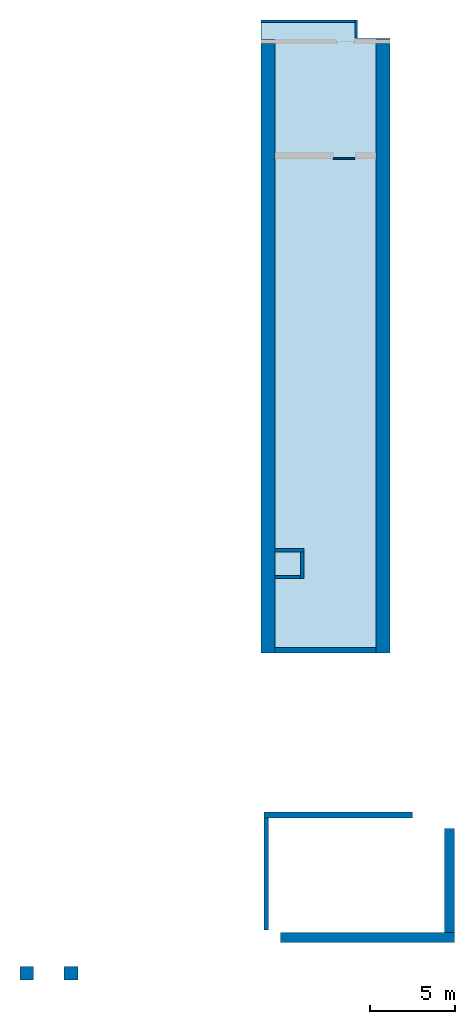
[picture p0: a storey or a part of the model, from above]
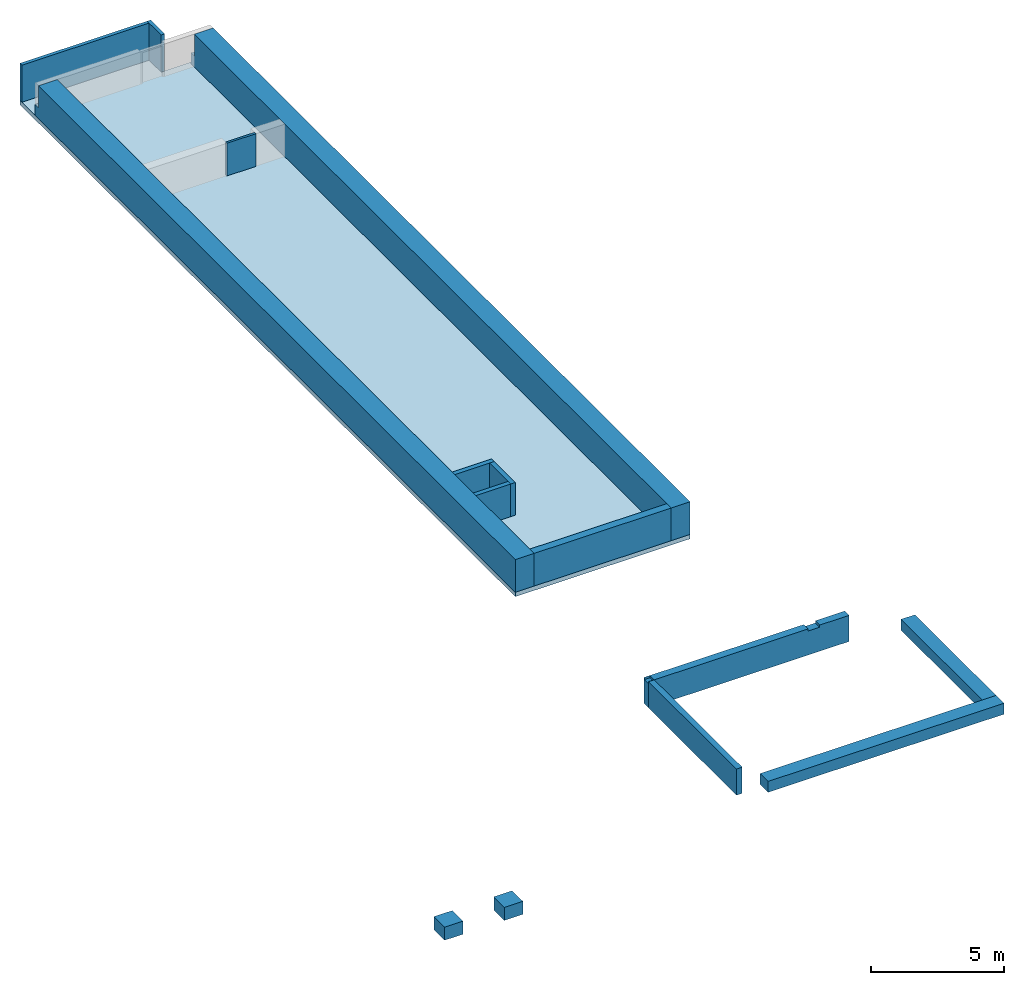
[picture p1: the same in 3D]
Properties of the parts of a building model (IFC2X3), part 1 of 7

# File
Description: ViewDefinition [, SurfaceGeometryAddOnView], Option [Elements to export: Visible elements (on all stories)], Option [Partial Structure Display: Entire Model], Option [IFC Domain: All], Option [Structural Function: All Elements], Option [Convert Grid elements: On], Option [Convert IFC Annotations and Archicad 2D elements: Off], Option [Convert 2D symbols of Doors and Windows: Off], Option [Export geometries that Participates in Collision Detection only: On], Option [Split complex elements: Off], Option [Material Preservation: Explode all], Option [IFC Model position: Survey Point and Project Origin], Option [Curtain Wall export mode: Container Element], Option [Railing export mode: Container Element], Option [Stair export mode: Container Element], Option [Properties To Export: Current Scheme properties only], Option [Space containment: Off], Option [Geometry to type objects: On], Option [Element Properties: Visible Only], Option [Building Material Properties: On], Option [Element Parameters: Off], Option [Component Parameters: Off], Option [IFC Base Quantities: Off], Option [Door Window Parameters: On], Option [IFC Space boundaries: Off], Option [Archicad Zone Categories as IFC Space classification data: Off], Option [Element Classifications: Off]
File name: C:\Users\kamee\OneDrive - Joop Petit Beheer BV\Bureaublad\Plot\IFC Bouwkiundig model.ifc
Time: 2026-01-28T16:22:37
Author: Architect
Organization: Naam bureau
Written by: DDS_IFC v3.0
Made in: Graphisoft - Archicad - 28.3.0
Authorization: The authorising person

# IfcProject, 108 Het Martin Buber
Description: Locatie Atrium gebouw N&V

# IfcSite, Site
RefLatitude: 51, 27, 0, 0; RefLongitude: 5, 29, 0, 0; RefElevation: 0 mm

# IfcBuildingStorey (11)
In: Naam gebouw
Name | Elevation (mm)
1e verdieping N | 4150
Begane grond N | 0
Fundering N | -1700
2e verdieping N | 7650
2e verdieping V | 8690
3e verdieping/dak N | 11150
3e verdieping V | 11460
4e verdieping V | 14230
5e verdieping V | 17000
6e verdieping V | 19770
7e verdieping-dak V | 22540

# IfcBeam: ALG - CONSTRUCTIEF KOLOM 150 x 250 (3)
In: 1e verdieping N
Type - PredefinedType: BEAM
Material: ALG - CONSTRUCTIEF KOLOM
Pset_BeamCommon - Slope: 0 deg; FireRating: n.v.t.; IsExternal: no; LoadBearing: yes; Reference: ALG - CONSTRUCTIEF KOLOM 150 x 250
Material Properties - ALG - CONSTRUCTIEF KOLOM, ThermalConductivity: 2.3; ALG - CONSTRUCTIEF KOLOM, SpecificHeatCapacity: 1000 J/kg/K; ALG - CONSTRUCTIEF KOLOM, MassDensity: 2300 kg/m3; ALG - CONSTRUCTIEF KOLOM, Embodied Energy: 1.92 (MJ/kg); ALG - CONSTRUCTIEF KOLOM, Embodied Carbon: 0.198 (kgCO₂/kg); ALG - CONSTRUCTIEF KOLOM, Name: ALG - CONSTRUCTIEF KOLOM; ALG - CONSTRUCTIEF KOLOM, Participates in Collision Detection: yes
CPset_Phasing - Renovation Phase: Bestaand
Name | Span (mm)
_Balk-x | 9595
_Balk-x | 28130
_Balk-x | 6885

# IfcBeam: ALG - CONSTRUCTIEF KOLOM 200 x 250, _Balk-x
In: 2e verdieping N
Type - PredefinedType: BEAM
Material: ALG - CONSTRUCTIEF KOLOM
Pset_BeamCommon - Span: 5320 mm; Slope: 0 deg; FireRating: n.v.t.; IsExternal: no; LoadBearing: yes; Reference: ALG - CONSTRUCTIEF KOLOM 200 x 250
CPset_Phasing - Renovation Phase: Bestaand
Material Properties - ALG - CONSTRUCTIEF KOLOM, ThermalConductivity: 2.3; ALG - CONSTRUCTIEF KOLOM, SpecificHeatCapacity: 1000 J/kg/K; ALG - CONSTRUCTIEF KOLOM, MassDensity: 2300 kg/m3; ALG - CONSTRUCTIEF KOLOM, Embodied Energy: 1.92 (MJ/kg); ALG - CONSTRUCTIEF KOLOM, Embodied Carbon: 0.198 (kgCO₂/kg); ALG - CONSTRUCTIEF KOLOM, Name: ALG - CONSTRUCTIEF KOLOM; ALG - CONSTRUCTIEF KOLOM, Participates in Collision Detection: yes

# IfcBeam: ALG - CONSTRUCTIEF KOLOM 250 x 200, _Balk-x
In: 2e verdieping N
Type - PredefinedType: BEAM
Material: ALG - CONSTRUCTIEF KOLOM
Pset_BeamCommon - Span: 5685 mm; Slope: 0 deg; FireRating: n.v.t.; IsExternal: no; LoadBearing: yes; Reference: ALG - CONSTRUCTIEF KOLOM 250 x 200
CPset_Phasing - Renovation Phase: Bestaand
Material Properties - ALG - CONSTRUCTIEF KOLOM, ThermalConductivity: 2.3; ALG - CONSTRUCTIEF KOLOM, SpecificHeatCapacity: 1000 J/kg/K; ALG - CONSTRUCTIEF KOLOM, MassDensity: 2300 kg/m3; ALG - CONSTRUCTIEF KOLOM, Embodied Energy: 1.92 (MJ/kg); ALG - CONSTRUCTIEF KOLOM, Embodied Carbon: 0.198 (kgCO₂/kg); ALG - CONSTRUCTIEF KOLOM, Name: ALG - CONSTRUCTIEF KOLOM; ALG - CONSTRUCTIEF KOLOM, Participates in Collision Detection: yes

# IfcBeam: ALG - CONSTRUCTIEF KOLOM 250 x 250 (8)
Type - PredefinedType: BEAM
Material: ALG - CONSTRUCTIEF KOLOM
Pset_BeamCommon - Slope: 0 deg; FireRating: n.v.t.; IsExternal: no; LoadBearing: yes; Reference: ALG - CONSTRUCTIEF KOLOM 250 x 250
CPset_Phasing - Renovation Phase: Bestaand
Material Properties - ALG - CONSTRUCTIEF KOLOM, ThermalConductivity: 2.3; ALG - CONSTRUCTIEF KOLOM, SpecificHeatCapacity: 1000 J/kg/K; ALG - CONSTRUCTIEF KOLOM, MassDensity: 2300 kg/m3; ALG - CONSTRUCTIEF KOLOM, Embodied Energy: 1.92 (MJ/kg); ALG - CONSTRUCTIEF KOLOM, Embodied Carbon: 0.198 (kgCO₂/kg); ALG - CONSTRUCTIEF KOLOM, Name: ALG - CONSTRUCTIEF KOLOM; ALG - CONSTRUCTIEF KOLOM, Participates in Collision Detection: yes
Name | In | Span (mm)
_Balk-x | 1e verdieping N | 5130
_Balk-x | 1e verdieping N | 3930
2 x _Balk-x | 1e verdieping N | 2710
_Balk-x | 1e verdieping N | 5275
_Balk-x | 1e verdieping N | 2705
_Balk-x | 1e verdieping N | 2650
_Balk-x | 2e verdieping N | 2705

# IfcBeam: ALG - CONSTRUCTIEF KOLOM 250 x 290, _Balk-x
In: 2e verdieping N
Type - PredefinedType: BEAM
Material: ALG - CONSTRUCTIEF KOLOM
Pset_BeamCommon - Span: 3930 mm; Slope: 0 deg; FireRating: n.v.t.; IsExternal: no; LoadBearing: yes; Reference: ALG - CONSTRUCTIEF KOLOM 250 x 290
CPset_Phasing - Renovation Phase: Bestaand
Material Properties - ALG - CONSTRUCTIEF KOLOM, ThermalConductivity: 2.3; ALG - CONSTRUCTIEF KOLOM, SpecificHeatCapacity: 1000 J/kg/K; ALG - CONSTRUCTIEF KOLOM, MassDensity: 2300 kg/m3; ALG - CONSTRUCTIEF KOLOM, Embodied Energy: 1.92 (MJ/kg); ALG - CONSTRUCTIEF KOLOM, Embodied Carbon: 0.198 (kgCO₂/kg); ALG - CONSTRUCTIEF KOLOM, Name: ALG - CONSTRUCTIEF KOLOM; ALG - CONSTRUCTIEF KOLOM, Participates in Collision Detection: yes

# IfcBeam: ALG - CONSTRUCTIEF KOLOM 250 x 300 (2)
In: Begane grond N
Type - PredefinedType: BEAM
Material: ALG - CONSTRUCTIEF KOLOM
Pset_BeamCommon - Span: 3873.9 mm; Slope: 0 deg; FireRating: n.v.t.; IsExternal: no; LoadBearing: yes; Reference: ALG - CONSTRUCTIEF KOLOM 250 x 300
Material Properties - ALG - CONSTRUCTIEF KOLOM, ThermalConductivity: 2.3; ALG - CONSTRUCTIEF KOLOM, SpecificHeatCapacity: 1000 J/kg/K; ALG - CONSTRUCTIEF KOLOM, MassDensity: 2300 kg/m3; ALG - CONSTRUCTIEF KOLOM, Embodied Energy: 1.92 (MJ/kg); ALG - CONSTRUCTIEF KOLOM, Embodied Carbon: 0.198 (kgCO₂/kg); ALG - CONSTRUCTIEF KOLOM, Name: ALG - CONSTRUCTIEF KOLOM; ALG - CONSTRUCTIEF KOLOM, Participates in Collision Detection: yes
CPset_Phasing - Renovation Phase: Bestaand

# IfcBeam: ALG - CONSTRUCTIEF KOLOM 250 x 350 (7)
In: Begane grond N
Type - PredefinedType: BEAM
Material: ALG - CONSTRUCTIEF KOLOM
CPset_Phasing - Renovation Phase: Bestaand
Material Properties - ALG - CONSTRUCTIEF KOLOM, ThermalConductivity: 2.3; ALG - CONSTRUCTIEF KOLOM, SpecificHeatCapacity: 1000 J/kg/K; ALG - CONSTRUCTIEF KOLOM, MassDensity: 2300 kg/m3; ALG - CONSTRUCTIEF KOLOM, Embodied Energy: 1.92 (MJ/kg); ALG - CONSTRUCTIEF KOLOM, Embodied Carbon: 0.198 (kgCO₂/kg); ALG - CONSTRUCTIEF KOLOM, Name: ALG - CONSTRUCTIEF KOLOM; ALG - CONSTRUCTIEF KOLOM, Participates in Collision Detection: yes
Pset_BeamCommon - Slope: 0 deg; FireRating: n.v.t.; IsExternal: no; LoadBearing: yes; Reference: ALG - CONSTRUCTIEF KOLOM 250 x 350
Name | Span (mm)
_Balk-x | 8932.17
2 x _Balk-x | 5
2 x _Balk-x | 2705
_Balk-x | 3820
_Balk-x | 2650

# IfcBeam: ALG - CONSTRUCTIEF KOLOM 355 x 250, _Balk-x
In: 1e verdieping N
Type - PredefinedType: BEAM
Material: ALG - CONSTRUCTIEF KOLOM
CPset_Phasing - Renovation Phase: Bestaand
Material Properties - ALG - CONSTRUCTIEF KOLOM, ThermalConductivity: 2.3; ALG - CONSTRUCTIEF KOLOM, SpecificHeatCapacity: 1000 J/kg/K; ALG - CONSTRUCTIEF KOLOM, MassDensity: 2300 kg/m3; ALG - CONSTRUCTIEF KOLOM, Embodied Energy: 1.92 (MJ/kg); ALG - CONSTRUCTIEF KOLOM, Embodied Carbon: 0.198 (kgCO₂/kg); ALG - CONSTRUCTIEF KOLOM, Name: ALG - CONSTRUCTIEF KOLOM; ALG - CONSTRUCTIEF KOLOM, Participates in Collision Detection: yes
Pset_BeamCommon - Span: 6283 mm; Slope: 0 deg; FireRating: n.v.t.; IsExternal: no; LoadBearing: yes; Reference: ALG - CONSTRUCTIEF KOLOM 355 x 250

# IfcBeam: ALG - CONSTRUCTIEF KOLOM 400 x 250 (5)
Type - PredefinedType: BEAM
Material: ALG - CONSTRUCTIEF KOLOM
Pset_BeamCommon - Slope: 0 deg; FireRating: n.v.t.; IsExternal: no; LoadBearing: yes; Reference: ALG - CONSTRUCTIEF KOLOM 400 x 250
CPset_Phasing - Renovation Phase: Bestaand
Material Properties - ALG - CONSTRUCTIEF KOLOM, ThermalConductivity: 2.3; ALG - CONSTRUCTIEF KOLOM, SpecificHeatCapacity: 1000 J/kg/K; ALG - CONSTRUCTIEF KOLOM, MassDensity: 2300 kg/m3; ALG - CONSTRUCTIEF KOLOM, Embodied Energy: 1.92 (MJ/kg); ALG - CONSTRUCTIEF KOLOM, Embodied Carbon: 0.198 (kgCO₂/kg); ALG - CONSTRUCTIEF KOLOM, Name: ALG - CONSTRUCTIEF KOLOM; ALG - CONSTRUCTIEF KOLOM, Participates in Collision Detection: yes
Name | In | Span (mm)
_Balk-x | Begane grond N | 6901.5
2 x _Balk-x | Begane grond N | 9670
_Balk-x | 1e verdieping N | 31151.2
_Balk-x | 1e verdieping N | 9700

# IfcBeam: ALG - CONSTRUCTIEF KOLOM 400 x 470 (8)
In: Begane grond N
Type - PredefinedType: BEAM
Material: ALG - CONSTRUCTIEF KOLOM
CPset_Phasing - Renovation Phase: Bestaand
Pset_BeamCommon - Slope: 0 deg; FireRating: n.v.t.; IsExternal: no; LoadBearing: yes; Reference: ALG - CONSTRUCTIEF KOLOM 400 x 470
Material Properties - ALG - CONSTRUCTIEF KOLOM, ThermalConductivity: 2.3; ALG - CONSTRUCTIEF KOLOM, SpecificHeatCapacity: 1000 J/kg/K; ALG - CONSTRUCTIEF KOLOM, MassDensity: 2300 kg/m3; ALG - CONSTRUCTIEF KOLOM, Embodied Energy: 1.92 (MJ/kg); ALG - CONSTRUCTIEF KOLOM, Embodied Carbon: 0.198 (kgCO₂/kg); ALG - CONSTRUCTIEF KOLOM, Name: ALG - CONSTRUCTIEF KOLOM; ALG - CONSTRUCTIEF KOLOM, Participates in Collision Detection: yes
Name | Span (mm)
6 x _Balk-x | 9670
_Balk-x | 40782.5
_Balk-x | 27880

# IfcBeam: ALG - CONSTRUCTIEF KOLOM 400 x 890 (9)
In: 1e verdieping N
Type - PredefinedType: BEAM
Material: ALG - CONSTRUCTIEF KOLOM
Pset_BeamCommon - Slope: 0 deg; FireRating: n.v.t.; IsExternal: no; LoadBearing: yes; Reference: ALG - CONSTRUCTIEF KOLOM 400 x 890
Material Properties - ALG - CONSTRUCTIEF KOLOM, ThermalConductivity: 2.3; ALG - CONSTRUCTIEF KOLOM, SpecificHeatCapacity: 1000 J/kg/K; ALG - CONSTRUCTIEF KOLOM, MassDensity: 2300 kg/m3; ALG - CONSTRUCTIEF KOLOM, Embodied Energy: 1.92 (MJ/kg); ALG - CONSTRUCTIEF KOLOM, Embodied Carbon: 0.198 (kgCO₂/kg); ALG - CONSTRUCTIEF KOLOM, Name: ALG - CONSTRUCTIEF KOLOM; ALG - CONSTRUCTIEF KOLOM, Participates in Collision Detection: yes
CPset_Phasing - Renovation Phase: Bestaand
Name | Span (mm)
7 x _Balk-x | 9670
2 x _Balk-x | 40427.5

# IfcBeam: L150X100X10 100 x 150 (3)
In: Begane grond N
Type - PredefinedType: BEAM
Material: Steen - Baksteen
Pset_BeamCommon - Slope: 0 deg; FireRating: n.v.t.; IsExternal: no; LoadBearing: yes; Reference: L150X100X10 100 x 150
CPset_Phasing - Renovation Phase: Nieuw
Material Properties - Steen - Baksteen, ThermalConductivity: 0.9; Steen - Baksteen, SpecificHeatCapacity: 840 J/kg/K; Steen - Baksteen, MassDensity: 1600 kg/m3; Steen - Baksteen, Embodied Energy: 3 (MJ/kg); Steen - Baksteen, Embodied Carbon: 0.23 (kgCO₂/kg); Steen - Baksteen, Name: Steen - Baksteen; Steen - Baksteen, Participates in Collision Detection: yes
Name | Span (mm)
2 x _Balk-x | 1910
_Balk-x | 3695

# IfcBeam: Lekdorpel 107 x 49 (26)
Type - PredefinedType: BEAM
Material: Metaal - Aluminium
Pset_BeamCommon - Slope: 0 deg; FireRating: n.v.t.; IsExternal: no; LoadBearing: yes; Reference: Lekdorpel 107 x 49
Material Properties - Metaal - Aluminium, ThermalConductivity: 160; Metaal - Aluminium, SpecificHeatCapacity: 880 J/kg/K; Metaal - Aluminium, MassDensity: 2800 kg/m3; Metaal - Aluminium, Embodied Energy: 155 (MJ/kg); Metaal - Aluminium, Embodied Carbon: 9.16 (kgCO₂/kg); Metaal - Aluminium, Name: Metaal - Aluminium; Metaal - Aluminium, Participates in Collision Detection: yes
Name | In | Span (mm) | Renovation Phase
2 x _Balk-x | Begane grond N | 4900 | Bestaand
_Balk-x | 1e verdieping N | 14675 | Nieuw
_Balk-x | 1e verdieping N | 18275 | Nieuw
_Balk-x | 1e verdieping N | 4460 | Bestaand
_Balk-x | 1e verdieping N | 12600 | Nieuw
_Balk-x | 2e verdieping N | 12600 | Nieuw
_Balk-x | 2e verdieping N | 3906.5 | Nieuw
_Balk-x | 2e verdieping N | 18275 | Nieuw
_Balk-x | 2e verdieping N | 16475 | Nieuw
_Balk-x | 2e verdieping N | 25200 | Nieuw
_Balk-x | 2e verdieping N | 7156.5 | Nieuw
_Balk-x | 2e verdieping N | 12738.7 | Nieuw
_Balk-x | 2e verdieping V | 5330 | Bestaand
_Balk-x | 2e verdieping V | 22661 | Bestaand
_Balk-x | 2e verdieping V | 15990 | Bestaand
_Balk-x | 2e verdieping V | 5080 | Bestaand
_Balk-x | 3e verdieping V | 5330 | Bestaand
_Balk-x | 3e verdieping V | 26650 | Bestaand
_Balk-x | 3e verdieping V | 22661 | Bestaand
_Balk-x | 4e verdieping V | 26650 | Bestaand
_Balk-x | 4e verdieping V | 5330 | Bestaand
_Balk-x | 4e verdieping V | 22661 | Bestaand
_Balk-x | 5e verdieping V | 22661 | Bestaand
_Balk-x | 5e verdieping V | 26650 | Bestaand
_Balk-x | 5e verdieping V | 5330 | Bestaand

# IfcBeam: Metaal - Staal C 10 x 100 (4)
In: 1e verdieping N
Type - PredefinedType: BEAM
Material: Metaal - Staal C
Pset_BeamCommon - FireRating: n.v.t.; IsExternal: no; LoadBearing: yes; Reference: Metaal - Staal C 10 x 100
CPset_Phasing - Renovation Phase: Nieuw
Material Properties - Metaal - Staal C, ThermalConductivity: 52; Metaal - Staal C, SpecificHeatCapacity: 530 J/kg/K; Metaal - Staal C, MassDensity: 7950 kg/m3; Metaal - Staal C, Embodied Energy: 25 (MJ/kg); Metaal - Staal C, Embodied Carbon: 1.91 (kgCO₂/kg); Metaal - Staal C, Name: Metaal - Staal C; Metaal - Staal C, Participates in Collision Detection: yes
Name | Span (mm) | Slope (deg)
2 x _Balk-x | 6507.14 | 37.1047
2 x _Balk-x | 6000.45 | 44.156

# IfcBeam: NLRS_28_SF_LIB_balk HE_generiek_ISR:balk HE_gen_HEB300 (33)
Type - PredefinedType: BEAM
Material: staal geanodiseerd RAL 7024
Pset_BeamCommon - Slope: 0 deg; Reference: balk HE_gen_HEB300; IsExternal: no; LoadBearing: yes
CPset_Phasing - Renovation Phase: Nieuw
Material Properties - staal geanodiseerd RAL 7024, ThermalConductivity: 2.3; staal geanodiseerd RAL 7024, SpecificHeatCapacity: 1000 J/kg/K; staal geanodiseerd RAL 7024, MassDensity: 2300 kg/m3; staal geanodiseerd RAL 7024, Embodied Energy: 1.92 (MJ/kg); staal geanodiseerd RAL 7024, Embodied Carbon: 0.198 (kgCO₂/kg); staal geanodiseerd RAL 7024, Name: staal geanodiseerd RAL 7024; staal geanodiseerd RAL 7024, Participates in Collision Detection: yes
Name (NLRS_28_SF_LIB_balk HE_generiek_ISR:balk HE_gen_HEB300:...) | In | Pset_ReinforcementBarPitchOfBeam, Reference | Pset_ReinforcementBarPitchOfBeam, sets with these values | Span (mm) | Group
3106919 | 2e verdieping N | balk HE_gen_HEB300 | 2 | 2833.63
3106583 | 2e verdieping N | balk HE_gen_HEB300 | 2 | 2833.63
3148283 | 2e verdieping N | balk HE_gen_HEB300 | 2 | 1544 | Model Group:luifel penthouse:3148164
3148337 | 2e verdieping N | balk HE_gen_HEB300 | 2 | 1544 | Model Group:luifel penthouse:3148164
3148282 | 2e verdieping N | balk HE_gen_HEB300 | 2 | 7380 | Model Group:luifel penthouse:3148164
2972296 | 2e verdieping V | balk HE_gen_HEB300 | 2 | 2830 | Model Group:BUITENRUIMTE helft:2972320
2973538 | 2e verdieping V | balk HE_gen_HEB300 | 2 | 2830
2972295 | 2e verdieping V | balk HE_gen_HEB300 | 2 | 7995 | Model Group:BUITENRUIMTE helft:2972320
2973612 | 2e verdieping V | balk HE_gen_HEB300 | 2 | 2830
2973856 | 2e verdieping V | balk HE_gen_HEB300 | 2 | 5240.03
3097593 | 2e verdieping V | balk HE_gen_HEB300 | 2 | 2833.63
3097884 | 2e verdieping V | balk HE_gen_HEB300 | 2 | 2833.63
3098411 | 2e verdieping V | balk HE_gen_HEB300 | 2 | 5330
2973537 | 2e verdieping V | balk HE_gen_HEB300 | 2 | 516.12
2972322 | 2e verdieping V | balk HE_gen_HEB300 | 2 | 7995 | Model Group:BUITENRUIMTE helft:2972347
2972323 | 2e verdieping V | balk HE_gen_HEB300 | 2 | 2830 | Model Group:BUITENRUIMTE helft:2972347
3108933 | 2e verdieping V |  |  | 3727.38 | Pset_QuantityTakeOff - Reference: balk HE_gen_HEB300; sets with these values: 2
2971994 | 3e verdieping/dak N |  |  | 7995 | Model Group:BUITENRUIMTE helft:2972019 | Pset_QuantityTakeOff - Reference: balk HE_gen_HEB300; sets with these values: 2
2971995 | 3e verdieping/dak N | balk HE_gen_HEB300 | 2 | 2830 | Model Group:BUITENRUIMTE helft:2972019
2972021 | 3e verdieping/dak N | balk HE_gen_HEB300 | 2 | 7995 | Model Group:BUITENRUIMTE helft:2972046
2972022 | 3e verdieping/dak N | balk HE_gen_HEB300 | 2 | 2830 | Model Group:BUITENRUIMTE helft:2972046
2972048 | 3e verdieping V | balk HE_gen_HEB300 | 2 | 7995 | Model Group:BUITENRUIMTE helft:2972073
2972075 | 3e verdieping V | balk HE_gen_HEB300 | 2 | 7995 | Model Group:BUITENRUIMTE helft:2972100
2972049 | 3e verdieping V |  |  | 2830 | Model Group:BUITENRUIMTE helft:2972073 | Pset_QuantityTakeOff - Reference: balk HE_gen_HEB300; sets with these values: 2
2972076 | 3e verdieping V | balk HE_gen_HEB300 | 2 | 2830 | Model Group:BUITENRUIMTE helft:2972100
2971941 | 4e verdieping V | balk HE_gen_HEB300 | 2 | 2830 | Model Group:BUITENRUIMTE helft:2971965
2971968 | 4e verdieping V | balk HE_gen_HEB300 | 2 | 2830 | Model Group:BUITENRUIMTE helft:2971992
2971940 | 4e verdieping V |  |  | 7995 | Model Group:BUITENRUIMTE helft:2971965 | Pset_QuantityTakeOff - Reference: balk HE_gen_HEB300; sets with these values: 2
2971967 | 4e verdieping V | balk HE_gen_HEB300 | 2 | 7995 | Model Group:BUITENRUIMTE helft:2971992
2972590 | 5e verdieping V | balk HE_gen_HEB300 | 2 | 2550 | Model Group:BUITENRUIMTE helft dak:2972614
2972589 | 5e verdieping V | balk HE_gen_HEB300 | 2 | 7995 | Model Group:BUITENRUIMTE helft dak:2972614
2972412 | 5e verdieping V | balk HE_gen_HEB300 | 2 | 7995 | Model Group:BUITENRUIMTE helft dak:2972437
2972413 | 5e verdieping V | balk HE_gen_HEB300 | 2 | 2550 | Model Group:BUITENRUIMTE helft dak:2972437

# IfcBeam: NLRS_28_SF_staal - balk - UNP:UNP300 (20)
Type - PredefinedType: BEAM
Pset_BeamCommon - Slope: 0 deg; Reference: UNP300; IsExternal: no; LoadBearing: yes
CPset_Phasing - Renovation Phase: Nieuw
Name (NLRS_28_SF_staal - balk - UNP:UNP300:...) | In | Material | Span (mm) | staal, ThermalConductivity | staal, SpecificHeatCapacity (J/kg/K) | staal, MassDensity (kg/m3) | staal, Embodied Energy | staal, Embodied Carbon | staal, Name | staal, Participates in Collision Detection | Group | Pset_ReinforcementBarPitchOfBeam, Reference | Pset_ReinforcementBarPitchOfBeam, sets with these values
3149742 | 1e verdieping N | staal | 2200 | 2.3 | 1000 | 2300 | 1.92 (MJ/kg) | 0.198 (kgCO₂/kg) | staal | yes | Model Group:KOZ-03:3140556 | Pset_QuantityTakeOff - Reference: UNP300; sets with these values: 2
2725791 | 1e verdieping N | staal | 11220 | 2.3 | 1000 | 2300 | 1.92 (MJ/kg) | 0.198 (kgCO₂/kg) | staal | yes |  | UNP300 | 2
2727269 | 1e verdieping N | staal | 6410 | 2.3 | 1000 | 2300 | 1.92 (MJ/kg) | 0.198 (kgCO₂/kg) | staal | yes |  | UNP300 | 2
2725625 | 2e verdieping N | staal | 5960 | 2.3 | 1000 | 2300 | 1.92 (MJ/kg) | 0.198 (kgCO₂/kg) | staal | yes |  | UNP300 | 2
3149748 | 2e verdieping N | staal | 2200 | 2.3 | 1000 | 2300 | 1.92 (MJ/kg) | 0.198 (kgCO₂/kg) | staal | yes | Model Group:KOZ-03:3142360 | UNP300 | 2
3149730 | 2e verdieping V | staal geanodiseerd RAL 7024 | 2200 |  |  |  |  |  |  |  | Model Group:KOZ-03:3087227 | UNP300 | 2 | Material Properties - staal geanodiseerd RAL 7024, ThermalConductivity: 2.3; staal geanodiseerd RAL 7024, SpecificHeatCapacity: 1000 J/kg/K; staal geanodiseerd RAL 7024, MassDensity: 2300 kg/m3; staal geanodiseerd RAL 7024, Embodied Energy: 1.92 (MJ/kg); staal geanodiseerd RAL 7024, Embodied Carbon: 0.198 (kgCO₂/kg); staal geanodiseerd RAL 7024, Name: staal geanodiseerd RAL 7024; staal geanodiseerd RAL 7024, Participates in Collision Detection: yes
3149745 | 2e verdieping V | staal | 2200 | 2.3 | 1000 | 2300 | 1.92 (MJ/kg) | 0.198 (kgCO₂/kg) | staal | yes | Model Group:KOZ-03:3140557 | UNP300 | 2
2725736 | 2e verdieping V | staal | 5960 | 2.3 | 1000 | 2300 | 1.92 (MJ/kg) | 0.198 (kgCO₂/kg) | staal | yes |  | UNP300 | 2
3149715 | 3e verdieping/dak N | staal geanodiseerd RAL 7024 | 2200 |  |  |  |  |  |  |  | Model Group:KOZ-03:2767540 | Pset_QuantityTakeOff - Reference: UNP300; sets with these values: 2; Material Properties - staal geanodiseerd RAL 7024, ThermalConductivity: 2.3; staal geanodiseerd RAL 7024, SpecificHeatCapacity: 1000 J/kg/K; staal geanodiseerd RAL 7024, MassDensity: 2300 kg/m3; staal geanodiseerd RAL 7024, Embodied Energy: 1.92 (MJ/kg); staal geanodiseerd RAL 7024, Embodied Carbon: 0.198 (kgCO₂/kg); staal geanodiseerd RAL 7024, Name: staal geanodiseerd RAL 7024; staal geanodiseerd RAL 7024, Participates in Collision Detection: yes
2725577 | 3e verdieping/dak N | staal | 5960 | 2.3 | 1000 | 2300 | 1.92 (MJ/kg) | 0.198 (kgCO₂/kg) | staal | yes | Model Group:V vluchttrappenhuis 2:2013401 | UNP300 | 2
3149733 | 3e verdieping/dak N | staal | 2200 | 2.3 | 1000 | 2300 | 1.92 (MJ/kg) | 0.198 (kgCO₂/kg) | staal | yes | Model Group:KOZ-03:3140528 | Pset_QuantityTakeOff - Reference: UNP300; sets with these values: 2
2725581 | 3e verdieping V | staal | 5960 | 2.3 | 1000 | 2300 | 1.92 (MJ/kg) | 0.198 (kgCO₂/kg) | staal | yes | Model Group:V vluchttrappenhuis 2:2013471 | UNP300 | 2
3149721 | 3e verdieping V | staal geanodiseerd RAL 7024 | 2200 |  |  |  |  |  |  |  | Model Group:KOZ-03:2767569 | Pset_QuantityTakeOff - Reference: UNP300; sets with these values: 2; Material Properties - staal geanodiseerd RAL 7024, ThermalConductivity: 2.3; staal geanodiseerd RAL 7024, SpecificHeatCapacity: 1000 J/kg/K; staal geanodiseerd RAL 7024, MassDensity: 2300 kg/m3; staal geanodiseerd RAL 7024, Embodied Energy: 1.92 (MJ/kg); staal geanodiseerd RAL 7024, Embodied Carbon: 0.198 (kgCO₂/kg); staal geanodiseerd RAL 7024, Name: staal geanodiseerd RAL 7024; staal geanodiseerd RAL 7024, Participates in Collision Detection: yes
3149736 | 3e verdieping V | staal | 2200 | 2.3 | 1000 | 2300 | 1.92 (MJ/kg) | 0.198 (kgCO₂/kg) | staal | yes | Model Group:KOZ-03:3140535 | Pset_QuantityTakeOff - Reference: UNP300; sets with these values: 2
3149739 | 4e verdieping V | staal | 2200 | 2.3 | 1000 | 2300 | 1.92 (MJ/kg) | 0.198 (kgCO₂/kg) | staal | yes | Model Group:KOZ-03:3140542 | UNP300 | 2
3149724 | 4e verdieping V | staal geanodiseerd RAL 7024 | 2200 |  |  |  |  |  |  |  | Model Group:KOZ-03:2767587 | Pset_QuantityTakeOff - Reference: UNP300; sets with these values: 2; Material Properties - staal geanodiseerd RAL 7024, ThermalConductivity: 2.3; staal geanodiseerd RAL 7024, SpecificHeatCapacity: 1000 J/kg/K; staal geanodiseerd RAL 7024, MassDensity: 2300 kg/m3; staal geanodiseerd RAL 7024, Embodied Energy: 1.92 (MJ/kg); staal geanodiseerd RAL 7024, Embodied Carbon: 0.198 (kgCO₂/kg); staal geanodiseerd RAL 7024, Name: staal geanodiseerd RAL 7024; staal geanodiseerd RAL 7024, Participates in Collision Detection: yes
2725293 | 4e verdieping V | staal | 5960 | 2.3 | 1000 | 2300 | 1.92 (MJ/kg) | 0.198 (kgCO₂/kg) | staal | yes | Model Group:V vluchttrappenhuis 2:2013517 | UNP300 | 2
3149419 | 5e verdieping V | staal | 2200 | 2.3 | 1000 | 2300 | 1.92 (MJ/kg) | 0.198 (kgCO₂/kg) | staal | yes | Model Group:KOZ-03:3140549 | UNP300 | 2
3149727 | 5e verdieping V | staal geanodiseerd RAL 7024 | 2200 |  |  |  |  |  |  |  | Model Group:KOZ-03:2767621 | UNP300 | 2 | Material Properties - staal geanodiseerd RAL 7024, ThermalConductivity: 2.3; staal geanodiseerd RAL 7024, SpecificHeatCapacity: 1000 J/kg/K; staal geanodiseerd RAL 7024, MassDensity: 2300 kg/m3; staal geanodiseerd RAL 7024, Embodied Energy: 1.92 (MJ/kg); staal geanodiseerd RAL 7024, Embodied Carbon: 0.198 (kgCO₂/kg); staal geanodiseerd RAL 7024, Name: staal geanodiseerd RAL 7024; staal geanodiseerd RAL 7024, Participates in Collision Detection: yes
3085542 | 5e verdieping V | staal | 5960 | 2.3 | 1000 | 2300 | 1.92 (MJ/kg) | 0.198 (kgCO₂/kg) | staal | yes | Model Group:V vluchttrappenhuis 2:2013112 | Pset_QuantityTakeOff - Reference: UNP300; sets with these values: 2

# IfcBeam: Onderdorpel 155 x 80 (8)
In: Begane grond N
Type - PredefinedType: BEAM
Material: Beton gewapend prefab
Pset_BeamCommon - Span: 275 mm; Slope: 0 deg; FireRating: n.v.t.; IsExternal: no; LoadBearing: yes; Reference: Onderdorpel 155 x 80
CPset_Phasing - Renovation Phase: Nieuw
Material Properties - Beton gewapend prefab, ThermalConductivity: 2.5; Beton gewapend prefab, SpecificHeatCapacity: 1000 J/kg/K; Beton gewapend prefab, MassDensity: 2400 kg/m3; Beton gewapend prefab, Embodied Energy: 2.33 (MJ/kg); Beton gewapend prefab, Embodied Carbon: 0.242 (kgCO₂/kg); Beton gewapend prefab, Name: Beton gewapend prefab; Beton gewapend prefab, Participates in Collision Detection: yes

# IfcBuildingElementPart (1450)
Name | In | Material | Renovation Phase
101 x Isolatie - Steenwol LSW | Begane grond N | Isolatie - Steenwol LSW | Nieuw | Material Properties - Isolatie - Steenwol LSW, ThermalConductivity: 0.039; Isolatie - Steenwol LSW, SpecificHeatCapacity: 840 J/kg/K; Isolatie - Steenwol LSW, MassDensity: 55 kg/m3; Isolatie - Steenwol LSW, Embodied Energy: 16.8 (MJ/kg); Isolatie - Steenwol LSW, Embodied Carbon: 1.05 (kgCO₂/kg); Isolatie - Steenwol LSW, Name: Isolatie - Steenwol LSW; Isolatie - Steenwol LSW, Participates in Collision Detection: yes
207 x Gipsplaat | Begane grond N | Gipsplaat | Nieuw | Material Properties - Gipsplaat, ThermalConductivity: 0.23; Gipsplaat, SpecificHeatCapacity: 840 J/kg/K; Gipsplaat, MassDensity: 800 kg/m3; Gipsplaat, Embodied Energy: 6.75 (MJ/kg); Gipsplaat, Embodied Carbon: 0.38 (kgCO₂/kg); Gipsplaat, Name: Gipsplaat; Gipsplaat, Participates in Collision Detection: yes
4 x Hout - Multiplex | Begane grond N | Hout - Multiplex | Nieuw | Material Properties - Hout - Multiplex, ThermalConductivity: 0.17; Hout - Multiplex, SpecificHeatCapacity: 1600 J/kg/K; Hout - Multiplex, MassDensity: 700 kg/m3; Hout - Multiplex, Embodied Energy: 15 (MJ/kg); Hout - Multiplex, Embodied Carbon: 0.77 (kgCO₂/kg); Hout - Multiplex, Name: Hout - Multiplex; Hout - Multiplex, Participates in Collision Detection: yes
10 x Isolatie - Kunststof hard | Begane grond N | Isolatie - Kunststof hard | Nieuw | Material Properties - Isolatie - Kunststof hard, ThermalConductivity: 0.029; Isolatie - Kunststof hard, SpecificHeatCapacity: 1470 J/kg/K; Isolatie - Kunststof hard, MassDensity: 100 kg/m3; Isolatie - Kunststof hard, Embodied Energy: 101.5 (MJ/kg); Isolatie - Kunststof hard, Embodied Carbon: 3.48 (kgCO₂/kg); Isolatie - Kunststof hard, Name: Isolatie - Kunststof hard; Isolatie - Kunststof hard, Participates in Collision Detection: yes
2 x Metaal - Aluminium | Begane grond N | Metaal - Aluminium | Nieuw | Material Properties - Metaal - Aluminium, ThermalConductivity: 160; Metaal - Aluminium, SpecificHeatCapacity: 880 J/kg/K; Metaal - Aluminium, MassDensity: 2800 kg/m3; Metaal - Aluminium, Embodied Energy: 155 (MJ/kg); Metaal - Aluminium, Embodied Carbon: 9.16 (kgCO₂/kg); Metaal - Aluminium, Name: Metaal - Aluminium; Metaal - Aluminium, Participates in Collision Detection: yes
7 x stucwerk | Begane grond N | stucwerk | Nieuw | Material Properties - stucwerk, ThermalConductivity: 2.3; stucwerk, SpecificHeatCapacity: 1000 J/kg/K; stucwerk, MassDensity: 2300 kg/m3; stucwerk, Embodied Energy: 1.92 (MJ/kg); stucwerk, Embodied Carbon: 0.198 (kgCO₂/kg); stucwerk, Name: stucwerk; stucwerk, Participates in Collision Detection: yes
Cement | Begane grond N | Cement | Nieuw | Material Properties - Cement, ThermalConductivity: 0.93; Cement, SpecificHeatCapacity: 840 J/kg/K; Cement, MassDensity: 1900 kg/m3; Cement, Embodied Energy: 0.97 (MJ/kg); Cement, Embodied Carbon: 0.146 (kgCO₂/kg); Cement, Name: Cement; Cement, Participates in Collision Detection: yes
Beton gewapend C vloer | Begane grond N | Beton gewapend C vloer | Nieuw | Material Properties - Beton gewapend C vloer, ThermalConductivity: 2.5; Beton gewapend C vloer, SpecificHeatCapacity: 1000 J/kg/K; Beton gewapend C vloer, MassDensity: 2400 kg/m3; Beton gewapend C vloer, Embodied Energy: 2.33 (MJ/kg); Beton gewapend C vloer, Embodied Carbon: 0.242 (kgCO₂/kg); Beton gewapend C vloer, Name: Beton gewapend C vloer; Beton gewapend C vloer, Participates in Collision Detection: yes
2 x Steen - Betonblok | Begane grond N | Steen - Betonblok | Nieuw | Material Properties - Steen - Betonblok, ThermalConductivity: 0.4; Steen - Betonblok, SpecificHeatCapacity: 840 J/kg/K; Steen - Betonblok, MassDensity: 800 kg/m3; Steen - Betonblok, Embodied Energy: 0.59 (MJ/kg); Steen - Betonblok, Embodied Carbon: 0.059 (kgCO₂/kg); Steen - Betonblok, Name: Steen - Betonblok; Steen - Betonblok, Participates in Collision Detection: yes
2 x Isolatie - Steenwol zacht | Begane grond N | Isolatie - Steenwol zacht | Nieuw | Material Properties - Isolatie - Steenwol zacht, ThermalConductivity: 0.035; Isolatie - Steenwol zacht, SpecificHeatCapacity: 840 J/kg/K; Isolatie - Steenwol zacht, MassDensity: 45 kg/m3; Isolatie - Steenwol zacht, Embodied Energy: 16.8 (MJ/kg); Isolatie - Steenwol zacht, Embodied Carbon: 1.05 (kgCO₂/kg); Isolatie - Steenwol zacht, Name: Isolatie - Steenwol zacht; Isolatie - Steenwol zacht, Participates in Collision Detection: yes
2 x Steen - Baksteen AFW | Begane grond N | Steen - Baksteen AFW | Nieuw | Material Properties - Steen - Baksteen AFW, ThermalConductivity: 0.9; Steen - Baksteen AFW, SpecificHeatCapacity: 840 J/kg/K; Steen - Baksteen AFW, MassDensity: 1600 kg/m3; Steen - Baksteen AFW, Embodied Energy: 3 (MJ/kg); Steen - Baksteen AFW, Embodied Carbon: 0.23 (kgCO₂/kg); Steen - Baksteen AFW, Name: Steen - Baksteen AFW; Steen - Baksteen AFW, Participates in Collision Detection: yes
104 x Isolatie - Steenwol LSW | 1e verdieping N | Isolatie - Steenwol LSW | Nieuw | Material Properties - Isolatie - Steenwol LSW, ThermalConductivity: 0.039; Isolatie - Steenwol LSW, SpecificHeatCapacity: 840 J/kg/K; Isolatie - Steenwol LSW, MassDensity: 55 kg/m3; Isolatie - Steenwol LSW, Embodied Energy: 16.8 (MJ/kg); Isolatie - Steenwol LSW, Embodied Carbon: 1.05 (kgCO₂/kg); Isolatie - Steenwol LSW, Name: Isolatie - Steenwol LSW; Isolatie - Steenwol LSW, Participates in Collision Detection: yes
206 x Gipsplaat | 1e verdieping N | Gipsplaat | Nieuw | Material Properties - Gipsplaat, ThermalConductivity: 0.23; Gipsplaat, SpecificHeatCapacity: 840 J/kg/K; Gipsplaat, MassDensity: 800 kg/m3; Gipsplaat, Embodied Energy: 6.75 (MJ/kg); Gipsplaat, Embodied Carbon: 0.38 (kgCO₂/kg); Gipsplaat, Name: Gipsplaat; Gipsplaat, Participates in Collision Detection: yes
10 x isolatie_080_1-100 | 1e verdieping N | isolatie_080_1-100 | Nieuw | Material Properties - isolatie_080_1-100, ThermalConductivity: 2.3; isolatie_080_1-100, SpecificHeatCapacity: 1000 J/kg/K; isolatie_080_1-100, MassDensity: 2300 kg/m3; isolatie_080_1-100, Embodied Energy: 1.92 (MJ/kg); isolatie_080_1-100, Embodied Carbon: 0.198 (kgCO₂/kg); isolatie_080_1-100, Name: isolatie_080_1-100; isolatie_080_1-100, Participates in Collision Detection: yes
10 x stucwerk - gevel gebouw V RAL 7044 | 1e verdieping N | stucwerk - gevel gebouw V RAL 7044 | Nieuw | Material Properties - stucwerk - gevel gebouw V RAL 7044, ThermalConductivity: 2.3; stucwerk - gevel gebouw V RAL 7044, SpecificHeatCapacity: 1000 J/kg/K; stucwerk - gevel gebouw V RAL 7044, MassDensity: 2300 kg/m3; stucwerk - gevel gebouw V RAL 7044, Embodied Energy: 1.92 (MJ/kg); stucwerk - gevel gebouw V RAL 7044, Embodied Carbon: 0.198 (kgCO₂/kg); stucwerk - gevel gebouw V RAL 7044, Name: stucwerk - gevel gebouw V RAL 7044; stucwerk - gevel gebouw V RAL 7044, Participates in Collision Detection: yes
10 x Verflaag ral 7044 Zijdengrijs Isostuc | 1e verdieping N | Verflaag ral 7044 Zijdengrijs Isostuc | Nieuw | Material Properties - Verflaag ral 7044 Zijdengrijs Isostuc, ThermalConductivity: 2.3; Verflaag ral 7044 Zijdengrijs Isostuc, SpecificHeatCapacity: 1000 J/kg/K; Verflaag ral 7044 Zijdengrijs Isostuc, MassDensity: 2300 kg/m3; Verflaag ral 7044 Zijdengrijs Isostuc, Embodied Energy: 1.92 (MJ/kg); Verflaag ral 7044 Zijdengrijs Isostuc, Embodied Carbon: 0.198 (kgCO₂/kg); Verflaag ral 7044 Zijdengrijs Isostuc, Name: Verflaag ral 7044 Zijdengrijs Isostuc; Verflaag ral 7044 Zijdengrijs Isostuc, Participates in Collision Detection: yes
isolatie | 1e verdieping N | isolatie | Nieuw | Material Properties - isolatie, ThermalConductivity: 2.3; isolatie, SpecificHeatCapacity: 1000 J/kg/K; isolatie, MassDensity: 2300 kg/m3; isolatie, Embodied Energy: 1.92 (MJ/kg); isolatie, Embodied Carbon: 0.198 (kgCO₂/kg); isolatie, Name: isolatie; isolatie, Participates in Collision Detection: yes
2 x luchtspouw | 1e verdieping N | luchtspouw | Nieuw | Material Properties - luchtspouw, ThermalConductivity: 2.3; luchtspouw, SpecificHeatCapacity: 1000 J/kg/K; luchtspouw, MassDensity: 2300 kg/m3; luchtspouw, Embodied Energy: 1.92 (MJ/kg); luchtspouw, Embodied Carbon: 0.198 (kgCO₂/kg); luchtspouw, Name: luchtspouw; luchtspouw, Participates in Collision Detection: yes
Houten delen vert | 1e verdieping N | Houten delen vert | Nieuw | Material Properties - Houten delen vert, ThermalConductivity: 2.3; Houten delen vert, SpecificHeatCapacity: 1000 J/kg/K; Houten delen vert, MassDensity: 2300 kg/m3; Houten delen vert, Embodied Energy: 1.92 (MJ/kg); Houten delen vert, Embodied Carbon: 0.198 (kgCO₂/kg); Houten delen vert, Name: Houten delen vert; Houten delen vert, Participates in Collision Detection: yes
4 x Gipsplaat | 1e verdieping N | Gipsplaat | Bestaand | Material Properties - Gipsplaat, ThermalConductivity: 0.23; Gipsplaat, SpecificHeatCapacity: 840 J/kg/K; Gipsplaat, MassDensity: 800 kg/m3; Gipsplaat, Embodied Energy: 6.75 (MJ/kg); Gipsplaat, Embodied Carbon: 0.38 (kgCO₂/kg); Gipsplaat, Name: Gipsplaat; Gipsplaat, Participates in Collision Detection: yes
2 x Isolatie - Steenwol LSW | 1e verdieping N | Isolatie - Steenwol LSW | Bestaand | Material Properties - Isolatie - Steenwol LSW, ThermalConductivity: 0.039; Isolatie - Steenwol LSW, SpecificHeatCapacity: 840 J/kg/K; Isolatie - Steenwol LSW, MassDensity: 55 kg/m3; Isolatie - Steenwol LSW, Embodied Energy: 16.8 (MJ/kg); Isolatie - Steenwol LSW, Embodied Carbon: 1.05 (kgCO₂/kg); Isolatie - Steenwol LSW, Name: Isolatie - Steenwol LSW; Isolatie - Steenwol LSW, Participates in Collision Detection: yes
160 x Gipsplaat | 2e verdieping N | Gipsplaat | Nieuw | Material Properties - Gipsplaat, ThermalConductivity: 0.23; Gipsplaat, SpecificHeatCapacity: 840 J/kg/K; Gipsplaat, MassDensity: 800 kg/m3; Gipsplaat, Embodied Energy: 6.75 (MJ/kg); Gipsplaat, Embodied Carbon: 0.38 (kgCO₂/kg); Gipsplaat, Name: Gipsplaat; Gipsplaat, Participates in Collision Detection: yes
80 x Isolatie - Steenwol LSW | 2e verdieping N | Isolatie - Steenwol LSW | Nieuw | Material Properties - Isolatie - Steenwol LSW, ThermalConductivity: 0.039; Isolatie - Steenwol LSW, SpecificHeatCapacity: 840 J/kg/K; Isolatie - Steenwol LSW, MassDensity: 55 kg/m3; Isolatie - Steenwol LSW, Embodied Energy: 16.8 (MJ/kg); Isolatie - Steenwol LSW, Embodied Carbon: 1.05 (kgCO₂/kg); Isolatie - Steenwol LSW, Name: Isolatie - Steenwol LSW; Isolatie - Steenwol LSW, Participates in Collision Detection: yes
6 x Verflaag ral 7044 Zijdengrijs Isostuc | 2e verdieping N | Verflaag ral 7044 Zijdengrijs Isostuc | Nieuw | Material Properties - Verflaag ral 7044 Zijdengrijs Isostuc, ThermalConductivity: 2.3; Verflaag ral 7044 Zijdengrijs Isostuc, SpecificHeatCapacity: 1000 J/kg/K; Verflaag ral 7044 Zijdengrijs Isostuc, MassDensity: 2300 kg/m3; Verflaag ral 7044 Zijdengrijs Isostuc, Embodied Energy: 1.92 (MJ/kg); Verflaag ral 7044 Zijdengrijs Isostuc, Embodied Carbon: 0.198 (kgCO₂/kg); Verflaag ral 7044 Zijdengrijs Isostuc, Name: Verflaag ral 7044 Zijdengrijs Isostuc; Verflaag ral 7044 Zijdengrijs Isostuc, Participates in Collision Detection: yes
6 x stucwerk - gevel gebouw V RAL 7044 | 2e verdieping N | stucwerk - gevel gebouw V RAL 7044 | Nieuw | Material Properties - stucwerk - gevel gebouw V RAL 7044, ThermalConductivity: 2.3; stucwerk - gevel gebouw V RAL 7044, SpecificHeatCapacity: 1000 J/kg/K; stucwerk - gevel gebouw V RAL 7044, MassDensity: 2300 kg/m3; stucwerk - gevel gebouw V RAL 7044, Embodied Energy: 1.92 (MJ/kg); stucwerk - gevel gebouw V RAL 7044, Embodied Carbon: 0.198 (kgCO₂/kg); stucwerk - gevel gebouw V RAL 7044, Name: stucwerk - gevel gebouw V RAL 7044; stucwerk - gevel gebouw V RAL 7044, Participates in Collision Detection: yes
26 x isolatie_080_1-100 | 2e verdieping N | isolatie_080_1-100 | Nieuw | Material Properties - isolatie_080_1-100, ThermalConductivity: 2.3; isolatie_080_1-100, SpecificHeatCapacity: 1000 J/kg/K; isolatie_080_1-100, MassDensity: 2300 kg/m3; isolatie_080_1-100, Embodied Energy: 1.92 (MJ/kg); isolatie_080_1-100, Embodied Carbon: 0.198 (kgCO₂/kg); isolatie_080_1-100, Name: isolatie_080_1-100; isolatie_080_1-100, Participates in Collision Detection: yes
40 x Aluminum geanodiseerd RAL 7024 | 2e verdieping N | Aluminum geanodiseerd RAL 7024 | Nieuw | Material Properties - Aluminum geanodiseerd RAL 7024, ThermalConductivity: 2.3; Aluminum geanodiseerd RAL 7024, SpecificHeatCapacity: 1000 J/kg/K; Aluminum geanodiseerd RAL 7024, MassDensity: 2300 kg/m3; Aluminum geanodiseerd RAL 7024, Embodied Energy: 1.92 (MJ/kg); Aluminum geanodiseerd RAL 7024, Embodied Carbon: 0.198 (kgCO₂/kg); Aluminum geanodiseerd RAL 7024, Name: Aluminum geanodiseerd RAL 7024; Aluminum geanodiseerd RAL 7024, Participates in Collision Detection: yes
4 x Hout - Multiplex | 2e verdieping N | Hout - Multiplex | Nieuw | Material Properties - Hout - Multiplex, ThermalConductivity: 0.17; Hout - Multiplex, SpecificHeatCapacity: 1600 J/kg/K; Hout - Multiplex, MassDensity: 700 kg/m3; Hout - Multiplex, Embodied Energy: 15 (MJ/kg); Hout - Multiplex, Embodied Carbon: 0.77 (kgCO₂/kg); Hout - Multiplex, Name: Hout - Multiplex; Hout - Multiplex, Participates in Collision Detection: yes
2 x Isolatie - Steenwol zacht | 2e verdieping N | Isolatie - Steenwol zacht | Nieuw | Material Properties - Isolatie - Steenwol zacht, ThermalConductivity: 0.035; Isolatie - Steenwol zacht, SpecificHeatCapacity: 840 J/kg/K; Isolatie - Steenwol zacht, MassDensity: 45 kg/m3; Isolatie - Steenwol zacht, Embodied Energy: 16.8 (MJ/kg); Isolatie - Steenwol zacht, Embodied Carbon: 1.05 (kgCO₂/kg); Isolatie - Steenwol zacht, Name: Isolatie - Steenwol zacht; Isolatie - Steenwol zacht, Participates in Collision Detection: yes
2 x Metaal - Staal AFW | 2e verdieping N | Metaal - Staal AFW | Nieuw | Material Properties - Metaal - Staal AFW, ThermalConductivity: 52; Metaal - Staal AFW, SpecificHeatCapacity: 530 J/kg/K; Metaal - Staal AFW, MassDensity: 7950 kg/m3; Metaal - Staal AFW, Embodied Energy: 25 (MJ/kg); Metaal - Staal AFW, Embodied Carbon: 1.91 (kgCO₂/kg); Metaal - Staal AFW, Name: Metaal - Staal AFW; Metaal - Staal AFW, Participates in Collision Detection: yes
Bestaand metselwerk | 2e verdieping N | Bestaand metselwerk | Nieuw | Material Properties - Bestaand metselwerk, ThermalConductivity: 2.3; Bestaand metselwerk, SpecificHeatCapacity: 1000 J/kg/K; Bestaand metselwerk, MassDensity: 2300 kg/m3; Bestaand metselwerk, Embodied Energy: 1.92 (MJ/kg); Bestaand metselwerk, Embodied Carbon: 0.198 (kgCO₂/kg); Bestaand metselwerk, Name: Bestaand metselwerk; Bestaand metselwerk, Participates in Collision Detection: yes
4 x stucwerk | 2e verdieping N | stucwerk | Nieuw | Material Properties - stucwerk, ThermalConductivity: 2.3; stucwerk, SpecificHeatCapacity: 1000 J/kg/K; stucwerk, MassDensity: 2300 kg/m3; stucwerk, Embodied Energy: 1.92 (MJ/kg); stucwerk, Embodied Carbon: 0.198 (kgCO₂/kg); stucwerk, Name: stucwerk; stucwerk, Participates in Collision Detection: yes
2 x metselwerk | 2e verdieping N | metselwerk | Nieuw | Material Properties - metselwerk, ThermalConductivity: 2.3; metselwerk, SpecificHeatCapacity: 1000 J/kg/K; metselwerk, MassDensity: 2300 kg/m3; metselwerk, Embodied Energy: 1.92 (MJ/kg); metselwerk, Embodied Carbon: 0.198 (kgCO₂/kg); metselwerk, Name: metselwerk; metselwerk, Participates in Collision Detection: yes
11 x luchtspouw | 2e verdieping N | luchtspouw | Nieuw | Material Properties - luchtspouw, ThermalConductivity: 2.3; luchtspouw, SpecificHeatCapacity: 1000 J/kg/K; luchtspouw, MassDensity: 2300 kg/m3; luchtspouw, Embodied Energy: 1.92 (MJ/kg); luchtspouw, Embodied Carbon: 0.198 (kgCO₂/kg); luchtspouw, Name: luchtspouw; luchtspouw, Participates in Collision Detection: yes
5 x Houten delen vert | 2e verdieping N | Houten delen vert | Nieuw | Material Properties - Houten delen vert, ThermalConductivity: 2.3; Houten delen vert, SpecificHeatCapacity: 1000 J/kg/K; Houten delen vert, MassDensity: 2300 kg/m3; Houten delen vert, Embodied Energy: 1.92 (MJ/kg); Houten delen vert, Embodied Carbon: 0.198 (kgCO₂/kg); Houten delen vert, Name: Houten delen vert; Houten delen vert, Participates in Collision Detection: yes
4 x isolatie | 2e verdieping N | isolatie | Nieuw | Material Properties - isolatie, ThermalConductivity: 2.3; isolatie, SpecificHeatCapacity: 1000 J/kg/K; isolatie, MassDensity: 2300 kg/m3; isolatie, Embodied Energy: 1.92 (MJ/kg); isolatie, Embodied Carbon: 0.198 (kgCO₂/kg); isolatie, Name: isolatie; isolatie, Participates in Collision Detection: yes
2 x Multiplex | 2e verdieping N | Multiplex | Nieuw | Material Properties - Multiplex, ThermalConductivity: 2.3; Multiplex, SpecificHeatCapacity: 1000 J/kg/K; Multiplex, MassDensity: 2300 kg/m3; Multiplex, Embodied Energy: 1.92 (MJ/kg); Multiplex, Embodied Carbon: 0.198 (kgCO₂/kg); Multiplex, Name: Multiplex; Multiplex, Participates in Collision Detection: yes
Oriented Strand Board | 2e verdieping N | Oriented Strand Board | Nieuw | Material Properties - Oriented Strand Board, ThermalConductivity: 2.3; Oriented Strand Board, SpecificHeatCapacity: 1000 J/kg/K; Oriented Strand Board, MassDensity: 2300 kg/m3; Oriented Strand Board, Embodied Energy: 1.92 (MJ/kg); Oriented Strand Board, Embodied Carbon: 0.198 (kgCO₂/kg); Oriented Strand Board, Name: Oriented Strand Board; Oriented Strand Board, Participates in Collision Detection: yes
4 x isolatie_080_1-100 | 2e verdieping V | isolatie_080_1-100 | Nieuw | Material Properties - isolatie_080_1-100, ThermalConductivity: 2.3; isolatie_080_1-100, SpecificHeatCapacity: 1000 J/kg/K; isolatie_080_1-100, MassDensity: 2300 kg/m3; isolatie_080_1-100, Embodied Energy: 1.92 (MJ/kg); isolatie_080_1-100, Embodied Carbon: 0.198 (kgCO₂/kg); isolatie_080_1-100, Name: isolatie_080_1-100; isolatie_080_1-100, Participates in Collision Detection: yes
4 x stucwerk - gevel gebouw V RAL 7044 | 2e verdieping V | stucwerk - gevel gebouw V RAL 7044 | Nieuw | Material Properties - stucwerk - gevel gebouw V RAL 7044, ThermalConductivity: 2.3; stucwerk - gevel gebouw V RAL 7044, SpecificHeatCapacity: 1000 J/kg/K; stucwerk - gevel gebouw V RAL 7044, MassDensity: 2300 kg/m3; stucwerk - gevel gebouw V RAL 7044, Embodied Energy: 1.92 (MJ/kg); stucwerk - gevel gebouw V RAL 7044, Embodied Carbon: 0.198 (kgCO₂/kg); stucwerk - gevel gebouw V RAL 7044, Name: stucwerk - gevel gebouw V RAL 7044; stucwerk - gevel gebouw V RAL 7044, Participates in Collision Detection: yes
2 x luchtspouw | 2e verdieping V | luchtspouw | Nieuw | Material Properties - luchtspouw, ThermalConductivity: 2.3; luchtspouw, SpecificHeatCapacity: 1000 J/kg/K; luchtspouw, MassDensity: 2300 kg/m3; luchtspouw, Embodied Energy: 1.92 (MJ/kg); luchtspouw, Embodied Carbon: 0.198 (kgCO₂/kg); luchtspouw, Name: luchtspouw; luchtspouw, Participates in Collision Detection: yes
4 x Verflaag ral 7044 Zijdengrijs Isostuc | 2e verdieping V | Verflaag ral 7044 Zijdengrijs Isostuc | Nieuw | Material Properties - Verflaag ral 7044 Zijdengrijs Isostuc, ThermalConductivity: 2.3; Verflaag ral 7044 Zijdengrijs Isostuc, SpecificHeatCapacity: 1000 J/kg/K; Verflaag ral 7044 Zijdengrijs Isostuc, MassDensity: 2300 kg/m3; Verflaag ral 7044 Zijdengrijs Isostuc, Embodied Energy: 1.92 (MJ/kg); Verflaag ral 7044 Zijdengrijs Isostuc, Embodied Carbon: 0.198 (kgCO₂/kg); Verflaag ral 7044 Zijdengrijs Isostuc, Name: Verflaag ral 7044 Zijdengrijs Isostuc; Verflaag ral 7044 Zijdengrijs Isostuc, Participates in Collision Detection: yes
Houten delen vert | 2e verdieping V | Houten delen vert | Nieuw | Material Properties - Houten delen vert, ThermalConductivity: 2.3; Houten delen vert, SpecificHeatCapacity: 1000 J/kg/K; Houten delen vert, MassDensity: 2300 kg/m3; Houten delen vert, Embodied Energy: 1.92 (MJ/kg); Houten delen vert, Embodied Carbon: 0.198 (kgCO₂/kg); Houten delen vert, Name: Houten delen vert; Houten delen vert, Participates in Collision Detection: yes
isolatie | 2e verdieping V | isolatie | Nieuw | Material Properties - isolatie, ThermalConductivity: 2.3; isolatie, SpecificHeatCapacity: 1000 J/kg/K; isolatie, MassDensity: 2300 kg/m3; isolatie, Embodied Energy: 1.92 (MJ/kg); isolatie, Embodied Carbon: 0.198 (kgCO₂/kg); isolatie, Name: isolatie; isolatie, Participates in Collision Detection: yes
Metaal - Staal AFW | 2e verdieping V | Metaal - Staal AFW | Nieuw | Material Properties - Metaal - Staal AFW, ThermalConductivity: 52; Metaal - Staal AFW, SpecificHeatCapacity: 530 J/kg/K; Metaal - Staal AFW, MassDensity: 7950 kg/m3; Metaal - Staal AFW, Embodied Energy: 25 (MJ/kg); Metaal - Staal AFW, Embodied Carbon: 1.91 (kgCO₂/kg); Metaal - Staal AFW, Name: Metaal - Staal AFW; Metaal - Staal AFW, Participates in Collision Detection: yes
Isolatie - Steenwol zacht | 2e verdieping V | Isolatie - Steenwol zacht | Nieuw | Material Properties - Isolatie - Steenwol zacht, ThermalConductivity: 0.035; Isolatie - Steenwol zacht, SpecificHeatCapacity: 840 J/kg/K; Isolatie - Steenwol zacht, MassDensity: 45 kg/m3; Isolatie - Steenwol zacht, Embodied Energy: 16.8 (MJ/kg); Isolatie - Steenwol zacht, Embodied Carbon: 1.05 (kgCO₂/kg); Isolatie - Steenwol zacht, Name: Isolatie - Steenwol zacht; Isolatie - Steenwol zacht, Participates in Collision Detection: yes
Hout - Multiplex | 2e verdieping V | Hout - Multiplex | Nieuw | Material Properties - Hout - Multiplex, ThermalConductivity: 0.17; Hout - Multiplex, SpecificHeatCapacity: 1600 J/kg/K; Hout - Multiplex, MassDensity: 700 kg/m3; Hout - Multiplex, Embodied Energy: 15 (MJ/kg); Hout - Multiplex, Embodied Carbon: 0.77 (kgCO₂/kg); Hout - Multiplex, Name: Hout - Multiplex; Hout - Multiplex, Participates in Collision Detection: yes
Gipsplaat | 2e verdieping V | Gipsplaat | Nieuw | Material Properties - Gipsplaat, ThermalConductivity: 0.23; Gipsplaat, SpecificHeatCapacity: 840 J/kg/K; Gipsplaat, MassDensity: 800 kg/m3; Gipsplaat, Embodied Energy: 6.75 (MJ/kg); Gipsplaat, Embodied Carbon: 0.38 (kgCO₂/kg); Gipsplaat, Name: Gipsplaat; Gipsplaat, Participates in Collision Detection: yes
4 x Verflaag ral 7044 Zijdengrijs Isostuc | 3e verdieping/dak N | Verflaag ral 7044 Zijdengrijs Isostuc | Nieuw | Material Properties - Verflaag ral 7044 Zijdengrijs Isostuc, ThermalConductivity: 2.3; Verflaag ral 7044 Zijdengrijs Isostuc, SpecificHeatCapacity: 1000 J/kg/K; Verflaag ral 7044 Zijdengrijs Isostuc, MassDensity: 2300 kg/m3; Verflaag ral 7044 Zijdengrijs Isostuc, Embodied Energy: 1.92 (MJ/kg); Verflaag ral 7044 Zijdengrijs Isostuc, Embodied Carbon: 0.198 (kgCO₂/kg); Verflaag ral 7044 Zijdengrijs Isostuc, Name: Verflaag ral 7044 Zijdengrijs Isostuc; Verflaag ral 7044 Zijdengrijs Isostuc, Participates in Collision Detection: yes
4 x isolatie_080_1-100 | 3e verdieping/dak N | isolatie_080_1-100 | Nieuw | Material Properties - isolatie_080_1-100, ThermalConductivity: 2.3; isolatie_080_1-100, SpecificHeatCapacity: 1000 J/kg/K; isolatie_080_1-100, MassDensity: 2300 kg/m3; isolatie_080_1-100, Embodied Energy: 1.92 (MJ/kg); isolatie_080_1-100, Embodied Carbon: 0.198 (kgCO₂/kg); isolatie_080_1-100, Name: isolatie_080_1-100; isolatie_080_1-100, Participates in Collision Detection: yes
3 x Membraan - waterdicht | 3e verdieping/dak N | Membraan - waterdicht | Nieuw | Material Properties - Membraan - waterdicht, ThermalConductivity: 0.2; Membraan - waterdicht, SpecificHeatCapacity: 1840 J/kg/K; Membraan - waterdicht, MassDensity: 1050 kg/m3; Membraan - waterdicht, Embodied Energy: 51 (MJ/kg); Membraan - waterdicht, Embodied Carbon: 0.38 (kgCO₂/kg); Membraan - waterdicht, Name: Membraan - waterdicht; Membraan - waterdicht, Participates in Collision Detection: yes
4 x stucwerk - gevel gebouw V RAL 7044 | 3e verdieping/dak N | stucwerk - gevel gebouw V RAL 7044 | Nieuw | Material Properties - stucwerk - gevel gebouw V RAL 7044, ThermalConductivity: 2.3; stucwerk - gevel gebouw V RAL 7044, SpecificHeatCapacity: 1000 J/kg/K; stucwerk - gevel gebouw V RAL 7044, MassDensity: 2300 kg/m3; stucwerk - gevel gebouw V RAL 7044, Embodied Energy: 1.92 (MJ/kg); stucwerk - gevel gebouw V RAL 7044, Embodied Carbon: 0.198 (kgCO₂/kg); stucwerk - gevel gebouw V RAL 7044, Name: stucwerk - gevel gebouw V RAL 7044; stucwerk - gevel gebouw V RAL 7044, Participates in Collision Detection: yes
3 x Isolatie - Kunststof hard | 3e verdieping/dak N | Isolatie - Kunststof hard | Nieuw | Material Properties - Isolatie - Kunststof hard, ThermalConductivity: 0.029; Isolatie - Kunststof hard, SpecificHeatCapacity: 1470 J/kg/K; Isolatie - Kunststof hard, MassDensity: 100 kg/m3; Isolatie - Kunststof hard, Embodied Energy: 101.5 (MJ/kg); Isolatie - Kunststof hard, Embodied Carbon: 3.48 (kgCO₂/kg); Isolatie - Kunststof hard, Name: Isolatie - Kunststof hard; Isolatie - Kunststof hard, Participates in Collision Detection: yes
2 x Membraan - dampdicht | 3e verdieping/dak N | Membraan - dampdicht | Nieuw | Material Properties - Membraan - dampdicht, ThermalConductivity: 0.22; Membraan - dampdicht, SpecificHeatCapacity: 1800 J/kg/K; Membraan - dampdicht, MassDensity: 910 kg/m3; Membraan - dampdicht, Embodied Energy: 99.2 (MJ/kg); Membraan - dampdicht, Embodied Carbon: 3.43 (kgCO₂/kg); Membraan - dampdicht, Name: Membraan - dampdicht; Membraan - dampdicht, Participates in Collision Detection: yes
Hout - Multiplex | 3e verdieping/dak N | Hout - Multiplex | Nieuw | Material Properties - Hout - Multiplex, ThermalConductivity: 0.17; Hout - Multiplex, SpecificHeatCapacity: 1600 J/kg/K; Hout - Multiplex, MassDensity: 700 kg/m3; Hout - Multiplex, Embodied Energy: 15 (MJ/kg); Hout - Multiplex, Embodied Carbon: 0.77 (kgCO₂/kg); Hout - Multiplex, Name: Hout - Multiplex; Hout - Multiplex, Participates in Collision Detection: yes
Houten delen vert | 3e verdieping/dak N | Houten delen vert | Nieuw | Material Properties - Houten delen vert, ThermalConductivity: 2.3; Houten delen vert, SpecificHeatCapacity: 1000 J/kg/K; Houten delen vert, MassDensity: 2300 kg/m3; Houten delen vert, Embodied Energy: 1.92 (MJ/kg); Houten delen vert, Embodied Carbon: 0.198 (kgCO₂/kg); Houten delen vert, Name: Houten delen vert; Houten delen vert, Participates in Collision Detection: yes
2 x luchtspouw | 3e verdieping/dak N | luchtspouw | Nieuw | Material Properties - luchtspouw, ThermalConductivity: 2.3; luchtspouw, SpecificHeatCapacity: 1000 J/kg/K; luchtspouw, MassDensity: 2300 kg/m3; luchtspouw, Embodied Energy: 1.92 (MJ/kg); luchtspouw, Embodied Carbon: 0.198 (kgCO₂/kg); luchtspouw, Name: luchtspouw; luchtspouw, Participates in Collision Detection: yes
isolatie | 3e verdieping/dak N | isolatie | Nieuw | Material Properties - isolatie, ThermalConductivity: 2.3; isolatie, SpecificHeatCapacity: 1000 J/kg/K; isolatie, MassDensity: 2300 kg/m3; isolatie, Embodied Energy: 1.92 (MJ/kg); isolatie, Embodied Carbon: 0.198 (kgCO₂/kg); isolatie, Name: isolatie; isolatie, Participates in Collision Detection: yes
4 x isolatie_080_1-100 | 3e verdieping V | isolatie_080_1-100 | Nieuw | Material Properties - isolatie_080_1-100, ThermalConductivity: 2.3; isolatie_080_1-100, SpecificHeatCapacity: 1000 J/kg/K; isolatie_080_1-100, MassDensity: 2300 kg/m3; isolatie_080_1-100, Embodied Energy: 1.92 (MJ/kg); isolatie_080_1-100, Embodied Carbon: 0.198 (kgCO₂/kg); isolatie_080_1-100, Name: isolatie_080_1-100; isolatie_080_1-100, Participates in Collision Detection: yes
4 x stucwerk - gevel gebouw V RAL 7044 | 3e verdieping V | stucwerk - gevel gebouw V RAL 7044 | Nieuw | Material Properties - stucwerk - gevel gebouw V RAL 7044, ThermalConductivity: 2.3; stucwerk - gevel gebouw V RAL 7044, SpecificHeatCapacity: 1000 J/kg/K; stucwerk - gevel gebouw V RAL 7044, MassDensity: 2300 kg/m3; stucwerk - gevel gebouw V RAL 7044, Embodied Energy: 1.92 (MJ/kg); stucwerk - gevel gebouw V RAL 7044, Embodied Carbon: 0.198 (kgCO₂/kg); stucwerk - gevel gebouw V RAL 7044, Name: stucwerk - gevel gebouw V RAL 7044; stucwerk - gevel gebouw V RAL 7044, Participates in Collision Detection: yes
4 x Verflaag ral 7044 Zijdengrijs Isostuc | 3e verdieping V | Verflaag ral 7044 Zijdengrijs Isostuc | Nieuw | Material Properties - Verflaag ral 7044 Zijdengrijs Isostuc, ThermalConductivity: 2.3; Verflaag ral 7044 Zijdengrijs Isostuc, SpecificHeatCapacity: 1000 J/kg/K; Verflaag ral 7044 Zijdengrijs Isostuc, MassDensity: 2300 kg/m3; Verflaag ral 7044 Zijdengrijs Isostuc, Embodied Energy: 1.92 (MJ/kg); Verflaag ral 7044 Zijdengrijs Isostuc, Embodied Carbon: 0.198 (kgCO₂/kg); Verflaag ral 7044 Zijdengrijs Isostuc, Name: Verflaag ral 7044 Zijdengrijs Isostuc; Verflaag ral 7044 Zijdengrijs Isostuc, Participates in Collision Detection: yes
isolatie | 3e verdieping V | isolatie | Nieuw | Material Properties - isolatie, ThermalConductivity: 2.3; isolatie, SpecificHeatCapacity: 1000 J/kg/K; isolatie, MassDensity: 2300 kg/m3; isolatie, Embodied Energy: 1.92 (MJ/kg); isolatie, Embodied Carbon: 0.198 (kgCO₂/kg); isolatie, Name: isolatie; isolatie, Participates in Collision Detection: yes
2 x luchtspouw | 3e verdieping V | luchtspouw | Nieuw | Material Properties - luchtspouw, ThermalConductivity: 2.3; luchtspouw, SpecificHeatCapacity: 1000 J/kg/K; luchtspouw, MassDensity: 2300 kg/m3; luchtspouw, Embodied Energy: 1.92 (MJ/kg); luchtspouw, Embodied Carbon: 0.198 (kgCO₂/kg); luchtspouw, Name: luchtspouw; luchtspouw, Participates in Collision Detection: yes
Houten delen vert | 3e verdieping V | Houten delen vert | Nieuw | Material Properties - Houten delen vert, ThermalConductivity: 2.3; Houten delen vert, SpecificHeatCapacity: 1000 J/kg/K; Houten delen vert, MassDensity: 2300 kg/m3; Houten delen vert, Embodied Energy: 1.92 (MJ/kg); Houten delen vert, Embodied Carbon: 0.198 (kgCO₂/kg); Houten delen vert, Name: Houten delen vert; Houten delen vert, Participates in Collision Detection: yes
stucwerk - gevel gebouw V RAL 7044 | 4e verdieping V | stucwerk - gevel gebouw V RAL 7044 | Nieuw | Material Properties - stucwerk - gevel gebouw V RAL 7044, ThermalConductivity: 2.3; stucwerk - gevel gebouw V RAL 7044, SpecificHeatCapacity: 1000 J/kg/K; stucwerk - gevel gebouw V RAL 7044, MassDensity: 2300 kg/m3; stucwerk - gevel gebouw V RAL 7044, Embodied Energy: 1.92 (MJ/kg); stucwerk - gevel gebouw V RAL 7044, Embodied Carbon: 0.198 (kgCO₂/kg); stucwerk - gevel gebouw V RAL 7044, Name: stucwerk - gevel gebouw V RAL 7044; stucwerk - gevel gebouw V RAL 7044, Participates in Collision Detection: yes
Verflaag ral 7044 Zijdengrijs Isostuc | 4e verdieping V | Verflaag ral 7044 Zijdengrijs Isostuc | Nieuw | Material Properties - Verflaag ral 7044 Zijdengrijs Isostuc, ThermalConductivity: 2.3; Verflaag ral 7044 Zijdengrijs Isostuc, SpecificHeatCapacity: 1000 J/kg/K; Verflaag ral 7044 Zijdengrijs Isostuc, MassDensity: 2300 kg/m3; Verflaag ral 7044 Zijdengrijs Isostuc, Embodied Energy: 1.92 (MJ/kg); Verflaag ral 7044 Zijdengrijs Isostuc, Embodied Carbon: 0.198 (kgCO₂/kg); Verflaag ral 7044 Zijdengrijs Isostuc, Name: Verflaag ral 7044 Zijdengrijs Isostuc; Verflaag ral 7044 Zijdengrijs Isostuc, Participates in Collision Detection: yes
isolatie_080_1-100 | 4e verdieping V | isolatie_080_1-100 | Nieuw | Material Properties - isolatie_080_1-100, ThermalConductivity: 2.3; isolatie_080_1-100, SpecificHeatCapacity: 1000 J/kg/K; isolatie_080_1-100, MassDensity: 2300 kg/m3; isolatie_080_1-100, Embodied Energy: 1.92 (MJ/kg); isolatie_080_1-100, Embodied Carbon: 0.198 (kgCO₂/kg); isolatie_080_1-100, Name: isolatie_080_1-100; isolatie_080_1-100, Participates in Collision Detection: yes
2 x luchtspouw | 4e verdieping V | luchtspouw | Nieuw | Material Properties - luchtspouw, ThermalConductivity: 2.3; luchtspouw, SpecificHeatCapacity: 1000 J/kg/K; luchtspouw, MassDensity: 2300 kg/m3; luchtspouw, Embodied Energy: 1.92 (MJ/kg); luchtspouw, Embodied Carbon: 0.198 (kgCO₂/kg); luchtspouw, Name: luchtspouw; luchtspouw, Participates in Collision Detection: yes
isolatie | 4e verdieping V | isolatie | Nieuw | Material Properties - isolatie, ThermalConductivity: 2.3; isolatie, SpecificHeatCapacity: 1000 J/kg/K; isolatie, MassDensity: 2300 kg/m3; isolatie, Embodied Energy: 1.92 (MJ/kg); isolatie, Embodied Carbon: 0.198 (kgCO₂/kg); isolatie, Name: isolatie; isolatie, Participates in Collision Detection: yes
Houten delen vert | 4e verdieping V | Houten delen vert | Nieuw | Material Properties - Houten delen vert, ThermalConductivity: 2.3; Houten delen vert, SpecificHeatCapacity: 1000 J/kg/K; Houten delen vert, MassDensity: 2300 kg/m3; Houten delen vert, Embodied Energy: 1.92 (MJ/kg); Houten delen vert, Embodied Carbon: 0.198 (kgCO₂/kg); Houten delen vert, Name: Houten delen vert; Houten delen vert, Participates in Collision Detection: yes
96 x Gyproc® A | 5e verdieping V | Gyproc® A | Nieuw | Material Properties - Gyproc® A, ThermalConductivity: 2.3; Gyproc® A, SpecificHeatCapacity: 1000 J/kg/K; Gyproc® A, MassDensity: 2300 kg/m3; Gyproc® A, Embodied Energy: 1.92 (MJ/kg); Gyproc® A, Embodied Carbon: 0.198 (kgCO₂/kg); Gyproc® A, Name: Gyproc® A; Gyproc® A, Participates in Collision Detection: yes
66 x GYPROC_Profile | 5e verdieping V | GYPROC_Profile | Nieuw | Material Properties - GYPROC_Profile, ThermalConductivity: 2.3; GYPROC_Profile, SpecificHeatCapacity: 1000 J/kg/K; GYPROC_Profile, MassDensity: 2300 kg/m3; GYPROC_Profile, Embodied Energy: 1.92 (MJ/kg); GYPROC_Profile, Embodied Carbon: 0.198 (kgCO₂/kg); GYPROC_Profile, Name: GYPROC_Profile; GYPROC_Profile, Participates in Collision Detection: yes
33 x ISOVER® Sonepanel | 5e verdieping V | ISOVER® Sonepanel | Nieuw | Material Properties - ISOVER® Sonepanel, ThermalConductivity: 2.3; ISOVER® Sonepanel, SpecificHeatCapacity: 1000 J/kg/K; ISOVER® Sonepanel, MassDensity: 2300 kg/m3; ISOVER® Sonepanel, Embodied Energy: 1.92 (MJ/kg); ISOVER® Sonepanel, Embodied Carbon: 0.198 (kgCO₂/kg); ISOVER® Sonepanel, Name: ISOVER® Sonepanel; ISOVER® Sonepanel, Participates in Collision Detection: yes
27 x stucwerk - gevel gebouw V RAL 7044 | 5e verdieping V | stucwerk - gevel gebouw V RAL 7044 | Nieuw | Material Properties - stucwerk - gevel gebouw V RAL 7044, ThermalConductivity: 2.3; stucwerk - gevel gebouw V RAL 7044, SpecificHeatCapacity: 1000 J/kg/K; stucwerk - gevel gebouw V RAL 7044, MassDensity: 2300 kg/m3; stucwerk - gevel gebouw V RAL 7044, Embodied Energy: 1.92 (MJ/kg); stucwerk - gevel gebouw V RAL 7044, Embodied Carbon: 0.198 (kgCO₂/kg); stucwerk - gevel gebouw V RAL 7044, Name: stucwerk - gevel gebouw V RAL 7044; stucwerk - gevel gebouw V RAL 7044, Participates in Collision Detection: yes
27 x Verflaag ral 7044 Zijdengrijs Isostuc | 5e verdieping V | Verflaag ral 7044 Zijdengrijs Isostuc | Nieuw | Material Properties - Verflaag ral 7044 Zijdengrijs Isostuc, ThermalConductivity: 2.3; Verflaag ral 7044 Zijdengrijs Isostuc, SpecificHeatCapacity: 1000 J/kg/K; Verflaag ral 7044 Zijdengrijs Isostuc, MassDensity: 2300 kg/m3; Verflaag ral 7044 Zijdengrijs Isostuc, Embodied Energy: 1.92 (MJ/kg); Verflaag ral 7044 Zijdengrijs Isostuc, Embodied Carbon: 0.198 (kgCO₂/kg); Verflaag ral 7044 Zijdengrijs Isostuc, Name: Verflaag ral 7044 Zijdengrijs Isostuc; Verflaag ral 7044 Zijdengrijs Isostuc, Participates in Collision Detection: yes
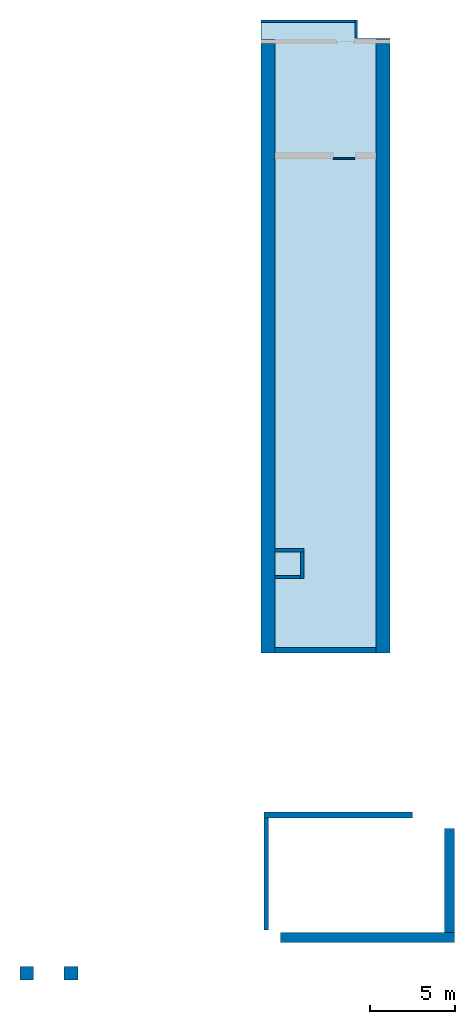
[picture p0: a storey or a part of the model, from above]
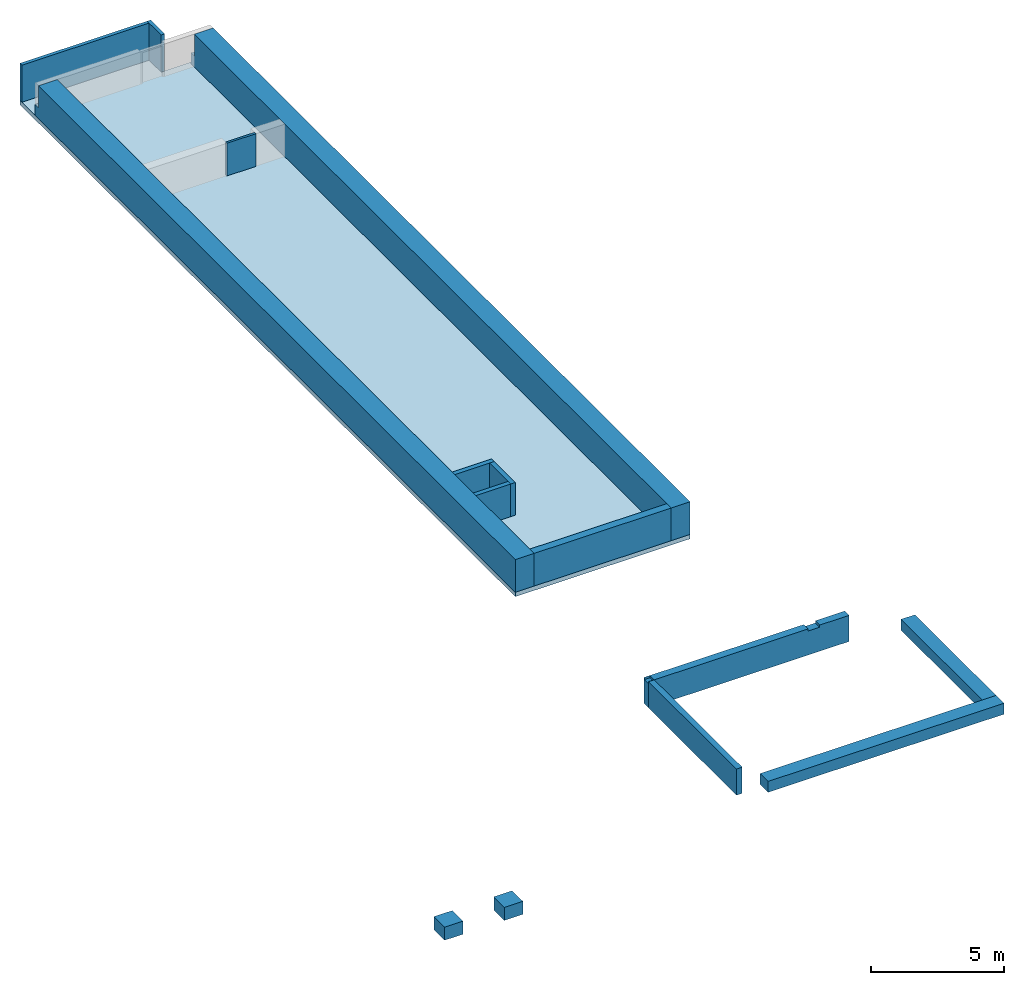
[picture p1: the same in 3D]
Properties of the parts of a building model (IFC2X3), part 2 of 7

# IfcBuildingElementPart (1450)
Name | In | Material | Renovation Phase
20 x isolatie_080_1-100 | 5e verdieping V | isolatie_080_1-100 | Nieuw | Material Properties - isolatie_080_1-100, ThermalConductivity: 2.3; isolatie_080_1-100, SpecificHeatCapacity: 1000 J/kg/K; isolatie_080_1-100, MassDensity: 2300 kg/m3; isolatie_080_1-100, Embodied Energy: 1.92 (MJ/kg); isolatie_080_1-100, Embodied Carbon: 0.198 (kgCO₂/kg); isolatie_080_1-100, Name: isolatie_080_1-100; isolatie_080_1-100, Participates in Collision Detection: yes
10 x DuraGyp® Standaard | 5e verdieping V | DuraGyp® Standaard | Nieuw | Material Properties - DuraGyp® Standaard, ThermalConductivity: 2.3; DuraGyp® Standaard, SpecificHeatCapacity: 1000 J/kg/K; DuraGyp® Standaard, MassDensity: 2300 kg/m3; DuraGyp® Standaard, Embodied Energy: 1.92 (MJ/kg); DuraGyp® Standaard, Embodied Carbon: 0.198 (kgCO₂/kg); DuraGyp® Standaard, Name: DuraGyp® Standaard; DuraGyp® Standaard, Participates in Collision Detection: yes
5 x GYPROC_Air | 5e verdieping V | GYPROC_Air | Nieuw | Material Properties - GYPROC_Air, ThermalConductivity: 2.3; GYPROC_Air, SpecificHeatCapacity: 1000 J/kg/K; GYPROC_Air, MassDensity: 2300 kg/m3; GYPROC_Air, Embodied Energy: 1.92 (MJ/kg); GYPROC_Air, Embodied Carbon: 0.198 (kgCO₂/kg); GYPROC_Air, Name: GYPROC_Air; GYPROC_Air, Participates in Collision Detection: yes
10 x RAL 7024 - Grafietgrijs | 5e verdieping V | RAL 7024 - Grafietgrijs | Nieuw | Material Properties - RAL 7024 - Grafietgrijs, ThermalConductivity: 2.3; RAL 7024 - Grafietgrijs, SpecificHeatCapacity: 1000 J/kg/K; RAL 7024 - Grafietgrijs, MassDensity: 2300 kg/m3; RAL 7024 - Grafietgrijs, Embodied Energy: 1.92 (MJ/kg); RAL 7024 - Grafietgrijs, Embodied Carbon: 0.198 (kgCO₂/kg); RAL 7024 - Grafietgrijs, Name: RAL 7024 - Grafietgrijs; RAL 7024 - Grafietgrijs, Participates in Collision Detection: yes
10 x aluminium | 5e verdieping V | aluminium | Nieuw | Material Properties - aluminium, ThermalConductivity: 2.3; aluminium, SpecificHeatCapacity: 1000 J/kg/K; aluminium, MassDensity: 2300 kg/m3; aluminium, Embodied Energy: 1.92 (MJ/kg); aluminium, Embodied Carbon: 0.198 (kgCO₂/kg); aluminium, Name: aluminium; aluminium, Participates in Collision Detection: yes
11 x isolatie_dak_120_1-100 | 5e verdieping V | isolatie_dak_120_1-100 | Nieuw | Material Properties - isolatie_dak_120_1-100, ThermalConductivity: 2.3; isolatie_dak_120_1-100, SpecificHeatCapacity: 1000 J/kg/K; isolatie_dak_120_1-100, MassDensity: 2300 kg/m3; isolatie_dak_120_1-100, Embodied Energy: 1.92 (MJ/kg); isolatie_dak_120_1-100, Embodied Carbon: 0.198 (kgCO₂/kg); isolatie_dak_120_1-100, Name: isolatie_dak_120_1-100; isolatie_dak_120_1-100, Participates in Collision Detection: yes
3 x HSB wand | 5e verdieping V | HSB wand | Nieuw | Material Properties - HSB wand, ThermalConductivity: 2.3; HSB wand, SpecificHeatCapacity: 1000 J/kg/K; HSB wand, MassDensity: 2300 kg/m3; HSB wand, Embodied Energy: 1.92 (MJ/kg); HSB wand, Embodied Carbon: 0.198 (kgCO₂/kg); HSB wand, Name: HSB wand; HSB wand, Participates in Collision Detection: yes
2 x Houten delen vert | 5e verdieping V | Houten delen vert | Nieuw | Material Properties - Houten delen vert, ThermalConductivity: 2.3; Houten delen vert, SpecificHeatCapacity: 1000 J/kg/K; Houten delen vert, MassDensity: 2300 kg/m3; Houten delen vert, Embodied Energy: 1.92 (MJ/kg); Houten delen vert, Embodied Carbon: 0.198 (kgCO₂/kg); Houten delen vert, Name: Houten delen vert; Houten delen vert, Participates in Collision Detection: yes
4 x luchtspouw | 5e verdieping V | luchtspouw | Nieuw | Material Properties - luchtspouw, ThermalConductivity: 2.3; luchtspouw, SpecificHeatCapacity: 1000 J/kg/K; luchtspouw, MassDensity: 2300 kg/m3; luchtspouw, Embodied Energy: 1.92 (MJ/kg); luchtspouw, Embodied Carbon: 0.198 (kgCO₂/kg); luchtspouw, Name: luchtspouw; luchtspouw, Participates in Collision Detection: yes
isolatie | 5e verdieping V | isolatie | Nieuw | Material Properties - isolatie, ThermalConductivity: 2.3; isolatie, SpecificHeatCapacity: 1000 J/kg/K; isolatie, MassDensity: 2300 kg/m3; isolatie, Embodied Energy: 1.92 (MJ/kg); isolatie, Embodied Carbon: 0.198 (kgCO₂/kg); isolatie, Name: isolatie; isolatie, Participates in Collision Detection: yes
4 x Verflaag ral 7044 Zijdengrijs Isostuc | 6e verdieping V | Verflaag ral 7044 Zijdengrijs Isostuc | Nieuw | Material Properties - Verflaag ral 7044 Zijdengrijs Isostuc, ThermalConductivity: 2.3; Verflaag ral 7044 Zijdengrijs Isostuc, SpecificHeatCapacity: 1000 J/kg/K; Verflaag ral 7044 Zijdengrijs Isostuc, MassDensity: 2300 kg/m3; Verflaag ral 7044 Zijdengrijs Isostuc, Embodied Energy: 1.92 (MJ/kg); Verflaag ral 7044 Zijdengrijs Isostuc, Embodied Carbon: 0.198 (kgCO₂/kg); Verflaag ral 7044 Zijdengrijs Isostuc, Name: Verflaag ral 7044 Zijdengrijs Isostuc; Verflaag ral 7044 Zijdengrijs Isostuc, Participates in Collision Detection: yes
4 x stucwerk - gevel gebouw V RAL 7044 | 6e verdieping V | stucwerk - gevel gebouw V RAL 7044 | Nieuw | Material Properties - stucwerk - gevel gebouw V RAL 7044, ThermalConductivity: 2.3; stucwerk - gevel gebouw V RAL 7044, SpecificHeatCapacity: 1000 J/kg/K; stucwerk - gevel gebouw V RAL 7044, MassDensity: 2300 kg/m3; stucwerk - gevel gebouw V RAL 7044, Embodied Energy: 1.92 (MJ/kg); stucwerk - gevel gebouw V RAL 7044, Embodied Carbon: 0.198 (kgCO₂/kg); stucwerk - gevel gebouw V RAL 7044, Name: stucwerk - gevel gebouw V RAL 7044; stucwerk - gevel gebouw V RAL 7044, Participates in Collision Detection: yes
4 x isolatie_080_1-100 | 6e verdieping V | isolatie_080_1-100 | Nieuw | Material Properties - isolatie_080_1-100, ThermalConductivity: 2.3; isolatie_080_1-100, SpecificHeatCapacity: 1000 J/kg/K; isolatie_080_1-100, MassDensity: 2300 kg/m3; isolatie_080_1-100, Embodied Energy: 1.92 (MJ/kg); isolatie_080_1-100, Embodied Carbon: 0.198 (kgCO₂/kg); isolatie_080_1-100, Name: isolatie_080_1-100; isolatie_080_1-100, Participates in Collision Detection: yes

# IfcBuildingElementProxy: 57_ZEHN_Warmteterugwinapparaat WHR930 rechts:WHR930 Basis rechts, 57_ZEHN_Warmteterugwinapparaat WHR930 rechts:WHR930 Basis rechts:2571872
In: 5e verdieping V
Material: IFC Building Material
Pset_QuantityTakeOff - Reference: WHR930 Basis rechts; sets with these values: 2
CPset_Phasing - Renovation Phase: Nieuw
Material Properties - IFC Building Material, ThermalConductivity: 2.3; IFC Building Material, SpecificHeatCapacity: 1000 J/kg/K; IFC Building Material, MassDensity: 2300 kg/m3; IFC Building Material, Embodied Energy: 1.92 (MJ/kg); IFC Building Material, Embodied Carbon: 0.198 (kgCO₂/kg); IFC Building Material, Name: IFC Building Material; IFC Building Material, Participates in Collision Detection: yes

# IfcBuildingElementProxy: 71_postkasten BBK 10 stuks R21:71_postkasten BBK 10 stuks R21, 71_postkasten BBK 10 stuks R21:71_postkasten BBK 10 stuks R21:2742604
In: 1e verdieping N
Material: IFC Building Material
Pset_QuantityTakeOff - Reference: 71_postkasten BBK 10 stuks R21; sets with these values: 2
CPset_Phasing - Renovation Phase: Nieuw
Material Properties - IFC Building Material, ThermalConductivity: 2.3; IFC Building Material, SpecificHeatCapacity: 1000 J/kg/K; IFC Building Material, MassDensity: 2300 kg/m3; IFC Building Material, Embodied Energy: 1.92 (MJ/kg); IFC Building Material, Embodied Carbon: 0.198 (kgCO₂/kg); IFC Building Material, Name: IFC Building Material; IFC Building Material, Participates in Collision Detection: yes

# IfcBuildingElementProxy: Beton C (3)
In: 5e verdieping V
Material: Beton C
Material Properties - Beton C, ThermalConductivity: 2; Beton C, SpecificHeatCapacity: 840 J/kg/K; Beton C, MassDensity: 2400 kg/m3; Beton C, Embodied Energy: 0.75 (MJ/kg); Beton C, Embodied Carbon: 0.1 (kgCO₂/kg); Beton C, Name: Beton C; Beton C, Participates in Collision Detection: yes
CPset_Phasing - Renovation Phase: Nieuw
Name (Wall Sweep:afdekkap gevel V:...) | Pset_QuantityTakeOff, Reference | Pset_QuantityTakeOff, sets with these values
2753781 | Pset_BuildingElementProxyCommon - Reference: afdekkap gevel V; sets with these values: 2
2753781 | afdekkap gevel V | 2
2766944 | afdekkap gevel V | 2

# IfcBuildingElementProxy: Buis ro koudgev kolom 27 (2)
In: Begane grond N
Material: Metaal - Staal AFW
Material Properties - Metaal - Staal AFW, ThermalConductivity: 52; Metaal - Staal AFW, SpecificHeatCapacity: 530 J/kg/K; Metaal - Staal AFW, MassDensity: 7950 kg/m3; Metaal - Staal AFW, Embodied Energy: 25 (MJ/kg); Metaal - Staal AFW, Embodied Carbon: 1.91 (kgCO₂/kg); Metaal - Staal AFW, Name: Metaal - Staal AFW; Metaal - Staal AFW, Participates in Collision Detection: yes

# IfcBuildingElementProxy: Buis vk koudgev balk 26 (25)
Material: Metaal - Staal AFW
Material Properties - Metaal - Staal AFW, ThermalConductivity: 52; Metaal - Staal AFW, SpecificHeatCapacity: 530 J/kg/K; Metaal - Staal AFW, MassDensity: 7950 kg/m3; Metaal - Staal AFW, Embodied Energy: 25 (MJ/kg); Metaal - Staal AFW, Embodied Carbon: 1.91 (kgCO₂/kg); Metaal - Staal AFW, Name: Metaal - Staal AFW; Metaal - Staal AFW, Participates in Collision Detection: yes
Name | In
7 x _Boom-x | 1e verdieping N
18 x _Boom-x | 3e verdieping/dak N

# IfcBuildingElementProxy: Buis vk koudgev kolom 26 (17)
Material: Metaal - Staal AFW
Material Properties - Metaal - Staal AFW, ThermalConductivity: 52; Metaal - Staal AFW, SpecificHeatCapacity: 530 J/kg/K; Metaal - Staal AFW, MassDensity: 7950 kg/m3; Metaal - Staal AFW, Embodied Energy: 25 (MJ/kg); Metaal - Staal AFW, Embodied Carbon: 1.91 (kgCO₂/kg); Metaal - Staal AFW, Name: Metaal - Staal AFW; Metaal - Staal AFW, Participates in Collision Detection: yes
Name | In
4 x _Boom-x | 1e verdieping N
3 x _Boom-x | 2e verdieping N
10 x _Boom-x | 3e verdieping/dak N

# IfcBuildingElementProxy: Buis vk warmgew balk 27 (2)
In: 1e verdieping N
Material: Metaal - Staal AFW
Material Properties - Metaal - Staal AFW, ThermalConductivity: 52; Metaal - Staal AFW, SpecificHeatCapacity: 530 J/kg/K; Metaal - Staal AFW, MassDensity: 7950 kg/m3; Metaal - Staal AFW, Embodied Energy: 25 (MJ/kg); Metaal - Staal AFW, Embodied Carbon: 1.91 (kgCO₂/kg); Metaal - Staal AFW, Name: Metaal - Staal AFW; Metaal - Staal AFW, Participates in Collision Detection: yes

# IfcBuildingElementProxy: Buis vk warmgew kolom 27 (59)
Material: Metaal - Staal AFW
Material Properties - Metaal - Staal AFW, ThermalConductivity: 52; Metaal - Staal AFW, SpecificHeatCapacity: 530 J/kg/K; Metaal - Staal AFW, MassDensity: 7950 kg/m3; Metaal - Staal AFW, Embodied Energy: 25 (MJ/kg); Metaal - Staal AFW, Embodied Carbon: 1.91 (kgCO₂/kg); Metaal - Staal AFW, Name: Metaal - Staal AFW; Metaal - Staal AFW, Participates in Collision Detection: yes
Name | In
18 x _Boom-x | Begane grond N
21 x _Boom-x | 1e verdieping N
20 x _Boom-x | 2e verdieping N

# IfcBuildingElementProxy: HEA balk 26, _Boom-x
In: 2e verdieping N
Material: Metaal - Staal AFW
Material Properties - Metaal - Staal AFW, ThermalConductivity: 52; Metaal - Staal AFW, SpecificHeatCapacity: 530 J/kg/K; Metaal - Staal AFW, MassDensity: 7950 kg/m3; Metaal - Staal AFW, Embodied Energy: 25 (MJ/kg); Metaal - Staal AFW, Embodied Carbon: 1.91 (kgCO₂/kg); Metaal - Staal AFW, Name: Metaal - Staal AFW; Metaal - Staal AFW, Participates in Collision Detection: yes

# IfcBuildingElementProxy: HEA balk 27 (12)
Material: Metaal - Staal AFW
Material Properties - Metaal - Staal AFW, ThermalConductivity: 52; Metaal - Staal AFW, SpecificHeatCapacity: 530 J/kg/K; Metaal - Staal AFW, MassDensity: 7950 kg/m3; Metaal - Staal AFW, Embodied Energy: 25 (MJ/kg); Metaal - Staal AFW, Embodied Carbon: 1.91 (kgCO₂/kg); Metaal - Staal AFW, Name: Metaal - Staal AFW; Metaal - Staal AFW, Participates in Collision Detection: yes
Name | In
6 x _Boom-x | Begane grond N
4 x _Boom-x | 1e verdieping N
2 x _Boom-x | 2e verdieping N

# IfcBuildingElementProxy: HEA kolom 26 (2)
In: Begane grond N
Material: Metaal - Staal AFW
Material Properties - Metaal - Staal AFW, ThermalConductivity: 52; Metaal - Staal AFW, SpecificHeatCapacity: 530 J/kg/K; Metaal - Staal AFW, MassDensity: 7950 kg/m3; Metaal - Staal AFW, Embodied Energy: 25 (MJ/kg); Metaal - Staal AFW, Embodied Carbon: 1.91 (kgCO₂/kg); Metaal - Staal AFW, Name: Metaal - Staal AFW; Metaal - Staal AFW, Participates in Collision Detection: yes

# IfcBuildingElementProxy: HEB balk 27 (19)
Material: Metaal - Staal AFW
Material Properties - Metaal - Staal AFW, ThermalConductivity: 52; Metaal - Staal AFW, SpecificHeatCapacity: 530 J/kg/K; Metaal - Staal AFW, MassDensity: 7950 kg/m3; Metaal - Staal AFW, Embodied Energy: 25 (MJ/kg); Metaal - Staal AFW, Embodied Carbon: 1.91 (kgCO₂/kg); Metaal - Staal AFW, Name: Metaal - Staal AFW; Metaal - Staal AFW, Participates in Collision Detection: yes
Name | In
6 x _Boom-x | Begane grond N
7 x _Boom-x | 1e verdieping N
6 x _Boom-x | 2e verdieping N

# IfcBuildingElementProxy: Hoeklijn gelijk balk 27, _Boom-x
In: 1e verdieping N
Material: Metaal - Staal AFW
Material Properties - Metaal - Staal AFW, ThermalConductivity: 52; Metaal - Staal AFW, SpecificHeatCapacity: 530 J/kg/K; Metaal - Staal AFW, MassDensity: 7950 kg/m3; Metaal - Staal AFW, Embodied Energy: 25 (MJ/kg); Metaal - Staal AFW, Embodied Carbon: 1.91 (kgCO₂/kg); Metaal - Staal AFW, Name: Metaal - Staal AFW; Metaal - Staal AFW, Participates in Collision Detection: yes

# IfcBuildingElementProxy: IFC Opening Extruded, _Object-x
In: 1e verdieping N
Material: IFC Building Material
CPset_Phasing - Renovation Phase: Nieuw
Material Properties - IFC Building Material, ThermalConductivity: 2.3; IFC Building Material, SpecificHeatCapacity: 1000 J/kg/K; IFC Building Material, MassDensity: 2300 kg/m3; IFC Building Material, Embodied Energy: 1.92 (MJ/kg); IFC Building Material, Embodied Carbon: 0.198 (kgCO₂/kg); IFC Building Material, Name: IFC Building Material; IFC Building Material, Participates in Collision Detection: yes

# IfcBuildingElementProxy: IfcBuildingElementProxy (3)
In: 1e verdieping N
Material: Metaal - Staal C
Material Properties - Metaal - Staal C, ThermalConductivity: 52; Metaal - Staal C, SpecificHeatCapacity: 530 J/kg/K; Metaal - Staal C, MassDensity: 7950 kg/m3; Metaal - Staal C, Embodied Energy: 25 (MJ/kg); Metaal - Staal C, Embodied Carbon: 1.91 (kgCO₂/kg); Metaal - Staal C, Name: Metaal - Staal C; Metaal - Staal C, Participates in Collision Detection: yes
Name
_Trapconstructie-x
_SS - 005
_SS - 004

# IfcBuildingElementProxy: NLRS_30_GM_UN_screen 95mm handbediend_Pirisol_ISR:screen handbediend_Pirisol_b 95 (2)
In: 5e verdieping V
Type - Description: Pirisol screen 95mm handbediend
Material: IFC Building Material
CPset_Phasing - Renovation Phase: Nieuw
Material Properties - IFC Building Material, ThermalConductivity: 2.3; IFC Building Material, SpecificHeatCapacity: 1000 J/kg/K; IFC Building Material, MassDensity: 2300 kg/m3; IFC Building Material, Embodied Energy: 1.92 (MJ/kg); IFC Building Material, Embodied Carbon: 0.198 (kgCO₂/kg); IFC Building Material, Name: IFC Building Material; IFC Building Material, Participates in Collision Detection: yes
Name (NLRS_30_GM_UN_screen 95mm handbediend_Pirisol_ISR:screen handbediend_Pirisol_b 95:...)
2659481 | Pset_BuildingElementProxyCommon - Reference: screen handbediend_Pirisol_b 95; sets with these values: 2
2659731 | Pset_QuantityTakeOff - Reference: screen handbediend_Pirisol_b 95; sets with these values: 2

# IfcBuildingElementProxy: Prefab balk recht 01 27 (22)
Material: Hout C
Material Properties - Hout C, ThermalConductivity: 0.14; Hout C, SpecificHeatCapacity: 1880 J/kg/K; Hout C, MassDensity: 550 kg/m3; Hout C, Embodied Energy: 7.4 (MJ/kg); Hout C, Embodied Carbon: 0.19 (kgCO₂/kg); Hout C, Name: Hout C; Hout C, Participates in Collision Detection: yes
Name | In
7 x _Boom-x | 1e verdieping N
15 x _Boom-x | 2e verdieping V

# IfcBuildingElementProxy: Profielplaat 26 (10)
Material: Metaal - Staal AFW
Material Properties - Metaal - Staal AFW, ThermalConductivity: 52; Metaal - Staal AFW, SpecificHeatCapacity: 530 J/kg/K; Metaal - Staal AFW, MassDensity: 7950 kg/m3; Metaal - Staal AFW, Embodied Energy: 25 (MJ/kg); Metaal - Staal AFW, Embodied Carbon: 1.91 (kgCO₂/kg); Metaal - Staal AFW, Name: Metaal - Staal AFW; Metaal - Staal AFW, Participates in Collision Detection: yes
Name | In
2 x _Boom-x | 1e verdieping N
2 x _Boom-x | 2e verdieping N
6 x _Boom-x | 3e verdieping/dak N

# IfcBuildingElementProxy: Structural Connections 229:Structural Connections 1, Structural Connections 229:Structural Connections 1:2971957
In: 3e verdieping V
Material: staal geanodiseerd RAL 7024; Group: Model Group:BUITENRUIMTE helft:2971965
Pset_QuantityTakeOff - Reference: Structural Connections 1; sets with these values: 2
CPset_Phasing - Renovation Phase: Nieuw
Material Properties - staal geanodiseerd RAL 7024, ThermalConductivity: 2.3; staal geanodiseerd RAL 7024, SpecificHeatCapacity: 1000 J/kg/K; staal geanodiseerd RAL 7024, MassDensity: 2300 kg/m3; staal geanodiseerd RAL 7024, Embodied Energy: 1.92 (MJ/kg); staal geanodiseerd RAL 7024, Embodied Carbon: 0.198 (kgCO₂/kg); staal geanodiseerd RAL 7024, Name: staal geanodiseerd RAL 7024; staal geanodiseerd RAL 7024, Participates in Collision Detection: yes

# IfcBuildingElementProxy: Structural Connections 230:Structural Connections 1, Structural Connections 230:Structural Connections 1:2971984
In: 3e verdieping V
Material: staal geanodiseerd RAL 7024; Group: Model Group:BUITENRUIMTE helft:2971992
Pset_BuildingElementProxyCommon - Reference: Structural Connections 1; sets with these values: 2
CPset_Phasing - Renovation Phase: Nieuw
Material Properties - staal geanodiseerd RAL 7024, ThermalConductivity: 2.3; staal geanodiseerd RAL 7024, SpecificHeatCapacity: 1000 J/kg/K; staal geanodiseerd RAL 7024, MassDensity: 2300 kg/m3; staal geanodiseerd RAL 7024, Embodied Energy: 1.92 (MJ/kg); staal geanodiseerd RAL 7024, Embodied Carbon: 0.198 (kgCO₂/kg); staal geanodiseerd RAL 7024, Name: staal geanodiseerd RAL 7024; staal geanodiseerd RAL 7024, Participates in Collision Detection: yes

# IfcBuildingElementProxy: Structural Connections 231:Structural Connections 1, Structural Connections 231:Structural Connections 1:2972011
In: 2e verdieping V
Material: staal geanodiseerd RAL 7024; Group: Model Group:BUITENRUIMTE helft:2972019
Pset_QuantityTakeOff - Reference: Structural Connections 1; sets with these values: 2
CPset_Phasing - Renovation Phase: Nieuw
Material Properties - staal geanodiseerd RAL 7024, ThermalConductivity: 2.3; staal geanodiseerd RAL 7024, SpecificHeatCapacity: 1000 J/kg/K; staal geanodiseerd RAL 7024, MassDensity: 2300 kg/m3; staal geanodiseerd RAL 7024, Embodied Energy: 1.92 (MJ/kg); staal geanodiseerd RAL 7024, Embodied Carbon: 0.198 (kgCO₂/kg); staal geanodiseerd RAL 7024, Name: staal geanodiseerd RAL 7024; staal geanodiseerd RAL 7024, Participates in Collision Detection: yes

# IfcBuildingElementProxy: Structural Connections 232:Structural Connections 1, Structural Connections 232:Structural Connections 1:2972038
In: 2e verdieping V
Material: staal geanodiseerd RAL 7024; Group: Model Group:BUITENRUIMTE helft:2972046
Pset_QuantityTakeOff - Reference: Structural Connections 1; sets with these values: 2
CPset_Phasing - Renovation Phase: Nieuw
Material Properties - staal geanodiseerd RAL 7024, ThermalConductivity: 2.3; staal geanodiseerd RAL 7024, SpecificHeatCapacity: 1000 J/kg/K; staal geanodiseerd RAL 7024, MassDensity: 2300 kg/m3; staal geanodiseerd RAL 7024, Embodied Energy: 1.92 (MJ/kg); staal geanodiseerd RAL 7024, Embodied Carbon: 0.198 (kgCO₂/kg); staal geanodiseerd RAL 7024, Name: staal geanodiseerd RAL 7024; staal geanodiseerd RAL 7024, Participates in Collision Detection: yes

# IfcBuildingElementProxy: Structural Connections 233:Structural Connections 1, Structural Connections 233:Structural Connections 1:2972065
In: 3e verdieping/dak N
Material: staal geanodiseerd RAL 7024; Group: Model Group:BUITENRUIMTE helft:2972073
Pset_QuantityTakeOff - Reference: Structural Connections 1; sets with these values: 2
CPset_Phasing - Renovation Phase: Nieuw
Material Properties - staal geanodiseerd RAL 7024, ThermalConductivity: 2.3; staal geanodiseerd RAL 7024, SpecificHeatCapacity: 1000 J/kg/K; staal geanodiseerd RAL 7024, MassDensity: 2300 kg/m3; staal geanodiseerd RAL 7024, Embodied Energy: 1.92 (MJ/kg); staal geanodiseerd RAL 7024, Embodied Carbon: 0.198 (kgCO₂/kg); staal geanodiseerd RAL 7024, Name: staal geanodiseerd RAL 7024; staal geanodiseerd RAL 7024, Participates in Collision Detection: yes

# IfcBuildingElementProxy: Structural Connections 234:Structural Connections 1, Structural Connections 234:Structural Connections 1:2972092
In: 3e verdieping/dak N
Material: staal geanodiseerd RAL 7024; Group: Model Group:BUITENRUIMTE helft:2972100
Pset_QuantityTakeOff - Reference: Structural Connections 1; sets with these values: 2
CPset_Phasing - Renovation Phase: Nieuw
Material Properties - staal geanodiseerd RAL 7024, ThermalConductivity: 2.3; staal geanodiseerd RAL 7024, SpecificHeatCapacity: 1000 J/kg/K; staal geanodiseerd RAL 7024, MassDensity: 2300 kg/m3; staal geanodiseerd RAL 7024, Embodied Energy: 1.92 (MJ/kg); staal geanodiseerd RAL 7024, Embodied Carbon: 0.198 (kgCO₂/kg); staal geanodiseerd RAL 7024, Name: staal geanodiseerd RAL 7024; staal geanodiseerd RAL 7024, Participates in Collision Detection: yes

# IfcBuildingElementProxy: Structural Connections 235:Structural Connections 1, Structural Connections 235:Structural Connections 1:2972312
In: 2e verdieping N
Material: staal geanodiseerd RAL 7024; Group: Model Group:BUITENRUIMTE helft:2972320
Pset_BuildingElementProxyCommon - Reference: Structural Connections 1; sets with these values: 2
Material Properties - staal geanodiseerd RAL 7024, ThermalConductivity: 2.3; staal geanodiseerd RAL 7024, SpecificHeatCapacity: 1000 J/kg/K; staal geanodiseerd RAL 7024, MassDensity: 2300 kg/m3; staal geanodiseerd RAL 7024, Embodied Energy: 1.92 (MJ/kg); staal geanodiseerd RAL 7024, Embodied Carbon: 0.198 (kgCO₂/kg); staal geanodiseerd RAL 7024, Name: staal geanodiseerd RAL 7024; staal geanodiseerd RAL 7024, Participates in Collision Detection: yes
CPset_Phasing - Renovation Phase: Nieuw

# IfcBuildingElementProxy: Structural Connections 236:Structural Connections 1, Structural Connections 236:Structural Connections 1:2972339
In: 2e verdieping N
Material: staal geanodiseerd RAL 7024; Group: Model Group:BUITENRUIMTE helft:2972347
Pset_QuantityTakeOff - Reference: Structural Connections 1; sets with these values: 2
CPset_Phasing - Renovation Phase: Nieuw
Material Properties - staal geanodiseerd RAL 7024, ThermalConductivity: 2.3; staal geanodiseerd RAL 7024, SpecificHeatCapacity: 1000 J/kg/K; staal geanodiseerd RAL 7024, MassDensity: 2300 kg/m3; staal geanodiseerd RAL 7024, Embodied Energy: 1.92 (MJ/kg); staal geanodiseerd RAL 7024, Embodied Carbon: 0.198 (kgCO₂/kg); staal geanodiseerd RAL 7024, Name: staal geanodiseerd RAL 7024; staal geanodiseerd RAL 7024, Participates in Collision Detection: yes

# IfcBuildingElementProxy: Structural Connections 237:Structural Connections 1, Structural Connections 237:Structural Connections 1:2972429
In: 4e verdieping V
Material: staal geanodiseerd RAL 7024; Group: Model Group:BUITENRUIMTE helft dak:2972437
Pset_QuantityTakeOff - Reference: Structural Connections 1; sets with these values: 2
Material Properties - staal geanodiseerd RAL 7024, ThermalConductivity: 2.3; staal geanodiseerd RAL 7024, SpecificHeatCapacity: 1000 J/kg/K; staal geanodiseerd RAL 7024, MassDensity: 2300 kg/m3; staal geanodiseerd RAL 7024, Embodied Energy: 1.92 (MJ/kg); staal geanodiseerd RAL 7024, Embodied Carbon: 0.198 (kgCO₂/kg); staal geanodiseerd RAL 7024, Name: staal geanodiseerd RAL 7024; staal geanodiseerd RAL 7024, Participates in Collision Detection: yes
CPset_Phasing - Renovation Phase: Nieuw

# IfcBuildingElementProxy: Structural Connections 244:Structural Connections 1, Structural Connections 244:Structural Connections 1:2972557
In: 2e verdieping N
Material: staal geanodiseerd RAL 7024; Group: Model Group:BUITENRUIMTE helft:2972320
Material Properties - staal geanodiseerd RAL 7024, ThermalConductivity: 2.3; staal geanodiseerd RAL 7024, SpecificHeatCapacity: 1000 J/kg/K; staal geanodiseerd RAL 7024, MassDensity: 2300 kg/m3; staal geanodiseerd RAL 7024, Embodied Energy: 1.92 (MJ/kg); staal geanodiseerd RAL 7024, Embodied Carbon: 0.198 (kgCO₂/kg); staal geanodiseerd RAL 7024, Name: staal geanodiseerd RAL 7024; staal geanodiseerd RAL 7024, Participates in Collision Detection: yes
Pset_BuildingElementProxyCommon - Reference: Structural Connections 1; sets with these values: 2
CPset_Phasing - Renovation Phase: Nieuw

# IfcBuildingElementProxy: Structural Connections 245:Structural Connections 1, Structural Connections 245:Structural Connections 1:2972569
In: 2e verdieping N
Material: staal geanodiseerd RAL 7024; Group: Model Group:BUITENRUIMTE helft:2972347
Pset_BuildingElementProxyCommon - Reference: Structural Connections 1; sets with these values: 2
Material Properties - staal geanodiseerd RAL 7024, ThermalConductivity: 2.3; staal geanodiseerd RAL 7024, SpecificHeatCapacity: 1000 J/kg/K; staal geanodiseerd RAL 7024, MassDensity: 2300 kg/m3; staal geanodiseerd RAL 7024, Embodied Energy: 1.92 (MJ/kg); staal geanodiseerd RAL 7024, Embodied Carbon: 0.198 (kgCO₂/kg); staal geanodiseerd RAL 7024, Name: staal geanodiseerd RAL 7024; staal geanodiseerd RAL 7024, Participates in Collision Detection: yes
CPset_Phasing - Renovation Phase: Nieuw

# IfcBuildingElementProxy: Structural Connections 247:Structural Connections 1, Structural Connections 247:Structural Connections 1:2972606
In: 4e verdieping V
Material: staal geanodiseerd RAL 7024; Group: Model Group:BUITENRUIMTE helft dak:2972614
Pset_QuantityTakeOff - Reference: Structural Connections 1; sets with these values: 2
CPset_Phasing - Renovation Phase: Nieuw
Material Properties - staal geanodiseerd RAL 7024, ThermalConductivity: 2.3; staal geanodiseerd RAL 7024, SpecificHeatCapacity: 1000 J/kg/K; staal geanodiseerd RAL 7024, MassDensity: 2300 kg/m3; staal geanodiseerd RAL 7024, Embodied Energy: 1.92 (MJ/kg); staal geanodiseerd RAL 7024, Embodied Carbon: 0.198 (kgCO₂/kg); staal geanodiseerd RAL 7024, Name: staal geanodiseerd RAL 7024; staal geanodiseerd RAL 7024, Participates in Collision Detection: yes

# IfcBuildingElementProxy: Structural Connections 249:Structural Connections 1, Structural Connections 249:Structural Connections 1:2972737
In: 3e verdieping V
Material: staal geanodiseerd RAL 7024
CPset_Phasing - Renovation Phase: Nieuw
Pset_BuildingElementProxyCommon - Reference: Structural Connections 1; sets with these values: 2
Material Properties - staal geanodiseerd RAL 7024, ThermalConductivity: 2.3; staal geanodiseerd RAL 7024, SpecificHeatCapacity: 1000 J/kg/K; staal geanodiseerd RAL 7024, MassDensity: 2300 kg/m3; staal geanodiseerd RAL 7024, Embodied Energy: 1.92 (MJ/kg); staal geanodiseerd RAL 7024, Embodied Carbon: 0.198 (kgCO₂/kg); staal geanodiseerd RAL 7024, Name: staal geanodiseerd RAL 7024; staal geanodiseerd RAL 7024, Participates in Collision Detection: yes

# IfcBuildingElementProxy: Structural Connections 250:Structural Connections 1, Structural Connections 250:Structural Connections 1:2972785
In: 2e verdieping N
Material: staal geanodiseerd RAL 7024
Pset_QuantityTakeOff - Reference: Structural Connections 1; sets with these values: 2
CPset_Phasing - Renovation Phase: Nieuw
Material Properties - staal geanodiseerd RAL 7024, ThermalConductivity: 2.3; staal geanodiseerd RAL 7024, SpecificHeatCapacity: 1000 J/kg/K; staal geanodiseerd RAL 7024, MassDensity: 2300 kg/m3; staal geanodiseerd RAL 7024, Embodied Energy: 1.92 (MJ/kg); staal geanodiseerd RAL 7024, Embodied Carbon: 0.198 (kgCO₂/kg); staal geanodiseerd RAL 7024, Name: staal geanodiseerd RAL 7024; staal geanodiseerd RAL 7024, Participates in Collision Detection: yes

# IfcBuildingElementProxy: Structural Connections 251:Structural Connections 1, Structural Connections 251:Structural Connections 1:2972826
In: 2e verdieping V
Material: staal geanodiseerd RAL 7024
Pset_QuantityTakeOff - Reference: Structural Connections 1; sets with these values: 2
CPset_Phasing - Renovation Phase: Nieuw
Material Properties - staal geanodiseerd RAL 7024, ThermalConductivity: 2.3; staal geanodiseerd RAL 7024, SpecificHeatCapacity: 1000 J/kg/K; staal geanodiseerd RAL 7024, MassDensity: 2300 kg/m3; staal geanodiseerd RAL 7024, Embodied Energy: 1.92 (MJ/kg); staal geanodiseerd RAL 7024, Embodied Carbon: 0.198 (kgCO₂/kg); staal geanodiseerd RAL 7024, Name: staal geanodiseerd RAL 7024; staal geanodiseerd RAL 7024, Participates in Collision Detection: yes

# IfcBuildingElementProxy: Structural Connections 252:Structural Connections 1, Structural Connections 252:Structural Connections 1:2972874
In: 3e verdieping/dak N
Material: staal geanodiseerd RAL 7024
Pset_QuantityTakeOff - Reference: Structural Connections 1; sets with these values: 2
Material Properties - staal geanodiseerd RAL 7024, ThermalConductivity: 2.3; staal geanodiseerd RAL 7024, SpecificHeatCapacity: 1000 J/kg/K; staal geanodiseerd RAL 7024, MassDensity: 2300 kg/m3; staal geanodiseerd RAL 7024, Embodied Energy: 1.92 (MJ/kg); staal geanodiseerd RAL 7024, Embodied Carbon: 0.198 (kgCO₂/kg); staal geanodiseerd RAL 7024, Name: staal geanodiseerd RAL 7024; staal geanodiseerd RAL 7024, Participates in Collision Detection: yes
CPset_Phasing - Renovation Phase: Nieuw

# IfcBuildingElementProxy: Structural Connections 253:Structural Connections 1, Structural Connections 253:Structural Connections 1:2972923
In: 4e verdieping V
Material: staal geanodiseerd RAL 7024
Pset_QuantityTakeOff - Reference: Structural Connections 1; sets with these values: 2
Material Properties - staal geanodiseerd RAL 7024, ThermalConductivity: 2.3; staal geanodiseerd RAL 7024, SpecificHeatCapacity: 1000 J/kg/K; staal geanodiseerd RAL 7024, MassDensity: 2300 kg/m3; staal geanodiseerd RAL 7024, Embodied Energy: 1.92 (MJ/kg); staal geanodiseerd RAL 7024, Embodied Carbon: 0.198 (kgCO₂/kg); staal geanodiseerd RAL 7024, Name: staal geanodiseerd RAL 7024; staal geanodiseerd RAL 7024, Participates in Collision Detection: yes
CPset_Phasing - Renovation Phase: Nieuw

# IfcBuildingElementProxy: Structural Connections 254:Structural Connections 1, Structural Connections 254:Structural Connections 1:2972964
In: 4e verdieping V
Material: staal geanodiseerd RAL 7024
Pset_QuantityTakeOff - Reference: Structural Connections 1; sets with these values: 2
CPset_Phasing - Renovation Phase: Nieuw
Material Properties - staal geanodiseerd RAL 7024, ThermalConductivity: 2.3; staal geanodiseerd RAL 7024, SpecificHeatCapacity: 1000 J/kg/K; staal geanodiseerd RAL 7024, MassDensity: 2300 kg/m3; staal geanodiseerd RAL 7024, Embodied Energy: 1.92 (MJ/kg); staal geanodiseerd RAL 7024, Embodied Carbon: 0.198 (kgCO₂/kg); staal geanodiseerd RAL 7024, Name: staal geanodiseerd RAL 7024; staal geanodiseerd RAL 7024, Participates in Collision Detection: yes

# IfcBuildingElementProxy: Structural Connections 255:Structural Connections 1, Structural Connections 255:Structural Connections 1:2973052
In: 3e verdieping V
Material: staal geanodiseerd RAL 7024
Pset_BuildingElementProxyCommon - Reference: Structural Connections 1; sets with these values: 2
Material Properties - staal geanodiseerd RAL 7024, ThermalConductivity: 2.3; staal geanodiseerd RAL 7024, SpecificHeatCapacity: 1000 J/kg/K; staal geanodiseerd RAL 7024, MassDensity: 2300 kg/m3; staal geanodiseerd RAL 7024, Embodied Energy: 1.92 (MJ/kg); staal geanodiseerd RAL 7024, Embodied Carbon: 0.198 (kgCO₂/kg); staal geanodiseerd RAL 7024, Name: staal geanodiseerd RAL 7024; staal geanodiseerd RAL 7024, Participates in Collision Detection: yes
CPset_Phasing - Renovation Phase: Nieuw

# IfcBuildingElementProxy: Structural Connections 256:Structural Connections 1, Structural Connections 256:Structural Connections 1:2973100
In: 2e verdieping N
Material: staal geanodiseerd RAL 7024
Pset_BuildingElementProxyCommon - Reference: Structural Connections 1; sets with these values: 2
CPset_Phasing - Renovation Phase: Nieuw
Material Properties - staal geanodiseerd RAL 7024, ThermalConductivity: 2.3; staal geanodiseerd RAL 7024, SpecificHeatCapacity: 1000 J/kg/K; staal geanodiseerd RAL 7024, MassDensity: 2300 kg/m3; staal geanodiseerd RAL 7024, Embodied Energy: 1.92 (MJ/kg); staal geanodiseerd RAL 7024, Embodied Carbon: 0.198 (kgCO₂/kg); staal geanodiseerd RAL 7024, Name: staal geanodiseerd RAL 7024; staal geanodiseerd RAL 7024, Participates in Collision Detection: yes

# IfcBuildingElementProxy: Structural Connections 257:Structural Connections 1, Structural Connections 257:Structural Connections 1:2973148
In: 2e verdieping V
Material: staal geanodiseerd RAL 7024
Pset_QuantityTakeOff - Reference: Structural Connections 1; sets with these values: 2
Material Properties - staal geanodiseerd RAL 7024, ThermalConductivity: 2.3; staal geanodiseerd RAL 7024, SpecificHeatCapacity: 1000 J/kg/K; staal geanodiseerd RAL 7024, MassDensity: 2300 kg/m3; staal geanodiseerd RAL 7024, Embodied Energy: 1.92 (MJ/kg); staal geanodiseerd RAL 7024, Embodied Carbon: 0.198 (kgCO₂/kg); staal geanodiseerd RAL 7024, Name: staal geanodiseerd RAL 7024; staal geanodiseerd RAL 7024, Participates in Collision Detection: yes
CPset_Phasing - Renovation Phase: Nieuw

# IfcBuildingElementProxy: Structural Connections 258:Structural Connections 1, Structural Connections 258:Structural Connections 1:2973196
In: 3e verdieping/dak N
Material: staal geanodiseerd RAL 7024
Pset_QuantityTakeOff - Reference: Structural Connections 1; sets with these values: 2
CPset_Phasing - Renovation Phase: Nieuw
Material Properties - staal geanodiseerd RAL 7024, ThermalConductivity: 2.3; staal geanodiseerd RAL 7024, SpecificHeatCapacity: 1000 J/kg/K; staal geanodiseerd RAL 7024, MassDensity: 2300 kg/m3; staal geanodiseerd RAL 7024, Embodied Energy: 1.92 (MJ/kg); staal geanodiseerd RAL 7024, Embodied Carbon: 0.198 (kgCO₂/kg); staal geanodiseerd RAL 7024, Name: staal geanodiseerd RAL 7024; staal geanodiseerd RAL 7024, Participates in Collision Detection: yes

# IfcBuildingElementProxy: Structural Connections 259:Structural Connections 1, Structural Connections 259:Structural Connections 1:2973245
In: 4e verdieping V
Material: staal geanodiseerd RAL 7024
CPset_Phasing - Renovation Phase: Nieuw
Pset_QuantityTakeOff - Reference: Structural Connections 1; sets with these values: 2
Material Properties - staal geanodiseerd RAL 7024, ThermalConductivity: 2.3; staal geanodiseerd RAL 7024, SpecificHeatCapacity: 1000 J/kg/K; staal geanodiseerd RAL 7024, MassDensity: 2300 kg/m3; staal geanodiseerd RAL 7024, Embodied Energy: 1.92 (MJ/kg); staal geanodiseerd RAL 7024, Embodied Carbon: 0.198 (kgCO₂/kg); staal geanodiseerd RAL 7024, Name: staal geanodiseerd RAL 7024; staal geanodiseerd RAL 7024, Participates in Collision Detection: yes

# IfcBuildingElementProxy: Structural Connections 260:Structural Connections 1, Structural Connections 260:Structural Connections 1:2973307
In: 3e verdieping V
Material: staal geanodiseerd RAL 7024
Pset_QuantityTakeOff - Reference: Structural Connections 1; sets with these values: 2
Material Properties - staal geanodiseerd RAL 7024, ThermalConductivity: 2.3; staal geanodiseerd RAL 7024, SpecificHeatCapacity: 1000 J/kg/K; staal geanodiseerd RAL 7024, MassDensity: 2300 kg/m3; staal geanodiseerd RAL 7024, Embodied Energy: 1.92 (MJ/kg); staal geanodiseerd RAL 7024, Embodied Carbon: 0.198 (kgCO₂/kg); staal geanodiseerd RAL 7024, Name: staal geanodiseerd RAL 7024; staal geanodiseerd RAL 7024, Participates in Collision Detection: yes
CPset_Phasing - Renovation Phase: Nieuw

# IfcBuildingElementProxy: Structural Connections 261:Structural Connections 1, Structural Connections 261:Structural Connections 1:2973355
In: 2e verdieping N
Material: staal geanodiseerd RAL 7024
Pset_QuantityTakeOff - Reference: Structural Connections 1; sets with these values: 2
CPset_Phasing - Renovation Phase: Nieuw
Material Properties - staal geanodiseerd RAL 7024, ThermalConductivity: 2.3; staal geanodiseerd RAL 7024, SpecificHeatCapacity: 1000 J/kg/K; staal geanodiseerd RAL 7024, MassDensity: 2300 kg/m3; staal geanodiseerd RAL 7024, Embodied Energy: 1.92 (MJ/kg); staal geanodiseerd RAL 7024, Embodied Carbon: 0.198 (kgCO₂/kg); staal geanodiseerd RAL 7024, Name: staal geanodiseerd RAL 7024; staal geanodiseerd RAL 7024, Participates in Collision Detection: yes

# IfcBuildingElementProxy: Structural Connections 262:Structural Connections 1, Structural Connections 262:Structural Connections 1:2973396
In: 2e verdieping V
Material: staal geanodiseerd RAL 7024
Material Properties - staal geanodiseerd RAL 7024, ThermalConductivity: 2.3; staal geanodiseerd RAL 7024, SpecificHeatCapacity: 1000 J/kg/K; staal geanodiseerd RAL 7024, MassDensity: 2300 kg/m3; staal geanodiseerd RAL 7024, Embodied Energy: 1.92 (MJ/kg); staal geanodiseerd RAL 7024, Embodied Carbon: 0.198 (kgCO₂/kg); staal geanodiseerd RAL 7024, Name: staal geanodiseerd RAL 7024; staal geanodiseerd RAL 7024, Participates in Collision Detection: yes
CPset_Phasing - Renovation Phase: Nieuw
Pset_BuildingElementProxyCommon - Reference: Structural Connections 1; sets with these values: 2

# IfcBuildingElementProxy: Structural Connections 263:Structural Connections 1, Structural Connections 263:Structural Connections 1:2973444
In: 3e verdieping/dak N
Material: staal geanodiseerd RAL 7024
Pset_QuantityTakeOff - Reference: Structural Connections 1; sets with these values: 2
CPset_Phasing - Renovation Phase: Nieuw
Material Properties - staal geanodiseerd RAL 7024, ThermalConductivity: 2.3; staal geanodiseerd RAL 7024, SpecificHeatCapacity: 1000 J/kg/K; staal geanodiseerd RAL 7024, MassDensity: 2300 kg/m3; staal geanodiseerd RAL 7024, Embodied Energy: 1.92 (MJ/kg); staal geanodiseerd RAL 7024, Embodied Carbon: 0.198 (kgCO₂/kg); staal geanodiseerd RAL 7024, Name: staal geanodiseerd RAL 7024; staal geanodiseerd RAL 7024, Participates in Collision Detection: yes

# IfcBuildingElementProxy: Structural Connections 264:Structural Connections 1, Structural Connections 264:Structural Connections 1:2973493
In: 4e verdieping V
Material: staal geanodiseerd RAL 7024
Pset_QuantityTakeOff - Reference: Structural Connections 1; sets with these values: 2
CPset_Phasing - Renovation Phase: Nieuw
Material Properties - staal geanodiseerd RAL 7024, ThermalConductivity: 2.3; staal geanodiseerd RAL 7024, SpecificHeatCapacity: 1000 J/kg/K; staal geanodiseerd RAL 7024, MassDensity: 2300 kg/m3; staal geanodiseerd RAL 7024, Embodied Energy: 1.92 (MJ/kg); staal geanodiseerd RAL 7024, Embodied Carbon: 0.198 (kgCO₂/kg); staal geanodiseerd RAL 7024, Name: staal geanodiseerd RAL 7024; staal geanodiseerd RAL 7024, Participates in Collision Detection: yes

# IfcBuildingElementProxy: Structural Connections 269:Structural Connections 1, Structural Connections 269:Structural Connections 1:2974118
In: 2e verdieping N
Material: staal geanodiseerd RAL 7024; Group: Model Group:verbinding 1:2974151
Pset_QuantityTakeOff - Reference: Structural Connections 1; sets with these values: 2
Material Properties - staal geanodiseerd RAL 7024, ThermalConductivity: 2.3; staal geanodiseerd RAL 7024, SpecificHeatCapacity: 1000 J/kg/K; staal geanodiseerd RAL 7024, MassDensity: 2300 kg/m3; staal geanodiseerd RAL 7024, Embodied Energy: 1.92 (MJ/kg); staal geanodiseerd RAL 7024, Embodied Carbon: 0.198 (kgCO₂/kg); staal geanodiseerd RAL 7024, Name: staal geanodiseerd RAL 7024; staal geanodiseerd RAL 7024, Participates in Collision Detection: yes
CPset_Phasing - Renovation Phase: Nieuw

# IfcBuildingElementProxy: Structural Connections 2:Structural Connections 1, Structural Connections 2:Structural Connections 1:3148295
In: 5e verdieping V
Material: staal geanodiseerd RAL 7024; Group: Model Group:luifel penthouse:3148164
Pset_BuildingElementProxyCommon - Reference: Structural Connections 1; sets with these values: 2
CPset_Phasing - Renovation Phase: Nieuw
Material Properties - staal geanodiseerd RAL 7024, ThermalConductivity: 2.3; staal geanodiseerd RAL 7024, SpecificHeatCapacity: 1000 J/kg/K; staal geanodiseerd RAL 7024, MassDensity: 2300 kg/m3; staal geanodiseerd RAL 7024, Embodied Energy: 1.92 (MJ/kg); staal geanodiseerd RAL 7024, Embodied Carbon: 0.198 (kgCO₂/kg); staal geanodiseerd RAL 7024, Name: staal geanodiseerd RAL 7024; staal geanodiseerd RAL 7024, Participates in Collision Detection: yes

# IfcBuildingElementProxy: Structural Connections 3:Structural Connections 1, Structural Connections 3:Structural Connections 1:3021267
In: 2e verdieping N
Material: staal geanodiseerd RAL 7024; Group: Model Group:verbinding 1:3021300
Pset_QuantityTakeOff - Reference: Structural Connections 1; sets with these values: 2
CPset_Phasing - Renovation Phase: Nieuw
Material Properties - staal geanodiseerd RAL 7024, ThermalConductivity: 2.3; staal geanodiseerd RAL 7024, SpecificHeatCapacity: 1000 J/kg/K; staal geanodiseerd RAL 7024, MassDensity: 2300 kg/m3; staal geanodiseerd RAL 7024, Embodied Energy: 1.92 (MJ/kg); staal geanodiseerd RAL 7024, Embodied Carbon: 0.198 (kgCO₂/kg); staal geanodiseerd RAL 7024, Name: staal geanodiseerd RAL 7024; staal geanodiseerd RAL 7024, Participates in Collision Detection: yes

# IfcBuildingElementProxy: Structural Connections 4:Structural Connections 1, Structural Connections 4:Structural Connections 1:3021339
In: 2e verdieping N
Material: staal geanodiseerd RAL 7024; Group: Model Group:verbinding 1:3021372
Pset_QuantityTakeOff - Reference: Structural Connections 1; sets with these values: 2
CPset_Phasing - Renovation Phase: Nieuw
Material Properties - staal geanodiseerd RAL 7024, ThermalConductivity: 2.3; staal geanodiseerd RAL 7024, SpecificHeatCapacity: 1000 J/kg/K; staal geanodiseerd RAL 7024, MassDensity: 2300 kg/m3; staal geanodiseerd RAL 7024, Embodied Energy: 1.92 (MJ/kg); staal geanodiseerd RAL 7024, Embodied Carbon: 0.198 (kgCO₂/kg); staal geanodiseerd RAL 7024, Name: staal geanodiseerd RAL 7024; staal geanodiseerd RAL 7024, Participates in Collision Detection: yes

# IfcBuildingElementProxy: Structural Connections 5:Structural Connections 1, Structural Connections 5:Structural Connections 1:3021397
In: 2e verdieping N
Material: staal geanodiseerd RAL 7024; Group: Model Group:verbinding 1:3021430
Pset_QuantityTakeOff - Reference: Structural Connections 1; sets with these values: 2
CPset_Phasing - Renovation Phase: Nieuw
Material Properties - staal geanodiseerd RAL 7024, ThermalConductivity: 2.3; staal geanodiseerd RAL 7024, SpecificHeatCapacity: 1000 J/kg/K; staal geanodiseerd RAL 7024, MassDensity: 2300 kg/m3; staal geanodiseerd RAL 7024, Embodied Energy: 1.92 (MJ/kg); staal geanodiseerd RAL 7024, Embodied Carbon: 0.198 (kgCO₂/kg); staal geanodiseerd RAL 7024, Name: staal geanodiseerd RAL 7024; staal geanodiseerd RAL 7024, Participates in Collision Detection: yes

# IfcBuildingElementProxy: Structural Connections 6:Structural Connections 1, Structural Connections 6:Structural Connections 1:3148318
In: 5e verdieping V
Material: staal geanodiseerd RAL 7024; Group: Model Group:luifel penthouse:3148164
Pset_BuildingElementProxyCommon - Reference: Structural Connections 1; sets with these values: 2
Material Properties - staal geanodiseerd RAL 7024, ThermalConductivity: 2.3; staal geanodiseerd RAL 7024, SpecificHeatCapacity: 1000 J/kg/K; staal geanodiseerd RAL 7024, MassDensity: 2300 kg/m3; staal geanodiseerd RAL 7024, Embodied Energy: 1.92 (MJ/kg); staal geanodiseerd RAL 7024, Embodied Carbon: 0.198 (kgCO₂/kg); staal geanodiseerd RAL 7024, Name: staal geanodiseerd RAL 7024; staal geanodiseerd RAL 7024, Participates in Collision Detection: yes
CPset_Phasing - Renovation Phase: Nieuw

# IfcBuildingElementProxy: Structural Connections 7:Structural Connections 1, Structural Connections 7:Structural Connections 1:3148342
In: 5e verdieping V
Material: staal geanodiseerd RAL 7024; Group: Model Group:luifel penthouse:3148164
Pset_QuantityTakeOff - Reference: Structural Connections 1; sets with these values: 2
CPset_Phasing - Renovation Phase: Nieuw
Material Properties - staal geanodiseerd RAL 7024, ThermalConductivity: 2.3; staal geanodiseerd RAL 7024, SpecificHeatCapacity: 1000 J/kg/K; staal geanodiseerd RAL 7024, MassDensity: 2300 kg/m3; staal geanodiseerd RAL 7024, Embodied Energy: 1.92 (MJ/kg); staal geanodiseerd RAL 7024, Embodied Carbon: 0.198 (kgCO₂/kg); staal geanodiseerd RAL 7024, Name: staal geanodiseerd RAL 7024; staal geanodiseerd RAL 7024, Participates in Collision Detection: yes

# IfcBuildingElementProxy: Structural Connections 8:Structural Connections 1, Structural Connections 8:Structural Connections 1:3148365
In: 5e verdieping V
Material: staal geanodiseerd RAL 7024; Group: Model Group:luifel penthouse:3148164
Pset_QuantityTakeOff - Reference: Structural Connections 1; sets with these values: 2
Material Properties - staal geanodiseerd RAL 7024, ThermalConductivity: 2.3; staal geanodiseerd RAL 7024, SpecificHeatCapacity: 1000 J/kg/K; staal geanodiseerd RAL 7024, MassDensity: 2300 kg/m3; staal geanodiseerd RAL 7024, Embodied Energy: 1.92 (MJ/kg); staal geanodiseerd RAL 7024, Embodied Carbon: 0.198 (kgCO₂/kg); staal geanodiseerd RAL 7024, Name: staal geanodiseerd RAL 7024; staal geanodiseerd RAL 7024, Participates in Collision Detection: yes
CPset_Phasing - Renovation Phase: Nieuw

# IfcBuildingElementProxy: UPN balk 27 (18)
Material: Metaal - Staal AFW
Material Properties - Metaal - Staal AFW, ThermalConductivity: 52; Metaal - Staal AFW, SpecificHeatCapacity: 530 J/kg/K; Metaal - Staal AFW, MassDensity: 7950 kg/m3; Metaal - Staal AFW, Embodied Energy: 25 (MJ/kg); Metaal - Staal AFW, Embodied Carbon: 1.91 (kgCO₂/kg); Metaal - Staal AFW, Name: Metaal - Staal AFW; Metaal - Staal AFW, Participates in Collision Detection: yes
Name | In
3 x _Boom-x | Begane grond N
7 x _Boom-x | 1e verdieping N
8 x _Boom-x | 2e verdieping N

# IfcBuildingElementProxy: UPN kolom 27, _Boom-x
In: Begane grond N
Material: Metaal - Staal AFW
Material Properties - Metaal - Staal AFW, ThermalConductivity: 52; Metaal - Staal AFW, SpecificHeatCapacity: 530 J/kg/K; Metaal - Staal AFW, MassDensity: 7950 kg/m3; Metaal - Staal AFW, Embodied Energy: 25 (MJ/kg); Metaal - Staal AFW, Embodied Carbon: 1.91 (kgCO₂/kg); Metaal - Staal AFW, Name: Metaal - Staal AFW; Metaal - Staal AFW, Participates in Collision Detection: yes

# IfcBuildingElementProxy: Wall Sweep:afdekkap gevel V, Wall Sweep:afdekkap gevel V:3146978
In: 5e verdieping V
Material: aluminium_wit
Pset_QuantityTakeOff - Reference: afdekkap gevel V; sets with these values: 2
CPset_Phasing - Renovation Phase: Nieuw
Material Properties - aluminium_wit, ThermalConductivity: 2.3; aluminium_wit, SpecificHeatCapacity: 1000 J/kg/K; aluminium_wit, MassDensity: 2300 kg/m3; aluminium_wit, Embodied Energy: 1.92 (MJ/kg); aluminium_wit, Embodied Carbon: 0.198 (kgCO₂/kg); aluminium_wit, Name: aluminium_wit; aluminium_wit, Participates in Collision Detection: yes

# IfcColumn: ALG - CONSTRUCTIEF 200 x 150 (6)
Type - PredefinedType: COLUMN
Material: ALG - CONSTRUCTIEF
Pset_ColumnCommon - Slope: 90 deg; FireRating: n.v.t.; IsExternal: no; LoadBearing: yes; Reference: ALG - CONSTRUCTIEF 200 x 150
CPset_Phasing - Renovation Phase: Bestaand
Material Properties - ALG - CONSTRUCTIEF, ThermalConductivity: 2.3; ALG - CONSTRUCTIEF, SpecificHeatCapacity: 1000 J/kg/K; ALG - CONSTRUCTIEF, MassDensity: 2300 kg/m3; ALG - CONSTRUCTIEF, Embodied Energy: 1.92 (MJ/kg); ALG - CONSTRUCTIEF, Embodied Carbon: 0.198 (kgCO₂/kg); ALG - CONSTRUCTIEF, Name: ALG - CONSTRUCTIEF; ALG - CONSTRUCTIEF, Participates in Collision Detection: yes
Name | In
2 x _Kolom-x | 3e verdieping/dak N
2 x _Kolom-x | 3e verdieping V
2 x _Kolom-x | 4e verdieping V

# IfcColumn: ALG - CONSTRUCTIEF 400 x 400 (24)
Type - PredefinedType: COLUMN
Material: ALG - CONSTRUCTIEF
CPset_Phasing - Renovation Phase: Bestaand
Pset_ColumnCommon - Slope: 90 deg; FireRating: n.v.t.; IsExternal: no; LoadBearing: yes; Reference: ALG - CONSTRUCTIEF 400 x 400
Material Properties - ALG - CONSTRUCTIEF, ThermalConductivity: 2.3; ALG - CONSTRUCTIEF, SpecificHeatCapacity: 1000 J/kg/K; ALG - CONSTRUCTIEF, MassDensity: 2300 kg/m3; ALG - CONSTRUCTIEF, Embodied Energy: 1.92 (MJ/kg); ALG - CONSTRUCTIEF, Embodied Carbon: 0.198 (kgCO₂/kg); ALG - CONSTRUCTIEF, Name: ALG - CONSTRUCTIEF; ALG - CONSTRUCTIEF, Participates in Collision Detection: yes
Name | In
12 x _Kolom-x | 1e verdieping N
12 x _Kolom-x | 2e verdieping N

# IfcColumn: ALG - CONSTRUCTIEF 500 x 355 (8)
Type - PredefinedType: COLUMN
Material: ALG - CONSTRUCTIEF
Pset_ColumnCommon - Slope: 90 deg; FireRating: n.v.t.; IsExternal: no; LoadBearing: yes; Reference: ALG - CONSTRUCTIEF 500 x 355
CPset_Phasing - Renovation Phase: Bestaand
Material Properties - ALG - CONSTRUCTIEF, ThermalConductivity: 2.3; ALG - CONSTRUCTIEF, SpecificHeatCapacity: 1000 J/kg/K; ALG - CONSTRUCTIEF, MassDensity: 2300 kg/m3; ALG - CONSTRUCTIEF, Embodied Energy: 1.92 (MJ/kg); ALG - CONSTRUCTIEF, Embodied Carbon: 0.198 (kgCO₂/kg); ALG - CONSTRUCTIEF, Name: ALG - CONSTRUCTIEF; ALG - CONSTRUCTIEF, Participates in Collision Detection: yes
Name | In
4 x _Kolom-x | 1e verdieping N
4 x _Kolom-x | 2e verdieping N

# IfcColumn: ALG - CONSTRUCTIEF 500 x 800 (3)
In: 1e verdieping N
Type - PredefinedType: COLUMN
Material: ALG - CONSTRUCTIEF
Pset_ColumnCommon - Slope: 90 deg; FireRating: n.v.t.; IsExternal: no; LoadBearing: yes; Reference: ALG - CONSTRUCTIEF 500 x 800
CPset_Phasing - Renovation Phase: Bestaand
Material Properties - ALG - CONSTRUCTIEF, ThermalConductivity: 2.3; ALG - CONSTRUCTIEF, SpecificHeatCapacity: 1000 J/kg/K; ALG - CONSTRUCTIEF, MassDensity: 2300 kg/m3; ALG - CONSTRUCTIEF, Embodied Energy: 1.92 (MJ/kg); ALG - CONSTRUCTIEF, Embodied Carbon: 0.198 (kgCO₂/kg); ALG - CONSTRUCTIEF, Name: ALG - CONSTRUCTIEF; ALG - CONSTRUCTIEF, Participates in Collision Detection: yes

# IfcColumn: ALG - CONSTRUCTIEF 500 x 820, _Kolom-x
In: 1e verdieping N
Type - PredefinedType: COLUMN
Material: ALG - CONSTRUCTIEF
Pset_ColumnCommon - Slope: 90 deg; FireRating: n.v.t.; IsExternal: no; LoadBearing: yes; Reference: ALG - CONSTRUCTIEF 500 x 820
CPset_Phasing - Renovation Phase: Bestaand
Material Properties - ALG - CONSTRUCTIEF, ThermalConductivity: 2.3; ALG - CONSTRUCTIEF, SpecificHeatCapacity: 1000 J/kg/K; ALG - CONSTRUCTIEF, MassDensity: 2300 kg/m3; ALG - CONSTRUCTIEF, Embodied Energy: 1.92 (MJ/kg); ALG - CONSTRUCTIEF, Embodied Carbon: 0.198 (kgCO₂/kg); ALG - CONSTRUCTIEF, Name: ALG - CONSTRUCTIEF; ALG - CONSTRUCTIEF, Participates in Collision Detection: yes

# IfcColumn: ALG - CONSTRUCTIEF 525 x 820 (25)
Type - PredefinedType: COLUMN
Material: ALG - CONSTRUCTIEF
CPset_Phasing - Renovation Phase: Bestaand
Material Properties - ALG - CONSTRUCTIEF, ThermalConductivity: 2.3; ALG - CONSTRUCTIEF, SpecificHeatCapacity: 1000 J/kg/K; ALG - CONSTRUCTIEF, MassDensity: 2300 kg/m3; ALG - CONSTRUCTIEF, Embodied Energy: 1.92 (MJ/kg); ALG - CONSTRUCTIEF, Embodied Carbon: 0.198 (kgCO₂/kg); ALG - CONSTRUCTIEF, Name: ALG - CONSTRUCTIEF; ALG - CONSTRUCTIEF, Participates in Collision Detection: yes
Pset_ColumnCommon - Slope: 90 deg; FireRating: n.v.t.; IsExternal: no; LoadBearing: yes; Reference: ALG - CONSTRUCTIEF 525 x 820
Name | In
12 x _Kolom-x | 1e verdieping N
13 x _Kolom-x | 2e verdieping V

# IfcColumn: ALG - CONSTRUCTIEF 540 x 310 (23)
Type - PredefinedType: COLUMN
Material: ALG - CONSTRUCTIEF
Pset_ColumnCommon - Slope: 90 deg; FireRating: n.v.t.; IsExternal: no; LoadBearing: yes; Reference: ALG - CONSTRUCTIEF 540 x 310
CPset_Phasing - Renovation Phase: Bestaand
Material Properties - ALG - CONSTRUCTIEF, ThermalConductivity: 2.3; ALG - CONSTRUCTIEF, SpecificHeatCapacity: 1000 J/kg/K; ALG - CONSTRUCTIEF, MassDensity: 2300 kg/m3; ALG - CONSTRUCTIEF, Embodied Energy: 1.92 (MJ/kg); ALG - CONSTRUCTIEF, Embodied Carbon: 0.198 (kgCO₂/kg); ALG - CONSTRUCTIEF, Name: ALG - CONSTRUCTIEF; ALG - CONSTRUCTIEF, Participates in Collision Detection: yes
Name | In
12 x _Kolom-x | 1e verdieping N
11 x _Kolom-x | 2e verdieping N

# IfcColumn: ALG - CONSTRUCTIEF D700 (2)
Type - PredefinedType: COLUMN
Material: ALG - CONSTRUCTIEF
Pset_ColumnCommon - Slope: 90 deg; FireRating: n.v.t.; IsExternal: no; LoadBearing: yes; Reference: ALG - CONSTRUCTIEF D700
CPset_Phasing - Renovation Phase: Bestaand
Material Properties - ALG - CONSTRUCTIEF, ThermalConductivity: 2.3; ALG - CONSTRUCTIEF, SpecificHeatCapacity: 1000 J/kg/K; ALG - CONSTRUCTIEF, MassDensity: 2300 kg/m3; ALG - CONSTRUCTIEF, Embodied Energy: 1.92 (MJ/kg); ALG - CONSTRUCTIEF, Embodied Carbon: 0.198 (kgCO₂/kg); ALG - CONSTRUCTIEF, Name: ALG - CONSTRUCTIEF; ALG - CONSTRUCTIEF, Participates in Collision Detection: yes
Name | In
_Kolom-x | 1e verdieping N
_Kolom-x | 2e verdieping N

# IfcColumn: ALG - CONSTRUCTIEF KOLOM 250 x 500 (5)
In: Begane grond N
Type - PredefinedType: COLUMN
Material: ALG - CONSTRUCTIEF KOLOM
Pset_ColumnCommon - Slope: 90 deg; FireRating: n.v.t.; IsExternal: no; LoadBearing: yes; Reference: ALG - CONSTRUCTIEF KOLOM 250 x 500
CPset_Phasing - Renovation Phase: Bestaand
Material Properties - ALG - CONSTRUCTIEF KOLOM, ThermalConductivity: 2.3; ALG - CONSTRUCTIEF KOLOM, SpecificHeatCapacity: 1000 J/kg/K; ALG - CONSTRUCTIEF KOLOM, MassDensity: 2300 kg/m3; ALG - CONSTRUCTIEF KOLOM, Embodied Energy: 1.92 (MJ/kg); ALG - CONSTRUCTIEF KOLOM, Embodied Carbon: 0.198 (kgCO₂/kg); ALG - CONSTRUCTIEF KOLOM, Name: ALG - CONSTRUCTIEF KOLOM; ALG - CONSTRUCTIEF KOLOM, Participates in Collision Detection: yes

# IfcColumn: ALG - CONSTRUCTIEF KOLOM 330 x 500, _Kolom-x
In: Begane grond N
Type - PredefinedType: COLUMN
Material: ALG - CONSTRUCTIEF KOLOM
Pset_ColumnCommon - Slope: 90 deg; FireRating: n.v.t.; IsExternal: no; LoadBearing: yes; Reference: ALG - CONSTRUCTIEF KOLOM 330 x 500
CPset_Phasing - Renovation Phase: Bestaand
Material Properties - ALG - CONSTRUCTIEF KOLOM, ThermalConductivity: 2.3; ALG - CONSTRUCTIEF KOLOM, SpecificHeatCapacity: 1000 J/kg/K; ALG - CONSTRUCTIEF KOLOM, MassDensity: 2300 kg/m3; ALG - CONSTRUCTIEF KOLOM, Embodied Energy: 1.92 (MJ/kg); ALG - CONSTRUCTIEF KOLOM, Embodied Carbon: 0.198 (kgCO₂/kg); ALG - CONSTRUCTIEF KOLOM, Name: ALG - CONSTRUCTIEF KOLOM; ALG - CONSTRUCTIEF KOLOM, Participates in Collision Detection: yes

# IfcColumn: ALG - CONSTRUCTIEF KOLOM 350 x 150, _Kolom-x
In: Begane grond N
Type - PredefinedType: COLUMN
Material: ALG - CONSTRUCTIEF KOLOM
Pset_ColumnCommon - Slope: 90 deg; FireRating: n.v.t.; IsExternal: no; LoadBearing: yes; Reference: ALG - CONSTRUCTIEF KOLOM 350 x 150
CPset_Phasing - Renovation Phase: Bestaand
Material Properties - ALG - CONSTRUCTIEF KOLOM, ThermalConductivity: 2.3; ALG - CONSTRUCTIEF KOLOM, SpecificHeatCapacity: 1000 J/kg/K; ALG - CONSTRUCTIEF KOLOM, MassDensity: 2300 kg/m3; ALG - CONSTRUCTIEF KOLOM, Embodied Energy: 1.92 (MJ/kg); ALG - CONSTRUCTIEF KOLOM, Embodied Carbon: 0.198 (kgCO₂/kg); ALG - CONSTRUCTIEF KOLOM, Name: ALG - CONSTRUCTIEF KOLOM; ALG - CONSTRUCTIEF KOLOM, Participates in Collision Detection: yes

# IfcColumn: ALG - CONSTRUCTIEF KOLOM 400 x 330 (11)
In: Begane grond N
Type - PredefinedType: COLUMN
Material: ALG - CONSTRUCTIEF KOLOM
Pset_ColumnCommon - Slope: 90 deg; FireRating: n.v.t.; IsExternal: no; LoadBearing: yes; Reference: ALG - CONSTRUCTIEF KOLOM 400 x 330
CPset_Phasing - Renovation Phase: Bestaand
Material Properties - ALG - CONSTRUCTIEF KOLOM, ThermalConductivity: 2.3; ALG - CONSTRUCTIEF KOLOM, SpecificHeatCapacity: 1000 J/kg/K; ALG - CONSTRUCTIEF KOLOM, MassDensity: 2300 kg/m3; ALG - CONSTRUCTIEF KOLOM, Embodied Energy: 1.92 (MJ/kg); ALG - CONSTRUCTIEF KOLOM, Embodied Carbon: 0.198 (kgCO₂/kg); ALG - CONSTRUCTIEF KOLOM, Name: ALG - CONSTRUCTIEF KOLOM; ALG - CONSTRUCTIEF KOLOM, Participates in Collision Detection: yes

# IfcColumn: ALG - CONSTRUCTIEF KOLOM 400 x 400 (12)
In: Begane grond N
Type - PredefinedType: COLUMN
Material: ALG - CONSTRUCTIEF KOLOM
Pset_ColumnCommon - Slope: 90 deg; FireRating: n.v.t.; IsExternal: no; LoadBearing: yes; Reference: ALG - CONSTRUCTIEF KOLOM 400 x 400
CPset_Phasing - Renovation Phase: Bestaand
Material Properties - ALG - CONSTRUCTIEF KOLOM, ThermalConductivity: 2.3; ALG - CONSTRUCTIEF KOLOM, SpecificHeatCapacity: 1000 J/kg/K; ALG - CONSTRUCTIEF KOLOM, MassDensity: 2300 kg/m3; ALG - CONSTRUCTIEF KOLOM, Embodied Energy: 1.92 (MJ/kg); ALG - CONSTRUCTIEF KOLOM, Embodied Carbon: 0.198 (kgCO₂/kg); ALG - CONSTRUCTIEF KOLOM, Name: ALG - CONSTRUCTIEF KOLOM; ALG - CONSTRUCTIEF KOLOM, Participates in Collision Detection: yes

# IfcColumn: ALG - CONSTRUCTIEF KOLOM 475 x 310, _Kolom-x
In: Begane grond N
Type - PredefinedType: COLUMN
Material: ALG - CONSTRUCTIEF KOLOM
CPset_Phasing - Renovation Phase: Bestaand
Pset_ColumnCommon - Slope: 90 deg; FireRating: n.v.t.; IsExternal: no; LoadBearing: yes; Reference: ALG - CONSTRUCTIEF KOLOM 475 x 310
Material Properties - ALG - CONSTRUCTIEF KOLOM, ThermalConductivity: 2.3; ALG - CONSTRUCTIEF KOLOM, SpecificHeatCapacity: 1000 J/kg/K; ALG - CONSTRUCTIEF KOLOM, MassDensity: 2300 kg/m3; ALG - CONSTRUCTIEF KOLOM, Embodied Energy: 1.92 (MJ/kg); ALG - CONSTRUCTIEF KOLOM, Embodied Carbon: 0.198 (kgCO₂/kg); ALG - CONSTRUCTIEF KOLOM, Name: ALG - CONSTRUCTIEF KOLOM; ALG - CONSTRUCTIEF KOLOM, Participates in Collision Detection: yes

# IfcColumn: ALG - CONSTRUCTIEF KOLOM 500 x 355 (3)
In: Begane grond N
Type - PredefinedType: COLUMN
Material: ALG - CONSTRUCTIEF KOLOM
Pset_ColumnCommon - Slope: 90 deg; FireRating: n.v.t.; IsExternal: no; LoadBearing: yes; Reference: ALG - CONSTRUCTIEF KOLOM 500 x 355
CPset_Phasing - Renovation Phase: Bestaand
Material Properties - ALG - CONSTRUCTIEF KOLOM, ThermalConductivity: 2.3; ALG - CONSTRUCTIEF KOLOM, SpecificHeatCapacity: 1000 J/kg/K; ALG - CONSTRUCTIEF KOLOM, MassDensity: 2300 kg/m3; ALG - CONSTRUCTIEF KOLOM, Embodied Energy: 1.92 (MJ/kg); ALG - CONSTRUCTIEF KOLOM, Embodied Carbon: 0.198 (kgCO₂/kg); ALG - CONSTRUCTIEF KOLOM, Name: ALG - CONSTRUCTIEF KOLOM; ALG - CONSTRUCTIEF KOLOM, Participates in Collision Detection: yes

# IfcColumn: ALG - CONSTRUCTIEF KOLOM 500 x 800, _Kolom-x
In: Begane grond N
Type - PredefinedType: COLUMN
Material: ALG - CONSTRUCTIEF KOLOM
Pset_ColumnCommon - Slope: 90 deg; FireRating: n.v.t.; IsExternal: no; LoadBearing: yes; Reference: ALG - CONSTRUCTIEF KOLOM 500 x 800
CPset_Phasing - Renovation Phase: Bestaand
Material Properties - ALG - CONSTRUCTIEF KOLOM, ThermalConductivity: 2.3; ALG - CONSTRUCTIEF KOLOM, SpecificHeatCapacity: 1000 J/kg/K; ALG - CONSTRUCTIEF KOLOM, MassDensity: 2300 kg/m3; ALG - CONSTRUCTIEF KOLOM, Embodied Energy: 1.92 (MJ/kg); ALG - CONSTRUCTIEF KOLOM, Embodied Carbon: 0.198 (kgCO₂/kg); ALG - CONSTRUCTIEF KOLOM, Name: ALG - CONSTRUCTIEF KOLOM; ALG - CONSTRUCTIEF KOLOM, Participates in Collision Detection: yes

# IfcColumn: ALG - CONSTRUCTIEF KOLOM 525 x 820 (15)
In: Begane grond N
Type - PredefinedType: COLUMN
Material: ALG - CONSTRUCTIEF KOLOM
Pset_ColumnCommon - Slope: 90 deg; FireRating: n.v.t.; IsExternal: no; LoadBearing: yes; Reference: ALG - CONSTRUCTIEF KOLOM 525 x 820
Material Properties - ALG - CONSTRUCTIEF KOLOM, ThermalConductivity: 2.3; ALG - CONSTRUCTIEF KOLOM, SpecificHeatCapacity: 1000 J/kg/K; ALG - CONSTRUCTIEF KOLOM, MassDensity: 2300 kg/m3; ALG - CONSTRUCTIEF KOLOM, Embodied Energy: 1.92 (MJ/kg); ALG - CONSTRUCTIEF KOLOM, Embodied Carbon: 0.198 (kgCO₂/kg); ALG - CONSTRUCTIEF KOLOM, Name: ALG - CONSTRUCTIEF KOLOM; ALG - CONSTRUCTIEF KOLOM, Participates in Collision Detection: yes
CPset_Phasing - Renovation Phase: Bestaand

# IfcColumn: ALG - CONSTRUCTIEF KOLOM 540 x 150 (5)
In: Begane grond N
Type - PredefinedType: COLUMN
Material: ALG - CONSTRUCTIEF KOLOM
Pset_ColumnCommon - Slope: 90 deg; FireRating: n.v.t.; IsExternal: no; LoadBearing: yes; Reference: ALG - CONSTRUCTIEF KOLOM 540 x 150
CPset_Phasing - Renovation Phase: Bestaand
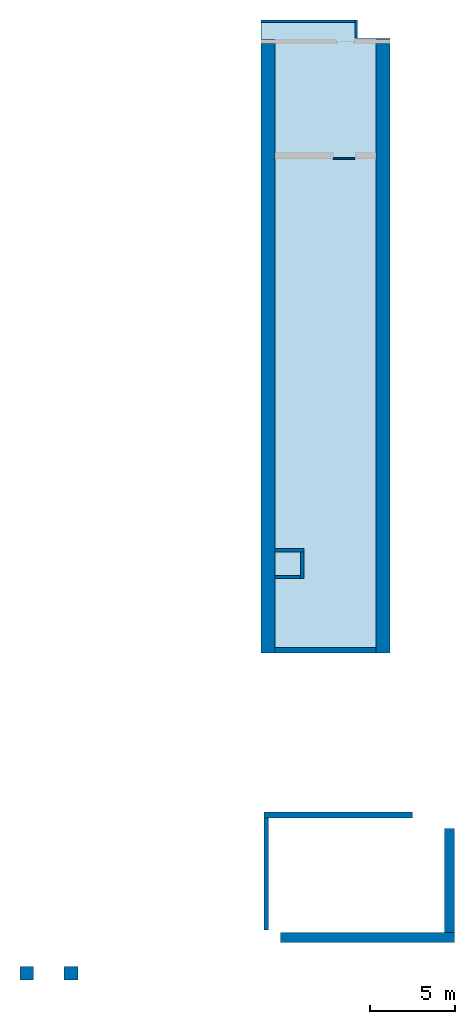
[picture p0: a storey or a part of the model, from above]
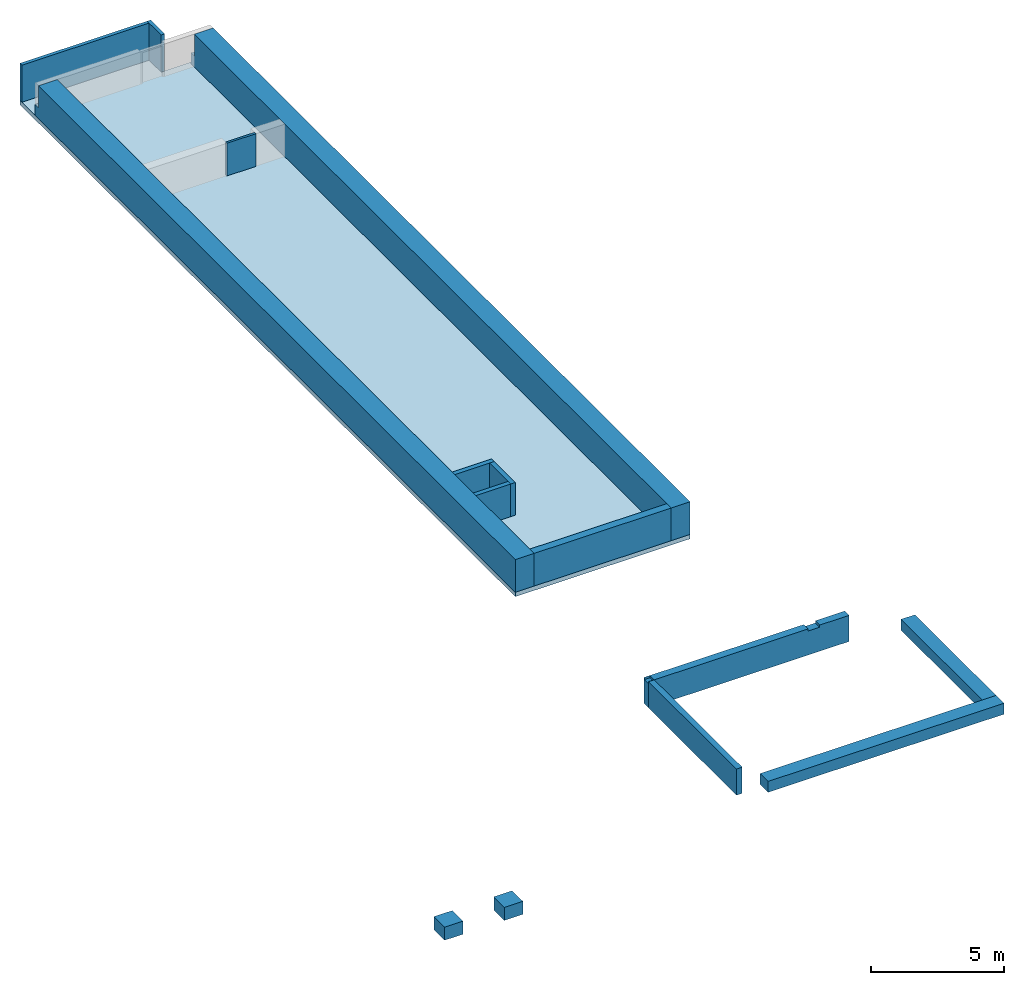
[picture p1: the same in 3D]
Properties of the parts of a building model (IFC2X3), part 3 of 7

# IfcColumn: ALG - CONSTRUCTIEF KOLOM 540 x 150 (5)
Material Properties - ALG - CONSTRUCTIEF KOLOM, ThermalConductivity: 2.3; ALG - CONSTRUCTIEF KOLOM, SpecificHeatCapacity: 1000 J/kg/K; ALG - CONSTRUCTIEF KOLOM, MassDensity: 2300 kg/m3; ALG - CONSTRUCTIEF KOLOM, Embodied Energy: 1.92 (MJ/kg); ALG - CONSTRUCTIEF KOLOM, Embodied Carbon: 0.198 (kgCO₂/kg); ALG - CONSTRUCTIEF KOLOM, Name: ALG - CONSTRUCTIEF KOLOM; ALG - CONSTRUCTIEF KOLOM, Participates in Collision Detection: yes

# IfcColumn: ALG - CONSTRUCTIEF KOLOM 540 x 275, _Kolom-x
In: Begane grond N
Type - PredefinedType: COLUMN
Material: ALG - CONSTRUCTIEF KOLOM
Pset_ColumnCommon - Slope: 90 deg; FireRating: n.v.t.; IsExternal: no; LoadBearing: yes; Reference: ALG - CONSTRUCTIEF KOLOM 540 x 275
Material Properties - ALG - CONSTRUCTIEF KOLOM, ThermalConductivity: 2.3; ALG - CONSTRUCTIEF KOLOM, SpecificHeatCapacity: 1000 J/kg/K; ALG - CONSTRUCTIEF KOLOM, MassDensity: 2300 kg/m3; ALG - CONSTRUCTIEF KOLOM, Embodied Energy: 1.92 (MJ/kg); ALG - CONSTRUCTIEF KOLOM, Embodied Carbon: 0.198 (kgCO₂/kg); ALG - CONSTRUCTIEF KOLOM, Name: ALG - CONSTRUCTIEF KOLOM; ALG - CONSTRUCTIEF KOLOM, Participates in Collision Detection: yes
CPset_Phasing - Renovation Phase: Bestaand

# IfcColumn: ALG - CONSTRUCTIEF KOLOM 540 x 310 (10)
In: Begane grond N
Type - PredefinedType: COLUMN
Material: ALG - CONSTRUCTIEF KOLOM
CPset_Phasing - Renovation Phase: Bestaand
Material Properties - ALG - CONSTRUCTIEF KOLOM, ThermalConductivity: 2.3; ALG - CONSTRUCTIEF KOLOM, SpecificHeatCapacity: 1000 J/kg/K; ALG - CONSTRUCTIEF KOLOM, MassDensity: 2300 kg/m3; ALG - CONSTRUCTIEF KOLOM, Embodied Energy: 1.92 (MJ/kg); ALG - CONSTRUCTIEF KOLOM, Embodied Carbon: 0.198 (kgCO₂/kg); ALG - CONSTRUCTIEF KOLOM, Name: ALG - CONSTRUCTIEF KOLOM; ALG - CONSTRUCTIEF KOLOM, Participates in Collision Detection: yes
Pset_ColumnCommon - Slope: 90 deg; FireRating: n.v.t.; IsExternal: no; LoadBearing: yes; Reference: ALG - CONSTRUCTIEF KOLOM 540 x 310

# IfcColumn: ALG - CONSTRUCTIEF KOLOM 540 x 330, _Kolom-x
In: Begane grond N
Type - PredefinedType: COLUMN
Material: ALG - CONSTRUCTIEF KOLOM
Material Properties - ALG - CONSTRUCTIEF KOLOM, ThermalConductivity: 2.3; ALG - CONSTRUCTIEF KOLOM, SpecificHeatCapacity: 1000 J/kg/K; ALG - CONSTRUCTIEF KOLOM, MassDensity: 2300 kg/m3; ALG - CONSTRUCTIEF KOLOM, Embodied Energy: 1.92 (MJ/kg); ALG - CONSTRUCTIEF KOLOM, Embodied Carbon: 0.198 (kgCO₂/kg); ALG - CONSTRUCTIEF KOLOM, Name: ALG - CONSTRUCTIEF KOLOM; ALG - CONSTRUCTIEF KOLOM, Participates in Collision Detection: yes
Pset_ColumnCommon - Slope: 90 deg; FireRating: n.v.t.; IsExternal: no; LoadBearing: yes; Reference: ALG - CONSTRUCTIEF KOLOM 540 x 330
CPset_Phasing - Renovation Phase: Bestaand

# IfcColumn: ALG - CONSTRUCTIEF KOLOM 770 x 225 (2)
In: Begane grond N
Type - PredefinedType: COLUMN
Material: ALG - CONSTRUCTIEF KOLOM
Pset_ColumnCommon - Slope: 90 deg; FireRating: n.v.t.; IsExternal: no; LoadBearing: yes; Reference: ALG - CONSTRUCTIEF KOLOM 770 x 225
CPset_Phasing - Renovation Phase: Bestaand
Material Properties - ALG - CONSTRUCTIEF KOLOM, ThermalConductivity: 2.3; ALG - CONSTRUCTIEF KOLOM, SpecificHeatCapacity: 1000 J/kg/K; ALG - CONSTRUCTIEF KOLOM, MassDensity: 2300 kg/m3; ALG - CONSTRUCTIEF KOLOM, Embodied Energy: 1.92 (MJ/kg); ALG - CONSTRUCTIEF KOLOM, Embodied Carbon: 0.198 (kgCO₂/kg); ALG - CONSTRUCTIEF KOLOM, Name: ALG - CONSTRUCTIEF KOLOM; ALG - CONSTRUCTIEF KOLOM, Participates in Collision Detection: yes

# IfcColumn: ALG - CONSTRUCTIEF KOLOM D700, _Kolom-x
In: Begane grond N
Type - PredefinedType: COLUMN
Material: ALG - CONSTRUCTIEF KOLOM
CPset_Phasing - Renovation Phase: Bestaand
Material Properties - ALG - CONSTRUCTIEF KOLOM, ThermalConductivity: 2.3; ALG - CONSTRUCTIEF KOLOM, SpecificHeatCapacity: 1000 J/kg/K; ALG - CONSTRUCTIEF KOLOM, MassDensity: 2300 kg/m3; ALG - CONSTRUCTIEF KOLOM, Embodied Energy: 1.92 (MJ/kg); ALG - CONSTRUCTIEF KOLOM, Embodied Carbon: 0.198 (kgCO₂/kg); ALG - CONSTRUCTIEF KOLOM, Name: ALG - CONSTRUCTIEF KOLOM; ALG - CONSTRUCTIEF KOLOM, Participates in Collision Detection: yes
Pset_ColumnCommon - Slope: 90 deg; FireRating: n.v.t.; IsExternal: no; LoadBearing: yes; Reference: ALG - CONSTRUCTIEF KOLOM D700

# IfcColumn: Hout C 46 x 146 (19)
In: 2e verdieping N
Type - PredefinedType: COLUMN
Material: Hout C
Material Properties - Hout C, ThermalConductivity: 0.14; Hout C, SpecificHeatCapacity: 1880 J/kg/K; Hout C, MassDensity: 550 kg/m3; Hout C, Embodied Energy: 7.4 (MJ/kg); Hout C, Embodied Carbon: 0.19 (kgCO₂/kg); Hout C, Name: Hout C; Hout C, Participates in Collision Detection: yes
CPset_Phasing - Renovation Phase: Nieuw
Pset_ColumnCommon - Slope: 90 deg; FireRating: n.v.t.; IsExternal: no; LoadBearing: yes; Reference: Hout C 46 x 146

# IfcColumn: Kolom r80mm1:Kolom r80mm, Kolom r80mm1:Kolom r80mm:2989662
In: 1e verdieping N
Type - PredefinedType: COLUMN
Material: staal geanodiseerd RAL 7024
Pset_ReinforcementBarPitchOfColumn - Reference: Kolom r80mm; sets with these values: 2
Pset_ColumnCommon - Reference: Kolom r80mm; Slope: 90 deg; IsExternal: no; LoadBearing: yes
CPset_Phasing - Renovation Phase: Nieuw
Material Properties - staal geanodiseerd RAL 7024, ThermalConductivity: 2.3; staal geanodiseerd RAL 7024, SpecificHeatCapacity: 1000 J/kg/K; staal geanodiseerd RAL 7024, MassDensity: 2300 kg/m3; staal geanodiseerd RAL 7024, Embodied Energy: 1.92 (MJ/kg); staal geanodiseerd RAL 7024, Embodied Carbon: 0.198 (kgCO₂/kg); staal geanodiseerd RAL 7024, Name: staal geanodiseerd RAL 7024; staal geanodiseerd RAL 7024, Participates in Collision Detection: yes

# IfcColumn: Kolom r80mm:Kolom r80mm, Kolom r80mm:Kolom r80mm:2989587
In: 1e verdieping N
Type - PredefinedType: COLUMN
Material: staal geanodiseerd RAL 7024
Pset_ReinforcementBarPitchOfColumn - Reference: Kolom r80mm; sets with these values: 2
Pset_ColumnCommon - Reference: Kolom r80mm; Slope: 90 deg; IsExternal: no; LoadBearing: yes
CPset_Phasing - Renovation Phase: Nieuw
Material Properties - staal geanodiseerd RAL 7024, ThermalConductivity: 2.3; staal geanodiseerd RAL 7024, SpecificHeatCapacity: 1000 J/kg/K; staal geanodiseerd RAL 7024, MassDensity: 2300 kg/m3; staal geanodiseerd RAL 7024, Embodied Energy: 1.92 (MJ/kg); staal geanodiseerd RAL 7024, Embodied Carbon: 0.198 (kgCO₂/kg); staal geanodiseerd RAL 7024, Name: staal geanodiseerd RAL 7024; staal geanodiseerd RAL 7024, Participates in Collision Detection: yes

# IfcColumn: Metaal - Staal C 90 x 44 (741)
Type - PredefinedType: COLUMN
Material: Metaal - Staal C
Pset_ColumnCommon - Slope: 90 deg; FireRating: n.v.t.; IsExternal: no; LoadBearing: yes; Reference: Metaal - Staal C 90 x 44
CPset_Phasing - Renovation Phase: Nieuw
Material Properties - Metaal - Staal C, ThermalConductivity: 52; Metaal - Staal C, SpecificHeatCapacity: 530 J/kg/K; Metaal - Staal C, MassDensity: 7950 kg/m3; Metaal - Staal C, Embodied Energy: 25 (MJ/kg); Metaal - Staal C, Embodied Carbon: 1.91 (kgCO₂/kg); Metaal - Staal C, Name: Metaal - Staal C; Metaal - Staal C, Participates in Collision Detection: yes
Name | In
282 x _Kolom-x | Begane grond N
272 x _Kolom-x | 1e verdieping N
187 x _Kolom-x | 2e verdieping N

# IfcColumn: NLRS_28_SCO_staal - kolom - HEB:HE300B (33)
Type - PredefinedType: COLUMN
Material: staal geanodiseerd RAL 7024
CPset_Phasing - Renovation Phase: Nieuw
Material Properties - staal geanodiseerd RAL 7024, ThermalConductivity: 2.3; staal geanodiseerd RAL 7024, SpecificHeatCapacity: 1000 J/kg/K; staal geanodiseerd RAL 7024, MassDensity: 2300 kg/m3; staal geanodiseerd RAL 7024, Embodied Energy: 1.92 (MJ/kg); staal geanodiseerd RAL 7024, Embodied Carbon: 0.198 (kgCO₂/kg); staal geanodiseerd RAL 7024, Name: staal geanodiseerd RAL 7024; staal geanodiseerd RAL 7024, Participates in Collision Detection: yes
Pset_ColumnCommon - Reference: HE300B; Slope: 90 deg; IsExternal: no; LoadBearing: yes
Name (NLRS_28_SCO_staal - kolom - HEB:HE300B:...) | In | Pset_ReinforcementBarPitchOfColumn, Reference | Pset_ReinforcementBarPitchOfColumn, sets with these values
3021381 | 2e verdieping N | HE300B | 2
2 x 3021251 | 2e verdieping N | HE300B | 2
3021323 | 2e verdieping N | HE300B | 2
2974208 | 2e verdieping N | HE300B | 2
2974102 | 2e verdieping N | HE300B | 2
2973033 | 2e verdieping N | HE300B | 2
2974153 | 2e verdieping N | HE300B | 2
2972654 | 2e verdieping N | Pset_QuantityTakeOff - Reference: HE300B; sets with these values: 2
3167840 | 2e verdieping N | Pset_QuantityTakeOff - Reference: HE300B; sets with these values: 2
3027965 | 2e verdieping N | HE300B | 2
3026742 | 2e verdieping N | HE300B | 2
3026877 | 2e verdieping N | HE300B | 2
2972907 | 2e verdieping V | HE300B | 2
2973477 | 2e verdieping V | HE300B | 2
2972294 | 2e verdieping V | Pset_QuantityTakeOff - Reference: HE300B; sets with these values: 2; Group: Model Group:BUITENRUIMTE helft:2972320
2973229 | 2e verdieping V | Pset_QuantityTakeOff - Reference: HE300B; sets with these values: 2
2972321 | 2e verdieping V | HE300B | 2 | Group: Model Group:BUITENRUIMTE helft:2972347
2973036 | 3e verdieping/dak N | HE300B | 2
2972721 | 3e verdieping/dak N | HE300B | 2
2973291 | 3e verdieping/dak N | HE300B | 2
2972020 | 3e verdieping/dak N | Pset_QuantityTakeOff - Reference: HE300B; sets with these values: 2; Group: Model Group:BUITENRUIMTE helft:2972046
2971993 | 3e verdieping/dak N | HE300B | 2 | Group: Model Group:BUITENRUIMTE helft:2972019
2972101 | 3e verdieping V | HE300B | 2
2972047 | 3e verdieping V | HE300B | 2 | Group: Model Group:BUITENRUIMTE helft:2972073
2973034 | 3e verdieping V | HE300B | 2
2972074 | 3e verdieping V | HE300B | 2 | Group: Model Group:BUITENRUIMTE helft:2972100
2973289 | 3e verdieping V | Pset_QuantityTakeOff - Reference: HE300B; sets with these values: 2
2971939 | 4e verdieping V | HE300B | 2 | Group: Model Group:BUITENRUIMTE helft:2971965
2973035 | 4e verdieping V | Pset_QuantityTakeOff - Reference: HE300B; sets with these values: 2
2973290 | 4e verdieping V | HE300B | 2
2972720 | 4e verdieping V | Pset_QuantityTakeOff - Reference: HE300B; sets with these values: 2
2971966 | 4e verdieping V | HE300B | 2 | Group: Model Group:BUITENRUIMTE helft:2971992

# IfcColumn: NLRS_28_SC_LIB_kolom recht_generiek_ISR:kolom staal_gen (12)
In: 5e verdieping V
Type - PredefinedType: COLUMN
Material: 00_Staal_generiek wit
Pset_ColumnCommon - Reference: kolom staal_gen; Slope: 90 deg; IsExternal: no; LoadBearing: yes
CPset_Phasing - Renovation Phase: Nieuw
Material Properties - 00_Staal_generiek wit, ThermalConductivity: 2.3; 00_Staal_generiek wit, SpecificHeatCapacity: 1000 J/kg/K; 00_Staal_generiek wit, MassDensity: 2300 kg/m3; 00_Staal_generiek wit, Embodied Energy: 1.92 (MJ/kg); 00_Staal_generiek wit, Embodied Carbon: 0.198 (kgCO₂/kg); 00_Staal_generiek wit, Name: 00_Staal_generiek wit; 00_Staal_generiek wit, Participates in Collision Detection: yes
Name (NLRS_28_SC_LIB_kolom recht_generiek_ISR:kolom staal_gen:...) | Pset_ReinforcementBarPitchOfColumn, Reference | Pset_ReinforcementBarPitchOfColumn, sets with these values
2546379 | kolom staal_gen | 2
2562121 | kolom staal_gen | 2
2562119 | Pset_QuantityTakeOff - Reference: kolom staal_gen; sets with these values: 2
2560163 | kolom staal_gen | 2
2560381 | kolom staal_gen | 2
2560324 | kolom staal_gen | 2
2560383 | kolom staal_gen | 2
2560303 | Pset_QuantityTakeOff - Reference: kolom staal_gen; sets with these values: 2
2560260 | Pset_QuantityTakeOff - Reference: kolom staal_gen; sets with these values: 2
2560385 | kolom staal_gen | 2
2560387 | kolom staal_gen | 2
2560389 | Pset_QuantityTakeOff - Reference: kolom staal_gen; sets with these values: 2

# IfcCovering: Compound Ceiling:47_3B_plafond gips 2 platen, Compound Ceiling:47_3B_plafond gips 2 platen:2730408
In: 1e verdieping N
Type - PredefinedType: CEILING
Type - Pset_CoveringCommon - TotalThickness: 25 mm
Material: IFC Building Material
Pset_QuantityTakeOff - Reference: 47_3B_plafond gips 2 platen
Pset_CoveringCommon - Reference: 47_3B_plafond gips 2 platen; Finish: plafond_gips;; Material: Lege arcering (01)
CPset_Phasing - Renovation Phase: Nieuw
Material Properties - IFC Building Material, ThermalConductivity: 2.3; IFC Building Material, SpecificHeatCapacity: 1000 J/kg/K; IFC Building Material, MassDensity: 2300 kg/m3; IFC Building Material, Embodied Energy: 1.92 (MJ/kg); IFC Building Material, Embodied Carbon: 0.198 (kgCO₂/kg); IFC Building Material, Name: IFC Building Material; IFC Building Material, Participates in Collision Detection: yes

# IfcCovering: Compound Ceiling:47_3B_plafond wvm WIT (9)
Type - PredefinedType: CEILING
Type - Pset_CoveringCommon - TotalThickness: 12 mm
Material: IFC Building Material
Pset_QuantityTakeOff - Reference: 47_3B_plafond wvm WIT
Pset_CoveringCommon - Reference: 47_3B_plafond wvm WIT; Finish: Multiplex wit geschilderd;; Material: Lege arcering (01)
CPset_Phasing - Renovation Phase: Nieuw
Material Properties - IFC Building Material, ThermalConductivity: 2.3; IFC Building Material, SpecificHeatCapacity: 1000 J/kg/K; IFC Building Material, MassDensity: 2300 kg/m3; IFC Building Material, Embodied Energy: 1.92 (MJ/kg); IFC Building Material, Embodied Carbon: 0.198 (kgCO₂/kg); IFC Building Material, Name: IFC Building Material; IFC Building Material, Participates in Collision Detection: yes
Name (Compound Ceiling:47_3B_plafond wvm WIT:...) | In | Group
2972687 | 3e verdieping/dak N | Model Group:BUITENRUIMTE helft:2972046
2972680 | 3e verdieping/dak N | Model Group:BUITENRUIMTE helft:2972019
2972694 | 3e verdieping V | Model Group:BUITENRUIMTE helft:2972073
2972701 | 3e verdieping V | Model Group:BUITENRUIMTE helft:2972100
3148389 | 4e verdieping V | Model Group:luifel penthouse:3148164
2972665 | 4e verdieping V | Model Group:BUITENRUIMTE helft:2971992
2972673 | 4e verdieping V | Model Group:BUITENRUIMTE helft:2971965
2973021 | 5e verdieping V
2973028 | 5e verdieping V

# IfcCurtainWall: Curtain Wall:21_CW_alu kozijn 070x065 (47)
Pset_QuantityTakeOff - Reference: 21_CW_alu kozijn 070x065
Pset_CurtainWallCommon - IsExternal: yes; Reference: 21_CW_alu kozijn 070x065
Name (Curtain Wall:21_CW_alu kozijn 070x065:...) | In | Group
2039380 | 1e verdieping N | Model Group:V-koz-M nieuw 2:2039391
2039354 | 1e verdieping N | Model Group:V-koz-M nieuw 2:2039379
2947045 | 1e verdieping N
2815514 | 1e verdieping N
3088430 | 1e verdieping N
2728845 | 1e verdieping N
2726616 | 1e verdieping N
3142361 | 1e verdieping N | Model Group:KOZ-03:3142360
3140550 | 1e verdieping N | Model Group:KOZ-03:3140556
2039108 | 2e verdieping N | Model Group:V-koz-M nieuw 2:2039133
2039134 | 2e verdieping N | Model Group:V-koz-M nieuw 2:2039145
3140558 | 2e verdieping N | Model Group:KOZ-03:3140557
3088416 | 2e verdieping N | Model Group:KOZ-03:3087227
2765754 | 2e verdieping V | Model Group:KOZ-03:2767540
3140522 | 2e verdieping V | Model Group:KOZ-03:3140528
2013389 | 2e verdieping V | Model Group:V-koz-M nieuw 2:2013400
2013363 | 2e verdieping V | Model Group:V-koz-M nieuw 2:2013388
2013459 | 3e verdieping/dak N | Model Group:V-koz-M nieuw 2:2013470
2767560 | 3e verdieping/dak N | Model Group:KOZ-03:2767569
2013433 | 3e verdieping/dak N | Model Group:V-koz-M nieuw 2:2013458
3140529 | 3e verdieping/dak N | Model Group:KOZ-03:3140535
2013630 | 3e verdieping V | Model Group:V-koz-M nieuw 2:2013655
2013656 | 3e verdieping V | Model Group:V-koz-M nieuw 2:2013667
3140536 | 3e verdieping V | Model Group:KOZ-03:3140542
2767578 | 3e verdieping V | Model Group:KOZ-03:2767587
2999300 | 5e verdieping V
2538973 | 5e verdieping V
2540323 | 5e verdieping V
3094151 | 5e verdieping V
3094180 | 5e verdieping V
3140909 | 5e verdieping V | Model Group:V vluchttrappenhuis V5:3080963
3140740 | 5e verdieping V | Model Group:V vluchttrappenhuis V5:3080963
2759490 | 5e verdieping V
3089618 | 5e verdieping V
2557569 | 5e verdieping V | Model Group:V-koz-N nieuw:2557585
2561723 | 5e verdieping V
3081058 | 5e verdieping V | Model Group:V vluchttrappenhuis V5:3080963
3081076 | 5e verdieping V | Model Group:V vluchttrappenhuis V5:3080963
2772138 | 5e verdieping V
2772172 | 5e verdieping V
2550081 | 5e verdieping V
3084842 | 5e verdieping V | Model Group:V vluchttrappenhuis V5:3080963
2542067 | 5e verdieping V
3085498 | 4e verdieping V | Model Group:V-koz-M nieuw 2:3085515
3085516 | 4e verdieping V | Model Group:V-koz-M nieuw 2:3085520
2767612 | 4e verdieping V | Model Group:KOZ-03:2767621
3140543 | 4e verdieping V | Model Group:KOZ-03:3140549

# IfcCurtainWall: Curtain Wall:21_CW_alu kozijn 084x065 (10)
In: 2e verdieping N
Pset_QuantityTakeOff - Reference: 21_CW_alu kozijn 084x065
Pset_CurtainWallCommon - IsExternal: yes; Reference: 21_CW_alu kozijn 084x065
Name (Curtain Wall:21_CW_alu kozijn 084x065:...)
3024871
3024069
3024353
3024322
3026228
3168168
2973606
2974187
3108137
3104775

# IfcDoor: 31_DO_deur_BI_glas:deur (2)
In: 5e verdieping V
Type - ParameterTakesPrecedence: no; Sizeable: no
Material: Glass
Pset_QuantityTakeOff - Reference: deur
CPset_Phasing - Renovation Phase: Nieuw
Material Properties - Glass, ThermalConductivity: 2.3; Glass, SpecificHeatCapacity: 1000 J/kg/K; Glass, MassDensity: 2300 kg/m3; Glass, Embodied Energy: 1.92 (MJ/kg); Glass, Embodied Carbon: 0.198 (kgCO₂/kg); Glass, Name: Glass; Glass, Participates in Collision Detection: yes
Pset_DoorCommon - Reference: deur; IsExternal: yes
Name (31_DO_deur_BI_glas:deur:...)
2539070
2561730

# IfcDoor: 31_DO_stolpdeur_1:0std (4)
In: 2e verdieping N
Type - ParameterTakesPrecedence: no; Sizeable: no
Pset_QuantityTakeOff - Reference: 0std
Pset_DoorCommon - Reference: 0std; IsExternal: yes
CPset_Phasing - Renovation Phase: Nieuw
Name (31_DO_stolpdeur_1:0std:...) | Material | RAL 7024 - Grafietgrijs, ThermalConductivity | RAL 7024 - Grafietgrijs, SpecificHeatCapacity (J/kg/K) | RAL 7024 - Grafietgrijs, MassDensity (kg/m3) | RAL 7024 - Grafietgrijs, Embodied Energy | RAL 7024 - Grafietgrijs, Embodied Carbon | RAL 7024 - Grafietgrijs, Name | RAL 7024 - Grafietgrijs, Participates in Collision Detection
3024076 | RAL 7024 - Grafietgrijs | 2.3 | 1000 | 2300 | 1.92 (MJ/kg) | 0.198 (kgCO₂/kg) | RAL 7024 - Grafietgrijs | yes
3024360 | RAL 7024 - Grafietgrijs | 2.3 | 1000 | 2300 | 1.92 (MJ/kg) | 0.198 (kgCO₂/kg) | RAL 7024 - Grafietgrijs | yes
3027120 | IFC Building Material | Material Properties - IFC Building Material, ThermalConductivity: 2.3; IFC Building Material, SpecificHeatCapacity: 1000 J/kg/K; IFC Building Material, MassDensity: 2300 kg/m3; IFC Building Material, Embodied Energy: 1.92 (MJ/kg); IFC Building Material, Embodied Carbon: 0.198 (kgCO₂/kg); IFC Building Material, Name: IFC Building Material; IFC Building Material, Participates in Collision Detection: yes
3021903 | RAL 7024 - Grafietgrijs | 2.3 | 1000 | 2300 | 1.92 (MJ/kg) | 0.198 (kgCO₂/kg) | RAL 7024 - Grafietgrijs | yes

# IfcDoor: 31_DO_stolpdeur_1:alu deur, 31_DO_stolpdeur_1:alu deur:2759491
In: 5e verdieping V
Type - ParameterTakesPrecedence: no; Sizeable: no
Material: IFC Building Material
Pset_DoorCommon - Reference: alu deur; IsExternal: yes
Pset_QuantityTakeOff - Reference: alu deur
CPset_Phasing - Renovation Phase: Nieuw
Material Properties - IFC Building Material, ThermalConductivity: 2.3; IFC Building Material, SpecificHeatCapacity: 1000 J/kg/K; IFC Building Material, MassDensity: 2300 kg/m3; IFC Building Material, Embodied Energy: 1.92 (MJ/kg); IFC Building Material, Embodied Carbon: 0.198 (kgCO₂/kg); IFC Building Material, Name: IFC Building Material; IFC Building Material, Participates in Collision Detection: yes

# IfcDoor: D1 26, _Merk-007
In: 2e verdieping N
Type - OperationType: SINGLE_SWING_LEFT; ParameterTakesPrecedence: no; Sizeable: no
Type - Door Lining Properties - LiningDepth: 114 mm; LiningThickness: 67 mm; LiningOffset: -114 mm
Type - Door Panel Properties - Panel 1 - PanelDepth: 40 mm; PanelOperation: SWINGING; PanelWidth: 1; PanelPosition: MIDDLE
OverallHeight: 2400 mm; OverallWidth: 1030 mm
Pset_DoorCommon - FireRating: n.v.t.; SecurityRating: FALSE; ThermalTransmittance: 0; GlazingAreaFraction: 1.4938; FireExit: no; SelfClosing: no; SmokeStop: no; IsExternal: no
Pset_FireRatingProperties - FireResistanceRating: Zelfsluitend
Material - Frame / Draaiend deel: n.v.t.; Deurblad: n.v.t.; Onderdorpel: n.v.t.; Stofdorpel: n.v.t.; Vensterbank: n.v.t.; Ventilatierooster: n.v.t.; Spouwlat: n.v.t.; Rollaag / Latei: n.v.t.; Afwerking dagkant buiten: n.v.t.; Afwerking dagkant binnen: n.v.t.; Zonwering - behuizing: n.v.t.; Zonwering - isolatie: n.v.t.; Glas: Glas - algemeen
CPset_Phasing - Renovation Phase: Nieuw

# IfcDoor: D1 26 (2)
Type - OperationType: SINGLE_SWING_LEFT; ParameterTakesPrecedence: no; Sizeable: no
Type - Door Lining Properties - LiningDepth: 114 mm; LiningThickness: 67 mm; LiningOffset: -184 mm
Type - Door Panel Properties - Panel 1 - PanelDepth: 40 mm; PanelOperation: SWINGING; PanelWidth: 1; PanelPosition: MIDDLE
OverallHeight: 2400 mm; OverallWidth: 1030 mm
Pset_DoorCommon - FireRating: n.v.t.; SecurityRating: FALSE; ThermalTransmittance: 0; GlazingAreaFraction: 1.4938; FireExit: no; SelfClosing: no; SmokeStop: no; IsExternal: no
Material - Frame / Draaiend deel: n.v.t.; Deurblad: n.v.t.; Onderdorpel: n.v.t.; Stofdorpel: n.v.t.; Vensterbank: n.v.t.; Ventilatierooster: n.v.t.; Spouwlat: n.v.t.; Rollaag / Latei: n.v.t.; Afwerking dagkant buiten: n.v.t.; Afwerking dagkant binnen: n.v.t.; Zonwering - behuizing: n.v.t.; Zonwering - isolatie: n.v.t.; Glas: Glas - algemeen
Pset_FireRatingProperties - FireResistanceRating: Zelfsluitend
CPset_Phasing - Renovation Phase: Nieuw
Name | In
_Merk-007 | Begane grond N
_Merk-007 | 1e verdieping N

# IfcDoor: D1 26, _Merk-008
In: Begane grond N
Type - OperationType: SINGLE_SWING_LEFT; ParameterTakesPrecedence: no; Sizeable: no
Type - Door Lining Properties - LiningDepth: 114 mm; LiningThickness: 67 mm; LiningOffset: -64 mm
Type - Door Panel Properties - Panel 1 - PanelDepth: 40 mm; PanelOperation: SWINGING; PanelWidth: 1; PanelPosition: MIDDLE
OverallHeight: 2400 mm; OverallWidth: 1030 mm
Pset_DoorCommon - FireRating: n.v.t.; SecurityRating: FALSE; ThermalTransmittance: 0; FireExit: no; SelfClosing: no; SmokeStop: no; IsExternal: no
Material - Frame / Draaiend deel: n.v.t.; Deurblad: n.v.t.; Onderdorpel: n.v.t.; Stofdorpel: n.v.t.; Vensterbank: n.v.t.; Ventilatierooster: n.v.t.; Spouwlat: n.v.t.; Rollaag / Latei: n.v.t.; Afwerking dagkant buiten: n.v.t.; Afwerking dagkant binnen: n.v.t.; Zonwering - behuizing: n.v.t.; Zonwering - isolatie: n.v.t.; Glas: Glas - algemeen
Pset_FireRatingProperties - FireResistanceRating: Zelfsluitend
CPset_Phasing - Renovation Phase: Nieuw

# IfcDoor: D1 26, _Merk-x
In: 6e verdieping V
Type - OperationType: SINGLE_SWING_LEFT; ParameterTakesPrecedence: no; Sizeable: no
Type - Door Lining Properties - LiningDepth: 114 mm; LiningThickness: 67 mm; LiningOffset: 11 mm
Type - Door Panel Properties - Panel 1 - PanelDepth: 40 mm; PanelOperation: SWINGING; PanelWidth: 1; PanelPosition: MIDDLE
OverallHeight: 2100 mm; OverallWidth: 1000 mm
Material - Frame / Draaiend deel: n.v.t.; Deurblad: n.v.t.; Onderdorpel: n.v.t.; Stofdorpel: n.v.t.; Vensterbank: n.v.t.; Ventilatierooster: n.v.t.; Spouwlat: n.v.t.; Rollaag / Latei: n.v.t.; Afwerking dagkant buiten: n.v.t.; Afwerking dagkant binnen: n.v.t.; Zonwering - behuizing: n.v.t.; Zonwering - isolatie: n.v.t.; Glas: Glas - algemeen
CPset_Phasing - Renovation Phase: Bestaand
Pset_DoorCommon - FireRating: n.v.t.; SecurityRating: FALSE; ThermalTransmittance: 0; FireExit: no; SelfClosing: no; SmokeStop: no; IsExternal: no

# IfcDoor: D1 26 (4)
Type - OperationType: SINGLE_SWING_RIGHT; ParameterTakesPrecedence: no; Sizeable: no
Type - Door Lining Properties - LiningDepth: 114 mm; LiningThickness: 67 mm; LiningOffset: -114 mm
Type - Door Panel Properties - Panel 1 - PanelDepth: 40 mm; PanelOperation: SWINGING; PanelWidth: 1; PanelPosition: MIDDLE
OverallHeight: 2100 mm; OverallWidth: 1000 mm
Pset_DoorCommon - FireRating: n.v.t.; SecurityRating: FALSE; ThermalTransmittance: 0; GlazingAreaFraction: 1.2136; FireExit: no; SelfClosing: no; SmokeStop: no; IsExternal: no
Material - Frame / Draaiend deel: n.v.t.; Deurblad: n.v.t.; Onderdorpel: n.v.t.; Stofdorpel: n.v.t.; Vensterbank: n.v.t.; Ventilatierooster: n.v.t.; Spouwlat: n.v.t.; Rollaag / Latei: n.v.t.; Afwerking dagkant buiten: n.v.t.; Afwerking dagkant binnen: n.v.t.; Zonwering - behuizing: n.v.t.; Zonwering - isolatie: n.v.t.; Glas: Glas - algemeen
CPset_Phasing - Renovation Phase: Bestaand
Name | In
_Merk-x | 2e verdieping V
_Merk-x | 3e verdieping V
_Merk-x | 4e verdieping V
_Merk-x | 5e verdieping V

# IfcDoor: D1 26, _Merk-x
In: 3e verdieping/dak N
Type - OperationType: SINGLE_SWING_RIGHT; ParameterTakesPrecedence: no; Sizeable: no
Type - Door Lining Properties - LiningDepth: 114 mm; LiningThickness: 67 mm; LiningOffset: -200 mm
Type - Door Panel Properties - Panel 1 - PanelDepth: 40 mm; PanelOperation: SWINGING; PanelWidth: 1; PanelPosition: MIDDLE
OverallHeight: 2100 mm; OverallWidth: 1000 mm
Pset_DoorCommon - FireRating: n.v.t.; SecurityRating: FALSE; ThermalTransmittance: 0; FireExit: no; SelfClosing: no; SmokeStop: no; IsExternal: no
Material - Frame / Draaiend deel: n.v.t.; Deurblad: n.v.t.; Onderdorpel: n.v.t.; Stofdorpel: n.v.t.; Vensterbank: n.v.t.; Ventilatierooster: n.v.t.; Spouwlat: n.v.t.; Rollaag / Latei: n.v.t.; Afwerking dagkant buiten: n.v.t.; Afwerking dagkant binnen: n.v.t.; Zonwering - behuizing: n.v.t.; Zonwering - isolatie: n.v.t.; Glas: Glas - algemeen
CPset_Phasing - Renovation Phase: Bestaand

# IfcDoor: D1 27 (2)
Type - OperationType: SINGLE_SWING_LEFT; ParameterTakesPrecedence: no; Sizeable: no
Type - Door Lining Properties - LiningDepth: 114 mm; LiningThickness: 67 mm; LiningOffset: -100 mm
Type - Door Panel Properties - Panel 1 - PanelDepth: 40 mm; PanelOperation: SWINGING; PanelWidth: 1; PanelPosition: MIDDLE
OverallHeight: 2400 mm; OverallWidth: 1034 mm
Pset_DoorCommon - FireRating: n.v.t.; SecurityRating: FALSE; ThermalTransmittance: 0; FireExit: no; SelfClosing: no; SmokeStop: no; IsExternal: no
Material - Frame / Draaiend deel: n.v.t.; Deurblad: n.v.t.; Onderdorpel: n.v.t.; Stofdorpel: n.v.t.; Vensterbank: n.v.t.; Ventilatierooster: n.v.t.; Spouwlat: n.v.t.; Rollaag / Latei: n.v.t.; Afwerking dagkant buiten: n.v.t.; Afwerking dagkant binnen: n.v.t.; Zonwering - behuizing: n.v.t.; Zonwering - isolatie: n.v.t.; Glas: Glas - algemeen
CPset_Phasing - Renovation Phase: Nieuw
Name | In
_Merk-x | Begane grond N
_Merk-x | 1e verdieping N

# IfcDoor: D1 27 (9)
Type - OperationType: SINGLE_SWING_LEFT; ParameterTakesPrecedence: no; Sizeable: no
Type - Door Lining Properties - LiningDepth: 114 mm; LiningThickness: 67 mm; LiningOffset: -107 mm
Type - Door Panel Properties - Panel 1 - PanelDepth: 40 mm; PanelOperation: SWINGING; PanelWidth: 1; PanelPosition: MIDDLE
Pset_DoorCommon - FireRating: n.v.t.; SecurityRating: FALSE; ThermalTransmittance: 0; FireExit: no; SelfClosing: no; SmokeStop: no; IsExternal: no
Material - Frame / Draaiend deel: n.v.t.; Deurblad: n.v.t.; Onderdorpel: n.v.t.; Stofdorpel: n.v.t.; Vensterbank: n.v.t.; Ventilatierooster: n.v.t.; Spouwlat: n.v.t.; Rollaag / Latei: n.v.t.; Afwerking dagkant buiten: n.v.t.; Afwerking dagkant binnen: n.v.t.; Zonwering - behuizing: n.v.t.; Zonwering - isolatie: n.v.t.; Glas: Glas - algemeen
CPset_Phasing - Renovation Phase: Nieuw
Name | In | OverallHeight (mm) | OverallWidth (mm)
2 x _Merk-x | Begane grond N | 2100 | 1034
2 x _Merk-x | Begane grond N | 2400 | 1034
_Merk-x | 1e verdieping N | 2400 | 934
2 x _Merk-x | 1e verdieping N | 2400 | 1034
2 x _Merk-x | 2e verdieping N | 2400 | 934

# IfcDoor: D1 27 (4)
Type - OperationType: SINGLE_SWING_LEFT; ParameterTakesPrecedence: no; Sizeable: no
Type - Door Lining Properties - LiningDepth: 114 mm; LiningThickness: 67 mm; LiningOffset: -114 mm
Type - Door Panel Properties - Panel 1 - PanelDepth: 40 mm; PanelOperation: SWINGING; PanelWidth: 1; PanelPosition: MIDDLE
OverallHeight: 2100 mm
Pset_DoorCommon - FireRating: n.v.t.; SecurityRating: FALSE; ThermalTransmittance: 0; FireExit: no; SelfClosing: no; SmokeStop: no; IsExternal: no
Material - Frame / Draaiend deel: n.v.t.; Deurblad: n.v.t.; Onderdorpel: n.v.t.; Stofdorpel: n.v.t.; Vensterbank: n.v.t.; Ventilatierooster: n.v.t.; Spouwlat: n.v.t.; Rollaag / Latei: n.v.t.; Afwerking dagkant buiten: n.v.t.; Afwerking dagkant binnen: n.v.t.; Zonwering - behuizing: n.v.t.; Zonwering - isolatie: n.v.t.; Glas: Glas - algemeen
CPset_Phasing - Renovation Phase: Bestaand
Name | In | OverallWidth (mm)
_Merk-x | 1e verdieping N | 1230
_Merk-x | 2e verdieping N | 1230
2 x _Merk-x | 2e verdieping V | 930

# IfcDoor: D1 27 (6)
Type - OperationType: SINGLE_SWING_LEFT; ParameterTakesPrecedence: no; Sizeable: no
Type - Door Lining Properties - LiningDepth: 114 mm; LiningThickness: 67 mm; LiningOffset: -14 mm
Type - Door Panel Properties - Panel 1 - PanelDepth: 40 mm; PanelOperation: SWINGING; PanelWidth: 1; PanelPosition: MIDDLE
OverallHeight: 2100 mm
Pset_DoorCommon - FireRating: n.v.t.; SecurityRating: FALSE; ThermalTransmittance: 0; FireExit: no; SelfClosing: no; SmokeStop: no; IsExternal: no
CPset_Phasing - Renovation Phase: Bestaand
Material - Frame / Draaiend deel: n.v.t.; Deurblad: n.v.t.; Onderdorpel: n.v.t.; Stofdorpel: n.v.t.; Vensterbank: n.v.t.; Ventilatierooster: n.v.t.; Spouwlat: n.v.t.; Rollaag / Latei: n.v.t.; Afwerking dagkant buiten: n.v.t.; Afwerking dagkant binnen: n.v.t.; Zonwering - behuizing: n.v.t.; Zonwering - isolatie: n.v.t.; Glas: Glas - algemeen
Name | In | OverallWidth (mm)
_Merk-x | 1e verdieping N | 800
_Merk-x | 1e verdieping N | 830
_Merk-x | 2e verdieping N | 800
_Merk-x | 2e verdieping N | 930
_Merk-x | 2e verdieping V | 949.999
_Merk-x | 2e verdieping V | 1000

# IfcDoor: D1 27, _Merk-x
In: Begane grond N
Type - OperationType: SINGLE_SWING_LEFT; ParameterTakesPrecedence: no; Sizeable: no
Type - Door Lining Properties - LiningDepth: 114 mm; LiningThickness: 67 mm; LiningOffset: -39 mm
Type - Door Panel Properties - Panel 1 - PanelDepth: 40 mm; PanelOperation: SWINGING; PanelWidth: 1; PanelPosition: MIDDLE
OverallHeight: 2100 mm; OverallWidth: 1100 mm
Pset_DoorCommon - FireRating: n.v.t.; SecurityRating: FALSE; ThermalTransmittance: 0; FireExit: no; SelfClosing: no; SmokeStop: no; IsExternal: no
Material - Frame / Draaiend deel: n.v.t.; Deurblad: n.v.t.; Onderdorpel: n.v.t.; Stofdorpel: n.v.t.; Vensterbank: n.v.t.; Ventilatierooster: n.v.t.; Spouwlat: n.v.t.; Rollaag / Latei: n.v.t.; Afwerking dagkant buiten: n.v.t.; Afwerking dagkant binnen: n.v.t.; Zonwering - behuizing: n.v.t.; Zonwering - isolatie: n.v.t.; Glas: Glas - algemeen
CPset_Phasing - Renovation Phase: Bestaand

# IfcDoor: D1 27, _Merk-x
In: 2e verdieping N
Type - OperationType: SINGLE_SWING_LEFT; ParameterTakesPrecedence: no; Sizeable: no
Type - Door Lining Properties - LiningDepth: 114 mm; LiningThickness: 67 mm; LiningOffset: -57 mm
Type - Door Panel Properties - Panel 1 - PanelDepth: 40 mm; PanelOperation: SWINGING; PanelWidth: 1; PanelPosition: MIDDLE
OverallHeight: 2400 mm; OverallWidth: 934 mm
Pset_DoorCommon - FireRating: n.v.t.; SecurityRating: FALSE; ThermalTransmittance: 0; FireExit: no; SelfClosing: no; SmokeStop: no; IsExternal: no
Material - Frame / Draaiend deel: n.v.t.; Deurblad: n.v.t.; Onderdorpel: n.v.t.; Stofdorpel: n.v.t.; Vensterbank: n.v.t.; Ventilatierooster: n.v.t.; Spouwlat: n.v.t.; Rollaag / Latei: n.v.t.; Afwerking dagkant buiten: n.v.t.; Afwerking dagkant binnen: n.v.t.; Zonwering - behuizing: n.v.t.; Zonwering - isolatie: n.v.t.; Glas: Glas - algemeen
CPset_Phasing - Renovation Phase: Nieuw

# IfcDoor: D1 27, _Merk-x
In: 1e verdieping N
Type - OperationType: SINGLE_SWING_LEFT; ParameterTakesPrecedence: no; Sizeable: no
Type - Door Lining Properties - LiningDepth: 114 mm; LiningThickness: 67 mm; LiningOffset: -64 mm
Type - Door Panel Properties - Panel 1 - PanelDepth: 40 mm; PanelOperation: SWINGING; PanelWidth: 1; PanelPosition: MIDDLE
OverallHeight: 2100 mm; OverallWidth: 930 mm
Pset_DoorCommon - FireRating: n.v.t.; SecurityRating: FALSE; ThermalTransmittance: 0; FireExit: no; SelfClosing: no; SmokeStop: no; IsExternal: no
CPset_Phasing - Renovation Phase: Bestaand
Material - Frame / Draaiend deel: n.v.t.; Deurblad: n.v.t.; Onderdorpel: n.v.t.; Stofdorpel: n.v.t.; Vensterbank: n.v.t.; Ventilatierooster: n.v.t.; Spouwlat: n.v.t.; Rollaag / Latei: n.v.t.; Afwerking dagkant buiten: n.v.t.; Afwerking dagkant binnen: n.v.t.; Zonwering - behuizing: n.v.t.; Zonwering - isolatie: n.v.t.; Glas: Glas - algemeen

# IfcDoor: D1 27 (8)
Type - OperationType: SINGLE_SWING_LEFT; ParameterTakesPrecedence: no; Sizeable: no
Type - Door Lining Properties - LiningDepth: 114 mm; LiningThickness: 67 mm; LiningOffset: -7 mm
Type - Door Panel Properties - Panel 1 - PanelDepth: 40 mm; PanelOperation: SWINGING; PanelWidth: 1; PanelPosition: MIDDLE
OverallHeight: 2400 mm
Material - Frame / Draaiend deel: n.v.t.; Deurblad: n.v.t.; Onderdorpel: n.v.t.; Stofdorpel: n.v.t.; Vensterbank: n.v.t.; Ventilatierooster: n.v.t.; Spouwlat: n.v.t.; Rollaag / Latei: n.v.t.; Afwerking dagkant buiten: n.v.t.; Afwerking dagkant binnen: n.v.t.; Zonwering - behuizing: n.v.t.; Zonwering - isolatie: n.v.t.; Glas: Glas - algemeen
Pset_DoorCommon - FireRating: n.v.t.; SecurityRating: FALSE; ThermalTransmittance: 0; FireExit: no; SelfClosing: no; SmokeStop: no; IsExternal: no
CPset_Phasing - Renovation Phase: Nieuw
Name | In | OverallWidth (mm)
3 x _Merk-x | Begane grond N | 934
_Merk-x | 1e verdieping N | 1034
_Merk-x | 2e verdieping N | 934
3 x _Merk-x | 2e verdieping N | 1034

# IfcDoor: D1 27 (2)
In: Begane grond N
Type - OperationType: SINGLE_SWING_LEFT; ParameterTakesPrecedence: no; Sizeable: no
Type - Door Lining Properties - LiningDepth: 114 mm; LiningThickness: 67 mm; LiningOffset: -75 mm
Type - Door Panel Properties - Panel 1 - PanelDepth: 40 mm; PanelOperation: SWINGING; PanelWidth: 1; PanelPosition: MIDDLE
OverallHeight: 2100 mm; OverallWidth: 1100 mm
Pset_DoorCommon - FireRating: n.v.t.; SecurityRating: FALSE; ThermalTransmittance: 0; FireExit: no; SelfClosing: no; SmokeStop: no; IsExternal: no
CPset_Phasing - Renovation Phase: Bestaand
Material - Frame / Draaiend deel: n.v.t.; Deurblad: n.v.t.; Onderdorpel: n.v.t.; Stofdorpel: n.v.t.; Vensterbank: n.v.t.; Ventilatierooster: n.v.t.; Spouwlat: n.v.t.; Rollaag / Latei: n.v.t.; Afwerking dagkant buiten: n.v.t.; Afwerking dagkant binnen: n.v.t.; Zonwering - behuizing: n.v.t.; Zonwering - isolatie: n.v.t.; Glas: Glas - algemeen

# IfcDoor: D1 27, _Merk-x
In: Begane grond N
Type - OperationType: SINGLE_SWING_LEFT; ParameterTakesPrecedence: no; Sizeable: no
Type - Door Lining Properties - LiningDepth: 114 mm; LiningThickness: 67 mm; LiningOffset: 0 mm
Type - Door Panel Properties - Panel 1 - PanelDepth: 40 mm; PanelOperation: SWINGING; PanelWidth: 1; PanelPosition: MIDDLE
OverallHeight: 2100 mm; OverallWidth: 1100 mm
Material - Frame / Draaiend deel: n.v.t.; Deurblad: n.v.t.; Onderdorpel: n.v.t.; Stofdorpel: n.v.t.; Vensterbank: n.v.t.; Ventilatierooster: n.v.t.; Spouwlat: n.v.t.; Rollaag / Latei: n.v.t.; Afwerking dagkant buiten: n.v.t.; Afwerking dagkant binnen: n.v.t.; Zonwering - behuizing: n.v.t.; Zonwering - isolatie: n.v.t.; Glas: Glas - algemeen
Pset_DoorCommon - FireRating: n.v.t.; SecurityRating: FALSE; ThermalTransmittance: 0; FireExit: no; SelfClosing: no; SmokeStop: no; IsExternal: no
CPset_Phasing - Renovation Phase: Bestaand

# IfcDoor: D1 27, _Merk-x
In: 1e verdieping N
Type - OperationType: SINGLE_SWING_LEFT; ParameterTakesPrecedence: no; Sizeable: no
Type - Door Panel Properties - Panel 1 - PanelDepth: 10 mm; PanelOperation: SWINGING; PanelWidth: 1; PanelPosition: MIDDLE
OverallHeight: 2400 mm; OverallWidth: 900 mm
Pset_DoorCommon - FireRating: n.v.t.; SecurityRating: FALSE; ThermalTransmittance: 0; FireExit: no; SelfClosing: no; SmokeStop: no; IsExternal: no
Material - Frame / Draaiend deel: n.v.t.; Deurblad: n.v.t.; Onderdorpel: n.v.t.; Stofdorpel: n.v.t.; Vensterbank: n.v.t.; Ventilatierooster: n.v.t.; Spouwlat: n.v.t.; Rollaag / Latei: n.v.t.; Afwerking dagkant buiten: n.v.t.; Afwerking dagkant binnen: n.v.t.; Zonwering - behuizing: n.v.t.; Zonwering - isolatie: n.v.t.; Glas: Glas - algemeen
CPset_Phasing - Renovation Phase: Nieuw

# IfcDoor: D1 27 (2)
Type - OperationType: SINGLE_SWING_RIGHT; ParameterTakesPrecedence: no; Sizeable: no
Type - Door Lining Properties - LiningDepth: 114 mm; LiningThickness: 67 mm; LiningOffset: -100 mm
Type - Door Panel Properties - Panel 1 - PanelDepth: 40 mm; PanelOperation: SWINGING; PanelWidth: 1; PanelPosition: MIDDLE
OverallHeight: 2400 mm; OverallWidth: 1034 mm
Pset_DoorCommon - FireRating: n.v.t.; SecurityRating: FALSE; ThermalTransmittance: 0; FireExit: no; SelfClosing: no; SmokeStop: no; IsExternal: no
Material - Frame / Draaiend deel: n.v.t.; Deurblad: n.v.t.; Onderdorpel: n.v.t.; Stofdorpel: n.v.t.; Vensterbank: n.v.t.; Ventilatierooster: n.v.t.; Spouwlat: n.v.t.; Rollaag / Latei: n.v.t.; Afwerking dagkant buiten: n.v.t.; Afwerking dagkant binnen: n.v.t.; Zonwering - behuizing: n.v.t.; Zonwering - isolatie: n.v.t.; Glas: Glas - algemeen
CPset_Phasing - Renovation Phase: Nieuw
Name | In
_Merk-x | Begane grond N
_Merk-x | 1e verdieping N

# IfcDoor: D1 27 (7)
Type - OperationType: SINGLE_SWING_RIGHT; ParameterTakesPrecedence: no; Sizeable: no
Type - Door Lining Properties - LiningDepth: 114 mm; LiningThickness: 67 mm; LiningOffset: -107 mm
Type - Door Panel Properties - Panel 1 - PanelDepth: 40 mm; PanelOperation: SWINGING; PanelWidth: 1; PanelPosition: MIDDLE
OverallHeight: 2400 mm; OverallWidth: 934 mm
Pset_DoorCommon - FireRating: n.v.t.; SecurityRating: FALSE; ThermalTransmittance: 0; FireExit: no; SelfClosing: no; SmokeStop: no; IsExternal: no
Material - Frame / Draaiend deel: n.v.t.; Deurblad: n.v.t.; Onderdorpel: n.v.t.; Stofdorpel: n.v.t.; Vensterbank: n.v.t.; Ventilatierooster: n.v.t.; Spouwlat: n.v.t.; Rollaag / Latei: n.v.t.; Afwerking dagkant buiten: n.v.t.; Afwerking dagkant binnen: n.v.t.; Zonwering - behuizing: n.v.t.; Zonwering - isolatie: n.v.t.; Glas: Glas - algemeen
CPset_Phasing - Renovation Phase: Nieuw
Name | In
2 x _Merk-x | Begane grond N
4 x _Merk-x | 1e verdieping N
_Merk-x | 2e verdieping N

# IfcDoor: D1 27 (3)
Type - OperationType: SINGLE_SWING_RIGHT; ParameterTakesPrecedence: no; Sizeable: no
Type - Door Lining Properties - LiningDepth: 114 mm; LiningThickness: 67 mm; LiningOffset: -114 mm
Type - Door Panel Properties - Panel 1 - PanelDepth: 40 mm; PanelOperation: SWINGING; PanelWidth: 1; PanelPosition: MIDDLE
OverallHeight: 2100 mm
Pset_DoorCommon - FireRating: n.v.t.; SecurityRating: FALSE; ThermalTransmittance: 0; FireExit: no; SelfClosing: no; SmokeStop: no; IsExternal: no
Material - Frame / Draaiend deel: n.v.t.; Deurblad: n.v.t.; Onderdorpel: n.v.t.; Stofdorpel: n.v.t.; Vensterbank: n.v.t.; Ventilatierooster: n.v.t.; Spouwlat: n.v.t.; Rollaag / Latei: n.v.t.; Afwerking dagkant buiten: n.v.t.; Afwerking dagkant binnen: n.v.t.; Zonwering - behuizing: n.v.t.; Zonwering - isolatie: n.v.t.; Glas: Glas - algemeen
Name | In | OverallWidth (mm) | Renovation Phase
_Merk-x | 1e verdieping N | 1034 | Nieuw
2 x _Merk-x | 2e verdieping V | 930 | Bestaand

# IfcDoor: D1 27 (5)
Type - OperationType: SINGLE_SWING_RIGHT; ParameterTakesPrecedence: no; Sizeable: no
Type - Door Lining Properties - LiningDepth: 114 mm; LiningThickness: 67 mm; LiningOffset: -14 mm
Type - Door Panel Properties - Panel 1 - PanelDepth: 40 mm; PanelOperation: SWINGING; PanelWidth: 1; PanelPosition: MIDDLE
OverallHeight: 2100 mm
Pset_DoorCommon - FireRating: n.v.t.; SecurityRating: FALSE; ThermalTransmittance: 0; FireExit: no; SelfClosing: no; SmokeStop: no; IsExternal: no
Material - Frame / Draaiend deel: n.v.t.; Deurblad: n.v.t.; Onderdorpel: n.v.t.; Stofdorpel: n.v.t.; Vensterbank: n.v.t.; Ventilatierooster: n.v.t.; Spouwlat: n.v.t.; Rollaag / Latei: n.v.t.; Afwerking dagkant buiten: n.v.t.; Afwerking dagkant binnen: n.v.t.; Zonwering - behuizing: n.v.t.; Zonwering - isolatie: n.v.t.; Glas: Glas - algemeen
Name | In | OverallWidth (mm) | Renovation Phase
_Merk-x | Begane grond N | 930 | Nieuw
3 x _Merk-x | 1e verdieping N | 830 | Bestaand
_Merk-x | 1e verdieping N | 930 | Nieuw

# IfcDoor: D1 27 (5)
In: Begane grond N
Type - OperationType: SINGLE_SWING_RIGHT; ParameterTakesPrecedence: no; Sizeable: no
Type - Door Lining Properties - LiningDepth: 114 mm; LiningThickness: 67 mm; LiningOffset: -39 mm
Type - Door Panel Properties - Panel 1 - PanelDepth: 40 mm; PanelOperation: SWINGING; PanelWidth: 1; PanelPosition: MIDDLE
OverallHeight: 2100 mm; OverallWidth: 987.5 mm
Pset_DoorCommon - FireRating: n.v.t.; SecurityRating: FALSE; ThermalTransmittance: 0; FireExit: no; SelfClosing: no; SmokeStop: no; IsExternal: no
Material - Frame / Draaiend deel: n.v.t.; Deurblad: n.v.t.; Onderdorpel: n.v.t.; Stofdorpel: n.v.t.; Vensterbank: n.v.t.; Ventilatierooster: n.v.t.; Spouwlat: n.v.t.; Rollaag / Latei: n.v.t.; Afwerking dagkant buiten: n.v.t.; Afwerking dagkant binnen: n.v.t.; Zonwering - behuizing: n.v.t.; Zonwering - isolatie: n.v.t.; Glas: Glas - algemeen
CPset_Phasing - Renovation Phase: Bestaand

# IfcDoor: D1 27, _Merk-x
In: 2e verdieping N
Type - OperationType: SINGLE_SWING_RIGHT; ParameterTakesPrecedence: no; Sizeable: no
Type - Door Lining Properties - LiningDepth: 114 mm; LiningThickness: 67 mm; LiningOffset: -57 mm
Type - Door Panel Properties - Panel 1 - PanelDepth: 40 mm; PanelOperation: SWINGING; PanelWidth: 1; PanelPosition: MIDDLE
OverallHeight: 2400 mm; OverallWidth: 934 mm
Pset_DoorCommon - FireRating: n.v.t.; SecurityRating: FALSE; ThermalTransmittance: 0; FireExit: no; SelfClosing: no; SmokeStop: no; IsExternal: no
Material - Frame / Draaiend deel: n.v.t.; Deurblad: n.v.t.; Onderdorpel: n.v.t.; Stofdorpel: n.v.t.; Vensterbank: n.v.t.; Ventilatierooster: n.v.t.; Spouwlat: n.v.t.; Rollaag / Latei: n.v.t.; Afwerking dagkant buiten: n.v.t.; Afwerking dagkant binnen: n.v.t.; Zonwering - behuizing: n.v.t.; Zonwering - isolatie: n.v.t.; Glas: Glas - algemeen
CPset_Phasing - Renovation Phase: Nieuw

# IfcDoor: D1 27, _Merk-x
In: 1e verdieping N
Type - OperationType: SINGLE_SWING_RIGHT; ParameterTakesPrecedence: no; Sizeable: no
Type - Door Lining Properties - LiningDepth: 114 mm; LiningThickness: 67 mm; LiningOffset: -64 mm
Type - Door Panel Properties - Panel 1 - PanelDepth: 40 mm; PanelOperation: SWINGING; PanelWidth: 1; PanelPosition: MIDDLE
OverallHeight: 2100 mm; OverallWidth: 930 mm
Pset_DoorCommon - FireRating: n.v.t.; SecurityRating: FALSE; ThermalTransmittance: 0; FireExit: no; SelfClosing: no; SmokeStop: no; IsExternal: no
CPset_Phasing - Renovation Phase: Bestaand
Material - Frame / Draaiend deel: n.v.t.; Deurblad: n.v.t.; Onderdorpel: n.v.t.; Stofdorpel: n.v.t.; Vensterbank: n.v.t.; Ventilatierooster: n.v.t.; Spouwlat: n.v.t.; Rollaag / Latei: n.v.t.; Afwerking dagkant buiten: n.v.t.; Afwerking dagkant binnen: n.v.t.; Zonwering - behuizing: n.v.t.; Zonwering - isolatie: n.v.t.; Glas: Glas - algemeen

# IfcDoor: D1 27 (12)
Type - OperationType: SINGLE_SWING_RIGHT; ParameterTakesPrecedence: no; Sizeable: no
Type - Door Lining Properties - LiningDepth: 114 mm; LiningThickness: 67 mm; LiningOffset: -7 mm
Type - Door Panel Properties - Panel 1 - PanelDepth: 40 mm; PanelOperation: SWINGING; PanelWidth: 1; PanelPosition: MIDDLE
Pset_DoorCommon - FireRating: n.v.t.; SecurityRating: FALSE; ThermalTransmittance: 0; FireExit: no; SelfClosing: no; SmokeStop: no; IsExternal: no
Material - Frame / Draaiend deel: n.v.t.; Deurblad: n.v.t.; Onderdorpel: n.v.t.; Stofdorpel: n.v.t.; Vensterbank: n.v.t.; Ventilatierooster: n.v.t.; Spouwlat: n.v.t.; Rollaag / Latei: n.v.t.; Afwerking dagkant buiten: n.v.t.; Afwerking dagkant binnen: n.v.t.; Zonwering - behuizing: n.v.t.; Zonwering - isolatie: n.v.t.; Glas: Glas - algemeen
CPset_Phasing - Renovation Phase: Nieuw
Name | In | OverallHeight (mm) | OverallWidth (mm)
_Merk-x | Begane grond N | 2400 | 1034
3 x _Merk-x | Begane grond N | 2400 | 934
_Merk-x | 1e verdieping N | 2100 | 962.208
_Merk-x | 1e verdieping N | 2400 | 934
_Merk-x | 1e verdieping N | 2400 | 1034 | Pset_DoorCommon - GlazingAreaFraction: 1.5047
_Merk-x | 1e verdieping N | 2400 | 1034
_Merk-x | 2e verdieping N | 2400 | 1034 | Pset_DoorCommon - GlazingAreaFraction: 1.5047
2 x _Merk-x | 2e verdieping N | 2400 | 1034
_Merk-x | 2e verdieping N | 2400 | 934

# IfcDoor: D1 27, _Merk-x
In: Begane grond N
Type - OperationType: SINGLE_SWING_RIGHT; ParameterTakesPrecedence: no; Sizeable: no
Type - Door Lining Properties - LiningDepth: 114 mm; LiningThickness: 67 mm; LiningOffset: -75 mm
Type - Door Panel Properties - Panel 1 - PanelDepth: 40 mm; PanelOperation: SWINGING; PanelWidth: 1; PanelPosition: MIDDLE
OverallHeight: 2100 mm; OverallWidth: 1100 mm
Pset_DoorCommon - FireRating: n.v.t.; SecurityRating: FALSE; ThermalTransmittance: 0; FireExit: no; SelfClosing: no; SmokeStop: no; IsExternal: no
Material - Frame / Draaiend deel: n.v.t.; Deurblad: n.v.t.; Onderdorpel: n.v.t.; Stofdorpel: n.v.t.; Vensterbank: n.v.t.; Ventilatierooster: n.v.t.; Spouwlat: n.v.t.; Rollaag / Latei: n.v.t.; Afwerking dagkant buiten: n.v.t.; Afwerking dagkant binnen: n.v.t.; Zonwering - behuizing: n.v.t.; Zonwering - isolatie: n.v.t.; Glas: Glas - algemeen
CPset_Phasing - Renovation Phase: Bestaand

# IfcDoor: D1 27 (2)
Type - OperationType: SINGLE_SWING_RIGHT; ParameterTakesPrecedence: no; Sizeable: no
Type - Door Lining Properties - LiningDepth: 114 mm; LiningThickness: 67 mm; LiningOffset: 0 mm
Type - Door Panel Properties - Panel 1 - PanelDepth: 40 mm; PanelOperation: SWINGING; PanelWidth: 1; PanelPosition: MIDDLE
Pset_DoorCommon - FireRating: n.v.t.; SecurityRating: FALSE; ThermalTransmittance: 0; FireExit: no; SelfClosing: no; SmokeStop: no; IsExternal: no
Material - Frame / Draaiend deel: n.v.t.; Deurblad: n.v.t.; Onderdorpel: n.v.t.; Stofdorpel: n.v.t.; Vensterbank: n.v.t.; Ventilatierooster: n.v.t.; Spouwlat: n.v.t.; Rollaag / Latei: n.v.t.; Afwerking dagkant buiten: n.v.t.; Afwerking dagkant binnen: n.v.t.; Zonwering - behuizing: n.v.t.; Zonwering - isolatie: n.v.t.; Glas: Glas - algemeen
Name | In | OverallHeight (mm) | OverallWidth (mm) | Renovation Phase
_Merk-x | Fundering N | 1501 | 1034 | Bestaand
_Merk-x | Begane grond N | 2100 | 1100 | Nieuw

# IfcDoor: D1 27, _Merk-x
In: 3e verdieping/dak N
Type - OperationType: SINGLE_SWING_RIGHT; ParameterTakesPrecedence: no; Sizeable: no
Type - Door Lining Properties - LiningDepth: 114 mm; LiningThickness: 67 mm; LiningOffset: 86 mm
Type - Door Panel Properties - Panel 1 - PanelDepth: 40 mm; PanelOperation: SWINGING; PanelWidth: 1; PanelPosition: MIDDLE
OverallHeight: 2100 mm; OverallWidth: 1000 mm
Pset_DoorCommon - FireRating: n.v.t.; SecurityRating: FALSE; ThermalTransmittance: 0; FireExit: no; SelfClosing: no; SmokeStop: no; IsExternal: no
Material - Frame / Draaiend deel: n.v.t.; Deurblad: n.v.t.; Onderdorpel: n.v.t.; Stofdorpel: n.v.t.; Vensterbank: n.v.t.; Ventilatierooster: n.v.t.; Spouwlat: n.v.t.; Rollaag / Latei: n.v.t.; Afwerking dagkant buiten: n.v.t.; Afwerking dagkant binnen: n.v.t.; Zonwering - behuizing: n.v.t.; Zonwering - isolatie: n.v.t.; Glas: Glas - algemeen
CPset_Phasing - Renovation Phase: Bestaand

# IfcDoor: D1 27, _Merk-x
In: 2e verdieping N
Type - OperationType: SINGLE_SWING_RIGHT; ParameterTakesPrecedence: no; Sizeable: no
Type - Door Panel Properties - Panel 1 - PanelDepth: 10 mm; PanelOperation: SWINGING; PanelWidth: 1; PanelPosition: MIDDLE
OverallHeight: 2100 mm; OverallWidth: 900 mm
Pset_DoorCommon - FireRating: n.v.t.; SecurityRating: FALSE; ThermalTransmittance: 0; FireExit: no; SelfClosing: no; SmokeStop: no; IsExternal: no
Material - Frame / Draaiend deel: n.v.t.; Deurblad: n.v.t.; Onderdorpel: n.v.t.; Stofdorpel: n.v.t.; Vensterbank: n.v.t.; Ventilatierooster: n.v.t.; Spouwlat: n.v.t.; Rollaag / Latei: n.v.t.; Afwerking dagkant buiten: n.v.t.; Afwerking dagkant binnen: n.v.t.; Zonwering - behuizing: n.v.t.; Zonwering - isolatie: n.v.t.; Glas: Glas - algemeen
CPset_Phasing - Renovation Phase: Nieuw

# IfcDoor: D1 zl2 27 (33)
Type - OperationType: USERDEFINED; ParameterTakesPrecedence: no; Sizeable: no
OverallHeight: 2400 mm
Material - Frame / Draaiend deel: n.v.t.; Deurblad: n.v.t.; Onderdorpel: n.v.t.; Stofdorpel: n.v.t.; Vensterbank: n.v.t.; Ventilatierooster: n.v.t.; Spouwlat: n.v.t.; Rollaag / Latei: n.v.t.; Afwerking dagkant buiten: n.v.t.; Afwerking dagkant binnen: n.v.t.; Zonwering - behuizing: n.v.t.; Zonwering - isolatie: n.v.t.; Glas: Glas - algemeen
Pset_DoorCommon - FireRating: n.v.t.; SecurityRating: FALSE; ThermalTransmittance: 0; FireExit: no; SelfClosing: no; SmokeStop: no; IsExternal: no
CPset_Phasing - Renovation Phase: Nieuw
Name | In | OverallWidth (mm) | GlazingAreaFraction
_Merk-x | Begane grond N | 2679.5 | 3.88323
_Merk-x | Begane grond N | 4450 | 8.0262
_Merk-x | Begane grond N | 2660 | 3.8376
_Merk-x | Begane grond N | 1625 | 1.4157
_Merk-x | Begane grond N | 2710 | 3.9546
_Merk-x | Begane grond N | 2572.5 | 3.63285
_Merk-x | Begane grond N | 2503.88 | 3.47229
_Merk-x | Begane grond N | 2760 | 4.0716
_Merk-x | Begane grond N | 3030 | 4.7034
_Merk-x | Begane grond N | 2910 | 4.4226
_Merk-x | 1e verdieping N | 1625 | 1.4157
_Merk-x | 1e verdieping N | 2710 | 3.9546
_Merk-x | 1e verdieping N | 2610 | 3.7206
_Merk-x | 1e verdieping N | 2515 | 3.4983
_Merk-x | 1e verdieping N | 1055.5 | 0.0830712
_Merk-x | 1e verdieping N | 2760 | 4.0716
2 x _Merk-x | 1e verdieping N | 2735 | 4.0131
_Merk-x | 1e verdieping N | 2503.88 | 3.47229
_Merk-x | 1e verdieping N | 4450 | 8.0262
_Merk-x | 1e verdieping N | 3030 | 4.7034
_Merk-x | 1e verdieping N | 2910 | 4.4226
_Merk-x | 2e verdieping N | 3030 | 4.7034
_Merk-x | 2e verdieping N | 2435 | 3.3111
_Merk-x | 2e verdieping N | 2515 | 3.4983
_Merk-x | 2e verdieping N | 2610 | 3.7206
_Merk-x | 2e verdieping N | 1625 | 1.4157
_Merk-x | 2e verdieping N | 2710 | 3.9546
2 x _Merk-x | 2e verdieping N | 2735 | 4.01309
_Merk-x | 2e verdieping N | 2760 | 4.0716
_Merk-x | 2e verdieping N | 2910 | 4.4226
_Merk-x | 2e verdieping N | 1055.5 | 0.0830712

# IfcDoor: D2 26, _Merk-017
In: Begane grond N
Type - OperationType: DOUBLE_DOOR_SINGLE_SWING; ParameterTakesPrecedence: no; Sizeable: no
Type - Door Lining Properties - LiningDepth: 114 mm; LiningThickness: 67 mm; LiningOffset: 146 mm
Type - Door Panel Properties - Panel 1 - PanelDepth: 40 mm; PanelOperation: SWINGING; PanelWidth: 0.50911; PanelPosition: RIGHT
Type - Door Panel Properties - Panel 2 - PanelDepth: 40 mm; PanelOperation: SWINGING; PanelWidth: 0.50911; PanelPosition: LEFT
OverallHeight: 2400 mm; OverallWidth: 2000 mm
Pset_DoorCommon - FireRating: n.v.t.; SecurityRating: FALSE; ThermalTransmittance: 0; GlazingAreaFraction: 3.075; FireExit: no; SelfClosing: no; SmokeStop: no; IsExternal: no
Material - Frame / Draaiend deel: n.v.t.; Deurblad: n.v.t.; Onderdorpel: n.v.t.; Stofdorpel: n.v.t.; Vensterbank: n.v.t.; Ventilatierooster: n.v.t.; Spouwlat: n.v.t.; Rollaag / Latei: n.v.t.; Afwerking dagkant buiten: n.v.t.; Afwerking dagkant binnen: n.v.t.; Zonwering - behuizing: n.v.t.; Zonwering - isolatie: n.v.t.; Glas: Glas - algemeen
Pset_FireRatingProperties - FireResistanceRating: Zelfsluitend
CPset_Phasing - Renovation Phase: Nieuw

# IfcDoor: D2 26, _Merk-018
In: 1e verdieping N
Type - OperationType: DOUBLE_DOOR_SINGLE_SWING; ParameterTakesPrecedence: no; Sizeable: no
Type - Door Lining Properties - LiningDepth: 114 mm; LiningThickness: 67 mm; LiningOffset: 146 mm
Type - Door Panel Properties - Panel 1 - PanelDepth: 40 mm; PanelOperation: SWINGING; PanelWidth: 0.509274; PanelPosition: RIGHT
Type - Door Panel Properties - Panel 2 - PanelDepth: 40 mm; PanelOperation: SWINGING; PanelWidth: 0.509274; PanelPosition: LEFT
OverallHeight: 2400 mm; OverallWidth: 1966.99 mm
Pset_DoorCommon - FireRating: n.v.t.; SecurityRating: FALSE; ThermalTransmittance: 0; GlazingAreaFraction: 3.00116; FireExit: no; SelfClosing: no; SmokeStop: no; IsExternal: no
Material - Frame / Draaiend deel: n.v.t.; Deurblad: n.v.t.; Onderdorpel: n.v.t.; Stofdorpel: n.v.t.; Vensterbank: n.v.t.; Ventilatierooster: n.v.t.; Spouwlat: n.v.t.; Rollaag / Latei: n.v.t.; Afwerking dagkant buiten: n.v.t.; Afwerking dagkant binnen: n.v.t.; Zonwering - behuizing: n.v.t.; Zonwering - isolatie: n.v.t.; Glas: Glas - algemeen
Pset_FireRatingProperties - FireResistanceRating: Zelfsluitend
CPset_Phasing - Renovation Phase: Nieuw

# IfcDoor: D2 26, _Merk-047
In: 2e verdieping N
Type - OperationType: DOUBLE_DOOR_SINGLE_SWING; ParameterTakesPrecedence: no; Sizeable: no
Type - Door Lining Properties - LiningDepth: 114 mm; LiningThickness: 67 mm; LiningOffset: 146 mm
Type - Door Panel Properties - Panel 1 - PanelDepth: 40 mm; PanelOperation: SWINGING; PanelWidth: 0.509378; PanelPosition: LEFT
Type - Door Panel Properties - Panel 2 - PanelDepth: 40 mm; PanelOperation: SWINGING; PanelWidth: 0.509378; PanelPosition: RIGHT
OverallHeight: 2400 mm; OverallWidth: 1946.78 mm
Pset_DoorCommon - FireRating: n.v.t.; SecurityRating: FALSE; ThermalTransmittance: 0; GlazingAreaFraction: 2.9659; FireExit: no; SelfClosing: no; SmokeStop: no; IsExternal: no
Material - Frame / Draaiend deel: n.v.t.; Deurblad: n.v.t.; Onderdorpel: n.v.t.; Stofdorpel: n.v.t.; Vensterbank: n.v.t.; Ventilatierooster: n.v.t.; Spouwlat: n.v.t.; Rollaag / Latei: n.v.t.; Afwerking dagkant buiten: n.v.t.; Afwerking dagkant binnen: n.v.t.; Zonwering - behuizing: n.v.t.; Zonwering - isolatie: n.v.t.; Glas: Glas - algemeen
Pset_FireRatingProperties - FireResistanceRating: Zelfsluitend
CPset_Phasing - Renovation Phase: Nieuw

# IfcDoor: D2 27, _Merk-x
In: 2e verdieping N
Type - OperationType: DOUBLE_DOOR_SINGLE_SWING; ParameterTakesPrecedence: no; Sizeable: no
Type - Door Lining Properties - LiningDepth: 114 mm; LiningThickness: 67 mm; LiningOffset: -107 mm
Type - Door Panel Properties - Panel 1 - PanelDepth: 40 mm; PanelOperation: SWINGING; PanelWidth: 0.508228; PanelPosition: RIGHT
Type - Door Panel Properties - Panel 2 - PanelDepth: 40 mm; PanelOperation: SWINGING; PanelWidth: 0.508228; PanelPosition: LEFT
OverallHeight: 2400 mm; OverallWidth: 2200 mm
Material - Frame / Draaiend deel: n.v.t.; Deurblad: n.v.t.; Onderdorpel: n.v.t.; Stofdorpel: n.v.t.; Vensterbank: n.v.t.; Ventilatierooster: n.v.t.; Spouwlat: n.v.t.; Rollaag / Latei: n.v.t.; Afwerking dagkant buiten: n.v.t.; Afwerking dagkant binnen: n.v.t.; Zonwering - behuizing: n.v.t.; Zonwering - isolatie: n.v.t.; Glas: Glas - algemeen
Pset_FireRatingProperties - FireResistanceRating: 60 minuten brandwerend en zelfsluitend
CPset_Phasing - Renovation Phase: Nieuw
Pset_DoorCommon - FireRating: n.v.t.; SecurityRating: FALSE; ThermalTransmittance: 0; GlazingAreaFraction: 3.485; FireExit: no; SelfClosing: no; SmokeStop: no; IsExternal: no

# IfcDoor: D2 27, _Merk-x
In: Begane grond N
Type - OperationType: DOUBLE_DOOR_SINGLE_SWING; ParameterTakesPrecedence: no; Sizeable: no
Type - Door Lining Properties - LiningDepth: 114 mm; LiningThickness: 67 mm; LiningOffset: -114 mm
Type - Door Panel Properties - Panel 1 - PanelDepth: 40 mm; PanelOperation: SWINGING; PanelWidth: 0.508691; PanelPosition: LEFT
Type - Door Panel Properties - Panel 2 - PanelDepth: 40 mm; PanelOperation: SWINGING; PanelWidth: 0.508691; PanelPosition: RIGHT
OverallHeight: 2400 mm; OverallWidth: 2090 mm
Pset_FireRatingProperties - FireResistanceRating: 60 minuten brandwerend en zelfsluitend
Pset_DoorCommon - FireRating: n.v.t.; SecurityRating: FALSE; ThermalTransmittance: 0; GlazingAreaFraction: 3.2595; FireExit: no; SelfClosing: no; SmokeStop: no; IsExternal: no
CPset_Phasing - Renovation Phase: Nieuw
Material - Frame / Draaiend deel: n.v.t.; Deurblad: n.v.t.; Onderdorpel: n.v.t.; Stofdorpel: n.v.t.; Vensterbank: n.v.t.; Ventilatierooster: n.v.t.; Spouwlat: n.v.t.; Rollaag / Latei: n.v.t.; Afwerking dagkant buiten: n.v.t.; Afwerking dagkant binnen: n.v.t.; Zonwering - behuizing: n.v.t.; Zonwering - isolatie: n.v.t.; Glas: Glas - algemeen

# IfcDoor: D2 27 (3)
Type - OperationType: DOUBLE_DOOR_SINGLE_SWING; ParameterTakesPrecedence: no; Sizeable: no
Type - Door Lining Properties - LiningDepth: 114 mm; LiningThickness: 67 mm; LiningOffset: -14 mm
Type - Door Panel Properties - Panel 1 - PanelDepth: 40 mm; PanelOperation: SWINGING; PanelWidth: 0.508691; PanelPosition: LEFT
Type - Door Panel Properties - Panel 2 - PanelDepth: 40 mm; PanelOperation: SWINGING; PanelWidth: 0.508691; PanelPosition: RIGHT
OverallHeight: 2300 mm; OverallWidth: 2090 mm
Pset_DoorCommon - FireRating: n.v.t.; SecurityRating: FALSE; ThermalTransmittance: 0; FireExit: no; SelfClosing: no; SmokeStop: no; IsExternal: no
Material - Frame / Draaiend deel: n.v.t.; Deurblad: n.v.t.; Onderdorpel: n.v.t.; Stofdorpel: n.v.t.; Vensterbank: n.v.t.; Ventilatierooster: n.v.t.; Spouwlat: n.v.t.; Rollaag / Latei: n.v.t.; Afwerking dagkant buiten: n.v.t.; Afwerking dagkant binnen: n.v.t.; Zonwering - behuizing: n.v.t.; Zonwering - isolatie: n.v.t.; Glas: Glas - algemeen
CPset_Phasing - Renovation Phase: Bestaand
Name | In
_Merk-x | Begane grond N
_Merk-x | 1e verdieping N
_Merk-x | 2e verdieping N

# IfcDoor: D2 27 (2)
In: Begane grond N
Type - OperationType: DOUBLE_DOOR_SINGLE_SWING; ParameterTakesPrecedence: no; Sizeable: no
Type - Door Lining Properties - LiningDepth: 114 mm; LiningThickness: 67 mm; LiningOffset: -14 mm
Type - Door Panel Properties - Panel 1 - PanelDepth: 40 mm; PanelOperation: SWINGING; PanelWidth: 0.511596; PanelPosition: LEFT
Type - Door Panel Properties - Panel 2 - PanelDepth: 40 mm; PanelOperation: SWINGING; PanelWidth: 0.511596; PanelPosition: RIGHT
OverallHeight: 2400 mm; OverallWidth: 1600 mm
Material - Frame / Draaiend deel: n.v.t.; Deurblad: n.v.t.; Onderdorpel: n.v.t.; Stofdorpel: n.v.t.; Vensterbank: n.v.t.; Ventilatierooster: n.v.t.; Spouwlat: n.v.t.; Rollaag / Latei: n.v.t.; Afwerking dagkant buiten: n.v.t.; Afwerking dagkant binnen: n.v.t.; Zonwering - behuizing: n.v.t.; Zonwering - isolatie: n.v.t.; Glas: Glas - algemeen
Pset_DoorCommon - FireRating: n.v.t.; SecurityRating: FALSE; ThermalTransmittance: 0; FireExit: no; SelfClosing: no; SmokeStop: no; IsExternal: no
CPset_Phasing - Renovation Phase: Nieuw

# IfcDoor: D2 27, _Merk-x
In: 1e verdieping N
Type - OperationType: DOUBLE_DOOR_SINGLE_SWING; ParameterTakesPrecedence: no; Sizeable: no
Type - Door Lining Properties - LiningDepth: 114 mm; LiningThickness: 67 mm; LiningOffset: -150 mm
Type - Door Panel Properties - Panel 1 - PanelDepth: 40 mm; PanelOperation: SWINGING; PanelWidth: 0.508229; PanelPosition: LEFT
Type - Door Panel Properties - Panel 2 - PanelDepth: 40 mm; PanelOperation: SWINGING; PanelWidth: 0.508229; PanelPosition: RIGHT
OverallHeight: 2400 mm; OverallWidth: 2199.96 mm
Material - Frame / Draaiend deel: n.v.t.; Deurblad: n.v.t.; Onderdorpel: n.v.t.; Stofdorpel: n.v.t.; Vensterbank: n.v.t.; Ventilatierooster: n.v.t.; Spouwlat: n.v.t.; Rollaag / Latei: n.v.t.; Afwerking dagkant buiten: n.v.t.; Afwerking dagkant binnen: n.v.t.; Zonwering - behuizing: n.v.t.; Zonwering - isolatie: n.v.t.; Glas: Glas - algemeen
Pset_DoorCommon - FireRating: n.v.t.; SecurityRating: FALSE; ThermalTransmittance: 0; GlazingAreaFraction: 3.48493; FireExit: no; SelfClosing: no; SmokeStop: no; IsExternal: no
CPset_Phasing - Renovation Phase: Nieuw

# IfcDoor: D2 27, _Merk-x
In: Begane grond N
Type - OperationType: DOUBLE_DOOR_SINGLE_SWING; ParameterTakesPrecedence: no; Sizeable: no
Type - Door Lining Properties - LiningDepth: 114 mm; LiningThickness: 67 mm; LiningOffset: -39 mm
Type - Door Panel Properties - Panel 1 - PanelDepth: 40 mm; PanelOperation: SWINGING; PanelWidth: 0.509444; PanelPosition: RIGHT
Type - Door Panel Properties - Panel 2 - PanelDepth: 40 mm; PanelOperation: SWINGING; PanelWidth: 0.509444; PanelPosition: LEFT
OverallHeight: 2400 mm; OverallWidth: 1934 mm
Pset_DoorCommon - FireRating: n.v.t.; SecurityRating: FALSE; ThermalTransmittance: 0; FireExit: no; SelfClosing: no; SmokeStop: no; IsExternal: no
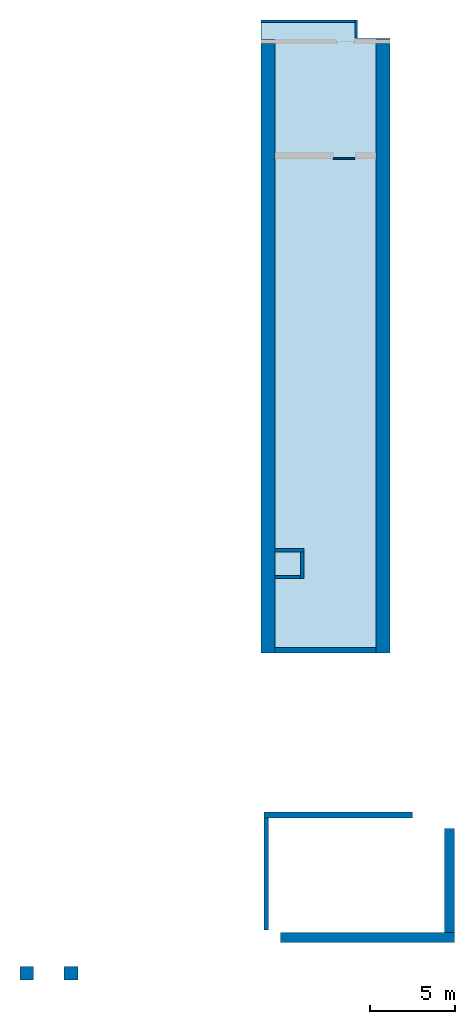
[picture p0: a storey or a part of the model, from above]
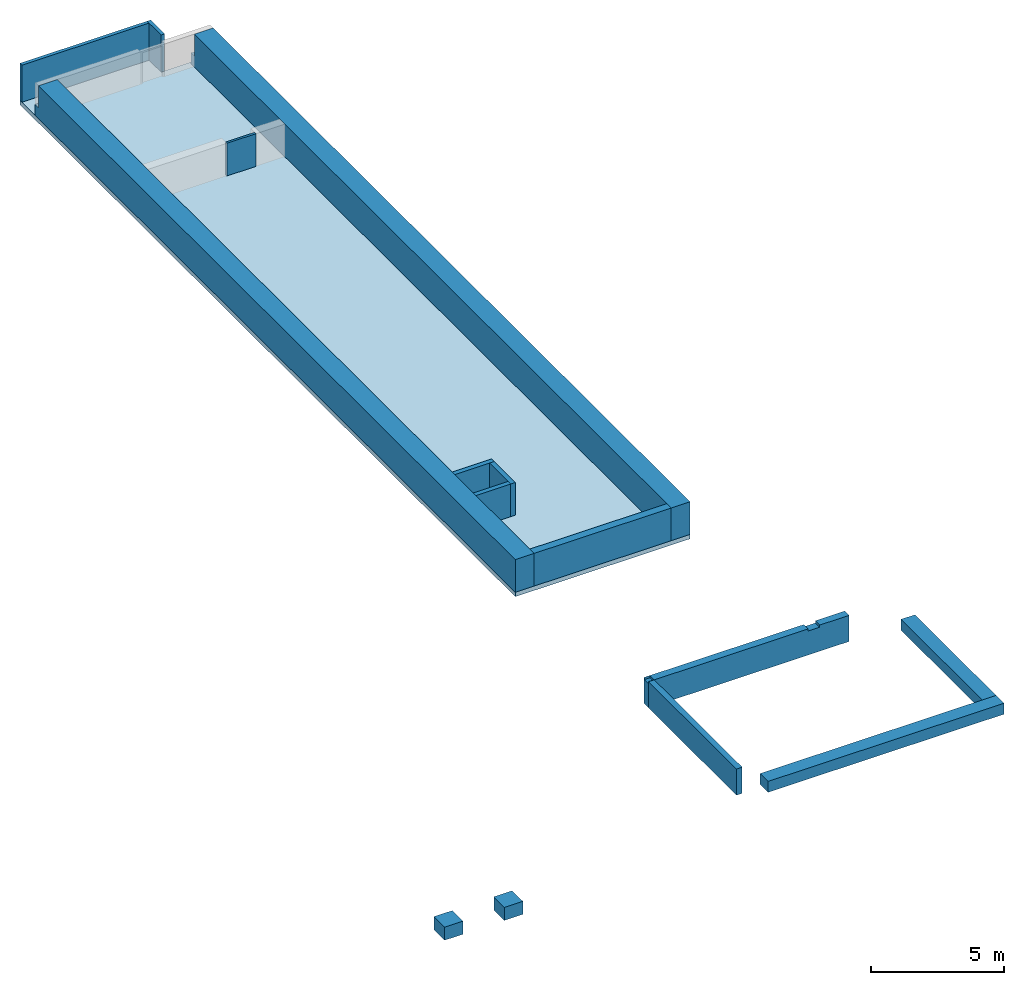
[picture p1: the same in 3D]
Properties of the parts of a building model (IFC2X3), part 4 of 7

# IfcDoor: D2 27, _Merk-x
Material - Frame / Draaiend deel: n.v.t.; Deurblad: n.v.t.; Onderdorpel: n.v.t.; Stofdorpel: n.v.t.; Vensterbank: n.v.t.; Ventilatierooster: n.v.t.; Spouwlat: n.v.t.; Rollaag / Latei: n.v.t.; Afwerking dagkant buiten: n.v.t.; Afwerking dagkant binnen: n.v.t.; Zonwering - behuizing: n.v.t.; Zonwering - isolatie: n.v.t.; Glas: Glas - algemeen
CPset_Phasing - Renovation Phase: Nieuw

# IfcDoor: D2 27 (2)
Type - OperationType: DOUBLE_DOOR_SINGLE_SWING; ParameterTakesPrecedence: no; Sizeable: no
Type - Door Lining Properties - LiningDepth: 114 mm; LiningThickness: 67 mm; LiningOffset: -7 mm
Type - Door Panel Properties - Panel 1 - PanelDepth: 40 mm; PanelOperation: SWINGING; PanelWidth: 0.507083; PanelPosition: LEFT
Type - Door Panel Properties - Panel 2 - PanelDepth: 40 mm; PanelOperation: SWINGING; PanelWidth: 0.507083; PanelPosition: RIGHT
OverallHeight: 2400 mm; OverallWidth: 2534 mm
Pset_DoorCommon - FireRating: n.v.t.; SecurityRating: FALSE; ThermalTransmittance: 0; GlazingAreaFraction: 4.1697; FireExit: no; SelfClosing: no; SmokeStop: no; IsExternal: no
Material - Frame / Draaiend deel: n.v.t.; Deurblad: n.v.t.; Onderdorpel: n.v.t.; Stofdorpel: n.v.t.; Vensterbank: n.v.t.; Ventilatierooster: n.v.t.; Spouwlat: n.v.t.; Rollaag / Latei: n.v.t.; Afwerking dagkant buiten: n.v.t.; Afwerking dagkant binnen: n.v.t.; Zonwering - behuizing: n.v.t.; Zonwering - isolatie: n.v.t.; Glas: Glas - algemeen
Pset_FireRatingProperties - FireResistanceRating: 60 minuten brandwerend en zelfsluitend
CPset_Phasing - Renovation Phase: Nieuw
Name | In
_Merk-x | Begane grond N
_Merk-x | 1e verdieping N

# IfcDoor: D2 27, _Merk-x
In: Begane grond N
Type - OperationType: DOUBLE_DOOR_SINGLE_SWING; ParameterTakesPrecedence: no; Sizeable: no
Type - Door Lining Properties - LiningDepth: 114 mm; LiningThickness: 67 mm; LiningOffset: 0 mm
Type - Door Panel Properties - Panel 1 - PanelDepth: 40 mm; PanelOperation: SWINGING; PanelWidth: 0.50911; PanelPosition: LEFT
Type - Door Panel Properties - Panel 2 - PanelDepth: 40 mm; PanelOperation: SWINGING; PanelWidth: 0.50911; PanelPosition: RIGHT
OverallHeight: 2400 mm; OverallWidth: 2000 mm
Pset_DoorCommon - FireRating: n.v.t.; SecurityRating: FALSE; ThermalTransmittance: 0; GlazingAreaFraction: 3.075; FireExit: no; SelfClosing: no; SmokeStop: no; IsExternal: no
Material - Frame / Draaiend deel: n.v.t.; Deurblad: n.v.t.; Onderdorpel: n.v.t.; Stofdorpel: n.v.t.; Vensterbank: n.v.t.; Ventilatierooster: n.v.t.; Spouwlat: n.v.t.; Rollaag / Latei: n.v.t.; Afwerking dagkant buiten: n.v.t.; Afwerking dagkant binnen: n.v.t.; Zonwering - behuizing: n.v.t.; Zonwering - isolatie: n.v.t.; Glas: Glas - algemeen
CPset_Phasing - Renovation Phase: Nieuw

# IfcDoor: D2 27, _Merk-x
In: Begane grond N
Type - OperationType: DOUBLE_DOOR_SINGLE_SWING; ParameterTakesPrecedence: no; Sizeable: no
Type - Door Lining Properties - LiningDepth: 114 mm; LiningThickness: 67 mm; LiningOffset: 86 mm
Type - Door Panel Properties - Panel 1 - PanelDepth: 40 mm; PanelOperation: SWINGING; PanelWidth: 0.514395; PanelPosition: RIGHT
Type - Door Panel Properties - Panel 2 - PanelDepth: 40 mm; PanelOperation: SWINGING; PanelWidth: 0.514395; PanelPosition: LEFT
OverallHeight: 2100 mm; OverallWidth: 1315 mm
Pset_DoorCommon - FireRating: n.v.t.; SecurityRating: FALSE; ThermalTransmittance: 0; FireExit: no; SelfClosing: no; SmokeStop: no; IsExternal: no
CPset_Phasing - Renovation Phase: Bestaand
Material - Frame / Draaiend deel: n.v.t.; Deurblad: n.v.t.; Onderdorpel: n.v.t.; Stofdorpel: n.v.t.; Vensterbank: n.v.t.; Ventilatierooster: n.v.t.; Spouwlat: n.v.t.; Rollaag / Latei: n.v.t.; Afwerking dagkant buiten: n.v.t.; Afwerking dagkant binnen: n.v.t.; Zonwering - behuizing: n.v.t.; Zonwering - isolatie: n.v.t.; Glas: Glas - algemeen

# IfcDoor: D2 27, _Merk-x
In: Begane grond N
Type - OperationType: DOUBLE_DOOR_SINGLE_SWING_OPPOSITE_RIGHT; ParameterTakesPrecedence: no; Sizeable: no
Type - Door Lining Properties - LiningDepth: 114 mm; LiningThickness: 67 mm; LiningOffset: -114 mm
Type - Door Panel Properties - Panel 1 - PanelDepth: 40 mm; PanelOperation: SWINGING; PanelWidth: 0.5; PanelPosition: LEFT
Type - Door Panel Properties - Panel 2 - PanelDepth: 40 mm; PanelOperation: SWINGING; PanelWidth: 0.5; PanelPosition: RIGHT
OverallHeight: 2400 mm; OverallWidth: 2484.92 mm
Pset_DoorCommon - FireRating: n.v.t.; SecurityRating: FALSE; ThermalTransmittance: 0; GlazingAreaFraction: 3.96622; FireExit: no; SelfClosing: no; SmokeStop: no; IsExternal: no
Material - Frame / Draaiend deel: n.v.t.; Deurblad: n.v.t.; Onderdorpel: n.v.t.; Stofdorpel: n.v.t.; Vensterbank: n.v.t.; Ventilatierooster: n.v.t.; Spouwlat: n.v.t.; Rollaag / Latei: n.v.t.; Afwerking dagkant buiten: n.v.t.; Afwerking dagkant binnen: n.v.t.; Zonwering - behuizing: n.v.t.; Zonwering - isolatie: n.v.t.; Glas: Glas - algemeen
Pset_FireRatingProperties - FireResistanceRating: Zelfsluitend
CPset_Phasing - Renovation Phase: Nieuw

# IfcDoor: D2 bl 26, _Merk-F001
In: Begane grond N
Type - OperationType: DOUBLE_DOOR_SINGLE_SWING; ParameterTakesPrecedence: no; Sizeable: no
Type - Door Lining Properties - LiningDepth: 114 mm; LiningThickness: 67 mm; TransomThickness: 67 mm; TransomOffset: 2400 mm; LiningOffset: 126 mm
Type - Door Panel Properties - Panel 1 - PanelDepth: 40 mm; PanelOperation: SWINGING; PanelWidth: 0.506625; PanelPosition: LEFT
Type - Door Panel Properties - Panel 2 - PanelDepth: 40 mm; PanelOperation: SWINGING; PanelWidth: 0.506625; PanelPosition: RIGHT
OverallHeight: 3360 mm; OverallWidth: 2700 mm
Pset_DoorCommon - FireRating: n.v.t.; SecurityRating: FALSE; ThermalTransmittance: 0; GlazingAreaFraction: 2.40632; FireExit: no; SelfClosing: no; SmokeStop: no; IsExternal: no
Pset_FireRatingProperties - FireResistanceRating: Zelfsluitend
Material - Frame / Draaiend deel: n.v.t.; Deurblad: n.v.t.; Onderdorpel: n.v.t.; Stofdorpel: n.v.t.; Vensterbank: n.v.t.; Ventilatierooster: n.v.t.; Spouwlat: n.v.t.; Rollaag / Latei: n.v.t.; Afwerking dagkant buiten: n.v.t.; Afwerking dagkant binnen: n.v.t.; Zonwering - behuizing: n.v.t.; Zonwering - isolatie: n.v.t.; Glas: Glas - algemeen
CPset_Phasing - Renovation Phase: Nieuw

# IfcDoor: D2 bl 26, _Merk-003
In: Begane grond N
Type - OperationType: DOUBLE_DOOR_SINGLE_SWING; ParameterTakesPrecedence: no; Sizeable: no
Type - Door Lining Properties - LiningDepth: 114 mm; LiningThickness: 67 mm; TransomThickness: 67 mm; TransomOffset: 2700 mm; LiningOffset: 116 mm
Type - Door Panel Properties - Panel 1 - PanelDepth: 40 mm; PanelOperation: SWINGING; PanelWidth: 0.50911; PanelPosition: RIGHT
Type - Door Panel Properties - Panel 2 - PanelDepth: 40 mm; PanelOperation: SWINGING; PanelWidth: 0.50911; PanelPosition: LEFT
OverallHeight: 3700 mm; OverallWidth: 2000 mm
Pset_DoorCommon - FireRating: n.v.t.; SecurityRating: FALSE; ThermalTransmittance: 0; GlazingAreaFraction: 2.02276; FireExit: no; SelfClosing: no; SmokeStop: no; IsExternal: no
Material - Frame / Draaiend deel: n.v.t.; Deurblad: n.v.t.; Onderdorpel: n.v.t.; Stofdorpel: n.v.t.; Vensterbank: n.v.t.; Ventilatierooster: n.v.t.; Spouwlat: n.v.t.; Rollaag / Latei: n.v.t.; Afwerking dagkant buiten: n.v.t.; Afwerking dagkant binnen: n.v.t.; Zonwering - behuizing: n.v.t.; Zonwering - isolatie: n.v.t.; Glas: Glas - algemeen
Pset_FireRatingProperties - FireResistanceRating: Zelfsluitend
CPset_Phasing - Renovation Phase: Nieuw

# IfcDoor: D2 bl 27, _Merk-x
In: 1e verdieping N
Type - OperationType: DOUBLE_DOOR_SINGLE_SWING; ParameterTakesPrecedence: no; Sizeable: no
Type - Door Lining Properties - LiningDepth: 114 mm; LiningThickness: 67 mm; TransomThickness: 67 mm; TransomOffset: 2100 mm; LiningOffset: -114 mm
Type - Door Panel Properties - Panel 1 - PanelDepth: 40 mm; PanelOperation: SWINGING; PanelWidth: 0.508647; PanelPosition: RIGHT
Type - Door Panel Properties - Panel 2 - PanelDepth: 40 mm; PanelOperation: SWINGING; PanelWidth: 0.508647; PanelPosition: LEFT
OverallHeight: 2400 mm; OverallWidth: 2100 mm
Pset_DoorCommon - FireRating: n.v.t.; SecurityRating: FALSE; ThermalTransmittance: 0; GlazingAreaFraction: 3.23356; FireExit: no; SelfClosing: no; SmokeStop: no; IsExternal: no
Material - Frame / Draaiend deel: n.v.t.; Deurblad: n.v.t.; Onderdorpel: n.v.t.; Stofdorpel: n.v.t.; Vensterbank: n.v.t.; Ventilatierooster: n.v.t.; Spouwlat: n.v.t.; Rollaag / Latei: n.v.t.; Afwerking dagkant buiten: n.v.t.; Afwerking dagkant binnen: n.v.t.; Zonwering - behuizing: n.v.t.; Zonwering - isolatie: n.v.t.; Glas: Glas - algemeen
Pset_FireRatingProperties - FireResistanceRating: 60 minuten brandwerend en zelfsluitend
CPset_Phasing - Renovation Phase: Nieuw

# IfcDoor: D2 bl 27, _Merk-x
In: Begane grond N
Type - OperationType: DOUBLE_DOOR_SINGLE_SWING; ParameterTakesPrecedence: no; Sizeable: no
Type - Door Lining Properties - LiningDepth: 114 mm; LiningThickness: 67 mm; TransomThickness: 67 mm; TransomOffset: 2100 mm; LiningOffset: -14 mm
Type - Door Panel Properties - Panel 1 - PanelDepth: 40 mm; PanelOperation: SWINGING; PanelWidth: 0.508647; PanelPosition: RIGHT
Type - Door Panel Properties - Panel 2 - PanelDepth: 40 mm; PanelOperation: SWINGING; PanelWidth: 0.508647; PanelPosition: LEFT
OverallHeight: 2400 mm; OverallWidth: 2100 mm
Pset_FireRatingProperties - FireResistanceRating: 60 minuten brandwerend en zelfsluitend
Pset_DoorCommon - FireRating: n.v.t.; SecurityRating: FALSE; ThermalTransmittance: 0; GlazingAreaFraction: 3.23356; FireExit: no; SelfClosing: no; SmokeStop: no; IsExternal: no
Material - Frame / Draaiend deel: n.v.t.; Deurblad: n.v.t.; Onderdorpel: n.v.t.; Stofdorpel: n.v.t.; Vensterbank: n.v.t.; Ventilatierooster: n.v.t.; Spouwlat: n.v.t.; Rollaag / Latei: n.v.t.; Afwerking dagkant buiten: n.v.t.; Afwerking dagkant binnen: n.v.t.; Zonwering - behuizing: n.v.t.; Zonwering - isolatie: n.v.t.; Glas: Glas - algemeen
CPset_Phasing - Renovation Phase: Nieuw

# IfcDoor: D2 bl 27 (2)
In: 2e verdieping V
Type - OperationType: DOUBLE_DOOR_SINGLE_SWING; ParameterTakesPrecedence: no; Sizeable: no
Type - Door Lining Properties - LiningDepth: 114 mm; LiningThickness: 67 mm; TransomThickness: 67 mm; TransomOffset: 2100 mm; LiningOffset: -14 mm
Type - Door Panel Properties - Panel 1 - PanelDepth: 40 mm; PanelOperation: SWINGING; PanelWidth: 0.510215; PanelPosition: LEFT
Type - Door Panel Properties - Panel 2 - PanelDepth: 40 mm; PanelOperation: SWINGING; PanelWidth: 0.510215; PanelPosition: RIGHT
OverallHeight: 2400 mm; OverallWidth: 1798.15 mm
Pset_DoorCommon - FireRating: n.v.t.; SecurityRating: FALSE; ThermalTransmittance: 0; GlazingAreaFraction: 0.276249; FireExit: no; SelfClosing: no; SmokeStop: no; IsExternal: no
Material - Frame / Draaiend deel: n.v.t.; Deurblad: n.v.t.; Onderdorpel: n.v.t.; Stofdorpel: n.v.t.; Vensterbank: n.v.t.; Ventilatierooster: n.v.t.; Spouwlat: n.v.t.; Rollaag / Latei: n.v.t.; Afwerking dagkant buiten: n.v.t.; Afwerking dagkant binnen: n.v.t.; Zonwering - behuizing: n.v.t.; Zonwering - isolatie: n.v.t.; Glas: Glas - algemeen
CPset_Phasing - Renovation Phase: Bestaand

# IfcDoor: D2 bl 27 (2)
In: Begane grond N
Type - OperationType: DOUBLE_DOOR_SINGLE_SWING; ParameterTakesPrecedence: no; Sizeable: no
Type - Door Lining Properties - LiningDepth: 114 mm; LiningThickness: 67 mm; TransomThickness: 67 mm; TransomOffset: 2100 mm; LiningOffset: -39 mm
Type - Door Panel Properties - Panel 1 - PanelDepth: 40 mm; PanelOperation: SWINGING; PanelWidth: 0.508691; PanelPosition: LEFT
Type - Door Panel Properties - Panel 2 - PanelDepth: 40 mm; PanelOperation: SWINGING; PanelWidth: 0.508691; PanelPosition: RIGHT
OverallHeight: 2400 mm; OverallWidth: 2090 mm
Pset_DoorCommon - FireRating: n.v.t.; SecurityRating: FALSE; ThermalTransmittance: 0; GlazingAreaFraction: 0.324696; FireExit: no; SelfClosing: no; SmokeStop: no; IsExternal: no
Material - Frame / Draaiend deel: n.v.t.; Deurblad: n.v.t.; Onderdorpel: n.v.t.; Stofdorpel: n.v.t.; Vensterbank: n.v.t.; Ventilatierooster: n.v.t.; Spouwlat: n.v.t.; Rollaag / Latei: n.v.t.; Afwerking dagkant buiten: n.v.t.; Afwerking dagkant binnen: n.v.t.; Zonwering - behuizing: n.v.t.; Zonwering - isolatie: n.v.t.; Glas: Glas - algemeen
CPset_Phasing - Renovation Phase: Bestaand

# IfcDoor: D2 bl 27, _Merk-x
In: Begane grond N
Type - OperationType: DOUBLE_DOOR_SINGLE_SWING; ParameterTakesPrecedence: no; Sizeable: no
Type - Door Lining Properties - LiningDepth: 114 mm; LiningThickness: 67 mm; TransomThickness: 67 mm; TransomOffset: 2100 mm; LiningOffset: 0 mm
Type - Door Panel Properties - Panel 1 - PanelDepth: 40 mm; PanelOperation: SWINGING; PanelWidth: 0.50911; PanelPosition: RIGHT
Type - Door Panel Properties - Panel 2 - PanelDepth: 40 mm; PanelOperation: SWINGING; PanelWidth: 0.50911; PanelPosition: LEFT
OverallHeight: 2400 mm; OverallWidth: 2000 mm
Pset_DoorCommon - FireRating: n.v.t.; SecurityRating: FALSE; ThermalTransmittance: 0; GlazingAreaFraction: 0.309756; FireExit: no; SelfClosing: no; SmokeStop: no; IsExternal: no
Material - Frame / Draaiend deel: n.v.t.; Deurblad: n.v.t.; Onderdorpel: n.v.t.; Stofdorpel: n.v.t.; Vensterbank: n.v.t.; Ventilatierooster: n.v.t.; Spouwlat: n.v.t.; Rollaag / Latei: n.v.t.; Afwerking dagkant buiten: n.v.t.; Afwerking dagkant binnen: n.v.t.; Zonwering - behuizing: n.v.t.; Zonwering - isolatie: n.v.t.; Glas: Glas - algemeen
CPset_Phasing - Renovation Phase: Nieuw

# IfcDoor: D2 bl 27, _Merk-x
In: 2e verdieping V
Type - OperationType: DOUBLE_DOOR_SINGLE_SWING; ParameterTakesPrecedence: no; Sizeable: no
Type - Door Lining Properties - LiningDepth: 114 mm; LiningThickness: 67 mm; TransomThickness: 67 mm; TransomOffset: 2100 mm; LiningOffset: 0 mm
Type - Door Panel Properties - Panel 1 - PanelDepth: 40 mm; PanelOperation: SWINGING; PanelWidth: 0.510215; PanelPosition: LEFT
Type - Door Panel Properties - Panel 2 - PanelDepth: 40 mm; PanelOperation: SWINGING; PanelWidth: 0.510215; PanelPosition: RIGHT
OverallHeight: 2400 mm; OverallWidth: 1798.15 mm
Pset_DoorCommon - FireRating: n.v.t.; SecurityRating: FALSE; ThermalTransmittance: 0; GlazingAreaFraction: 0.276249; FireExit: no; SelfClosing: no; SmokeStop: no; IsExternal: no
Material - Frame / Draaiend deel: n.v.t.; Deurblad: n.v.t.; Onderdorpel: n.v.t.; Stofdorpel: n.v.t.; Vensterbank: n.v.t.; Ventilatierooster: n.v.t.; Spouwlat: n.v.t.; Rollaag / Latei: n.v.t.; Afwerking dagkant buiten: n.v.t.; Afwerking dagkant binnen: n.v.t.; Zonwering - behuizing: n.v.t.; Zonwering - isolatie: n.v.t.; Glas: Glas - algemeen
CPset_Phasing - Renovation Phase: Bestaand

# IfcDoor: D2 bl 27, _Merk-x
In: 6e verdieping V
Type - OperationType: DOUBLE_DOOR_SINGLE_SWING; ParameterTakesPrecedence: no; Sizeable: no
Type - Door Lining Properties - LiningDepth: 114 mm; LiningThickness: 67 mm; TransomThickness: 67 mm; TransomOffset: 2100 mm; LiningOffset: 11 mm
Type - Door Panel Properties - Panel 1 - PanelDepth: 40 mm; PanelOperation: SWINGING; PanelWidth: 0.510204; PanelPosition: LEFT
Type - Door Panel Properties - Panel 2 - PanelDepth: 40 mm; PanelOperation: SWINGING; PanelWidth: 0.510204; PanelPosition: RIGHT
OverallHeight: 2400 mm; OverallWidth: 1800 mm
Material - Frame / Draaiend deel: n.v.t.; Deurblad: n.v.t.; Onderdorpel: n.v.t.; Stofdorpel: n.v.t.; Vensterbank: n.v.t.; Ventilatierooster: n.v.t.; Spouwlat: n.v.t.; Rollaag / Latei: n.v.t.; Afwerking dagkant buiten: n.v.t.; Afwerking dagkant binnen: n.v.t.; Zonwering - behuizing: n.v.t.; Zonwering - isolatie: n.v.t.; Glas: Glas - algemeen
Pset_DoorCommon - FireRating: n.v.t.; SecurityRating: FALSE; ThermalTransmittance: 0; GlazingAreaFraction: 0.276556; FireExit: no; SelfClosing: no; SmokeStop: no; IsExternal: no
CPset_Phasing - Renovation Phase: Bestaand

# IfcDoor: D2 bl 27 (2)
Type - OperationType: DOUBLE_DOOR_SINGLE_SWING; ParameterTakesPrecedence: no; Sizeable: no
Type - Door Lining Properties - LiningDepth: 114 mm; LiningThickness: 67 mm; TransomThickness: 67 mm; TransomOffset: 2100 mm; LiningOffset: 11 mm
Type - Door Panel Properties - Panel 1 - PanelDepth: 40 mm; PanelOperation: SWINGING; PanelWidth: 0.510204; PanelPosition: RIGHT
Type - Door Panel Properties - Panel 2 - PanelDepth: 40 mm; PanelOperation: SWINGING; PanelWidth: 0.510204; PanelPosition: LEFT
OverallHeight: 2400 mm; OverallWidth: 1800 mm
Pset_DoorCommon - FireRating: n.v.t.; SecurityRating: FALSE; ThermalTransmittance: 0; GlazingAreaFraction: 0.276556; FireExit: no; SelfClosing: no; SmokeStop: no; IsExternal: no
Material - Frame / Draaiend deel: n.v.t.; Deurblad: n.v.t.; Onderdorpel: n.v.t.; Stofdorpel: n.v.t.; Vensterbank: n.v.t.; Ventilatierooster: n.v.t.; Spouwlat: n.v.t.; Rollaag / Latei: n.v.t.; Afwerking dagkant buiten: n.v.t.; Afwerking dagkant binnen: n.v.t.; Zonwering - behuizing: n.v.t.; Zonwering - isolatie: n.v.t.; Glas: Glas - algemeen
CPset_Phasing - Renovation Phase: Bestaand
Name | In
_Merk-x | 4e verdieping V
_Merk-x | 5e verdieping V

# IfcDoor: D2 zl1 27 (2)
In: 1e verdieping N
Type - OperationType: USERDEFINED; ParameterTakesPrecedence: no; Sizeable: no
OverallHeight: 2550 mm; OverallWidth: 3200 mm
Material - Frame / Draaiend deel: n.v.t.; Deurblad: n.v.t.; Onderdorpel: n.v.t.; Stofdorpel: n.v.t.; Vensterbank: n.v.t.; Ventilatierooster: n.v.t.; Spouwlat: n.v.t.; Rollaag / Latei: n.v.t.; Afwerking dagkant buiten: n.v.t.; Afwerking dagkant binnen: n.v.t.; Zonwering - behuizing: n.v.t.; Zonwering - isolatie: n.v.t.; Glas: Glas - algemeen
Pset_DoorCommon - FireRating: n.v.t.; SecurityRating: FALSE; ThermalTransmittance: 0; GlazingAreaFraction: 2.80256; FireExit: no; SelfClosing: no; SmokeStop: no; IsExternal: no
CPset_Phasing - Renovation Phase: Bestaand

# IfcDoor: D2 zl2 27 (3)
Type - OperationType: USERDEFINED; ParameterTakesPrecedence: no; Sizeable: no
OverallHeight: 2400 mm; OverallWidth: 2300 mm
Pset_DoorCommon - FireRating: n.v.t.; SecurityRating: FALSE; ThermalTransmittance: 0; GlazingAreaFraction: 0.299112; FireExit: no; SelfClosing: no; SmokeStop: no; IsExternal: no
Material - Frame / Draaiend deel: n.v.t.; Deurblad: n.v.t.; Onderdorpel: n.v.t.; Stofdorpel: n.v.t.; Vensterbank: n.v.t.; Ventilatierooster: n.v.t.; Spouwlat: n.v.t.; Rollaag / Latei: n.v.t.; Afwerking dagkant buiten: n.v.t.; Afwerking dagkant binnen: n.v.t.; Zonwering - behuizing: n.v.t.; Zonwering - isolatie: n.v.t.; Glas: Glas - algemeen
Pset_FireRatingProperties - FireResistanceRating: 60 minuten brandwerend en zelfsluitend
CPset_Phasing - Renovation Phase: Nieuw
Name | In
_Merk-x | Begane grond N
_Merk-x | 1e verdieping N
_Merk-x | 2e verdieping N

# IfcDoor: DS1 in wand 26 (18)
Type - OperationType: USERDEFINED; ParameterTakesPrecedence: no; Sizeable: no
OverallHeight: 2400 mm
Pset_DoorCommon - FireRating: n.v.t.; SecurityRating: FALSE; ThermalTransmittance: 0; FireExit: no; SelfClosing: no; SmokeStop: no; IsExternal: no
Material - Frame / Draaiend deel: n.v.t.; Deurblad: Dichte arcering; Onderdorpel: n.v.t.; Stofdorpel: n.v.t.; Vensterbank: n.v.t.; Spouwlat: n.v.t.; Rollaag / Latei: n.v.t.; Afwerking dagkant buiten: n.v.t.; Afwerking dagkant binnen: n.v.t.; Zonwering - behuizing: n.v.t.; Zonwering - isolatie: n.v.t.; Glas: Glas - algemeen
CPset_Phasing - Renovation Phase: Nieuw
Name | In | OverallWidth (mm)
_Merk-x | Begane grond N | 840
5 x _Merk-x | Begane grond N | 1040
6 x _Merk-x | 1e verdieping N | 1040
6 x _Merk-x | 2e verdieping N | 1040

# IfcDoor: DS1 voor wand 27, _
In: 1e verdieping N
Type - OperationType: SLIDING_TO_RIGHT; ParameterTakesPrecedence: no; Sizeable: no
Type - Door Panel Properties - Panel 1 - PanelDepth: 40 mm; PanelOperation: SLIDING; PanelWidth: 1; PanelPosition: MIDDLE
OverallHeight: 2400 mm; OverallWidth: 1545 mm
Pset_DoorCommon - FireRating: n.v.t.; SecurityRating: FALSE; ThermalTransmittance: 0; GlazingAreaFraction: 2.8245; FireExit: no; SelfClosing: no; SmokeStop: no; IsExternal: no
Material - Frame / Draaiend deel: n.v.t.; Deurblad: n.v.t.; Onderdorpel: n.v.t.; Stofdorpel: n.v.t.; Vensterbank: n.v.t.; Spouwlat: n.v.t.; Rollaag / Latei: n.v.t.; Afwerking dagkant buiten: n.v.t.; Afwerking dagkant binnen: n.v.t.; Zonwering - behuizing: n.v.t.; Zonwering - isolatie: n.v.t.; Glas: Glas - algemeen
Pset_FireRatingProperties - FireResistanceRating: 60 minuten brandwerend en zelfsluitend
CPset_Phasing - Renovation Phase: Nieuw

# IfcDoor: NLRS_32_DO_deur enkel_WID:930x2315 muurdikte 100mm (28)
Type - ParameterTakesPrecedence: no; Sizeable: no
OverallHeight: 2357 mm; OverallWidth: 1014 mm
Pset_QuantityTakeOff - Reference: 930x2315 muurdikte 100mm
CPset_Phasing - Renovation Phase: Nieuw
Pset_DoorCommon - Reference: 930x2315 muurdikte 100mm; IsExternal: no
Name (NLRS_32_DO_deur enkel_WID:930x2315 muurdikte 100mm:...) | In | Material | hout_stijl_dorpel, ThermalConductivity | hout_stijl_dorpel, SpecificHeatCapacity (J/kg/K) | hout_stijl_dorpel, MassDensity (kg/m3) | hout_stijl_dorpel, Embodied Energy | hout_stijl_dorpel, Embodied Carbon | hout_stijl_dorpel, Name | hout_stijl_dorpel, Participates in Collision Detection
2729594 | 1e verdieping N | hout_stijl_dorpel | 2.3 | 1000 | 2300 | 1.92 (MJ/kg) | 0.198 (kgCO₂/kg) | hout_stijl_dorpel | yes
2039360 | 1e verdieping N | hout_stijl_dorpel | 2.3 | 1000 | 2300 | 1.92 (MJ/kg) | 0.198 (kgCO₂/kg) | hout_stijl_dorpel | yes
2039366 | 1e verdieping N | hout_stijl_dorpel | 2.3 | 1000 | 2300 | 1.92 (MJ/kg) | 0.198 (kgCO₂/kg) | hout_stijl_dorpel | yes
2947395 | 1e verdieping N | hout_stijl_dorpel | 2.3 | 1000 | 2300 | 1.92 (MJ/kg) | 0.198 (kgCO₂/kg) | hout_stijl_dorpel | yes
2039114 | 2e verdieping N | hout_stijl_dorpel | 2.3 | 1000 | 2300 | 1.92 (MJ/kg) | 0.198 (kgCO₂/kg) | hout_stijl_dorpel | yes
2039120 | 2e verdieping N | hout_stijl_dorpel | 2.3 | 1000 | 2300 | 1.92 (MJ/kg) | 0.198 (kgCO₂/kg) | hout_stijl_dorpel | yes
2013369 | 2e verdieping V | hout_stijl_dorpel | 2.3 | 1000 | 2300 | 1.92 (MJ/kg) | 0.198 (kgCO₂/kg) | hout_stijl_dorpel | yes | Group: Model Group:V vluchttrappenhuis 2:2013401
2013375 | 2e verdieping V | hout_stijl_dorpel | 2.3 | 1000 | 2300 | 1.92 (MJ/kg) | 0.198 (kgCO₂/kg) | hout_stijl_dorpel | yes | Group: Model Group:V vluchttrappenhuis 2:2013401
2013445 | 3e verdieping/dak N | hout_stijl_dorpel | 2.3 | 1000 | 2300 | 1.92 (MJ/kg) | 0.198 (kgCO₂/kg) | hout_stijl_dorpel | yes | Group: Model Group:V vluchttrappenhuis 2:2013471
2013439 | 3e verdieping/dak N | hout_stijl_dorpel | 2.3 | 1000 | 2300 | 1.92 (MJ/kg) | 0.198 (kgCO₂/kg) | hout_stijl_dorpel | yes | Group: Model Group:V vluchttrappenhuis 2:2013471
2013642 | 3e verdieping V | hout_stijl_dorpel | 2.3 | 1000 | 2300 | 1.92 (MJ/kg) | 0.198 (kgCO₂/kg) | hout_stijl_dorpel | yes | Group: Model Group:V vluchttrappenhuis 2:2013517
2013636 | 3e verdieping V | hout_stijl_dorpel | 2.3 | 1000 | 2300 | 1.92 (MJ/kg) | 0.198 (kgCO₂/kg) | hout_stijl_dorpel | yes | Group: Model Group:V vluchttrappenhuis 2:2013517
3085508 | 4e verdieping V | hout_stijl_dorpel | 2.3 | 1000 | 2300 | 1.92 (MJ/kg) | 0.198 (kgCO₂/kg) | hout_stijl_dorpel | yes | Group: Model Group:V vluchttrappenhuis 2:2013112
3085502 | 4e verdieping V | hout_stijl_dorpel | 2.3 | 1000 | 2300 | 1.92 (MJ/kg) | 0.198 (kgCO₂/kg) | hout_stijl_dorpel | yes | Group: Model Group:V vluchttrappenhuis 2:2013112
2536017 | 5e verdieping V | hout - RAL 9010 - Zuiver wit | Material Properties - hout - RAL 9010 - Zuiver wit, ThermalConductivity: 2.3; hout - RAL 9010 - Zuiver wit, SpecificHeatCapacity: 1000 J/kg/K; hout - RAL 9010 - Zuiver wit, MassDensity: 2300 kg/m3; hout - RAL 9010 - Zuiver wit, Embodied Energy: 1.92 (MJ/kg); hout - RAL 9010 - Zuiver wit, Embodied Carbon: 0.198 (kgCO₂/kg); hout - RAL 9010 - Zuiver wit, Name: hout - RAL 9010 - Zuiver wit; hout - RAL 9010 - Zuiver wit, Participates in Collision Detection: yes
2539801 | 5e verdieping V | hout_stijl_dorpel | 2.3 | 1000 | 2300 | 1.92 (MJ/kg) | 0.198 (kgCO₂/kg) | hout_stijl_dorpel | yes
2535975 | 5e verdieping V | hout_stijl_dorpel | 2.3 | 1000 | 2300 | 1.92 (MJ/kg) | 0.198 (kgCO₂/kg) | hout_stijl_dorpel | yes
2536748 | 5e verdieping V | hout_stijl_dorpel | 2.3 | 1000 | 2300 | 1.92 (MJ/kg) | 0.198 (kgCO₂/kg) | hout_stijl_dorpel | yes
2535806 | 5e verdieping V | hout - RAL 9010 - Zuiver wit | Material Properties - hout - RAL 9010 - Zuiver wit, ThermalConductivity: 2.3; hout - RAL 9010 - Zuiver wit, SpecificHeatCapacity: 1000 J/kg/K; hout - RAL 9010 - Zuiver wit, MassDensity: 2300 kg/m3; hout - RAL 9010 - Zuiver wit, Embodied Energy: 1.92 (MJ/kg); hout - RAL 9010 - Zuiver wit, Embodied Carbon: 0.198 (kgCO₂/kg); hout - RAL 9010 - Zuiver wit, Name: hout - RAL 9010 - Zuiver wit; hout - RAL 9010 - Zuiver wit, Participates in Collision Detection: yes
2541193 | 5e verdieping V | hout - RAL 9010 - Zuiver wit | Material Properties - hout - RAL 9010 - Zuiver wit, ThermalConductivity: 2.3; hout - RAL 9010 - Zuiver wit, SpecificHeatCapacity: 1000 J/kg/K; hout - RAL 9010 - Zuiver wit, MassDensity: 2300 kg/m3; hout - RAL 9010 - Zuiver wit, Embodied Energy: 1.92 (MJ/kg); hout - RAL 9010 - Zuiver wit, Embodied Carbon: 0.198 (kgCO₂/kg); hout - RAL 9010 - Zuiver wit, Name: hout - RAL 9010 - Zuiver wit; hout - RAL 9010 - Zuiver wit, Participates in Collision Detection: yes
2534527 | 5e verdieping V | hout_stijl_dorpel | 2.3 | 1000 | 2300 | 1.92 (MJ/kg) | 0.198 (kgCO₂/kg) | hout_stijl_dorpel | yes
2479717 | 5e verdieping V | hout_stijl_dorpel | 2.3 | 1000 | 2300 | 1.92 (MJ/kg) | 0.198 (kgCO₂/kg) | hout_stijl_dorpel | yes
2539738 | 5e verdieping V | hout_stijl_dorpel | 2.3 | 1000 | 2300 | 1.92 (MJ/kg) | 0.198 (kgCO₂/kg) | hout_stijl_dorpel | yes
2538393 | 5e verdieping V | hout_stijl_dorpel | 2.3 | 1000 | 2300 | 1.92 (MJ/kg) | 0.198 (kgCO₂/kg) | hout_stijl_dorpel | yes
2538625 | 5e verdieping V | hout_stijl_dorpel | 2.3 | 1000 | 2300 | 1.92 (MJ/kg) | 0.198 (kgCO₂/kg) | hout_stijl_dorpel | yes
2535730 | 5e verdieping V | hout_stijl_dorpel | 2.3 | 1000 | 2300 | 1.92 (MJ/kg) | 0.198 (kgCO₂/kg) | hout_stijl_dorpel | yes
3081062 | 5e verdieping V | hout_stijl_dorpel | 2.3 | 1000 | 2300 | 1.92 (MJ/kg) | 0.198 (kgCO₂/kg) | hout_stijl_dorpel | yes | Group: Model Group:V vluchttrappenhuis V5:3080963
3081068 | 5e verdieping V | hout_stijl_dorpel | 2.3 | 1000 | 2300 | 1.92 (MJ/kg) | 0.198 (kgCO₂/kg) | hout_stijl_dorpel | yes | Group: Model Group:V vluchttrappenhuis V5:3080963

# IfcDoor: NLRS_32_deur stomp dicht_WID:Deur (28)
Type - ParameterTakesPrecedence: no; Sizeable: no
Pset_QuantityTakeOff - Reference: Deur
Pset_DoorCommon - Reference: Deur; IsExternal: no
CPset_Phasing - Renovation Phase: Nieuw
Name (NLRS_32_deur stomp dicht_WID:Deur:...) | In | Material | <Unnamed>, ThermalConductivity | <Unnamed>, SpecificHeatCapacity (J/kg/K) | <Unnamed>, MassDensity (kg/m3) | <Unnamed>, Embodied Energy | <Unnamed>, Embodied Carbon | <Unnamed>, Name | <Unnamed>, Participates in Collision Detection
2729597 | 1e verdieping N | <Unnamed> | 2.3 | 1000 | 2300 | 1.92 (MJ/kg) | 0.198 (kgCO₂/kg) | <Unnamed> | yes
2039367 | 1e verdieping N | <Unnamed> | 2.3 | 1000 | 2300 | 1.92 (MJ/kg) | 0.198 (kgCO₂/kg) | <Unnamed> | yes
2039361 | 1e verdieping N | <Unnamed> | 2.3 | 1000 | 2300 | 1.92 (MJ/kg) | 0.198 (kgCO₂/kg) | <Unnamed> | yes
2947398 | 1e verdieping N | <Unnamed> | 2.3 | 1000 | 2300 | 1.92 (MJ/kg) | 0.198 (kgCO₂/kg) | <Unnamed> | yes
2039115 | 2e verdieping N | <Unnamed> | 2.3 | 1000 | 2300 | 1.92 (MJ/kg) | 0.198 (kgCO₂/kg) | <Unnamed> | yes
2039121 | 2e verdieping N | <Unnamed> | 2.3 | 1000 | 2300 | 1.92 (MJ/kg) | 0.198 (kgCO₂/kg) | <Unnamed> | yes
2013376 | 2e verdieping V | <Unnamed> | 2.3 | 1000 | 2300 | 1.92 (MJ/kg) | 0.198 (kgCO₂/kg) | <Unnamed> | yes | Group: Model Group:V vluchttrappenhuis 2:2013401
2013370 | 2e verdieping V | <Unnamed> | 2.3 | 1000 | 2300 | 1.92 (MJ/kg) | 0.198 (kgCO₂/kg) | <Unnamed> | yes | Group: Model Group:V vluchttrappenhuis 2:2013401
2013446 | 3e verdieping/dak N | <Unnamed> | 2.3 | 1000 | 2300 | 1.92 (MJ/kg) | 0.198 (kgCO₂/kg) | <Unnamed> | yes | Group: Model Group:V vluchttrappenhuis 2:2013471
2013440 | 3e verdieping/dak N | <Unnamed> | 2.3 | 1000 | 2300 | 1.92 (MJ/kg) | 0.198 (kgCO₂/kg) | <Unnamed> | yes | Group: Model Group:V vluchttrappenhuis 2:2013471
2013643 | 3e verdieping V | <Unnamed> | 2.3 | 1000 | 2300 | 1.92 (MJ/kg) | 0.198 (kgCO₂/kg) | <Unnamed> | yes | Group: Model Group:V vluchttrappenhuis 2:2013517
2013637 | 3e verdieping V | <Unnamed> | 2.3 | 1000 | 2300 | 1.92 (MJ/kg) | 0.198 (kgCO₂/kg) | <Unnamed> | yes | Group: Model Group:V vluchttrappenhuis 2:2013517
3085509 | 4e verdieping V | <Unnamed> | 2.3 | 1000 | 2300 | 1.92 (MJ/kg) | 0.198 (kgCO₂/kg) | <Unnamed> | yes | Group: Model Group:V vluchttrappenhuis 2:2013112
3085503 | 4e verdieping V | <Unnamed> | 2.3 | 1000 | 2300 | 1.92 (MJ/kg) | 0.198 (kgCO₂/kg) | <Unnamed> | yes | Group: Model Group:V vluchttrappenhuis 2:2013112
2539739 | 5e verdieping V | <Unnamed> | 2.3 | 1000 | 2300 | 1.92 (MJ/kg) | 0.198 (kgCO₂/kg) | <Unnamed> | yes
2535978 | 5e verdieping V | <Unnamed> | 2.3 | 1000 | 2300 | 1.92 (MJ/kg) | 0.198 (kgCO₂/kg) | <Unnamed> | yes
2539804 | 5e verdieping V | <Unnamed> | 2.3 | 1000 | 2300 | 1.92 (MJ/kg) | 0.198 (kgCO₂/kg) | <Unnamed> | yes
2534530 | 5e verdieping V | <Unnamed> | 2.3 | 1000 | 2300 | 1.92 (MJ/kg) | 0.198 (kgCO₂/kg) | <Unnamed> | yes
2536751 | 5e verdieping V | <Unnamed> | 2.3 | 1000 | 2300 | 1.92 (MJ/kg) | 0.198 (kgCO₂/kg) | <Unnamed> | yes
2538626 | 5e verdieping V | <Unnamed> | 2.3 | 1000 | 2300 | 1.92 (MJ/kg) | 0.198 (kgCO₂/kg) | <Unnamed> | yes
2535809 | 5e verdieping V | IFC Building Material | Material Properties - IFC Building Material, ThermalConductivity: 2.3; IFC Building Material, SpecificHeatCapacity: 1000 J/kg/K; IFC Building Material, MassDensity: 2300 kg/m3; IFC Building Material, Embodied Energy: 1.92 (MJ/kg); IFC Building Material, Embodied Carbon: 0.198 (kgCO₂/kg); IFC Building Material, Name: IFC Building Material; IFC Building Material, Participates in Collision Detection: yes
2535733 | 5e verdieping V | <Unnamed> | 2.3 | 1000 | 2300 | 1.92 (MJ/kg) | 0.198 (kgCO₂/kg) | <Unnamed> | yes
2538396 | 5e verdieping V | <Unnamed> | 2.3 | 1000 | 2300 | 1.92 (MJ/kg) | 0.198 (kgCO₂/kg) | <Unnamed> | yes
3081063 | 5e verdieping V | <Unnamed> | 2.3 | 1000 | 2300 | 1.92 (MJ/kg) | 0.198 (kgCO₂/kg) | <Unnamed> | yes | Group: Model Group:V vluchttrappenhuis V5:3080963
2536020 | 5e verdieping V | IFC Building Material | Material Properties - IFC Building Material, ThermalConductivity: 2.3; IFC Building Material, SpecificHeatCapacity: 1000 J/kg/K; IFC Building Material, MassDensity: 2300 kg/m3; IFC Building Material, Embodied Energy: 1.92 (MJ/kg); IFC Building Material, Embodied Carbon: 0.198 (kgCO₂/kg); IFC Building Material, Name: IFC Building Material; IFC Building Material, Participates in Collision Detection: yes
2541196 | 5e verdieping V | IFC Building Material | Material Properties - IFC Building Material, ThermalConductivity: 2.3; IFC Building Material, SpecificHeatCapacity: 1000 J/kg/K; IFC Building Material, MassDensity: 2300 kg/m3; IFC Building Material, Embodied Energy: 1.92 (MJ/kg); IFC Building Material, Embodied Carbon: 0.198 (kgCO₂/kg); IFC Building Material, Name: IFC Building Material; IFC Building Material, Participates in Collision Detection: yes
2479720 | 5e verdieping V | <Unnamed> | 2.3 | 1000 | 2300 | 1.92 (MJ/kg) | 0.198 (kgCO₂/kg) | <Unnamed> | yes
3081069 | 5e verdieping V | <Unnamed> | 2.3 | 1000 | 2300 | 1.92 (MJ/kg) | 0.198 (kgCO₂/kg) | <Unnamed> | yes | Group: Model Group:V vluchttrappenhuis V5:3080963

# IfcFlowController: Urinoir 27 (9)
CPset_Phasing - Renovation Phase: Nieuw
Name | In
3 x _Sanitair-x | Begane grond N
3 x _Sanitair-x | 1e verdieping N
3 x _Sanitair-x | 2e verdieping N

# IfcFlowController: Wasbak 27 (20)
Name | In | Renovation Phase
7 x _Sanitair-x | Begane grond N | Nieuw
3 x _Sanitair-x | Begane grond N | Bestaand
5 x _Sanitair-x | 1e verdieping N | Nieuw
5 x _Sanitair-x | 2e verdieping N | Nieuw

# IfcFurnishingElement: 82_FU_bed - multi:Eenpersoons, 82_FU_bed - multi:Eenpersoons:2572434
In: 5e verdieping V
Material: IFC Building Material
Pset_QuantityTakeOff - Reference: Eenpersoons
CPset_Phasing - Renovation Phase: Nieuw
Material Properties - IFC Building Material, ThermalConductivity: 2.3; IFC Building Material, SpecificHeatCapacity: 1000 J/kg/K; IFC Building Material, MassDensity: 2300 kg/m3; IFC Building Material, Embodied Energy: 1.92 (MJ/kg); IFC Building Material, Embodied Carbon: 0.198 (kgCO₂/kg); IFC Building Material, Name: IFC Building Material; IFC Building Material, Participates in Collision Detection: yes

# IfcFurnishingElement: 82_FU_kast_enkel:dichte legkast 600 (4)
In: 5e verdieping V
Type - Pset_FurnitureTypeCommon - Description: dubbele dichte legkast
Material: IFC Building Material
Pset_QuantityTakeOff - Reference: dichte legkast 600
CPset_Phasing - Renovation Phase: Nieuw
Material Properties - IFC Building Material, ThermalConductivity: 2.3; IFC Building Material, SpecificHeatCapacity: 1000 J/kg/K; IFC Building Material, MassDensity: 2300 kg/m3; IFC Building Material, Embodied Energy: 1.92 (MJ/kg); IFC Building Material, Embodied Carbon: 0.198 (kgCO₂/kg); IFC Building Material, Name: IFC Building Material; IFC Building Material, Participates in Collision Detection: yes
Name (82_FU_kast_enkel:dichte legkast 600:...)
2559920
2559738
2559981
2559982

# IfcFurnishingElement: NLRS_60_CASE_meterkast_generiek_WID:meterkast_gen_lxbxh 814x350x2600 (9)
Type - Pset_FurnitureTypeCommon - Description: meterkast
Material: houtfineer
Pset_QuantityTakeOff - Reference: meterkast_gen_lxbxh 814x350x2600
CPset_Phasing - Renovation Phase: Nieuw
Material Properties - houtfineer, ThermalConductivity: 2.3; houtfineer, SpecificHeatCapacity: 1000 J/kg/K; houtfineer, MassDensity: 2300 kg/m3; houtfineer, Embodied Energy: 1.92 (MJ/kg); houtfineer, Embodied Carbon: 0.198 (kgCO₂/kg); houtfineer, Name: houtfineer; houtfineer, Participates in Collision Detection: yes
Name (NLRS_60_CASE_meterkast_generiek_WID:meterkast_gen_lxbxh 814x350x2600:...) | In | Group
2425399 | 2e verdieping V | Model Group:V vluchttrappenhuis 2:2013401
2590896 | 2e verdieping V | Model Group:V vluchttrappenhuis 2:2013401
2590898 | 3e verdieping/dak N | Model Group:V vluchttrappenhuis 2:2013471
2425404 | 3e verdieping/dak N | Model Group:V vluchttrappenhuis 2:2013471
2590821 | 3e verdieping V | Model Group:V vluchttrappenhuis 2:2013517
2425409 | 3e verdieping V | Model Group:V vluchttrappenhuis 2:2013517
3085529 | 4e verdieping V | Model Group:V vluchttrappenhuis 2:2013112
3085533 | 4e verdieping V | Model Group:V vluchttrappenhuis 2:2013112
3081086 | 5e verdieping V | Model Group:V vluchttrappenhuis V5:3080963

# IfcFurnishingElement: NLRS_60_CASE_werkkast_algemeen_WID:meterkast_algemeen_lxbxh 840x350x2600 (5)
Type - Pset_FurnitureTypeCommon - Description: meterkast
Material: houtfineer
Pset_QuantityTakeOff - Reference: meterkast_algemeen_lxbxh 840x350x2600
Material Properties - houtfineer, ThermalConductivity: 2.3; houtfineer, SpecificHeatCapacity: 1000 J/kg/K; houtfineer, MassDensity: 2300 kg/m3; houtfineer, Embodied Energy: 1.92 (MJ/kg); houtfineer, Embodied Carbon: 0.198 (kgCO₂/kg); houtfineer, Name: houtfineer; houtfineer, Participates in Collision Detection: yes
CPset_Phasing - Renovation Phase: Nieuw
Name (NLRS_60_CASE_werkkast_algemeen_WID:meterkast_algemeen_lxbxh 840x350x2600:...) | In | Group
2423153 | 1e verdieping N
2013379 | 2e verdieping V | Model Group:V vluchttrappenhuis 2:2013401
2013449 | 3e verdieping/dak N | Model Group:V vluchttrappenhuis 2:2013471
2013646 | 3e verdieping V | Model Group:V vluchttrappenhuis 2:2013517
3085512 | 4e verdieping V | Model Group:V vluchttrappenhuis 2:2013112

# IfcFurnishingElement: NLRS_60_CASE_werkkast_algemeen_WID:meterkast_gen_lxbxh 814x350x2600 (2)
In: 1e verdieping N
Type - Pset_FurnitureTypeCommon - Description: meterkast
Material: houtfineer
Pset_QuantityTakeOff - Reference: meterkast_gen_lxbxh 814x350x2600
Material Properties - houtfineer, ThermalConductivity: 2.3; houtfineer, SpecificHeatCapacity: 1000 J/kg/K; houtfineer, MassDensity: 2300 kg/m3; houtfineer, Embodied Energy: 1.92 (MJ/kg); houtfineer, Embodied Carbon: 0.198 (kgCO₂/kg); houtfineer, Name: houtfineer; houtfineer, Participates in Collision Detection: yes
CPset_Phasing - Renovation Phase: Nieuw
Name (NLRS_60_CASE_werkkast_algemeen_WID:meterkast_gen_lxbxh 814x350x2600:...)
2040062
2040061

# IfcGroup: Model Group:V-koz-M nieuw 2 (12)
Name (Model Group:V-koz-M nieuw 2:...) | Group
2013388 | Model Group:V vluchttrappenhuis 2:2013401
2013400 | Model Group:V vluchttrappenhuis 2:2013401
2013470 | Model Group:V vluchttrappenhuis 2:2013471
2013458 | Model Group:V vluchttrappenhuis 2:2013471
2013655 | Model Group:V vluchttrappenhuis 2:2013517
2013667 | Model Group:V vluchttrappenhuis 2:2013517
2039379
2039391
3085520 | Model Group:V vluchttrappenhuis 2:2013112
3085515 | Model Group:V vluchttrappenhuis 2:2013112
2039133
2039145

# IfcMember: IfcMember (16)
Material: Metaal - Staal C
Pset_MemberCommon - FireRating: n.v.t.
Material Properties - Metaal - Staal C, ThermalConductivity: 52; Metaal - Staal C, SpecificHeatCapacity: 530 J/kg/K; Metaal - Staal C, MassDensity: 7950 kg/m3; Metaal - Staal C, Embodied Energy: 25 (MJ/kg); Metaal - Staal C, Embodied Carbon: 1.91 (kgCO₂/kg); Metaal - Staal C, Name: Metaal - Staal C; Metaal - Staal C, Participates in Collision Detection: yes
Name | In | Renovation Phase
4 x _Trapconstructie-x | Begane grond N | Bestaand
2 x _Trapconstructie-x | Begane grond N | Nieuw
4 x _Trapconstructie-x | 1e verdieping N | Bestaand
6 x _Trapconstructie-x | 1e verdieping N | Nieuw

# IfcMember: IfcMember (65)
Type - ElementType: Rail; PredefinedType: USERDEFINED
Name | In | Material | Metaal - Staal C, ThermalConductivity | Metaal - Staal C, SpecificHeatCapacity (J/kg/K) | Metaal - Staal C, MassDensity (kg/m3) | Metaal - Staal C, Embodied Energy | Metaal - Staal C, Embodied Carbon | Metaal - Staal C, Name | Metaal - Staal C, Participates in Collision Detection | Renovation Phase
15 x _Bovenregel-x | Begane grond N | Metaal - Staal C | 52 | 530 | 7950 | 25 (MJ/kg) | 1.91 (kgCO₂/kg) | Metaal - Staal C | yes | Bestaand
15 x _Regel-x | Begane grond N | Metaal - Staal C | 52 | 530 | 7950 | 25 (MJ/kg) | 1.91 (kgCO₂/kg) | Metaal - Staal C | yes | Bestaand
4 x _Bovenregel-x | Begane grond N | Metaal - RVS |  |  |  |  |  |  |  | Nieuw | Material Properties - Metaal - RVS, ThermalConductivity: 17; Metaal - RVS, SpecificHeatCapacity: 460 J/kg/K; Metaal - RVS, MassDensity: 7900 kg/m3; Metaal - RVS, Embodied Energy: 56.7 (MJ/kg); Metaal - RVS, Embodied Carbon: 6.15 (kgCO₂/kg); Metaal - RVS, Name: Metaal - RVS; Metaal - RVS, Participates in Collision Detection: yes
8 x _Bovenregel-x | Begane grond N | Metaal - Staal C | 52 | 530 | 7950 | 25 (MJ/kg) | 1.91 (kgCO₂/kg) | Metaal - Staal C | yes | Nieuw
8 x _Regel-x | Begane grond N | Metaal - Staal C | 52 | 530 | 7950 | 25 (MJ/kg) | 1.91 (kgCO₂/kg) | Metaal - Staal C | yes | Nieuw
3 x _Bovenregel-x | 1e verdieping N | Metaal - Staal C | 52 | 530 | 7950 | 25 (MJ/kg) | 1.91 (kgCO₂/kg) | Metaal - Staal C | yes | Bestaand
3 x _Regel-x | 1e verdieping N | Metaal - Staal C | 52 | 530 | 7950 | 25 (MJ/kg) | 1.91 (kgCO₂/kg) | Metaal - Staal C | yes | Bestaand
9 x _Regel-x | 1e verdieping N | Metaal - Aluminium |  |  |  |  |  |  |  | Nieuw | Material Properties - Metaal - Aluminium, ThermalConductivity: 160; Metaal - Aluminium, SpecificHeatCapacity: 880 J/kg/K; Metaal - Aluminium, MassDensity: 2800 kg/m3; Metaal - Aluminium, Embodied Energy: 155 (MJ/kg); Metaal - Aluminium, Embodied Carbon: 9.16 (kgCO₂/kg); Metaal - Aluminium, Name: Metaal - Aluminium; Metaal - Aluminium, Participates in Collision Detection: yes

# IfcMember: IfcMember (91)
Type - ElementType: Stair Riser; PredefinedType: USERDEFINED
Material: Hout - Vloer
Pset_MemberCommon - FireRating: n.v.t.
Material Properties - Hout - Vloer, ThermalConductivity: 0.14; Hout - Vloer, SpecificHeatCapacity: 1880 J/kg/K; Hout - Vloer, MassDensity: 550 kg/m3; Hout - Vloer, Embodied Energy: 7.4 (MJ/kg); Hout - Vloer, Embodied Carbon: 0.19 (kgCO₂/kg); Hout - Vloer, Name: Hout - Vloer; Hout - Vloer, Participates in Collision Detection: yes
Name | In | Renovation Phase
40 x _Stootbord-x | Begane grond N | Bestaand
5 x _Stootbord-x | Begane grond N | Nieuw
20 x _Stootbord-x | 1e verdieping N | Bestaand
6 x _Stootbord-x | 2e verdieping N | Bestaand
20 x _Stootbord-x | 2e verdieping V | Bestaand

# IfcMember: IfcMember (175)
Type - ElementType: Stair Tread; PredefinedType: USERDEFINED
Pset_MemberCommon - FireRating: n.v.t.
Name | In | Material | Renovation Phase | Hout - Vloer, ThermalConductivity | Hout - Vloer, SpecificHeatCapacity (J/kg/K) | Hout - Vloer, MassDensity (kg/m3) | Hout - Vloer, Embodied Energy | Hout - Vloer, Embodied Carbon | Hout - Vloer, Name | Hout - Vloer, Participates in Collision Detection
25 x _Traptrede-x | Begane grond N | Metaal - Staal C | Bestaand | Material Properties - Metaal - Staal C, ThermalConductivity: 52; Metaal - Staal C, SpecificHeatCapacity: 530 J/kg/K; Metaal - Staal C, MassDensity: 7950 kg/m3; Metaal - Staal C, Embodied Energy: 25 (MJ/kg); Metaal - Staal C, Embodied Carbon: 1.91 (kgCO₂/kg); Metaal - Staal C, Name: Metaal - Staal C; Metaal - Staal C, Participates in Collision Detection: yes
40 x _Traptrede-x | Begane grond N | Hout - Vloer | Bestaand | 0.14 | 1880 | 550 | 7.4 (MJ/kg) | 0.19 (kgCO₂/kg) | Hout - Vloer | yes
4 x _Traptrede-x | Begane grond N | Hout - Vloer | Nieuw | 0.14 | 1880 | 550 | 7.4 (MJ/kg) | 0.19 (kgCO₂/kg) | Hout - Vloer | yes
19 x _Traptrede-x | Begane grond N | Metaal - Staal C | Nieuw | Material Properties - Metaal - Staal C, ThermalConductivity: 52; Metaal - Staal C, SpecificHeatCapacity: 530 J/kg/K; Metaal - Staal C, MassDensity: 7950 kg/m3; Metaal - Staal C, Embodied Energy: 25 (MJ/kg); Metaal - Staal C, Embodied Carbon: 1.91 (kgCO₂/kg); Metaal - Staal C, Name: Metaal - Staal C; Metaal - Staal C, Participates in Collision Detection: yes
20 x _Traptrede-x | 1e verdieping N | Hout - Vloer | Bestaand | 0.14 | 1880 | 550 | 7.4 (MJ/kg) | 0.19 (kgCO₂/kg) | Hout - Vloer | yes
22 x _Traptrede-x | 1e verdieping N | Metaal - Staal C | Bestaand | Material Properties - Metaal - Staal C, ThermalConductivity: 52; Metaal - Staal C, SpecificHeatCapacity: 530 J/kg/K; Metaal - Staal C, MassDensity: 7950 kg/m3; Metaal - Staal C, Embodied Energy: 25 (MJ/kg); Metaal - Staal C, Embodied Carbon: 1.91 (kgCO₂/kg); Metaal - Staal C, Name: Metaal - Staal C; Metaal - Staal C, Participates in Collision Detection: yes
17 x _Traptrede-x | 1e verdieping N | Metaal - Staal C | Nieuw | Material Properties - Metaal - Staal C, ThermalConductivity: 52; Metaal - Staal C, SpecificHeatCapacity: 530 J/kg/K; Metaal - Staal C, MassDensity: 7950 kg/m3; Metaal - Staal C, Embodied Energy: 25 (MJ/kg); Metaal - Staal C, Embodied Carbon: 1.91 (kgCO₂/kg); Metaal - Staal C, Name: Metaal - Staal C; Metaal - Staal C, Participates in Collision Detection: yes
2 x _Bordes afwerking-x | 1e verdieping N | Metaal - Staal C | Nieuw | Material Properties - Metaal - Staal C, ThermalConductivity: 52; Metaal - Staal C, SpecificHeatCapacity: 530 J/kg/K; Metaal - Staal C, MassDensity: 7950 kg/m3; Metaal - Staal C, Embodied Energy: 25 (MJ/kg); Metaal - Staal C, Embodied Carbon: 1.91 (kgCO₂/kg); Metaal - Staal C, Name: Metaal - Staal C; Metaal - Staal C, Participates in Collision Detection: yes
6 x _Traptrede-x | 2e verdieping N | Hout - Vloer | Bestaand | 0.14 | 1880 | 550 | 7.4 (MJ/kg) | 0.19 (kgCO₂/kg) | Hout - Vloer | yes
20 x _Traptrede-x | 2e verdieping V | Hout - Vloer | Bestaand | 0.14 | 1880 | 550 | 7.4 (MJ/kg) | 0.19 (kgCO₂/kg) | Hout - Vloer | yes

# IfcMember: IfcMember (508)
Type - PredefinedType: MEMBER
Material: Metaal - Staal C
Pset_MemberCommon - FireRating: n.v.t.
Material Properties - Metaal - Staal C, ThermalConductivity: 52; Metaal - Staal C, SpecificHeatCapacity: 530 J/kg/K; Metaal - Staal C, MassDensity: 7950 kg/m3; Metaal - Staal C, Embodied Energy: 25 (MJ/kg); Metaal - Staal C, Embodied Carbon: 1.91 (kgCO₂/kg); Metaal - Staal C, Name: Metaal - Staal C; Metaal - Staal C, Participates in Collision Detection: yes
Name | In | Renovation Phase
285 x _Spijlen-x | Begane grond N | Bestaand
174 x _Spijlen-x | Begane grond N | Nieuw
49 x _Spijlen-x | 1e verdieping N | Bestaand

# IfcMember: IfcMember (9)
In: 1e verdieping N
Type - PredefinedType: PLATE
Material: Glas
CPset_Phasing - Renovation Phase: Nieuw
Material Properties - Glas, ThermalConductivity: 1.2; Glas, SpecificHeatCapacity: 795 J/kg/K; Glas, MassDensity: 2180 kg/m3; Glas, Embodied Energy: 15 (MJ/kg); Glas, Embodied Carbon: 0.86 (kgCO₂/kg); Glas, Name: Glas; Glas, Participates in Collision Detection: yes

# IfcMember: IfcMember (85)
Type - PredefinedType: POST
Name | In | Material | Renovation Phase | Metaal - Staal C, ThermalConductivity | Metaal - Staal C, SpecificHeatCapacity (J/kg/K) | Metaal - Staal C, MassDensity (kg/m3) | Metaal - Staal C, Embodied Energy | Metaal - Staal C, Embodied Carbon | Metaal - Staal C, Name | Metaal - Staal C, Participates in Collision Detection
20 x _Hoofdbaluster-x | Begane grond N | Metaal - Staal C | Bestaand | 52 | 530 | 7950 | 25 (MJ/kg) | 1.91 (kgCO₂/kg) | Metaal - Staal C | yes
24 x _Baluster-x | Begane grond N | Metaal - Staal C | Bestaand | 52 | 530 | 7950 | 25 (MJ/kg) | 1.91 (kgCO₂/kg) | Metaal - Staal C | yes
6 x _Hoofdbaluster-x | Begane grond N | Metaal - RVS | Nieuw | Material Properties - Metaal - RVS, ThermalConductivity: 17; Metaal - RVS, SpecificHeatCapacity: 460 J/kg/K; Metaal - RVS, MassDensity: 7900 kg/m3; Metaal - RVS, Embodied Energy: 56.7 (MJ/kg); Metaal - RVS, Embodied Carbon: 6.15 (kgCO₂/kg); Metaal - RVS, Name: Metaal - RVS; Metaal - RVS, Participates in Collision Detection: yes
10 x _Hoofdbaluster-x | Begane grond N | Metaal - Staal C | Nieuw | 52 | 530 | 7950 | 25 (MJ/kg) | 1.91 (kgCO₂/kg) | Metaal - Staal C | yes
15 x _Baluster-x | Begane grond N | Metaal - Staal C | Nieuw | 52 | 530 | 7950 | 25 (MJ/kg) | 1.91 (kgCO₂/kg) | Metaal - Staal C | yes
6 x _Hoofdbaluster-x | 1e verdieping N | Metaal - Staal C | Bestaand | 52 | 530 | 7950 | 25 (MJ/kg) | 1.91 (kgCO₂/kg) | Metaal - Staal C | yes
4 x _Baluster-x | 1e verdieping N | Metaal - Staal C | Bestaand | 52 | 530 | 7950 | 25 (MJ/kg) | 1.91 (kgCO₂/kg) | Metaal - Staal C | yes

# IfcMember: Rectangular Mullion:31_alu_070x0100 RAL 7024 (8)
In: 7e verdieping-dak V
Type - PredefinedType: MULLION
Material: RAL 7024 - Grafietgrijs
Pset_QuantityTakeOff - Reference: 31_alu_070x0100 RAL 7024
CPset_Phasing - Renovation Phase: Nieuw
Pset_MemberCommon - Reference: 31_alu_070x0100 RAL 7024; IsExternal: yes; LoadBearing: no
Material Properties - RAL 7024 - Grafietgrijs, ThermalConductivity: 2.3; RAL 7024 - Grafietgrijs, SpecificHeatCapacity: 1000 J/kg/K; RAL 7024 - Grafietgrijs, MassDensity: 2300 kg/m3; RAL 7024 - Grafietgrijs, Embodied Energy: 1.92 (MJ/kg); RAL 7024 - Grafietgrijs, Embodied Carbon: 0.198 (kgCO₂/kg); RAL 7024 - Grafietgrijs, Name: RAL 7024 - Grafietgrijs; RAL 7024 - Grafietgrijs, Participates in Collision Detection: yes
Name (Rectangular Mullion:31_alu_070x0100 RAL 7024:...) | Span (mm)
2769843 | 1070
2769842 | 540
2769635 | 344.031
2769462 | 540
2769634 | 1000
2769460 | 1000
2769459 | 344.031
2769461 | 1070

# IfcMember: Rectangular Mullion:31_alu_070x065 RAL 7024 (258)
Type - PredefinedType: MULLION
Material: RAL 7024 - Grafietgrijs
Pset_QuantityTakeOff - Reference: 31_alu_070x065 RAL 7024
Pset_MemberCommon - Reference: 31_alu_070x065 RAL 7024; IsExternal: yes; LoadBearing: no
Material Properties - RAL 7024 - Grafietgrijs, ThermalConductivity: 2.3; RAL 7024 - Grafietgrijs, SpecificHeatCapacity: 1000 J/kg/K; RAL 7024 - Grafietgrijs, MassDensity: 2300 kg/m3; RAL 7024 - Grafietgrijs, Embodied Energy: 1.92 (MJ/kg); RAL 7024 - Grafietgrijs, Embodied Carbon: 0.198 (kgCO₂/kg); RAL 7024 - Grafietgrijs, Name: RAL 7024 - Grafietgrijs; RAL 7024 - Grafietgrijs, Participates in Collision Detection: yes
CPset_Phasing - Renovation Phase: Nieuw
Name (Rectangular Mullion:31_alu_070x065 RAL 7024:...) | In | Span (mm)
2039357 | 1e verdieping N | 1080 | Group: Model Group:V-koz-M nieuw 2:2039379
2039358 | 1e verdieping N | 2470 | Group: Model Group:V-koz-M nieuw 2:2039379
2725171 | 1e verdieping N | 1080 | Group: Model Group:V-koz-M nieuw 2:2039379
2724992 | 1e verdieping N | 2470 | Group: Model Group:V-koz-M nieuw 2:2039391
2725174 | 1e verdieping N | 1080 | Group: Model Group:V-koz-M nieuw 2:2039391
2039383 | 1e verdieping N | 1080 | Group: Model Group:V-koz-M nieuw 2:2039391
2724989 | 1e verdieping N | 2470 | Group: Model Group:V-koz-M nieuw 2:2039379
2039384 | 1e verdieping N | 2470 | Group: Model Group:V-koz-M nieuw 2:2039391
3140553 | 1e verdieping N | 1154 | Group: Model Group:KOZ-03:3140556
3140552 | 1e verdieping N | 1154 | Group: Model Group:KOZ-03:3140556
3140555 | 1e verdieping N | 2470 | Group: Model Group:KOZ-03:3140556
3142365 | 1e verdieping N | 2470 | Group: Model Group:KOZ-03:3142360
3142364 | 1e verdieping N | 1154 | Group: Model Group:KOZ-03:3142360
3140554 | 1e verdieping N | 2470 | Group: Model Group:KOZ-03:3140556
3142363 | 1e verdieping N | 1154 | Group: Model Group:KOZ-03:3142360
3142366 | 1e verdieping N | 2470 | Group: Model Group:KOZ-03:3142360
2726619 | 1e verdieping N | 1150.53
2726620 | 1e verdieping N | 1150.53
2726621 | 1e verdieping N | 2470
2726622 | 1e verdieping N | 2470
2730065 | 1e verdieping N | 1586.5
2730066 | 1e verdieping N | 1714.5
2730067 | 1e verdieping N | 2330
2728849 | 1e verdieping N | 1644.5
2728850 | 1e verdieping N | 1516.5
2728852 | 1e verdieping N | 2400
2728851 | 1e verdieping N | 2400
3088435 | 1e verdieping N | 2570
3088432 | 1e verdieping N | 1154
3088434 | 1e verdieping N | 2570
3088433 | 1e verdieping N | 1154
2815519 | 1e verdieping N | 1167.2
2815516 | 1e verdieping N | 244.8
2815517 | 1e verdieping N | 1714.7
2815522 | 1e verdieping N | 1784.7
2815523 | 1e verdieping N | 1100
2949171 | 1e verdieping N | 1167.2
2815524 | 1e verdieping N | 753.3
2949166 | 1e verdieping N | 409.5
2949169 | 1e verdieping N | 209.8
2949165 | 1e verdieping N | 1237.2
2949354 | 1e verdieping N | 409.5
2949353 | 1e verdieping N | 409.5
2949352 | 1e verdieping N | 209.8
2949349 | 1e verdieping N | 823.3
2946782 | 1e verdieping N | 753.3
2949348 | 1e verdieping N | 409.5
2946780 | 1e verdieping N | 1100
2946781 | 1e verdieping N | 314.8
2949170 | 1e verdieping N | 1167.2
2947051 | 1e verdieping N | 2470
2947050 | 1e verdieping N | 2470
2947049 | 1e verdieping N | 1015
2947048 | 1e verdieping N | 1015
2815518 | 1e verdieping N | 753.3
2724986 | 2e verdieping N | 2470 | Group: Model Group:V-koz-M nieuw 2:2039145
2039137 | 2e verdieping N | 1080 | Group: Model Group:V-koz-M nieuw 2:2039145
2725165 | 2e verdieping N | 1080 | Group: Model Group:V-koz-M nieuw 2:2039133
2724983 | 2e verdieping N | 2470 | Group: Model Group:V-koz-M nieuw 2:2039133
2039111 | 2e verdieping N | 1080 | Group: Model Group:V-koz-M nieuw 2:2039133
2039112 | 2e verdieping N | 2470 | Group: Model Group:V-koz-M nieuw 2:2039133
2039138 | 2e verdieping N | 2470 | Group: Model Group:V-koz-M nieuw 2:2039145
2725168 | 2e verdieping N | 1080 | Group: Model Group:V-koz-M nieuw 2:2039145
3140560 | 2e verdieping N | 1154 | Group: Model Group:KOZ-03:3140557
3140561 | 2e verdieping N | 1154 | Group: Model Group:KOZ-03:3140557
3140562 | 2e verdieping N | 2470 | Group: Model Group:KOZ-03:3140557
3140563 | 2e verdieping N | 2470 | Group: Model Group:KOZ-03:3140557
3088418 | 2e verdieping N | 1154 | Group: Model Group:KOZ-03:3087227
3088419 | 2e verdieping N | 1154 | Group: Model Group:KOZ-03:3087227
3088420 | 2e verdieping N | 2470 | Group: Model Group:KOZ-03:3087227
3088421 | 2e verdieping N | 2470 | Group: Model Group:KOZ-03:3087227
2013366 | 2e verdieping V | 1080 | Group: Model Group:V-koz-M nieuw 2:2013388
2724965 | 2e verdieping V | 2470 | Group: Model Group:V-koz-M nieuw 2:2013388
2765757 | 2e verdieping V | 1154 | Group: Model Group:KOZ-03:2767540
2765756 | 2e verdieping V | 1154 | Group: Model Group:KOZ-03:2767540
2765758 | 2e verdieping V | 2470 | Group: Model Group:KOZ-03:2767540
2765759 | 2e verdieping V | 2470 | Group: Model Group:KOZ-03:2767540
2013392 | 2e verdieping V | 1080 | Group: Model Group:V-koz-M nieuw 2:2013400
2013393 | 2e verdieping V | 2470 | Group: Model Group:V-koz-M nieuw 2:2013400
2725150 | 2e verdieping V | 1080 | Group: Model Group:V-koz-M nieuw 2:2013400
2724968 | 2e verdieping V | 2470 | Group: Model Group:V-koz-M nieuw 2:2013400
3140524 | 2e verdieping V | 1154 | Group: Model Group:KOZ-03:3140528
2725147 | 2e verdieping V | 1080 | Group: Model Group:V-koz-M nieuw 2:2013388
3140525 | 2e verdieping V | 1154 | Group: Model Group:KOZ-03:3140528
3140526 | 2e verdieping V | 2470 | Group: Model Group:KOZ-03:3140528
2013367 | 2e verdieping V | 2470 | Group: Model Group:V-koz-M nieuw 2:2013388
3140527 | 2e verdieping V | 2470 | Group: Model Group:KOZ-03:3140528
2013437 | 3e verdieping/dak N | 2470 | Group: Model Group:V-koz-M nieuw 2:2013458
2724971 | 3e verdieping/dak N | 2470 | Group: Model Group:V-koz-M nieuw 2:2013458
2725153 | 3e verdieping/dak N | 1080 | Group: Model Group:V-koz-M nieuw 2:2013458
2013462 | 3e verdieping/dak N | 1080 | Group: Model Group:V-koz-M nieuw 2:2013470
2724974 | 3e verdieping/dak N | 2470 | Group: Model Group:V-koz-M nieuw 2:2013470
2013463 | 3e verdieping/dak N | 2470 | Group: Model Group:V-koz-M nieuw 2:2013470
2767564 | 3e verdieping/dak N | 2470 | Group: Model Group:KOZ-03:2767569
2767565 | 3e verdieping/dak N | 2470 | Group: Model Group:KOZ-03:2767569
2725156 | 3e verdieping/dak N | 1080 | Group: Model Group:V-koz-M nieuw 2:2013470
3140531 | 3e verdieping/dak N | 1154 | Group: Model Group:KOZ-03:3140535
2767563 | 3e verdieping/dak N | 1154 | Group: Model Group:KOZ-03:2767569
2013436 | 3e verdieping/dak N | 1080 | Group: Model Group:V-koz-M nieuw 2:2013458
2767562 | 3e verdieping/dak N | 1154 | Group: Model Group:KOZ-03:2767569
3140534 | 3e verdieping/dak N | 2470 | Group: Model Group:KOZ-03:3140535
3140532 | 3e verdieping/dak N | 1154 | Group: Model Group:KOZ-03:3140535
2013633 | 3e verdieping V | 1080 | Group: Model Group:V-koz-M nieuw 2:2013655
2725159 | 3e verdieping V | 1080 | Group: Model Group:V-koz-M nieuw 2:2013655
2724977 | 3e verdieping V | 2470 | Group: Model Group:V-koz-M nieuw 2:2013655
2013660 | 3e verdieping V | 2470 | Group: Model Group:V-koz-M nieuw 2:2013667
2013659 | 3e verdieping V | 1080 | Group: Model Group:V-koz-M nieuw 2:2013667
2724980 | 3e verdieping V | 2470 | Group: Model Group:V-koz-M nieuw 2:2013667
2725162 | 3e verdieping V | 1080 | Group: Model Group:V-koz-M nieuw 2:2013667
2767582 | 3e verdieping V | 2470 | Group: Model Group:KOZ-03:2767587
2767580 | 3e verdieping V | 1154 | Group: Model Group:KOZ-03:2767587
2767583 | 3e verdieping V | 2470 | Group: Model Group:KOZ-03:2767587
2767581 | 3e verdieping V | 1154 | Group: Model Group:KOZ-03:2767587
3140540 | 3e verdieping V | 2470 | Group: Model Group:KOZ-03:3140542
3140539 | 3e verdieping V | 1154 | Group: Model Group:KOZ-03:3140542
2013634 | 3e verdieping V | 2470 | Group: Model Group:V-koz-M nieuw 2:2013655
3140538 | 3e verdieping V | 1154 | Group: Model Group:KOZ-03:3140542
3140541 | 3e verdieping V | 2470 | Group: Model Group:KOZ-03:3140542
3085501 | 4e verdieping V | 2470 | Group: Model Group:V-koz-M nieuw 2:3085515
3085539 | 4e verdieping V | 1080 | Group: Model Group:V-koz-M nieuw 2:3085515
3085500 | 4e verdieping V | 1080 | Group: Model Group:V-koz-M nieuw 2:3085515
3085537 | 4e verdieping V | 2470 | Group: Model Group:V-koz-M nieuw 2:3085515
3085519 | 4e verdieping V | 2470 | Group: Model Group:V-koz-M nieuw 2:3085520
3085518 | 4e verdieping V | 1080 | Group: Model Group:V-koz-M nieuw 2:3085520
3085540 | 4e verdieping V | 1080 | Group: Model Group:V-koz-M nieuw 2:3085520
3085538 | 4e verdieping V | 2470 | Group: Model Group:V-koz-M nieuw 2:3085520
2767614 | 4e verdieping V | 1154 | Group: Model Group:KOZ-03:2767621
2767615 | 4e verdieping V | 1154 | Group: Model Group:KOZ-03:2767621
3140548 | 4e verdieping V | 2470 | Group: Model Group:KOZ-03:3140549
2767617 | 4e verdieping V | 2470 | Group: Model Group:KOZ-03:2767621
2767616 | 4e verdieping V | 2470 | Group: Model Group:KOZ-03:2767621
3140545 | 4e verdieping V | 1154 | Group: Model Group:KOZ-03:3140549
3140547 | 4e verdieping V | 2470 | Group: Model Group:KOZ-03:3140549
3140546 | 4e verdieping V | 1154 | Group: Model Group:KOZ-03:3140549
2999304 | 5e verdieping V | 1920
2999305 | 5e verdieping V | 1920
2999302 | 5e verdieping V | 1240
2999303 | 5e verdieping V | 1240
2999318 | 5e verdieping V | 1240
2999317 | 5e verdieping V | 1240
2999319 | 5e verdieping V | 1920
2538976 | 5e verdieping V | 877
2538978 | 5e verdieping V | 2790
2538979 | 5e verdieping V | 2790
2539079 | 5e verdieping V | 2790
2539077 | 5e verdieping V | 877
2539150 | 5e verdieping V | 2790
2539149 | 5e verdieping V | 912
2542070 | 5e verdieping V | 890
2542071 | 5e verdieping V | 890
2542072 | 5e verdieping V | 2730
2542073 | 5e verdieping V | 2730
2540326 | 5e verdieping V | 1237.5
2540327 | 5e verdieping V | 1237.5
2539148 | 5e verdieping V | 900
2540328 | 5e verdieping V | 1920
2540329 | 5e verdieping V | 1920
2997359 | 5e verdieping V | 200
2997361 | 5e verdieping V | 1920
2997360 | 5e verdieping V | 1237.5
2553508 | 5e verdieping V | 1237.5
2553509 | 5e verdieping V | 200
2553510 | 5e verdieping V | 1920
3094156 | 5e verdieping V | 2060
3094154 | 5e verdieping V | 1092.5
2538977 | 5e verdieping V | 912
3094153 | 5e verdieping V | 1092.5
3094184 | 5e verdieping V | 2060
3094182 | 5e verdieping V | 1092.5
3140911 | 5e verdieping V | 1154 | Group: Model Group:V vluchttrappenhuis V5:3080963
3094155 | 5e verdieping V | 2060
3140913 | 5e verdieping V | 2930 | Group: Model Group:V vluchttrappenhuis V5:3080963
3140912 | 5e verdieping V | 1154 | Group: Model Group:V vluchttrappenhuis V5:3080963
3140914 | 5e verdieping V | 2930 | Group: Model Group:V vluchttrappenhuis V5:3080963
3140742 | 5e verdieping V | 1154 | Group: Model Group:V vluchttrappenhuis V5:3080963
3140743 | 5e verdieping V | 1154 | Group: Model Group:V vluchttrappenhuis V5:3080963
3140744 | 5e verdieping V | 2930 | Group: Model Group:V vluchttrappenhuis V5:3080963
3140745 | 5e verdieping V | 2930 | Group: Model Group:V vluchttrappenhuis V5:3080963
2759493 | 5e verdieping V | 1426.75
2759495 | 5e verdieping V | 2590
2759492 | 5e verdieping V | 2698
2759503 | 5e verdieping V | 1426.75
2759494 | 5e verdieping V | 2590
2759505 | 5e verdieping V | 2590
2759504 | 5e verdieping V | 2698
2557571 | 5e verdieping V | 1240 | Group: Model Group:V-koz-N nieuw:2557585
3094185 | 5e verdieping V | 2060
2557573 | 5e verdieping V | 1920 | Group: Model Group:V-koz-N nieuw:2557585
2557577 | 5e verdieping V | 1240 | Group: Model Group:V-koz-N nieuw:2557585
2557572 | 5e verdieping V | 1240 | Group: Model Group:V-koz-N nieuw:2557585
2557579 | 5e verdieping V | 1920 | Group: Model Group:V-koz-N nieuw:2557585
3089622 | 5e verdieping V | 2730
3089620 | 5e verdieping V | 1911.75
3089621 | 5e verdieping V | 1911.75
2557578 | 5e verdieping V | 1240 | Group: Model Group:V-koz-N nieuw:2557585
2561726 | 5e verdieping V | 390
3089623 | 5e verdieping V | 2730
2561736 | 5e verdieping V | 390
2561737 | 5e verdieping V | 2705
2561725 | 5e verdieping V | 355
2561731 | 5e verdieping V | 355
2561735 | 5e verdieping V | 900
2561728 | 5e verdieping V | 2705
2561732 | 5e verdieping V | 2705
3094183 | 5e verdieping V | 1092.5
3081078 | 5e verdieping V | 1080 | Group: Model Group:V vluchttrappenhuis V5:3080963
3081095 | 5e verdieping V | 1080 | Group: Model Group:V vluchttrappenhuis V5:3080963
3081079 | 5e verdieping V | 2930 | Group: Model Group:V vluchttrappenhuis V5:3080963
2557574 | 5e verdieping V | 1920 | Group: Model Group:V-koz-N nieuw:2557585
3081096 | 5e verdieping V | 1080 | Group: Model Group:V vluchttrappenhuis V5:3080963
3081060 | 5e verdieping V | 1080 | Group: Model Group:V vluchttrappenhuis V5:3080963
3084847 | 5e verdieping V | 2930 | Group: Model Group:V vluchttrappenhuis V5:3080963
2561727 | 5e verdieping V | 2705
3084844 | 5e verdieping V | 1153 | Group: Model Group:V vluchttrappenhuis V5:3080963
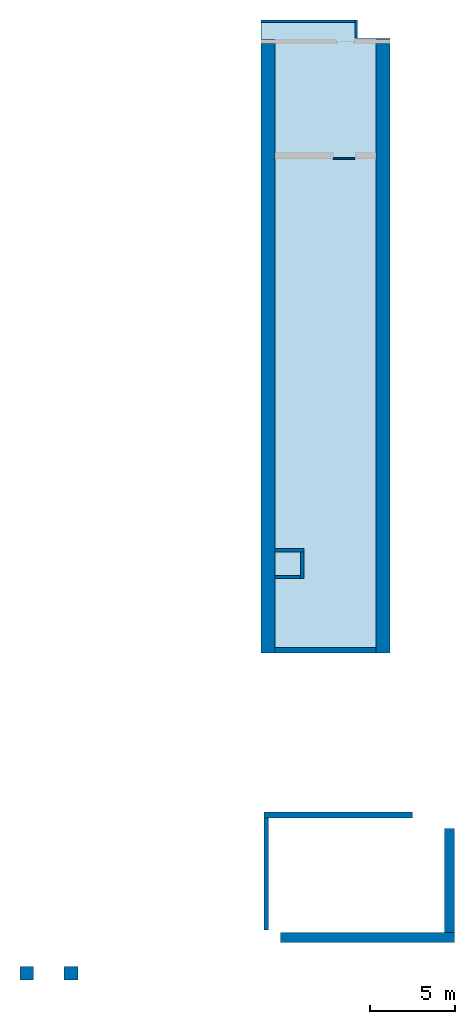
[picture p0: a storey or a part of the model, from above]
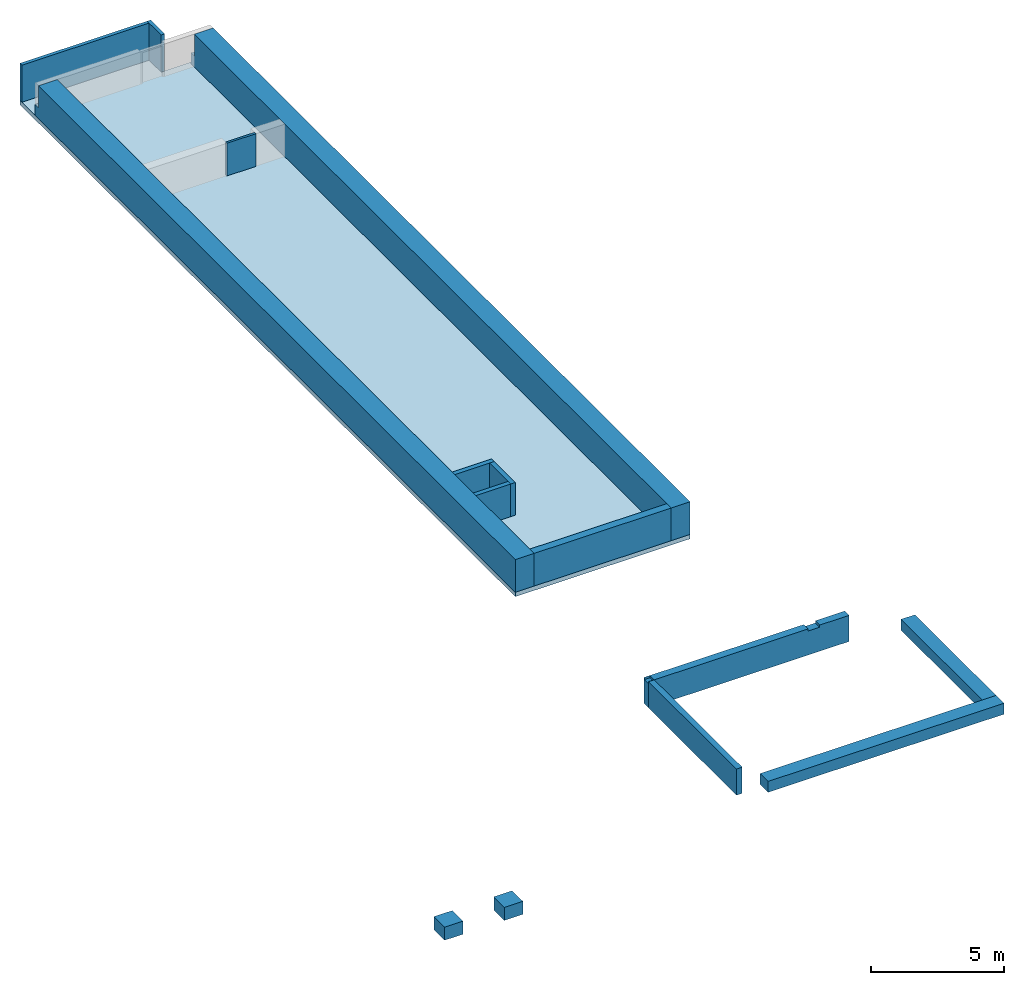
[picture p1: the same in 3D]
Properties of the parts of a building model (IFC2X3), part 5 of 7

# IfcMember: Rectangular Mullion:31_alu_070x065 RAL 7024 (258)
Name (Rectangular Mullion:31_alu_070x065 RAL 7024:...) | In | Span (mm)
3081093 | 5e verdieping V | 2930 | Group: Model Group:V vluchttrappenhuis V5:3080963
3084846 | 5e verdieping V | 2930 | Group: Model Group:V vluchttrappenhuis V5:3080963
3081094 | 5e verdieping V | 2930 | Group: Model Group:V vluchttrappenhuis V5:3080963
3081061 | 5e verdieping V | 2930 | Group: Model Group:V vluchttrappenhuis V5:3080963
2772141 | 5e verdieping V | 1265
2772140 | 5e verdieping V | 1240
2772143 | 5e verdieping V | 1920
2772142 | 5e verdieping V | 1920
2772153 | 5e verdieping V | 1920
3084845 | 5e verdieping V | 1153 | Group: Model Group:V vluchttrappenhuis V5:3080963
2772156 | 5e verdieping V | 1205
2772158 | 5e verdieping V | 1920
2772157 | 5e verdieping V | 195
2772147 | 5e verdieping V | 1240
2772146 | 5e verdieping V | 1205
2772148 | 5e verdieping V | 1920
2772151 | 5e verdieping V | 195
2772163 | 5e verdieping V | 1920
2772162 | 5e verdieping V | 1205
2772161 | 5e verdieping V | 1265
2772175 | 5e verdieping V | 1240
2772185 | 5e verdieping V | 195
2772187 | 5e verdieping V | 1920
2772186 | 5e verdieping V | 1205
2772174 | 5e verdieping V | 1240
2772191 | 5e verdieping V | 195
2772176 | 5e verdieping V | 1920
2772177 | 5e verdieping V | 1920
2772181 | 5e verdieping V | 1240
2772190 | 5e verdieping V | 1205
2772180 | 5e verdieping V | 1205
2772192 | 5e verdieping V | 1920
2772152 | 5e verdieping V | 1205
2772197 | 5e verdieping V | 1920
2772182 | 5e verdieping V | 1920
2553360 | 5e verdieping V | 1470
2772195 | 5e verdieping V | 1240
2553358 | 5e verdieping V | 3415
2550084 | 5e verdieping V | 1540
2553359 | 5e verdieping V | 835
2550085 | 5e verdieping V | 1540
2550087 | 5e verdieping V | 3345
2550086 | 5e verdieping V | 765
2772196 | 5e verdieping V | 1205

# IfcMember: Rectangular Mullion:31_alu_084x065 RAL 7024 (86)
In: 2e verdieping N
Type - PredefinedType: MULLION
Material: RAL 7024 - Grafietgrijs
Pset_MemberCommon - Reference: 31_alu_084x065 RAL 7024; IsExternal: yes; LoadBearing: no
Pset_QuantityTakeOff - Reference: 31_alu_084x065 RAL 7024
CPset_Phasing - Renovation Phase: Nieuw
Material Properties - RAL 7024 - Grafietgrijs, ThermalConductivity: 2.3; RAL 7024 - Grafietgrijs, SpecificHeatCapacity: 1000 J/kg/K; RAL 7024 - Grafietgrijs, MassDensity: 2300 kg/m3; RAL 7024 - Grafietgrijs, Embodied Energy: 1.92 (MJ/kg); RAL 7024 - Grafietgrijs, Embodied Carbon: 0.198 (kgCO₂/kg); RAL 7024 - Grafietgrijs, Name: RAL 7024 - Grafietgrijs; RAL 7024 - Grafietgrijs, Participates in Collision Detection: yes
Name (Rectangular Mullion:31_alu_084x065 RAL 7024:...) | Span (mm)
3024881 | 3232
3024880 | 1222.5
3024885 | 1222.5
3024884 | 1222.5
3024886 | 3232
3024889 | 1222.5
3024890 | 1222.5
3024873 | 1222.5
3024891 | 3232
3024875 | 3232
3024874 | 1222.5
3024879 | 1222.5
3024876 | 3232
3024083 | 1477
3024082 | 2030
3024084 | 3232
3024073 | 3232
3024071 | 1435
3024074 | 3232
3024072 | 1477
3024079 | 3232
3024077 | 1435
3024368 | 3194
3024355 | 1351
3024357 | 3236
3024356 | 1393
3024358 | 836
3024361 | 1435
3024367 | 1477
3024366 | 2030
3024363 | 3194
3109752 | 920
3139255 | 794
3139273 | 794
3109753 | 3320
3109755 | 2114
3024601 | 3232
3024599 | 1225
3024600 | 1225
3024337 | 3232
3024325 | 1225
3024324 | 1225
3024327 | 3232
3024326 | 3232
3024332 | 3232
3024331 | 1225
3024335 | 1225
3024330 | 1225
3026235 | 462
3026234 | 1435
3026237 | 3232
3026236 | 3232
3024336 | 1225
3027181 | 2030
3027182 | 1057
3027183 | 3232
3027127 | 420
3027129 | 3232
3027247 | 1015
3027249 | 3232
3168175 | 3400
3027248 | 1435
3168174 | 3400
3168173 | 2401
3108142 | 3400
3108140 | 2401
3108141 | 3400
2973609 | 1997.03
3168172 | 2401
2973608 | 1997.03
3108139 | 2401
2973610 | 3400
3021945 | 1477
3021946 | 3232
3021910 | 1435
2973611 | 3400
2974192 | 3232
3021912 | 3232
2974191 | 3232
2974189 | 1435
3021944 | 2030
3104777 | 2401
3104779 | 3400
3104778 | 2401
3104780 | 3400
2974190 | 1477

# IfcOpeningElement (664)
Name | In
2 x _Merk-x | Fundering N
_Merk-009 | Begane grond N
6 x _Merk-002 | Begane grond N
73 x _Merk-x | Begane grond N
_Merk-007 | Begane grond N
_Merk-004 | Begane grond N
6 x _ | Begane grond N
8 x _Merk-006 | Begane grond N
3 x _Merk-005 | Begane grond N
9 x _Merk-006sp | Begane grond N
_Merk-006A | Begane grond N
_Merk-010 | Begane grond N
_Merk- | Begane grond N
_Merk-F001 | Begane grond N
2 x _Merk-012 | Begane grond N
_Merk-011 | Begane grond N
4 x _Merk-001 | Begane grond N
2 x _Merk-003 | Begane grond N
3 x _Merk-016 | Begane grond N
_Merk-014sp | Begane grond N
_Merk-017 | Begane grond N
_Merk-013 | Begane grond N
_Merk-015 | Begane grond N
_Merk-013sp | Begane grond N
2 x _Merk-014 | Begane grond N
_Merk-008 | Begane grond N
80 x _Merk-x | 1e verdieping N
5 x _ | 1e verdieping N
_Merk-030sp | 1e verdieping N
2 x _Merk-032 | 1e verdieping N
3 x _Merk-031 | 1e verdieping N
_Merk-030 | 1e verdieping N
_Merk-007 | 1e verdieping N
Floor:23_3B_beton 170mm:888664 | 1e verdieping N | Pset_OpeningElementCommon - Reference: 23_3B_beton 170mm; sets with these values: 2
2 x Basic Wall:41_WA_stucwerk op iso 170mm:2040042 | 1e verdieping N | Pset_QuantityTakeOff - Reference: 21_CW_alu kozijn 070x065; sets with these values: 2
NLRS_32_DO_deur enkel_WID:930x2315 muurdikte 100mm:2729594 | 1e verdieping N
Basic Wall:NLRS_28_kalkzandsteen 214mm:2728058 | 1e verdieping N | Pset_QuantityTakeOff - Reference: 930x2315 muurdikte 100mm; sets with these values: 2
_Merk-039 | 1e verdieping N
8 x _Merk-027 | 1e verdieping N
3 x _Merk-028 | 1e verdieping N
2 x _Merk-028sp | 1e verdieping N
2 x _Merk-035 | 1e verdieping N
2 x _Merk-034 | 1e verdieping N
_Merk-029sp | 1e verdieping N
_Merk-036 | 1e verdieping N
_Merk-029 | 1e verdieping N
6 x _Merk-044 | 1e verdieping N
3 x _Merk-042 | 1e verdieping N
_Merk-043 | 1e verdieping N
_Merk-43sp | 1e verdieping N
_Merk-045 | 1e verdieping N
4 x _Merk-044sp | 1e verdieping N
_Merk-046 | 1e verdieping N
Basic Wall:NLRS_28_kalkzandsteen 214mm:2040039 | 1e verdieping N | Pset_QuantityTakeOff - Reference: 21_CW_alu kozijn 070x065; sets with these values: 2
Basic Wall:41_WA_stucwerk op iso 170mm:2039351 | 1e verdieping N | Pset_QuantityTakeOff - Reference: 21_CW_alu kozijn 070x065; sets with these values: 2
NLRS_32_DO_deur enkel_WID:930x2315 muurdikte 100mm:2039366 | 1e verdieping N
NLRS_32_DO_deur enkel_WID:930x2315 muurdikte 100mm:2039360 | 1e verdieping N
Basic Wall:41_WA_stucwerk op iso 170mm:2039353 | 1e verdieping N | Pset_QuantityTakeOff - Reference: 21_CW_alu kozijn 070x065; sets with these values: 2
Basic Wall:NLRS_28_kalkzandsteen 214mm:2039348 | 1e verdieping N | Pset_QuantityTakeOff - Reference: 21_CW_alu kozijn 070x065; sets with these values: 2
3 x _Merk-020sp | 1e verdieping N
_Merk-021 | 1e verdieping N
3 x _Merk-020 | 1e verdieping N
_Merk-018 | 1e verdieping N
Basic Wall:NLRS_28_kalkzandsteen 214mm:2039350 | 1e verdieping N | Pset_QuantityTakeOff - Reference: 21_CW_alu kozijn 070x065; sets with these values: 2
Basic Wall:NLRS_28_kalkzandsteen 214mm:2040021 | 1e verdieping N
_Merk-041 | 1e verdieping N
NLRS_32_DO_deur enkel_WID:930x2315 muurdikte 100mm:2947395 | 1e verdieping N
8 x _Merk-038 | 1e verdieping N
3 x _Merk-037 | 1e verdieping N
_Merk-038A | 1e verdieping N
_Merk-040 | 1e verdieping N
7 x _Merk-002 | 1e verdieping N
_Opening-x | 1e verdieping N | CPset_Phasing - Renovation Phase: Nieuw
8 x _Merk-052 | 2e verdieping N
4 x _Merk-051 | 2e verdieping N
_Merk-055 | 2e verdieping N
5 x _ | 2e verdieping N
69 x _Merk-x | 2e verdieping N
NLRS_32_DO_deur enkel_WID:930x2315 muurdikte 100mm:2039114 | 2e verdieping N
NLRS_32_DO_deur enkel_WID:930x2315 muurdikte 100mm:2039120 | 2e verdieping N
_Merk-056 | 2e verdieping N
2 x _Merk-057 | 2e verdieping N
_Merk-054 | 2e verdieping N
_Merk-053 | 2e verdieping N
11 x _Merk-048 | 2e verdieping N
_Merk-058 | 2e verdieping N
_Merk-058sp | 2e verdieping N
_Merk-050 | 2e verdieping N
7 x _Merk-002 | 2e verdieping N
_Merk-007 | 2e verdieping N
_Merk-049 | 2e verdieping N
_Merk-047 | 2e verdieping N
Basic Wall:31_WA_ALU_PANEEL:3102546 | 2e verdieping N | Pset_QuantityTakeOff - Reference: 21_CW_alu kozijn 084x065; sets with these values: 2
Basic Wall:41_WA_stucwerk op iso 170mm:2039105 | 2e verdieping N | Pset_QuantityTakeOff - Reference: 21_CW_alu kozijn 070x065; sets with these values: 2
Basic Wall:41_WA_stucwerk op iso 170mm:2039107 | 2e verdieping N | Pset_QuantityTakeOff - Reference: 21_CW_alu kozijn 070x065; sets with these values: 2
37 x _Merk-x | 2e verdieping V
Basic Wall:NLRS_28_kalkzandsteen 214mm:2013359 | 2e verdieping V | Pset_QuantityTakeOff - Reference: 21_CW_alu kozijn 070x065; sets with these values: 2; Group: Model Group:V vluchttrappenhuis 2:2013401
NLRS_32_DO_deur enkel_WID:930x2315 muurdikte 100mm:2013375 | 2e verdieping V
NLRS_32_DO_deur enkel_WID:930x2315 muurdikte 100mm:2013369 | 2e verdieping V
Basic Wall:NLRS_28_kalkzandsteen 214mm:2014444 | 2e verdieping V | Pset_QuantityTakeOff - Reference: 21_CW_alu kozijn 070x065; sets with these values: 2; Group: Model Group:V vluchttrappenhuis 2:2013401
Basic Wall:NLRS_28_kalkzandsteen 214mm:2013334 | 2e verdieping V
Basic Wall:NLRS_28_kalkzandsteen 214mm:2014453 | 3e verdieping/dak N | Pset_QuantityTakeOff - Reference: 21_CW_alu kozijn 070x065; sets with these values: 2; Group: Model Group:V vluchttrappenhuis 2:2013471
2 x _Merk-x | 3e verdieping/dak N
_Gang (entree woning) | 3e verdieping/dak N
Basic Wall:NLRS_28_kalkzandsteen 214mm:2013429 | 3e verdieping/dak N | Pset_QuantityTakeOff - Reference: 21_CW_alu kozijn 070x065; sets with these values: 2; Group: Model Group:V vluchttrappenhuis 2:2013471
Basic Wall:NLRS_28_kalkzandsteen 214mm:2013404 | 3e verdieping/dak N
NLRS_32_DO_deur enkel_WID:930x2315 muurdikte 100mm:2013439 | 3e verdieping/dak N
NLRS_32_DO_deur enkel_WID:930x2315 muurdikte 100mm:2013445 | 3e verdieping/dak N
Basic Wall:NLRS_28_kalkzandsteen 214mm:2014462 | 3e verdieping V | Pset_QuantityTakeOff - Reference: 21_CW_alu kozijn 070x065; sets with these values: 2; Group: Model Group:V vluchttrappenhuis 2:2013517
33 x _Merk-x | 3e verdieping V
Basic Wall:NLRS_28_kalkzandsteen 214mm:2013599 | 3e verdieping V
Basic Wall:NLRS_28_kalkzandsteen 214mm:2013625 | 3e verdieping V | Pset_QuantityTakeOff - Reference: 21_CW_alu kozijn 070x065; sets with these values: 2; Group: Model Group:V vluchttrappenhuis 2:2013517
NLRS_32_DO_deur enkel_WID:930x2315 muurdikte 100mm:2013642 | 3e verdieping V
NLRS_32_DO_deur enkel_WID:930x2315 muurdikte 100mm:2013636 | 3e verdieping V
34 x _Merk-x | 4e verdieping V
NLRS_32_DO_deur enkel_WID:930x2315 muurdikte 100mm:3085508 | 4e verdieping V
NLRS_32_DO_deur enkel_WID:930x2315 muurdikte 100mm:3085502 | 4e verdieping V
8 x _Gang (entree woning) | 4e verdieping V
Basic Wall:NLRS_28_kalkzandsteen 214mm:3085477 | 4e verdieping V
Basic Wall:41_WA_stucwerk op iso 170mm:3085497 | 4e verdieping V | Pset_OpeningElementCommon - Reference: 21_CW_alu kozijn 070x065; sets with these values: 2; Group: Model Group:V vluchttrappenhuis 2:2013112
Basic Wall:NLRS_28_kalkzandsteen 214mm:3085522 | 4e verdieping V | Pset_QuantityTakeOff - Reference: 21_CW_alu kozijn 070x065; sets with these values: 2; Group: Model Group:V vluchttrappenhuis 2:2013112
Basic Wall:NLRS_28_kalkzandsteen 214mm:3085494 | 4e verdieping V | Pset_QuantityTakeOff - Reference: 21_CW_alu kozijn 070x065; sets with these values: 2; Group: Model Group:V vluchttrappenhuis 2:2013112
34 x _Merk-x | 5e verdieping V
3 x Basic Wall:NLRS_21_basis 200mm:2467835 | 5e verdieping V | Pset_QuantityTakeOff - Reference: NLRS_21_basis 200mm; sets with these values: 2
8 x _Gang (entree woning) | 5e verdieping V
NLRS_32_DO_deur enkel_WID:930x2315 muurdikte 100mm:2536017 | 5e verdieping V
Basic Wall:GF 100/2.50.2.A:2469198 | 5e verdieping V | Pset_QuantityTakeOff - Reference: GF 100/2.50.2.A; sets with these values: 2
NLRS_32_DO_deur enkel_WID:930x2315 muurdikte 100mm:2539801 | 5e verdieping V
Basic Wall:NLRS_21_basis 200mm:2468300 | 5e verdieping V | Pset_QuantityTakeOff - Reference: 21_CW_alu kozijn 070x065; sets with these values: 2
NLRS_32_DO_deur enkel_WID:930x2315 muurdikte 100mm:2535975 | 5e verdieping V
Basic Wall:GF 100/2.50.2.A:2468759 | 5e verdieping V | Pset_QuantityTakeOff - Reference: GF 100/2.50.2.A; sets with these values: 2
3 x Basic Wall:NLRS_21_basis 200mm:2468543 | 5e verdieping V | Pset_QuantityTakeOff - Reference: 21_CW_alu kozijn 070x065; sets with these values: 2
2 x Basic Wall:NLRS_21_basis 200mm:2468543 | 5e verdieping V | Pset_OpeningElementCommon - Reference: 21_CW_alu kozijn 070x065; sets with these values: 2
Basic Wall:GF 100/2.50.2.A:2469740 | 5e verdieping V | Pset_QuantityTakeOff - Reference: GF 100/2.50.2.A; sets with these values: 2
NLRS_32_DO_deur enkel_WID:930x2315 muurdikte 100mm:2536748 | 5e verdieping V
Basic Wall:GF 100/2.50.2.A:2538670 | 5e verdieping V | Pset_QuantityTakeOff - Reference: 930x2315 muurdikte 100mm; sets with these values: 2
NLRS_32_DO_deur enkel_WID:930x2315 muurdikte 100mm:2535806 | 5e verdieping V
NLRS_32_DO_deur enkel_WID:930x2315 muurdikte 100mm:2541193 | 5e verdieping V
NLRS_32_DO_deur enkel_WID:930x2315 muurdikte 100mm:2534527 | 5e verdieping V
NLRS_32_DO_deur enkel_WID:930x2315 muurdikte 100mm:2479717 | 5e verdieping V
NLRS_32_DO_deur enkel_WID:930x2315 muurdikte 100mm:2539738 | 5e verdieping V
NLRS_32_DO_deur enkel_WID:930x2315 muurdikte 100mm:2538625 | 5e verdieping V
NLRS_32_DO_deur enkel_WID:930x2315 muurdikte 100mm:2538393 | 5e verdieping V
Basic Wall:GF 205 ECO DGS/2.75*75.2.AA:2479587 | 5e verdieping V | Pset_OpeningElementCommon - Reference: 21_CW_alu kozijn 070x065; sets with these values: 2
Basic Wall:GF 100/2.50.2.A:3206854 | 5e verdieping V | Pset_OpeningElementCommon - Reference: 21_CW_alu kozijn 070x065; sets with these values: 2
NLRS_32_DO_deur enkel_WID:930x2315 muurdikte 100mm:2535730 | 5e verdieping V
Basic Wall:41_WA_houten delen vert balkon/terras bij BT:2658072 | 5e verdieping V | Pset_QuantityTakeOff - Reference: 21_CW_alu kozijn 070x065; sets with these values: 2
2 x Basic Wall:41_WA_stucwerk op iso 110mm:1957910 | 5e verdieping V | Pset_QuantityTakeOff - Reference: 41_WA_stucwerk op iso 110mm; sets with these values: 2
5 x Basic Wall:41_WA_stucwerk op iso 110mm:2465232 | 5e verdieping V | Pset_QuantityTakeOff - Reference: 21_CW_alu kozijn 070x065; sets with these values: 2
Basic Wall:41_WA_stucwerk op iso 170mm:2463730:1 | 5e verdieping V | Pset_QuantityTakeOff - Reference: 41_WA_stucwerk op iso 170mm; sets with these values: 2
NLRS_32_DO_deur enkel_WID:930x2315 muurdikte 100mm:3081068 | 5e verdieping V
NLRS_32_DO_deur enkel_WID:930x2315 muurdikte 100mm:3081062 | 5e verdieping V
Basic Wall:NLRS_28_kalkzandsteen 214mm:3081035 | 5e verdieping V
Basic Wall:NLRS_28_kalkzandsteen 214mm:3081052 | 5e verdieping V | Pset_QuantityTakeOff - Reference: 21_CW_alu kozijn 070x065; sets with these values: 2; Group: Model Group:V vluchttrappenhuis V5:3080963
Basic Wall:NLRS_28_kalkzandsteen 214mm:3081811 | 5e verdieping V | Pset_QuantityTakeOff - Reference: 21_CW_alu kozijn 070x065; sets with these values: 2; Group: Model Group:V vluchttrappenhuis V5:3080963
2 x Basic Wall:21_WA_gevel V plaat tussen kozijnen op binnenblad - kozijnmaat:3093944 | 5e verdieping V | Pset_QuantityTakeOff - Reference: 21_CW_alu kozijn 070x065; sets with these values: 2
Basic Wall:21_WA_gevel V plaat tussen kozijnen op binnenblad - kozijnmaat:2667654 | 5e verdieping V | Pset_QuantityTakeOff - Reference: 21_CW_alu kozijn 070x065; sets with these values: 2
Basic Wall:41_WA_stucwerk op iso 110mm:3140915 | 5e verdieping V | Pset_OpeningElementCommon - Reference: 21_CW_alu kozijn 070x065; sets with these values: 2; Group: Model Group:V vluchttrappenhuis V5:3080963
Basic Wall:21_WA_gevel V plaat tussen kozijnen op binnenblad - kozijnmaat:2667732 | 5e verdieping V | Pset_QuantityTakeOff - Reference: 21_CW_alu kozijn 070x065; sets with these values: 2
2 x Basic Wall:21_WA_gevel V iso stuc systeem Nieuwe dakrand - 410mm:2754110 | 5e verdieping V | Pset_OpeningElementCommon - Reference: 21_CW_alu kozijn 070x065; sets with these values: 2
3 x Basic Wall:21_WA_gevel V iso stuc systeem Nieuwe dakrand - 410mm:2754110 | 5e verdieping V | Pset_QuantityTakeOff - Reference: 21_CW_alu kozijn 070x065; sets with these values: 2
Basic Wall:41_WA_stucwerk op iso 110mm:3090988 | 5e verdieping V | Pset_QuantityTakeOff - Reference: 21_CW_alu kozijn 070x065; sets with these values: 2; Group: Model Group:V vluchttrappenhuis V5:3080963
2 x _Merk-x | 6e verdieping V
Basic Wall:NLRS_22_gasbeton 100mm:2091721 | 6e verdieping V | Pset_QuantityTakeOff - Reference: NLRS_22_gasbeton 100mm; sets with these values: 2
Basic Wall:NLRS_22_gasbeton 100mm:2091764 | 6e verdieping V | Pset_QuantityTakeOff - Reference: NLRS_22_gasbeton 100mm; sets with these values: 2

# IfcPlate: 30_3B_alu deur met glas:deur RAL 7024 (3)
In: 1e verdieping N
Type - PredefinedType: CURTAIN_PANEL
Material: IFC Building Material
Pset_QuantityTakeOff - Reference: deur RAL 7024
Pset_PlateCommon - Reference: deur RAL 7024; IsExternal: yes; LoadBearing: no
CPset_Phasing - Renovation Phase: Nieuw
Material Properties - IFC Building Material, ThermalConductivity: 2.3; IFC Building Material, SpecificHeatCapacity: 1000 J/kg/K; IFC Building Material, MassDensity: 2300 kg/m3; IFC Building Material, Embodied Energy: 1.92 (MJ/kg); IFC Building Material, Embodied Carbon: 0.198 (kgCO₂/kg); IFC Building Material, Name: IFC Building Material; IFC Building Material, Participates in Collision Detection: yes
Name (30_3B_alu deur met glas:deur RAL 7024:...)
2726617
2815521
2947046

# IfcPlate: 30_3B_vliesgevel - raam_01_BI:raam, 30_3B_vliesgevel - raam_01_BI:raam:2542068
In: 5e verdieping V
Type - PredefinedType: CURTAIN_PANEL
Material: IFC Building Material
CPset_Phasing - Renovation Phase: Nieuw
Material Properties - IFC Building Material, ThermalConductivity: 2.3; IFC Building Material, SpecificHeatCapacity: 1000 J/kg/K; IFC Building Material, MassDensity: 2300 kg/m3; IFC Building Material, Embodied Energy: 1.92 (MJ/kg); IFC Building Material, Embodied Carbon: 0.198 (kgCO₂/kg); IFC Building Material, Name: IFC Building Material; IFC Building Material, Participates in Collision Detection: yes
Pset_PlateCommon - Reference: raam; IsExternal: yes; LoadBearing: no
Pset_QuantityTakeOff - Reference: raam

# IfcPlate: 30_3B_vliesgevel - raam_01_BI:raam RAL 7024 (2)
In: 5e verdieping V
Type - PredefinedType: CURTAIN_PANEL
Material: IFC Building Material
Pset_QuantityTakeOff - Reference: raam RAL 7024
Pset_PlateCommon - Reference: raam RAL 7024; IsExternal: yes; LoadBearing: no
CPset_Phasing - Renovation Phase: Nieuw
Material Properties - IFC Building Material, ThermalConductivity: 2.3; IFC Building Material, SpecificHeatCapacity: 1000 J/kg/K; IFC Building Material, MassDensity: 2300 kg/m3; IFC Building Material, Embodied Energy: 1.92 (MJ/kg); IFC Building Material, Embodied Carbon: 0.198 (kgCO₂/kg); IFC Building Material, Name: IFC Building Material; IFC Building Material, Participates in Collision Detection: yes
Name (30_3B_vliesgevel - raam_01_BI:raam RAL 7024:...)
3094152
3094181

# IfcPlate: 30_3B_vliesgevel - vastglas:vast glas_bi vast (15)
In: 2e verdieping N
Type - PredefinedType: CURTAIN_PANEL
Material: glas (1)
Pset_PlateCommon - Reference: vast glas_bi vast; IsExternal: yes; LoadBearing: no
CPset_Phasing - Renovation Phase: Nieuw
Pset_QuantityTakeOff - Reference: vast glas_bi vast
Material Properties - glas (1), ThermalConductivity: 2.3; glas (1), SpecificHeatCapacity: 1000 J/kg/K; glas (1), MassDensity: 2300 kg/m3; glas (1), Embodied Energy: 1.92 (MJ/kg); glas (1), Embodied Carbon: 0.198 (kgCO₂/kg); glas (1), Name: glas (1); glas (1), Participates in Collision Detection: yes
Name (30_3B_vliesgevel - vastglas:vast glas_bi vast:...)
3024883
3024888
3024872
3024878
3024081
3024070
3024354
3024365
3109513
3024323
3024329
3024593
3024334
3021937
2974188

# IfcPlate: Strip Dak Entree V:Strip Dak Entree V, Strip Dak Entree V:Strip Dak Entree V:2747701
In: 1e verdieping N
Material: staal geanodiseerd RAL 7024
Pset_QuantityTakeOff - Reference: Strip Dak Entree V
CPset_Phasing - Renovation Phase: Nieuw
Pset_PlateCommon - Reference: Strip Dak Entree V; IsExternal: no; LoadBearing: no
Material Properties - staal geanodiseerd RAL 7024, ThermalConductivity: 2.3; staal geanodiseerd RAL 7024, SpecificHeatCapacity: 1000 J/kg/K; staal geanodiseerd RAL 7024, MassDensity: 2300 kg/m3; staal geanodiseerd RAL 7024, Embodied Energy: 1.92 (MJ/kg); staal geanodiseerd RAL 7024, Embodied Carbon: 0.198 (kgCO₂/kg); staal geanodiseerd RAL 7024, Name: staal geanodiseerd RAL 7024; staal geanodiseerd RAL 7024, Participates in Collision Detection: yes

# IfcPlate: System Panel:31_3B_glas, System Panel:31_3B_glas:2769457
In: 7e verdieping-dak V
Type - PredefinedType: CURTAIN_PANEL
Material: paneel_vliesgevel_glas
Pset_PlateCommon - Reference: 31_3B_glas; IsExternal: yes; LoadBearing: no
Pset_QuantityTakeOff - Reference: 31_3B_glas
CPset_Phasing - Renovation Phase: Nieuw
Material Properties - paneel_vliesgevel_glas, ThermalConductivity: 2.3; paneel_vliesgevel_glas, SpecificHeatCapacity: 1000 J/kg/K; paneel_vliesgevel_glas, MassDensity: 2300 kg/m3; paneel_vliesgevel_glas, Embodied Energy: 1.92 (MJ/kg); paneel_vliesgevel_glas, Embodied Carbon: 0.198 (kgCO₂/kg); paneel_vliesgevel_glas, Name: paneel_vliesgevel_glas; paneel_vliesgevel_glas, Participates in Collision Detection: yes

# IfcPlate: System Panel:31_3B_paneel alu pui RAL ntb (2)
In: 5e verdieping V
Type - PredefinedType: CURTAIN_PANEL
Material: RAL 7024 - Grafietgrijs
Pset_QuantityTakeOff - Reference: 31_3B_paneel alu pui RAL ntb
Pset_PlateCommon - Reference: 31_3B_paneel alu pui RAL ntb; IsExternal: yes; LoadBearing: no
CPset_Phasing - Renovation Phase: Nieuw
Material Properties - RAL 7024 - Grafietgrijs, ThermalConductivity: 2.3; RAL 7024 - Grafietgrijs, SpecificHeatCapacity: 1000 J/kg/K; RAL 7024 - Grafietgrijs, MassDensity: 2300 kg/m3; RAL 7024 - Grafietgrijs, Embodied Energy: 1.92 (MJ/kg); RAL 7024 - Grafietgrijs, Embodied Carbon: 0.198 (kgCO₂/kg); RAL 7024 - Grafietgrijs, Name: RAL 7024 - Grafietgrijs; RAL 7024 - Grafietgrijs, Participates in Collision Detection: yes
Name (System Panel:31_3B_paneel alu pui RAL ntb:...)
2772155
2772189

# IfcPlate: System Panel:31_3B_paneel ral 7016, System Panel:31_3B_paneel ral 7016:3089619
In: 5e verdieping V
Type - PredefinedType: CURTAIN_PANEL
Material: RAL 7016 - Antracietgrijs
Pset_QuantityTakeOff - Reference: 31_3B_paneel ral 7016
Pset_PlateCommon - Reference: 31_3B_paneel ral 7016; IsExternal: yes; LoadBearing: no
Material Properties - RAL 7016 - Antracietgrijs, ThermalConductivity: 2.3; RAL 7016 - Antracietgrijs, SpecificHeatCapacity: 1000 J/kg/K; RAL 7016 - Antracietgrijs, MassDensity: 2300 kg/m3; RAL 7016 - Antracietgrijs, Embodied Energy: 1.92 (MJ/kg); RAL 7016 - Antracietgrijs, Embodied Carbon: 0.198 (kgCO₂/kg); RAL 7016 - Antracietgrijs, Name: RAL 7016 - Antracietgrijs; RAL 7016 - Antracietgrijs, Participates in Collision Detection: yes
CPset_Phasing - Renovation Phase: Nieuw

# IfcPlate: System Panel:31_3B_paneel ral 7024, System Panel:31_3B_paneel ral 7024:2997688
In: 5e verdieping V
Type - PredefinedType: CURTAIN_PANEL
Material: RAL 7024 - Grafietgrijs
Pset_QuantityTakeOff - Reference: 31_3B_paneel ral 7024
Pset_PlateCommon - Reference: 31_3B_paneel ral 7024; IsExternal: yes; LoadBearing: no
Material Properties - RAL 7024 - Grafietgrijs, ThermalConductivity: 2.3; RAL 7024 - Grafietgrijs, SpecificHeatCapacity: 1000 J/kg/K; RAL 7024 - Grafietgrijs, MassDensity: 2300 kg/m3; RAL 7024 - Grafietgrijs, Embodied Energy: 1.92 (MJ/kg); RAL 7024 - Grafietgrijs, Embodied Carbon: 0.198 (kgCO₂/kg); RAL 7024 - Grafietgrijs, Name: RAL 7024 - Grafietgrijs; RAL 7024 - Grafietgrijs, Participates in Collision Detection: yes
CPset_Phasing - Renovation Phase: Nieuw

# IfcPlate: System Panel:31_CWP_alu glas_2 (50)
Type - PredefinedType: CURTAIN_PANEL
Material: Glass
Pset_QuantityTakeOff - Reference: 31_CWP_alu glas_2
Pset_PlateCommon - Reference: 31_CWP_alu glas_2; IsExternal: yes; LoadBearing: no
Material Properties - Glass, ThermalConductivity: 2.3; Glass, SpecificHeatCapacity: 1000 J/kg/K; Glass, MassDensity: 2300 kg/m3; Glass, Embodied Energy: 1.92 (MJ/kg); Glass, Embodied Carbon: 0.198 (kgCO₂/kg); Glass, Name: Glass; Glass, Participates in Collision Detection: yes
CPset_Phasing - Renovation Phase: Nieuw
Name (System Panel:31_CWP_alu glas_2:...) | In | Group
2039355 | 1e verdieping N | Model Group:V-koz-M nieuw 2:2039379
2039381 | 1e verdieping N | Model Group:V-koz-M nieuw 2:2039391
3140551 | 1e verdieping N | Model Group:KOZ-03:3140556
3142362 | 1e verdieping N | Model Group:KOZ-03:3142360
2730058 | 1e verdieping N
2728846 | 1e verdieping N
3088431 | 1e verdieping N
2815515 | 1e verdieping N
2949292 | 1e verdieping N
2946773 | 1e verdieping N
2949106 | 1e verdieping N
2039109 | 2e verdieping N | Model Group:V-koz-M nieuw 2:2039133
2039135 | 2e verdieping N | Model Group:V-koz-M nieuw 2:2039145
3026229 | 2e verdieping N
3027174 | 2e verdieping N
3027240 | 2e verdieping N
3168169 | 2e verdieping N
3108138 | 2e verdieping N
2973607 | 2e verdieping N
3140559 | 2e verdieping N | Model Group:KOZ-03:3140557
3088417 | 2e verdieping N | Model Group:KOZ-03:3087227
3104776 | 2e verdieping N
2013364 | 2e verdieping V | Model Group:V-koz-M nieuw 2:2013388
2765755 | 2e verdieping V | Model Group:KOZ-03:2767540
3140523 | 2e verdieping V | Model Group:KOZ-03:3140528
2013390 | 2e verdieping V | Model Group:V-koz-M nieuw 2:2013400
2013434 | 3e verdieping/dak N | Model Group:V-koz-M nieuw 2:2013458
2013460 | 3e verdieping/dak N | Model Group:V-koz-M nieuw 2:2013470
3140530 | 3e verdieping/dak N | Model Group:KOZ-03:3140535
2767561 | 3e verdieping/dak N | Model Group:KOZ-03:2767569
2013631 | 3e verdieping V | Model Group:V-koz-M nieuw 2:2013655
2767579 | 3e verdieping V | Model Group:KOZ-03:2767587
3140537 | 3e verdieping V | Model Group:KOZ-03:3140542
2013657 | 3e verdieping V | Model Group:V-koz-M nieuw 2:2013667
3085499 | 4e verdieping V | Model Group:V-koz-M nieuw 2:3085515
3085517 | 4e verdieping V | Model Group:V-koz-M nieuw 2:3085520
2767613 | 4e verdieping V | Model Group:KOZ-03:2767621
3140544 | 4e verdieping V | Model Group:KOZ-03:3140549
2538974 | 5e verdieping V
2539141 | 5e verdieping V
3140741 | 5e verdieping V | Model Group:V vluchttrappenhuis V5:3080963
2759502 | 5e verdieping V
3140910 | 5e verdieping V | Model Group:V vluchttrappenhuis V5:3080963
2561724 | 5e verdieping V
2561734 | 5e verdieping V
3081077 | 5e verdieping V | Model Group:V vluchttrappenhuis V5:3080963
3081059 | 5e verdieping V | Model Group:V vluchttrappenhuis V5:3080963
3084843 | 5e verdieping V | Model Group:V vluchttrappenhuis V5:3080963
2553351 | 5e verdieping V
2550082 | 5e verdieping V

# IfcRailing: Railing Type (15)
Pset_RailingCommon - IsExternal: no
Name | In | Renovation Phase
5 x _Reling-x | Begane grond N | Bestaand
4 x _Reling-x | Begane grond N | Nieuw
3 x _Reling-x | 1e verdieping N | Bestaand
3 x _Reling-x | 1e verdieping N | Nieuw

# IfcRailing: Railing:44_3B_leuning - staal 50x10mm (14)
Material: baluster_staal
Pset_RailingCommon - Reference: 44_3B_leuning - staal 50x10mm; Height: 1219.2 mm; IsExternal: no
Pset_QuantityTakeOff - Reference: 44_3B_leuning - staal 50x10mm
CPset_Phasing - Renovation Phase: Nieuw
Material Properties - baluster_staal, ThermalConductivity: 2.3; baluster_staal, SpecificHeatCapacity: 1000 J/kg/K; baluster_staal, MassDensity: 2300 kg/m3; baluster_staal, Embodied Energy: 1.92 (MJ/kg); baluster_staal, Embodied Carbon: 0.198 (kgCO₂/kg); baluster_staal, Name: baluster_staal; baluster_staal, Participates in Collision Detection: yes
Name (Railing:44_3B_leuning - staal 50x10mm:...) | In
2462846 | 1e verdieping N
2462861 | 1e verdieping N
2462874 | 1e verdieping N
2462833 | 1e verdieping N
2462889 | 2e verdieping N
2462902 | 2e verdieping N
2462930 | 2e verdieping V
2462917 | 2e verdieping V
2462958 | 3e verdieping/dak N
2462945 | 3e verdieping/dak N
2462986 | 3e verdieping V
2462973 | 3e verdieping V
2462809 | 4e verdieping V
2014640 | 4e verdieping V

# IfcRailing: Railing:44_3B_leuning - staal Ø40 (14)
Material: baluster_staal
Pset_RailingCommon - Reference: 44_3B_leuning - staal Ø40; Height: 1219.2 mm; IsExternal: no
CPset_Phasing - Renovation Phase: Nieuw
Material Properties - baluster_staal, ThermalConductivity: 2.3; baluster_staal, SpecificHeatCapacity: 1000 J/kg/K; baluster_staal, MassDensity: 2300 kg/m3; baluster_staal, Embodied Energy: 1.92 (MJ/kg); baluster_staal, Embodied Carbon: 0.198 (kgCO₂/kg); baluster_staal, Name: baluster_staal; baluster_staal, Participates in Collision Detection: yes
Pset_QuantityTakeOff - Reference: 44_3B_leuning - staal Ø40
Name (Railing:44_3B_leuning - staal Ø40:...) | In
2462842 | 1e verdieping N
2462857 | 1e verdieping N
2462870 | 1e verdieping N
2462829 | 1e verdieping N
2462885 | 2e verdieping N
2462898 | 2e verdieping N
2462926 | 2e verdieping V
2462913 | 2e verdieping V
2462954 | 3e verdieping/dak N
2462941 | 3e verdieping/dak N
2462982 | 3e verdieping V
2462969 | 3e verdieping V
2462805 | 4e verdieping V
2014636 | 4e verdieping V

# IfcRoof, Fascia:47_3B_dakrand HMB:3135497
In: 2e verdieping N
Material: Aluminum geanodiseerd RAL 7024
Pset_RoofCommon - Reference: 47_3B_dakrand HMB; IsExternal: no
Pset_QuantityTakeOff - Reference: 47_3B_dakrand HMB
CPset_Phasing - Renovation Phase: Nieuw
Material Properties - Aluminum geanodiseerd RAL 7024, ThermalConductivity: 2.3; Aluminum geanodiseerd RAL 7024, SpecificHeatCapacity: 1000 J/kg/K; Aluminum geanodiseerd RAL 7024, MassDensity: 2300 kg/m3; Aluminum geanodiseerd RAL 7024, Embodied Energy: 1.92 (MJ/kg); Aluminum geanodiseerd RAL 7024, Embodied Carbon: 0.198 (kgCO₂/kg); Aluminum geanodiseerd RAL 7024, Name: Aluminum geanodiseerd RAL 7024; Aluminum geanodiseerd RAL 7024, Participates in Collision Detection: yes

# IfcRoof: Basic Roof:27_3B_beton 200mm, Basic Roof:27_3B_beton 200mm:2973010
In: 5e verdieping V
Pset_QuantityTakeOff - Reference: 27_3B_beton 200mm
Pset_RoofCommon - IsExternal: yes; Reference: 27_3B_beton 200mm; ProjectedArea: 45.5555 m2; TotalArea: 45.5555 m2

# IfcRoof: Basic Roof:27_3B_beton 300mm (3)
Pset_RoofCommon - IsExternal: yes; Reference: 27_3B_beton 300mm
Pset_QuantityTakeOff - Reference: 27_3B_beton 300mm
Name (Basic Roof:27_3B_beton 300mm:...) | In | ProjectedArea (m2) = TotalArea (m2)
3106531 | 2e verdieping N | 89.0058
3106520 | 2e verdieping N | 53.3518
2092854 | 6e verdieping V | 273.872

# IfcRoof: Basic Roof:27_3B_houten balklaag, Basic Roof:27_3B_houten balklaag:2727762
In: 1e verdieping N
Pset_RoofCommon - IsExternal: yes; Reference: 27_3B_houten balklaag; ProjectedArea: 30.0071 m2; TotalArea: 30.0071 m2
Pset_QuantityTakeOff - Reference: 27_3B_houten balklaag

# IfcRoof: Basic Roof:NLRS_27_RO_dakleer iso 164 2-2-160_gen (3)
Pset_RoofCommon - IsExternal: yes; Reference: NLRS_27_RO_dakleer iso 164 2-2-160_gen
Pset_QuantityTakeOff - Reference: NLRS_27_RO_dakleer iso 164 2-2-160_gen
Name (Basic Roof:NLRS_27_RO_dakleer iso 164 2-2-160_gen:...) | In | ProjectedArea (m2) = TotalArea (m2)
3101106 | 2e verdieping N | 91.0849
2987001 | 2e verdieping N | 55.4309
3110331 | 2e verdieping V | 28.671

# IfcRoof: Basic Roof:NLRS_27_RO_dakleer iso 204 2-2-200_gen, Basic Roof:NLRS_27_RO_dakleer iso 204 2-2-200_gen:2681941
In: 6e verdieping V
Pset_QuantityTakeOff - Reference: NLRS_27_RO_dakleer iso 204 2-2-200_gen
Pset_RoofCommon - IsExternal: yes; Reference: NLRS_27_RO_dakleer iso 204 2-2-200_gen; ProjectedArea: 264.879 m2; TotalArea: 264.879 m2

# IfcRoof: Sloped Glazing:27_3B_lichtstraat, Sloped Glazing:27_3B_lichtstraat:2769413
In: 7e verdieping-dak V
Pset_RoofCommon - IsExternal: yes; Reference: 27_3B_lichtstraat; ProjectedArea: 2.38929 m2
Pset_QuantityTakeOff - Reference: 27_3B_lichtstraat

# IfcSlab: ALG - BINNENAFWERKING 25 (14)
In: 1e verdieping N
Material: ALG - BINNENAFWERKING
CPset_Phasing - Renovation Phase: Nieuw
Pset_SlabCommon - FireRating: n.v.t.; IsExternal: no; LoadBearing: yes
Material Properties - ALG - BINNENAFWERKING, ThermalConductivity: 0.27; ALG - BINNENAFWERKING, SpecificHeatCapacity: 840 J/kg/K; ALG - BINNENAFWERKING, MassDensity: 800 kg/m3; ALG - BINNENAFWERKING, Embodied Energy: 2 (MJ/kg); ALG - BINNENAFWERKING, Embodied Carbon: 0.13 (kgCO₂/kg); ALG - BINNENAFWERKING, Name: ALG - BINNENAFWERKING; ALG - BINNENAFWERKING, Participates in Collision Detection: yes

# IfcSlab: ALG - BINNENAFWERKING 40 (104)
Material: ALG - BINNENAFWERKING
Pset_SlabCommon - FireRating: n.v.t.; IsExternal: no; LoadBearing: yes
CPset_Phasing - Renovation Phase: Nieuw
Material Properties - ALG - BINNENAFWERKING, ThermalConductivity: 0.27; ALG - BINNENAFWERKING, SpecificHeatCapacity: 840 J/kg/K; ALG - BINNENAFWERKING, MassDensity: 800 kg/m3; ALG - BINNENAFWERKING, Embodied Energy: 2 (MJ/kg); ALG - BINNENAFWERKING, Embodied Carbon: 0.13 (kgCO₂/kg); ALG - BINNENAFWERKING, Name: ALG - BINNENAFWERKING; ALG - BINNENAFWERKING, Participates in Collision Detection: yes
Name | In
35 x _Vloer-x | Begane grond N
41 x _Vloer-x | 1e verdieping N
28 x _Vloer-x | 2e verdieping N

# IfcSlab: ALG - CONSTRUCTIEF VLOER 200 (2)
Material: ALG - CONSTRUCTIEF VLOER
Pset_SlabCommon - FireRating: n.v.t.; IsExternal: no; LoadBearing: yes
CPset_Phasing - Renovation Phase: Bestaand
Material Properties - ALG - CONSTRUCTIEF VLOER, ThermalConductivity: 2.5; ALG - CONSTRUCTIEF VLOER, SpecificHeatCapacity: 1000 J/kg/K; ALG - CONSTRUCTIEF VLOER, MassDensity: 2400 kg/m3; ALG - CONSTRUCTIEF VLOER, Embodied Energy: 2.33 (MJ/kg); ALG - CONSTRUCTIEF VLOER, Embodied Carbon: 0.242 (kgCO₂/kg); ALG - CONSTRUCTIEF VLOER, Name: ALG - CONSTRUCTIEF VLOER; ALG - CONSTRUCTIEF VLOER, Participates in Collision Detection: yes
Name | In
_Vloer-x | Begane grond N
_Vloer-x | 1e verdieping N

# IfcSlab: ALG - CONSTRUCTIEF VLOER 210 (2)
Material: ALG - CONSTRUCTIEF VLOER
Pset_SlabCommon - FireRating: n.v.t.; IsExternal: no; LoadBearing: yes
Material Properties - ALG - CONSTRUCTIEF VLOER, ThermalConductivity: 2.5; ALG - CONSTRUCTIEF VLOER, SpecificHeatCapacity: 1000 J/kg/K; ALG - CONSTRUCTIEF VLOER, MassDensity: 2400 kg/m3; ALG - CONSTRUCTIEF VLOER, Embodied Energy: 2.33 (MJ/kg); ALG - CONSTRUCTIEF VLOER, Embodied Carbon: 0.242 (kgCO₂/kg); ALG - CONSTRUCTIEF VLOER, Name: ALG - CONSTRUCTIEF VLOER; ALG - CONSTRUCTIEF VLOER, Participates in Collision Detection: yes
CPset_Phasing - Renovation Phase: Bestaand
Name | In
_Vloer-x | 2e verdieping V
_Vloer-x | 3e verdieping/dak N

# IfcSlab: ALG - CONSTRUCTIEF VLOER 300 (4)
Material: ALG - CONSTRUCTIEF VLOER
CPset_Phasing - Renovation Phase: Bestaand
Pset_SlabCommon - FireRating: n.v.t.; IsExternal: no; LoadBearing: yes
Material Properties - ALG - CONSTRUCTIEF VLOER, ThermalConductivity: 2.5; ALG - CONSTRUCTIEF VLOER, SpecificHeatCapacity: 1000 J/kg/K; ALG - CONSTRUCTIEF VLOER, MassDensity: 2400 kg/m3; ALG - CONSTRUCTIEF VLOER, Embodied Energy: 2.33 (MJ/kg); ALG - CONSTRUCTIEF VLOER, Embodied Carbon: 0.242 (kgCO₂/kg); ALG - CONSTRUCTIEF VLOER, Name: ALG - CONSTRUCTIEF VLOER; ALG - CONSTRUCTIEF VLOER, Participates in Collision Detection: yes
Name | In
_Vloer-x | 1e verdieping N
_Vloer-x | 2e verdieping V
2 x _Vloer-x | 3e verdieping/dak N

# IfcSlab: ALG - ONTWERPWAND 200, _Vloer-x
In: 2e verdieping N
Material: ALG - ONTWERPWAND
Pset_SlabCommon - FireRating: n.v.t.; IsExternal: no; LoadBearing: yes
Material Properties - ALG - ONTWERPWAND, ThermalConductivity: 2.3; ALG - ONTWERPWAND, SpecificHeatCapacity: 1000 J/kg/K; ALG - ONTWERPWAND, MassDensity: 2300 kg/m3; ALG - ONTWERPWAND, Embodied Energy: 1.92 (MJ/kg); ALG - ONTWERPWAND, Embodied Carbon: 0.198 (kgCO₂/kg); ALG - ONTWERPWAND, Name: ALG - ONTWERPWAND; ALG - ONTWERPWAND, Participates in Collision Detection: yes
CPset_Phasing - Renovation Phase: Nieuw

# IfcSlab: ALG Vloer 200 (19)
Material: ALG - CONSTRUCTIEF VLOER
Pset_SlabCommon - FireRating: n.v.t.; IsExternal: no; LoadBearing: yes
Material Properties - ALG - CONSTRUCTIEF VLOER, ThermalConductivity: 2.5; ALG - CONSTRUCTIEF VLOER, SpecificHeatCapacity: 1000 J/kg/K; ALG - CONSTRUCTIEF VLOER, MassDensity: 2400 kg/m3; ALG - CONSTRUCTIEF VLOER, Embodied Energy: 2.33 (MJ/kg); ALG - CONSTRUCTIEF VLOER, Embodied Carbon: 0.242 (kgCO₂/kg); ALG - CONSTRUCTIEF VLOER, Name: ALG - CONSTRUCTIEF VLOER; ALG - CONSTRUCTIEF VLOER, Participates in Collision Detection: yes
Name | In | Renovation Phase
_Vloer-x | Fundering N | Bestaand
4 x _Vloer-x | Begane grond N | Bestaand
2 x _Vloer-x | 1e verdieping N | Bestaand
2 x _Vloer-x | 2e verdieping N | Bestaand
2 x _Vloer-x | 2e verdieping V | Bestaand
_Vloer-x | 3e verdieping V | Bestaand
2 x _Vloer-x | 4e verdieping V | Bestaand
2 x _Vloer-x | 4e verdieping V | Nieuw
_Vloer-x | 5e verdieping V | Bestaand
2 x _Vloer-x | 6e verdieping V | Bestaand

# IfcSlab: Beton gewapend prefab vloer 100, _Vloer-x
In: 1e verdieping N
Material: Beton gewapend prefab vloer
Pset_SlabCommon - FireRating: n.v.t.; IsExternal: no; LoadBearing: yes
CPset_Phasing - Renovation Phase: Nieuw
Material Properties - Beton gewapend prefab vloer, ThermalConductivity: 2.5; Beton gewapend prefab vloer, SpecificHeatCapacity: 1000 J/kg/K; Beton gewapend prefab vloer, MassDensity: 2400 kg/m3; Beton gewapend prefab vloer, Embodied Energy: 2.33 (MJ/kg); Beton gewapend prefab vloer, Embodied Carbon: 0.242 (kgCO₂/kg); Beton gewapend prefab vloer, Name: Beton gewapend prefab vloer; Beton gewapend prefab vloer, Participates in Collision Detection: yes

# IfcSlab: Floor:23_3B_basis 200mm, Floor:23_3B_basis 200mm:2614401
In: 5e verdieping V
Type - PredefinedType: FLOOR
Material: beton
Pset_QuantityTakeOff - Reference: 23_3B_basis 200mm; sets with these values: 2
Pset_SlabCommon - PitchAngle: 0 deg; Reference: 23_3B_basis 200mm; IsExternal: no; LoadBearing: no
CPset_Phasing - Renovation Phase: Nieuw
Material Properties - beton, ThermalConductivity: 2.3; beton, SpecificHeatCapacity: 1000 J/kg/K; beton, MassDensity: 2300 kg/m3; beton, Embodied Energy: 1.92 (MJ/kg); beton, Embodied Carbon: 0.198 (kgCO₂/kg); beton, Name: beton; beton, Participates in Collision Detection: yes

# IfcSlab: Floor:23_3B_beton 170mm (9)
Type - PredefinedType: FLOOR
Material: beton
Pset_SlabCommon - Reference: 23_3B_beton 170mm; PitchAngle: 0 deg; IsExternal: no; LoadBearing: no
CPset_Phasing - Renovation Phase: Nieuw
Material Properties - beton, ThermalConductivity: 2.3; beton, SpecificHeatCapacity: 1000 J/kg/K; beton, MassDensity: 2300 kg/m3; beton, Embodied Energy: 1.92 (MJ/kg); beton, Embodied Carbon: 0.198 (kgCO₂/kg); beton, Name: beton; beton, Participates in Collision Detection: yes
Name (Floor:23_3B_beton 170mm:...) | In | Pset_ReinforcementBarPitchOfSlab, Reference | Pset_ReinforcementBarPitchOfSlab, sets with these values
2040027 | 1e verdieping N | Pset_QuantityTakeOff - Reference: 23_3B_beton 170mm; sets with these values: 2
2039336 | 1e verdieping N | 23_3B_beton 170mm | 2
2973614 | 2e verdieping N | 23_3B_beton 170mm | 2
2039090 | 2e verdieping N | 23_3B_beton 170mm | 2
2013340 | 2e verdieping V | 23_3B_beton 170mm | 2 | Group: Model Group:V vluchttrappenhuis 2:2013401
2013410 | 3e verdieping/dak N | 23_3B_beton 170mm | 2 | Group: Model Group:V vluchttrappenhuis 2:2013471
2013605 | 3e verdieping V | 23_3B_beton 170mm | 2 | Group: Model Group:V vluchttrappenhuis 2:2013517
3085483 | 4e verdieping V | 23_3B_beton 170mm | 2 | Group: Model Group:V vluchttrappenhuis 2:2013112
2094311 | 5e verdieping V | 23_3B_beton 170mm | 2

# IfcSlab: Floor:23_3B_beton 170mm + 50mm metal deck (11)
Type - PredefinedType: FLOOR
Material: beton
Pset_SlabCommon - PitchAngle: 0 deg; Reference: 23_3B_beton 170mm + 50mm metal deck; IsExternal: no; LoadBearing: no
CPset_Phasing - Renovation Phase: Nieuw
Material Properties - beton, ThermalConductivity: 2.3; beton, SpecificHeatCapacity: 1000 J/kg/K; beton, MassDensity: 2300 kg/m3; beton, Embodied Energy: 1.92 (MJ/kg); beton, Embodied Carbon: 0.198 (kgCO₂/kg); beton, Name: beton; beton, Participates in Collision Detection: yes
Name (Floor:23_3B_beton 170mm + 50mm metal deck:...) | In | Pset_ReinforcementBarPitchOfSlab, Reference | Pset_ReinforcementBarPitchOfSlab, sets with these values | Group
2972342 | 2e verdieping V | 23_3B_beton 170mm + 50mm metal deck | 2 | Model Group:BUITENRUIMTE helft:2972347
2972315 | 2e verdieping V | 23_3B_beton 170mm + 50mm metal deck | 2 | Model Group:BUITENRUIMTE helft:2972320
2972014 | 3e verdieping/dak N |  |  | Model Group:BUITENRUIMTE helft:2972019 | Pset_QuantityTakeOff - Reference: 23_3B_beton 170mm + 50mm metal deck; sets with these values: 2
2972041 | 3e verdieping/dak N | 23_3B_beton 170mm + 50mm metal deck | 2 | Model Group:BUITENRUIMTE helft:2972046
2972068 | 3e verdieping V | 23_3B_beton 170mm + 50mm metal deck | 2 | Model Group:BUITENRUIMTE helft:2972073
2972095 | 3e verdieping V | 23_3B_beton 170mm + 50mm metal deck | 2 | Model Group:BUITENRUIMTE helft:2972100
2971960 | 4e verdieping V | 23_3B_beton 170mm + 50mm metal deck | 2 | Model Group:BUITENRUIMTE helft:2971965
2971987 | 4e verdieping V | 23_3B_beton 170mm + 50mm metal deck | 2 | Model Group:BUITENRUIMTE helft:2971992
2972609 | 5e verdieping V | 23_3B_beton 170mm + 50mm metal deck | 2 | Model Group:BUITENRUIMTE helft dak:2972614
3148286 | 5e verdieping V |  |  | Model Group:luifel penthouse:3148164 | Pset_QuantityTakeOff - Reference: 23_3B_beton 170mm + 50mm metal deck; sets with these values: 2
2972432 | 5e verdieping V |  |  | Model Group:BUITENRUIMTE helft dak:2972437 | Pset_QuantityTakeOff - Reference: 23_3B_beton 170mm + 50mm metal deck; sets with these values: 2

# IfcSlab: Floor:23_3B_beton 370 mm, Floor:23_3B_beton 370 mm:3136033
In: 2e verdieping N
Type - PredefinedType: FLOOR
Material: beton
Pset_SlabCommon - PitchAngle: 0 deg; Reference: 23_3B_beton 370 mm; IsExternal: no; LoadBearing: no
Pset_ReinforcementBarPitchOfSlab - Reference: 23_3B_beton 370 mm; sets with these values: 2
CPset_Phasing - Renovation Phase: Nieuw
Material Properties - beton, ThermalConductivity: 2.3; beton, SpecificHeatCapacity: 1000 J/kg/K; beton, MassDensity: 2300 kg/m3; beton, Embodied Energy: 1.92 (MJ/kg); beton, Embodied Carbon: 0.198 (kgCO₂/kg); beton, Name: beton; beton, Participates in Collision Detection: yes

# IfcSlab: Floor:43_tegels 300x300 (3)
In: 5e verdieping V
Type - PredefinedType: FLOOR
Material: tegels_vloer 300x300
Pset_SlabCommon - PitchAngle: 0 deg; Reference: 43_tegels 300x300; IsExternal: no; LoadBearing: no
CPset_Phasing - Renovation Phase: Nieuw
Material Properties - tegels_vloer 300x300, ThermalConductivity: 2.3; tegels_vloer 300x300, SpecificHeatCapacity: 1000 J/kg/K; tegels_vloer 300x300, MassDensity: 2300 kg/m3; tegels_vloer 300x300, Embodied Energy: 1.92 (MJ/kg); tegels_vloer 300x300, Embodied Carbon: 0.198 (kgCO₂/kg); tegels_vloer 300x300, Name: tegels_vloer 300x300; tegels_vloer 300x300, Participates in Collision Detection: yes
Name (Floor:43_tegels 300x300:...) | Pset_QuantityTakeOff, Reference | Pset_QuantityTakeOff, sets with these values
2534765 | Pset_ReinforcementBarPitchOfSlab - Reference: 43_tegels 300x300; sets with these values: 2
2536087 | 43_tegels 300x300 | 2
2537167 | 43_tegels 300x300 | 2

# IfcSlab: Floor:43_wastafel_planchet (2)
In: 5e verdieping V
Type - PredefinedType: FLOOR
Material: wastafel planchet ntb
Material Properties - wastafel planchet ntb, ThermalConductivity: 2.3; wastafel planchet ntb, SpecificHeatCapacity: 1000 J/kg/K; wastafel planchet ntb, MassDensity: 2300 kg/m3; wastafel planchet ntb, Embodied Energy: 1.92 (MJ/kg); wastafel planchet ntb, Embodied Carbon: 0.198 (kgCO₂/kg); wastafel planchet ntb, Name: wastafel planchet ntb; wastafel planchet ntb, Participates in Collision Detection: yes
CPset_Phasing - Renovation Phase: Nieuw
Pset_SlabCommon - PitchAngle: 0 deg; Reference: 43_wastafel_planchet; IsExternal: no; LoadBearing: no
Name (Floor:43_wastafel_planchet:...)
2534790 | Pset_QuantityTakeOff - Reference: 43_wastafel_planchet; sets with these values: 2
2561090 | Pset_ReinforcementBarPitchOfSlab - Reference: 43_wastafel_planchet; sets with these values: 2

# IfcSlab: Gipsplaat 18, _Vloer-x
In: 1e verdieping N
Material: Gipsplaat
Pset_SlabCommon - FireRating: n.v.t.; IsExternal: no; LoadBearing: yes
CPset_Phasing - Renovation Phase: Nieuw
Material Properties - Gipsplaat, ThermalConductivity: 0.23; Gipsplaat, SpecificHeatCapacity: 840 J/kg/K; Gipsplaat, MassDensity: 800 kg/m3; Gipsplaat, Embodied Energy: 6.75 (MJ/kg); Gipsplaat, Embodied Carbon: 0.38 (kgCO₂/kg); Gipsplaat, Name: Gipsplaat; Gipsplaat, Participates in Collision Detection: yes

# IfcSlab: Hout - Multiplex 18, _Vloer-x
In: 1e verdieping N
Material: Hout - Multiplex
Pset_SlabCommon - FireRating: n.v.t.; IsExternal: no; LoadBearing: yes
CPset_Phasing - Renovation Phase: Nieuw
Material Properties - Hout - Multiplex, ThermalConductivity: 0.17; Hout - Multiplex, SpecificHeatCapacity: 1600 J/kg/K; Hout - Multiplex, MassDensity: 700 kg/m3; Hout - Multiplex, Embodied Energy: 15 (MJ/kg); Hout - Multiplex, Embodied Carbon: 0.77 (kgCO₂/kg); Hout - Multiplex, Name: Hout - Multiplex; Hout - Multiplex, Participates in Collision Detection: yes

# IfcSlab: IFC Building Material 164 (3)
Type - PredefinedType: ROOF
Material: IFC Building Material
CPset_Phasing - Renovation Phase: Nieuw
Pset_SlabCommon - PitchAngle: 0 deg; Reference: NLRS_27_RO_dakleer iso 164 2-2-160_gen; IsExternal: yes; LoadBearing: yes
Material Properties - IFC Building Material, ThermalConductivity: 2.3; IFC Building Material, SpecificHeatCapacity: 1000 J/kg/K; IFC Building Material, MassDensity: 2300 kg/m3; IFC Building Material, Embodied Energy: 1.92 (MJ/kg); IFC Building Material, Embodied Carbon: 0.198 (kgCO₂/kg); IFC Building Material, Name: IFC Building Material; IFC Building Material, Participates in Collision Detection: yes
Name (Basic Roof:NLRS_27_RO_dakleer iso 164 2-2-160_gen:...) | In | Pset_ReinforcementBarPitchOfSlab, Reference | Pset_ReinforcementBarPitchOfSlab, sets with these values
3101106 | 2e verdieping N | NLRS_27_RO_dakleer iso 164 2-2-160_gen | 2
2987001 | 2e verdieping N | NLRS_27_RO_dakleer iso 164 2-2-160_gen | 2
3110331 | 2e verdieping V | Pset_QuantityTakeOff - Reference: NLRS_27_RO_dakleer iso 164 2-2-160_gen; sets with these values: 2

# IfcSlab: IFC Building Material 204 (2)
In: 6e verdieping V
Type - PredefinedType: ROOF
Material: IFC Building Material
Pset_SlabCommon - PitchAngle: 0 deg; Reference: NLRS_27_RO_dakleer iso 204 2-2-200_gen; IsExternal: yes; LoadBearing: yes
Pset_ReinforcementBarPitchOfSlab - Reference: NLRS_27_RO_dakleer iso 204 2-2-200_gen; sets with these values: 2
CPset_Phasing - Renovation Phase: Nieuw
Material Properties - IFC Building Material, ThermalConductivity: 2.3; IFC Building Material, SpecificHeatCapacity: 1000 J/kg/K; IFC Building Material, MassDensity: 2300 kg/m3; IFC Building Material, Embodied Energy: 1.92 (MJ/kg); IFC Building Material, Embodied Carbon: 0.198 (kgCO₂/kg); IFC Building Material, Name: IFC Building Material; IFC Building Material, Participates in Collision Detection: yes

# IfcSlab: IFC Building Material 410, Basic Roof:27_3B_houten balklaag:2727762
In: 1e verdieping N
Type - PredefinedType: ROOF
Material: IFC Building Material
Pset_SlabCommon - PitchAngle: 0 deg; Reference: 27_3B_houten balklaag; IsExternal: yes; LoadBearing: yes
Pset_ReinforcementBarPitchOfSlab - Reference: 27_3B_houten balklaag; sets with these values: 2
CPset_Phasing - Renovation Phase: Nieuw
Material Properties - IFC Building Material, ThermalConductivity: 2.3; IFC Building Material, SpecificHeatCapacity: 1000 J/kg/K; IFC Building Material, MassDensity: 2300 kg/m3; IFC Building Material, Embodied Energy: 1.92 (MJ/kg); IFC Building Material, Embodied Carbon: 0.198 (kgCO₂/kg); IFC Building Material, Name: IFC Building Material; IFC Building Material, Participates in Collision Detection: yes

# IfcSlab: Isolatie platdak 154 (2)
In: 3e verdieping/dak N
CPset_Phasing - Renovation Phase: Nieuw
Pset_SlabCommon - FireRating: n.v.t.; IsExternal: no; LoadBearing: yes

# IfcSlab: Metaal - Staal C 40 (5)
Material: Metaal - Staal C
Pset_SlabCommon - FireRating: n.v.t.; IsExternal: no; LoadBearing: yes
Material Properties - Metaal - Staal C, ThermalConductivity: 52; Metaal - Staal C, SpecificHeatCapacity: 530 J/kg/K; Metaal - Staal C, MassDensity: 7950 kg/m3; Metaal - Staal C, Embodied Energy: 25 (MJ/kg); Metaal - Staal C, Embodied Carbon: 1.91 (kgCO₂/kg); Metaal - Staal C, Name: Metaal - Staal C; Metaal - Staal C, Participates in Collision Detection: yes
Name | In | Renovation Phase
3 x _Vloer-x | 1e verdieping N | Bestaand
_Vloer-x | 2e verdieping N | Nieuw
_Vloer-x | 2e verdieping N | Bestaand

# IfcSlab: Platdak 125, _Vloer-x
In: 3e verdieping/dak N
Pset_SlabCommon - FireRating: n.v.t.; IsExternal: no; LoadBearing: yes
CPset_Phasing - Renovation Phase: Nieuw

# IfcSlab: Vloeropzand+dv iso 350, _Vloer-x
In: Begane grond N
Pset_SlabCommon - FireRating: n.v.t.; IsExternal: no; LoadBearing: yes
CPset_Phasing - Renovation Phase: Nieuw

# IfcSlab: beton 200, Basic Roof:27_3B_beton 200mm:2973010
In: 5e verdieping V
Type - PredefinedType: ROOF
Material: beton
Pset_SlabCommon - PitchAngle: 0 deg; Reference: 27_3B_beton 200mm; IsExternal: yes; LoadBearing: yes
Pset_ReinforcementBarPitchOfSlab - Reference: 27_3B_beton 200mm; sets with these values: 2
CPset_Phasing - Renovation Phase: Nieuw
Material Properties - beton, ThermalConductivity: 2.3; beton, SpecificHeatCapacity: 1000 J/kg/K; beton, MassDensity: 2300 kg/m3; beton, Embodied Energy: 1.92 (MJ/kg); beton, Embodied Carbon: 0.198 (kgCO₂/kg); beton, Name: beton; beton, Participates in Collision Detection: yes

# IfcSlab: beton 300 (3)
Type - PredefinedType: ROOF
Material: beton
Pset_SlabCommon - PitchAngle: 0 deg; Reference: 27_3B_beton 300mm; IsExternal: yes; LoadBearing: yes
CPset_Phasing - Renovation Phase: Nieuw
Material Properties - beton, ThermalConductivity: 2.3; beton, SpecificHeatCapacity: 1000 J/kg/K; beton, MassDensity: 2300 kg/m3; beton, Embodied Energy: 1.92 (MJ/kg); beton, Embodied Carbon: 0.198 (kgCO₂/kg); beton, Name: beton; beton, Participates in Collision Detection: yes
Name (Basic Roof:27_3B_beton 300mm:...) | In | Pset_ReinforcementBarPitchOfSlab, Reference | Pset_ReinforcementBarPitchOfSlab, sets with these values
3106531 | 2e verdieping N | 27_3B_beton 300mm | 2
3106520 | 2e verdieping N | Pset_QuantityTakeOff - Reference: 27_3B_beton 300mm; sets with these values: 2
2092854 | 6e verdieping V | 27_3B_beton 300mm | 2

# IfcSlab: plateau 180 mm 180, _Vloer-x
In: Begane grond N
Material: ALG - CONSTRUCTIEF VLOER
Pset_SlabCommon - FireRating: n.v.t.; IsExternal: no; LoadBearing: yes
CPset_Phasing - Renovation Phase: Bestaand
Material Properties - ALG - CONSTRUCTIEF VLOER, ThermalConductivity: 2.5; ALG - CONSTRUCTIEF VLOER, SpecificHeatCapacity: 1000 J/kg/K; ALG - CONSTRUCTIEF VLOER, MassDensity: 2400 kg/m3; ALG - CONSTRUCTIEF VLOER, Embodied Energy: 2.33 (MJ/kg); ALG - CONSTRUCTIEF VLOER, Embodied Carbon: 0.242 (kgCO₂/kg); ALG - CONSTRUCTIEF VLOER, Name: ALG - CONSTRUCTIEF VLOER; ALG - CONSTRUCTIEF VLOER, Participates in Collision Detection: yes

# IfcStair (17)
Pset_StairCommon - FireRating: n.v.t.; IsExternal: no
Name | In | Renovation Phase
7 x _Trap-x | Begane grond N | Bestaand
2 x _Trap-x | Begane grond N | Nieuw
4 x _Trap-x | 1e verdieping N | Bestaand
_Trap-x | 1e verdieping N | Nieuw
_Trap-x | 2e verdieping N | Bestaand
2 x _Trap-x | 2e verdieping V | Bestaand

# IfcStair: Precast Stair:24_trap - prefab (14)
Pset_StairCommon - IsExternal: no; Reference: 24_trap - prefab; NumberOfRiser: 15; NumberOfTreads: 15; RiserHeight: 184.667 mm; TreadLength: 240 mm
Pset_QuantityTakeOff - Reference: 24_trap - prefab
Name (Precast Stair:Stair:...) | In
2462826 | 1e verdieping N
2462867 | 1e verdieping N
2462854 | 1e verdieping N
2462839 | 1e verdieping N
2462895 | 2e verdieping N
2462882 | 2e verdieping N
2462923 | 2e verdieping V
2462910 | 2e verdieping V
2462951 | 3e verdieping/dak N
2462938 | 3e verdieping/dak N
2462979 | 3e verdieping V
2462966 | 3e verdieping V
2014475 | 4e verdieping V
2462802 | 4e verdieping V

# IfcStairFlight: IfcStairFlight (11)
Material: Beton C
Material Properties - Beton C, ThermalConductivity: 2; Beton C, SpecificHeatCapacity: 840 J/kg/K; Beton C, MassDensity: 2400 kg/m3; Beton C, Embodied Energy: 0.75 (MJ/kg); Beton C, Embodied Carbon: 0.1 (kgCO₂/kg); Beton C, Name: Beton C; Beton C, Participates in Collision Detection: yes
Name | In | Renovation Phase
5 x _Trapsegment-x | Begane grond N | Bestaand
_Trapsegment-x | Begane grond N | Nieuw
2 x _Trapsegment-x | 1e verdieping N | Bestaand
_Trapsegment-x | 2e verdieping N | Bestaand
2 x _Trapsegment-x | 2e verdieping V | Bestaand

# IfcStairFlight: Monolithic Run:prefab trap (14)
Type - PredefinedType: STRAIGHT
RiserHeight: 0.605862 mm; TreadLength: 0.787402 mm; Material: beton
Pset_StairFlightCommon - Reference: prefab trap; NosingLength: 0 mm; NumberOfRiser: 15; NumberOfTreads: 15; RiserHeight: 184.667 mm; TreadLength: 240 mm; WalkingLineOffset: 1.9685 mm; TreadLengthAtOffset: 240 mm; TreadLengthAtInnerSide: 240 mm
Pset_QuantityTakeOff - Reference: prefab trap
CPset_Phasing - Renovation Phase: Nieuw
Material Properties - beton, ThermalConductivity: 2.3; beton, SpecificHeatCapacity: 1000 J/kg/K; beton, MassDensity: 2300 kg/m3; beton, Embodied Energy: 1.92 (MJ/kg); beton, Embodied Carbon: 0.198 (kgCO₂/kg); beton, Name: beton; beton, Participates in Collision Detection: yes
Name (Precast Stair:Stair:...) | In
2462839 Run 1 | 1e verdieping N
2462867 Run 1 | 1e verdieping N
2462854 Run 1 | 1e verdieping N
2462826 Run 1 | 1e verdieping N
2462882 Run 1 | 2e verdieping N
2462895 Run 1 | 2e verdieping N
2462923 Run 1 | 2e verdieping V
2462910 Run 1 | 2e verdieping V
2462938 Run 1 | 3e verdieping/dak N
2462951 Run 1 | 3e verdieping/dak N
2462979 Run 1 | 3e verdieping V
2462966 Run 1 | 3e verdieping V
2462802 Run 1 | 4e verdieping V
2014475 Run 1 | 4e verdieping V

# IfcTransportElement: KONE_Car:KONE_Car, KONE_Car:KONE_Car:2065074
In: 1e verdieping N
Type - PredefinedType: ELEVATOR
Material: IFC Building Material
Pset_TransportElementCommon - Reference: KONE_Car; sets with these values: 2
CPset_Phasing - Renovation Phase: Nieuw
Material Properties - IFC Building Material, ThermalConductivity: 2.3; IFC Building Material, SpecificHeatCapacity: 1000 J/kg/K; IFC Building Material, MassDensity: 2300 kg/m3; IFC Building Material, Embodied Energy: 1.92 (MJ/kg); IFC Building Material, Embodied Carbon: 0.198 (kgCO₂/kg); IFC Building Material, Name: IFC Building Material; IFC Building Material, Participates in Collision Detection: yes

# IfcTransportElement: KONE_Car_Door_2R_P12:KONE_Car_Door_2R_P12, KONE_Car_Door_2R_P12:KONE_Car_Door_2R_P12:2065075
In: 1e verdieping N
Type - PredefinedType: ELEVATOR
Material: Default
Pset_TransportElementCommon - Reference: KONE_Car_Door_2R_P12; sets with these values: 2
CPset_Phasing - Renovation Phase: Nieuw
Material Properties - Default, ThermalConductivity: 2.3; Default, SpecificHeatCapacity: 1000 J/kg/K; Default, MassDensity: 2300 kg/m3; Default, Embodied Energy: 1.92 (MJ/kg); Default, Embodied Carbon: 0.198 (kgCO₂/kg); Default, Name: Default; Default, Participates in Collision Detection: yes

# IfcTransportElement: KONE_LDO_Design_2R_P19:KONE_LDO_Design_2R_P19 (6)
Type - PredefinedType: ELEVATOR
Material: IFC Building Material
CPset_Phasing - Renovation Phase: Nieuw
Material Properties - IFC Building Material, ThermalConductivity: 2.3; IFC Building Material, SpecificHeatCapacity: 1000 J/kg/K; IFC Building Material, MassDensity: 2300 kg/m3; IFC Building Material, Embodied Energy: 1.92 (MJ/kg); IFC Building Material, Embodied Carbon: 0.198 (kgCO₂/kg); IFC Building Material, Name: IFC Building Material; IFC Building Material, Participates in Collision Detection: yes
Name (KONE_LDO_Design_2R_P19:KONE_LDO_Design_2R_P19:...) | In
2065076 | 1e verdieping N | Pset_TransportElementCommon - Reference: KONE_LDO_Design_2R_P19; sets with these values: 2
2065077 | 2e verdieping V | Pset_QuantityTakeOff - Reference: KONE_LDO_Design_2R_P19; sets with these values: 2
2065078 | 3e verdieping/dak N | Pset_TransportElementCommon - Reference: KONE_LDO_Design_2R_P19; sets with these values: 2
2065079 | 3e verdieping V | Pset_TransportElementCommon - Reference: KONE_LDO_Design_2R_P19; sets with these values: 2
2065080 | 4e verdieping V | Pset_QuantityTakeOff - Reference: KONE_LDO_Design_2R_P19; sets with these values: 2
2089571 | 5e verdieping V | Pset_QuantityTakeOff - Reference: KONE_LDO_Design_2R_P19; sets with these values: 2

# IfcWall: ALG - ALGEMEEN 150, _Wand-x
In: 2e verdieping V
Material: ALG - ALGEMEEN
CPset_Phasing - Renovation Phase: Nieuw
Pset_WallCommon - FireRating: n.v.t.; SurfaceSpreadOfFlame: n.v.t.; IsExternal: yes; LoadBearing: yes
Material Properties - ALG - ALGEMEEN, ThermalConductivity: 0.27; ALG - ALGEMEEN, SpecificHeatCapacity: 840 J/kg/K; ALG - ALGEMEEN, MassDensity: 800 kg/m3; ALG - ALGEMEEN, Embodied Energy: 2 (MJ/kg); ALG - ALGEMEEN, Embodied Carbon: 0.13 (kgCO₂/kg); ALG - ALGEMEEN, Name: ALG - ALGEMEEN; ALG - ALGEMEEN, Participates in Collision Detection: yes

# IfcWall: ALG - ALGEMEEN 330 (8)
In: 3e verdieping/dak N
Material: ALG - ALGEMEEN
CPset_Phasing - Renovation Phase: Bestaand
Pset_WallCommon - FireRating: n.v.t.; SurfaceSpreadOfFlame: n.v.t.; IsExternal: yes; LoadBearing: yes
Material Properties - ALG - ALGEMEEN, ThermalConductivity: 0.27; ALG - ALGEMEEN, SpecificHeatCapacity: 840 J/kg/K; ALG - ALGEMEEN, MassDensity: 800 kg/m3; ALG - ALGEMEEN, Embodied Energy: 2 (MJ/kg); ALG - ALGEMEEN, Embodied Carbon: 0.13 (kgCO₂/kg); ALG - ALGEMEEN, Name: ALG - ALGEMEEN; ALG - ALGEMEEN, Participates in Collision Detection: yes

# IfcWall: ALG - BINNENBLAD 200, _Wand-x
In: 3e verdieping/dak N
Material: ALG - BINNENBLAD
Pset_WallCommon - FireRating: n.v.t.; SurfaceSpreadOfFlame: n.v.t.; IsExternal: yes; LoadBearing: yes
Material Properties - ALG - BINNENBLAD, ThermalConductivity: 0.9; ALG - BINNENBLAD, SpecificHeatCapacity: 840 J/kg/K; ALG - BINNENBLAD, MassDensity: 1900 kg/m3; ALG - BINNENBLAD, Embodied Energy: 0.75 (MJ/kg); ALG - BINNENBLAD, Embodied Carbon: 0.1 (kgCO₂/kg); ALG - BINNENBLAD, Name: ALG - BINNENBLAD; ALG - BINNENBLAD, Participates in Collision Detection: yes
CPset_Phasing - Renovation Phase: Bestaand

# IfcWall: ALG - BUITENAFWERKING 130 (2)
In: 3e verdieping/dak N
Material: ALG - BUITENAFWERKING
Pset_WallCommon - FireRating: n.v.t.; SurfaceSpreadOfFlame: n.v.t.; IsExternal: yes; LoadBearing: yes
CPset_Phasing - Renovation Phase: Bestaand
Material Properties - ALG - BUITENAFWERKING, ThermalConductivity: 1.5; ALG - BUITENAFWERKING, SpecificHeatCapacity: 840 J/kg/K; ALG - BUITENAFWERKING, MassDensity: 1900 kg/m3; ALG - BUITENAFWERKING, Embodied Energy: 4.51 (MJ/kg); ALG - BUITENAFWERKING, Embodied Carbon: 0.73 (kgCO₂/kg); ALG - BUITENAFWERKING, Name: ALG - BUITENAFWERKING; ALG - BUITENAFWERKING, Participates in Collision Detection: yes

# IfcWall: ALG - BUITENAFWERKING 140 (3)
In: 3e verdieping/dak N
Material: ALG - BUITENAFWERKING
Pset_WallCommon - FireRating: n.v.t.; SurfaceSpreadOfFlame: n.v.t.; IsExternal: yes; LoadBearing: yes
CPset_Phasing - Renovation Phase: Nieuw
Material Properties - ALG - BUITENAFWERKING, ThermalConductivity: 1.5; ALG - BUITENAFWERKING, SpecificHeatCapacity: 840 J/kg/K; ALG - BUITENAFWERKING, MassDensity: 1900 kg/m3; ALG - BUITENAFWERKING, Embodied Energy: 4.51 (MJ/kg); ALG - BUITENAFWERKING, Embodied Carbon: 0.73 (kgCO₂/kg); ALG - BUITENAFWERKING, Name: ALG - BUITENAFWERKING; ALG - BUITENAFWERKING, Participates in Collision Detection: yes

# IfcWall: ALG - BUITENAFWERKING 230 (8)
In: 3e verdieping/dak N
Material: ALG - BUITENAFWERKING
Pset_WallCommon - FireRating: n.v.t.; SurfaceSpreadOfFlame: n.v.t.; IsExternal: yes; LoadBearing: yes
CPset_Phasing - Renovation Phase: Bestaand
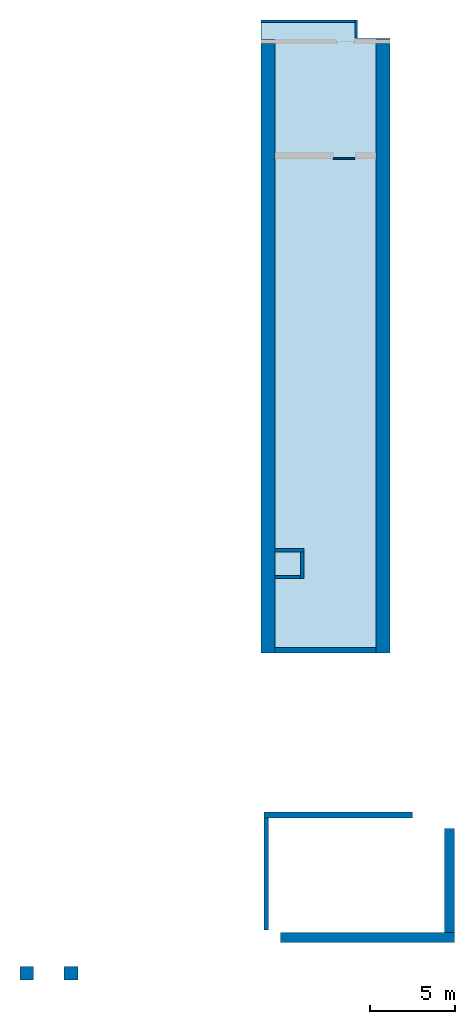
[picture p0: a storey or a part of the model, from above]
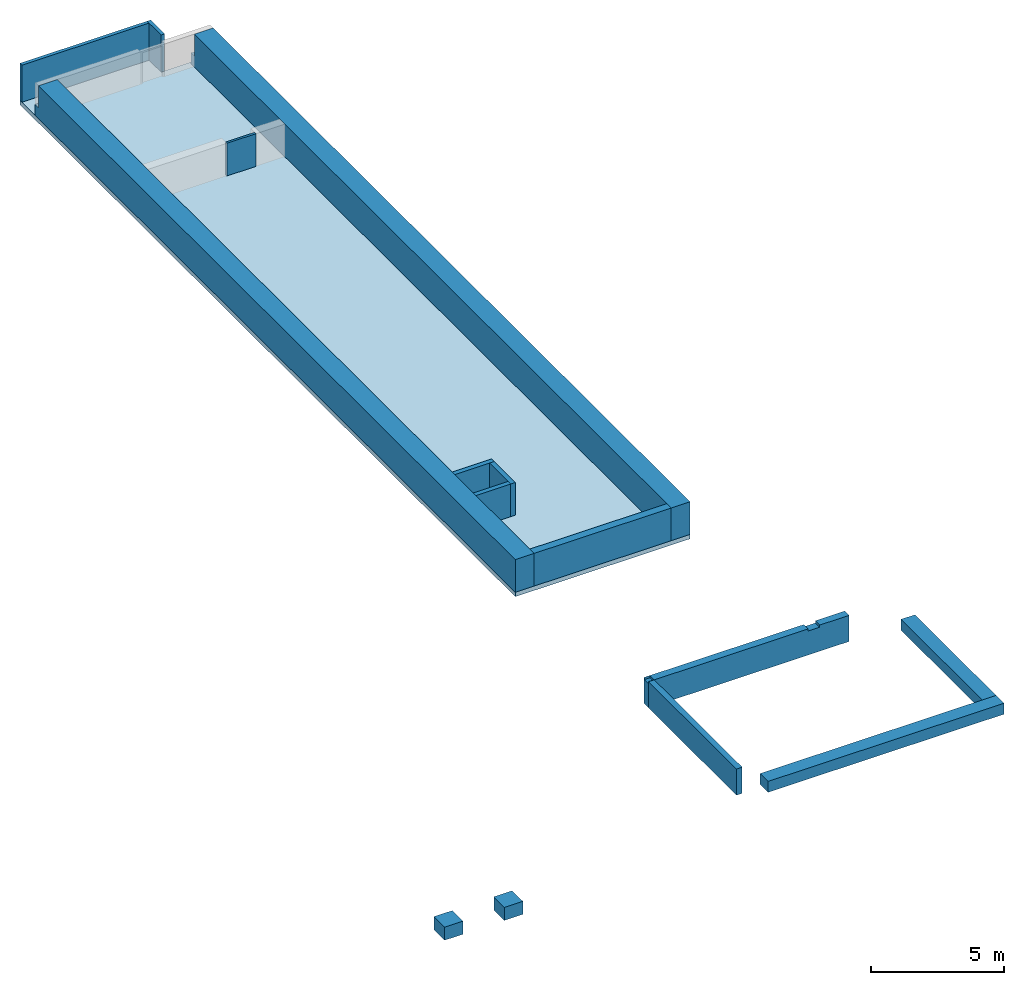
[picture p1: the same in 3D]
Properties of the parts of a building model (IFC2X3), part 6 of 7

# IfcWall: ALG - BUITENAFWERKING 230 (8)
Material Properties - ALG - BUITENAFWERKING, ThermalConductivity: 1.5; ALG - BUITENAFWERKING, SpecificHeatCapacity: 840 J/kg/K; ALG - BUITENAFWERKING, MassDensity: 1900 kg/m3; ALG - BUITENAFWERKING, Embodied Energy: 4.51 (MJ/kg); ALG - BUITENAFWERKING, Embodied Carbon: 0.73 (kgCO₂/kg); ALG - BUITENAFWERKING, Name: ALG - BUITENAFWERKING; ALG - BUITENAFWERKING, Participates in Collision Detection: yes

# IfcWall: ALG - BUITENAFWERKING 280 (2)
In: 3e verdieping/dak N
Material: ALG - BUITENAFWERKING
Pset_WallCommon - FireRating: n.v.t.; SurfaceSpreadOfFlame: n.v.t.; IsExternal: yes; LoadBearing: yes
CPset_Phasing - Renovation Phase: Bestaand
Material Properties - ALG - BUITENAFWERKING, ThermalConductivity: 1.5; ALG - BUITENAFWERKING, SpecificHeatCapacity: 840 J/kg/K; ALG - BUITENAFWERKING, MassDensity: 1900 kg/m3; ALG - BUITENAFWERKING, Embodied Energy: 4.51 (MJ/kg); ALG - BUITENAFWERKING, Embodied Carbon: 0.73 (kgCO₂/kg); ALG - BUITENAFWERKING, Name: ALG - BUITENAFWERKING; ALG - BUITENAFWERKING, Participates in Collision Detection: yes

# IfcWall: ALG - BUITENAFWERKING 360 (18)
In: 3e verdieping/dak N
Material: ALG - BUITENAFWERKING
Pset_WallCommon - FireRating: n.v.t.; SurfaceSpreadOfFlame: n.v.t.; IsExternal: yes; LoadBearing: yes
Material Properties - ALG - BUITENAFWERKING, ThermalConductivity: 1.5; ALG - BUITENAFWERKING, SpecificHeatCapacity: 840 J/kg/K; ALG - BUITENAFWERKING, MassDensity: 1900 kg/m3; ALG - BUITENAFWERKING, Embodied Energy: 4.51 (MJ/kg); ALG - BUITENAFWERKING, Embodied Carbon: 0.73 (kgCO₂/kg); ALG - BUITENAFWERKING, Name: ALG - BUITENAFWERKING; ALG - BUITENAFWERKING, Participates in Collision Detection: yes
Name | Renovation Phase
16 x _Wand-x | Bestaand
2 x _Wand-x | Nieuw

# IfcWall: ALG - BUITENAFWERKING 380, _Wand-x
In: 7e verdieping-dak V
Material: ALG - BUITENAFWERKING
CPset_Phasing - Renovation Phase: Bestaand
Material Properties - ALG - BUITENAFWERKING, ThermalConductivity: 1.5; ALG - BUITENAFWERKING, SpecificHeatCapacity: 840 J/kg/K; ALG - BUITENAFWERKING, MassDensity: 1900 kg/m3; ALG - BUITENAFWERKING, Embodied Energy: 4.51 (MJ/kg); ALG - BUITENAFWERKING, Embodied Carbon: 0.73 (kgCO₂/kg); ALG - BUITENAFWERKING, Name: ALG - BUITENAFWERKING; ALG - BUITENAFWERKING, Participates in Collision Detection: yes
Pset_WallCommon - FireRating: n.v.t.; SurfaceSpreadOfFlame: n.v.t.; IsExternal: yes; LoadBearing: yes

# IfcWall: ALG - CONSTRUCTIEF 100 (59)
Material: ALG - CONSTRUCTIEF
Pset_WallCommon - FireRating: n.v.t.; SurfaceSpreadOfFlame: n.v.t.; IsExternal: yes; LoadBearing: yes
Material Properties - ALG - CONSTRUCTIEF, ThermalConductivity: 2.3; ALG - CONSTRUCTIEF, SpecificHeatCapacity: 1000 J/kg/K; ALG - CONSTRUCTIEF, MassDensity: 2300 kg/m3; ALG - CONSTRUCTIEF, Embodied Energy: 1.92 (MJ/kg); ALG - CONSTRUCTIEF, Embodied Carbon: 0.198 (kgCO₂/kg); ALG - CONSTRUCTIEF, Name: ALG - CONSTRUCTIEF; ALG - CONSTRUCTIEF, Participates in Collision Detection: yes
Name | In | Renovation Phase
_Wand-x | Fundering N | Bestaand
8 x _Wand-x | Begane grond N | Bestaand
19 x _Wand-x | 1e verdieping N | Bestaand
11 x _Wand-x | 2e verdieping N | Bestaand
_Wand-x | 2e verdieping N | Nieuw
10 x _Wand-x | 2e verdieping V | Bestaand
3 x _Wand-x | 3e verdieping V | Bestaand
3 x _Wand-x | 4e verdieping V | Bestaand
3 x _Wand-x | 5e verdieping V | Bestaand

# IfcWall: ALG - CONSTRUCTIEF 145, _Wand-x
In: 7e verdieping-dak V
Material: ALG - CONSTRUCTIEF
Pset_WallCommon - FireRating: n.v.t.; SurfaceSpreadOfFlame: n.v.t.; IsExternal: yes; LoadBearing: yes
CPset_Phasing - Renovation Phase: Bestaand
Material Properties - ALG - CONSTRUCTIEF, ThermalConductivity: 2.3; ALG - CONSTRUCTIEF, SpecificHeatCapacity: 1000 J/kg/K; ALG - CONSTRUCTIEF, MassDensity: 2300 kg/m3; ALG - CONSTRUCTIEF, Embodied Energy: 1.92 (MJ/kg); ALG - CONSTRUCTIEF, Embodied Carbon: 0.198 (kgCO₂/kg); ALG - CONSTRUCTIEF, Name: ALG - CONSTRUCTIEF; ALG - CONSTRUCTIEF, Participates in Collision Detection: yes

# IfcWall: ALG - CONSTRUCTIEF 146 (51)
Material: ALG - CONSTRUCTIEF
Pset_WallCommon - FireRating: n.v.t.; SurfaceSpreadOfFlame: n.v.t.; IsExternal: yes; LoadBearing: yes
CPset_Phasing - Renovation Phase: Bestaand
Material Properties - ALG - CONSTRUCTIEF, ThermalConductivity: 2.3; ALG - CONSTRUCTIEF, SpecificHeatCapacity: 1000 J/kg/K; ALG - CONSTRUCTIEF, MassDensity: 2300 kg/m3; ALG - CONSTRUCTIEF, Embodied Energy: 1.92 (MJ/kg); ALG - CONSTRUCTIEF, Embodied Carbon: 0.198 (kgCO₂/kg); ALG - CONSTRUCTIEF, Name: ALG - CONSTRUCTIEF; ALG - CONSTRUCTIEF, Participates in Collision Detection: yes
Name | In
34 x _Wand-x | Begane grond N
13 x _Wand-x | 1e verdieping N
4 x _Wand-x | 2e verdieping V

# IfcWall: ALG - CONSTRUCTIEF 150 (66)
Material: ALG - CONSTRUCTIEF
Pset_WallCommon - FireRating: n.v.t.; SurfaceSpreadOfFlame: n.v.t.; IsExternal: yes; LoadBearing: yes
Material Properties - ALG - CONSTRUCTIEF, ThermalConductivity: 2.3; ALG - CONSTRUCTIEF, SpecificHeatCapacity: 1000 J/kg/K; ALG - CONSTRUCTIEF, MassDensity: 2300 kg/m3; ALG - CONSTRUCTIEF, Embodied Energy: 1.92 (MJ/kg); ALG - CONSTRUCTIEF, Embodied Carbon: 0.198 (kgCO₂/kg); ALG - CONSTRUCTIEF, Name: ALG - CONSTRUCTIEF; ALG - CONSTRUCTIEF, Participates in Collision Detection: yes
Name | In | Renovation Phase
2 x _Wand-x | Fundering N | Bestaand
25 x _Wand-x | Begane grond N | Bestaand
14 x _Wand-x | 1e verdieping N | Bestaand
14 x _Wand-x | 2e verdieping N | Bestaand
2 x _Wand-x | 2e verdieping V | Bestaand
_Wand-x | 3e verdieping/dak N | Nieuw
4 x _Wand-x | 4e verdieping V | Nieuw
4 x _Wand-x | 5e verdieping V | Nieuw

# IfcWall: ALG - CONSTRUCTIEF 165 (2)
In: 3e verdieping/dak N
Material: ALG - CONSTRUCTIEF
CPset_Phasing - Renovation Phase: Bestaand
Pset_WallCommon - FireRating: n.v.t.; SurfaceSpreadOfFlame: n.v.t.; IsExternal: yes; LoadBearing: yes
Material Properties - ALG - CONSTRUCTIEF, ThermalConductivity: 2.3; ALG - CONSTRUCTIEF, SpecificHeatCapacity: 1000 J/kg/K; ALG - CONSTRUCTIEF, MassDensity: 2300 kg/m3; ALG - CONSTRUCTIEF, Embodied Energy: 1.92 (MJ/kg); ALG - CONSTRUCTIEF, Embodied Carbon: 0.198 (kgCO₂/kg); ALG - CONSTRUCTIEF, Name: ALG - CONSTRUCTIEF; ALG - CONSTRUCTIEF, Participates in Collision Detection: yes

# IfcWall: ALG - CONSTRUCTIEF 200 (92)
Material: ALG - CONSTRUCTIEF
Pset_WallCommon - FireRating: n.v.t.; SurfaceSpreadOfFlame: n.v.t.; IsExternal: yes; LoadBearing: yes
CPset_Phasing - Renovation Phase: Bestaand
Material Properties - ALG - CONSTRUCTIEF, ThermalConductivity: 2.3; ALG - CONSTRUCTIEF, SpecificHeatCapacity: 1000 J/kg/K; ALG - CONSTRUCTIEF, MassDensity: 2300 kg/m3; ALG - CONSTRUCTIEF, Embodied Energy: 1.92 (MJ/kg); ALG - CONSTRUCTIEF, Embodied Carbon: 0.198 (kgCO₂/kg); ALG - CONSTRUCTIEF, Name: ALG - CONSTRUCTIEF; ALG - CONSTRUCTIEF, Participates in Collision Detection: yes
Name | In
3 x _Wand-x | Fundering N
16 x _Wand-x | Begane grond N
14 x _Wand-x | 1e verdieping N
11 x _Wand-x | 2e verdieping N
5 x _Wand-x | 2e verdieping V
16 x _Wand-x | 3e verdieping/dak N
9 x _Wand-x | 3e verdieping V
9 x _Wand-x | 4e verdieping V
9 x _Wand-x | 5e verdieping V

# IfcWall: ALG - CONSTRUCTIEF 240 (8)
Material: ALG - CONSTRUCTIEF
Pset_WallCommon - FireRating: n.v.t.; SurfaceSpreadOfFlame: n.v.t.; IsExternal: yes; LoadBearing: yes
CPset_Phasing - Renovation Phase: Bestaand
Material Properties - ALG - CONSTRUCTIEF, ThermalConductivity: 2.3; ALG - CONSTRUCTIEF, SpecificHeatCapacity: 1000 J/kg/K; ALG - CONSTRUCTIEF, MassDensity: 2300 kg/m3; ALG - CONSTRUCTIEF, Embodied Energy: 1.92 (MJ/kg); ALG - CONSTRUCTIEF, Embodied Carbon: 0.198 (kgCO₂/kg); ALG - CONSTRUCTIEF, Name: ALG - CONSTRUCTIEF; ALG - CONSTRUCTIEF, Participates in Collision Detection: yes
Name | In
_Wand-x | Fundering N
7 x _Wand-x | Begane grond N

# IfcWall: ALG - CONSTRUCTIEF 250 (129)
Material: ALG - CONSTRUCTIEF
Pset_WallCommon - FireRating: n.v.t.; SurfaceSpreadOfFlame: n.v.t.; IsExternal: yes; LoadBearing: yes
Material Properties - ALG - CONSTRUCTIEF, ThermalConductivity: 2.3; ALG - CONSTRUCTIEF, SpecificHeatCapacity: 1000 J/kg/K; ALG - CONSTRUCTIEF, MassDensity: 2300 kg/m3; ALG - CONSTRUCTIEF, Embodied Energy: 1.92 (MJ/kg); ALG - CONSTRUCTIEF, Embodied Carbon: 0.198 (kgCO₂/kg); ALG - CONSTRUCTIEF, Name: ALG - CONSTRUCTIEF; ALG - CONSTRUCTIEF, Participates in Collision Detection: yes
Name | In | Renovation Phase
_Wand-x | Fundering N | Bestaand
27 x _Wand-x | Begane grond N | Bestaand
17 x _Wand-x | 1e verdieping N | Bestaand
13 x _Wand-x | 2e verdieping N | Bestaand
6 x _Wand-x | 2e verdieping V | Bestaand
14 x _Wand-x | 3e verdieping/dak N | Bestaand
10 x _Wand-x | 3e verdieping V | Bestaand
18 x _Wand-x | 4e verdieping V | Bestaand
4 x _Wand-x | 4e verdieping V | Nieuw
13 x _Wand-x | 5e verdieping V | Bestaand
4 x _Wand-x | 5e verdieping V | Nieuw
2 x _Wand-x | 6e verdieping V | Bestaand

# IfcWall: ALG - CONSTRUCTIEF 260 (94)
Material: ALG - CONSTRUCTIEF
Pset_WallCommon - FireRating: n.v.t.; SurfaceSpreadOfFlame: n.v.t.; IsExternal: yes; LoadBearing: yes
CPset_Phasing - Renovation Phase: Bestaand
Material Properties - ALG - CONSTRUCTIEF, ThermalConductivity: 2.3; ALG - CONSTRUCTIEF, SpecificHeatCapacity: 1000 J/kg/K; ALG - CONSTRUCTIEF, MassDensity: 2300 kg/m3; ALG - CONSTRUCTIEF, Embodied Energy: 1.92 (MJ/kg); ALG - CONSTRUCTIEF, Embodied Carbon: 0.198 (kgCO₂/kg); ALG - CONSTRUCTIEF, Name: ALG - CONSTRUCTIEF; ALG - CONSTRUCTIEF, Participates in Collision Detection: yes
Name | In
_Wand-x | 1e verdieping N
2 x _Wand-x | 2e verdieping N
34 x _Wand-x | 2e verdieping V
19 x _Wand-x | 3e verdieping V
19 x _Wand-x | 4e verdieping V
19 x _Wand-x | 5e verdieping V

# IfcWall: ALG - CONSTRUCTIEF 280 (2)
In: 6e verdieping V
Material: ALG - CONSTRUCTIEF
Pset_WallCommon - FireRating: n.v.t.; SurfaceSpreadOfFlame: n.v.t.; IsExternal: yes; LoadBearing: yes
CPset_Phasing - Renovation Phase: Bestaand
Material Properties - ALG - CONSTRUCTIEF, ThermalConductivity: 2.3; ALG - CONSTRUCTIEF, SpecificHeatCapacity: 1000 J/kg/K; ALG - CONSTRUCTIEF, MassDensity: 2300 kg/m3; ALG - CONSTRUCTIEF, Embodied Energy: 1.92 (MJ/kg); ALG - CONSTRUCTIEF, Embodied Carbon: 0.198 (kgCO₂/kg); ALG - CONSTRUCTIEF, Name: ALG - CONSTRUCTIEF; ALG - CONSTRUCTIEF, Participates in Collision Detection: yes

# IfcWall: ALG - CONSTRUCTIEF 310, _Wand-x
In: Begane grond N
Material: ALG - CONSTRUCTIEF
CPset_Phasing - Renovation Phase: Bestaand
Pset_WallCommon - FireRating: n.v.t.; SurfaceSpreadOfFlame: n.v.t.; IsExternal: yes; LoadBearing: yes
Material Properties - ALG - CONSTRUCTIEF, ThermalConductivity: 2.3; ALG - CONSTRUCTIEF, SpecificHeatCapacity: 1000 J/kg/K; ALG - CONSTRUCTIEF, MassDensity: 2300 kg/m3; ALG - CONSTRUCTIEF, Embodied Energy: 1.92 (MJ/kg); ALG - CONSTRUCTIEF, Embodied Carbon: 0.198 (kgCO₂/kg); ALG - CONSTRUCTIEF, Name: ALG - CONSTRUCTIEF; ALG - CONSTRUCTIEF, Participates in Collision Detection: yes

# IfcWall: ALG - CONSTRUCTIEF 325, _Wand-x
In: Begane grond N
Material: ALG - CONSTRUCTIEF
Pset_WallCommon - FireRating: n.v.t.; SurfaceSpreadOfFlame: n.v.t.; IsExternal: yes; LoadBearing: yes
Material Properties - ALG - CONSTRUCTIEF, ThermalConductivity: 2.3; ALG - CONSTRUCTIEF, SpecificHeatCapacity: 1000 J/kg/K; ALG - CONSTRUCTIEF, MassDensity: 2300 kg/m3; ALG - CONSTRUCTIEF, Embodied Energy: 1.92 (MJ/kg); ALG - CONSTRUCTIEF, Embodied Carbon: 0.198 (kgCO₂/kg); ALG - CONSTRUCTIEF, Name: ALG - CONSTRUCTIEF; ALG - CONSTRUCTIEF, Participates in Collision Detection: yes
CPset_Phasing - Renovation Phase: Bestaand

# IfcWall: ALG - CONSTRUCTIEF 330 (104)
Material: ALG - CONSTRUCTIEF
Pset_WallCommon - FireRating: n.v.t.; SurfaceSpreadOfFlame: n.v.t.; IsExternal: yes; LoadBearing: yes
Material Properties - ALG - CONSTRUCTIEF, ThermalConductivity: 2.3; ALG - CONSTRUCTIEF, SpecificHeatCapacity: 1000 J/kg/K; ALG - CONSTRUCTIEF, MassDensity: 2300 kg/m3; ALG - CONSTRUCTIEF, Embodied Energy: 1.92 (MJ/kg); ALG - CONSTRUCTIEF, Embodied Carbon: 0.198 (kgCO₂/kg); ALG - CONSTRUCTIEF, Name: ALG - CONSTRUCTIEF; ALG - CONSTRUCTIEF, Participates in Collision Detection: yes
Name | In | Renovation Phase
2 x _Wand-x | Fundering N | Bestaand
23 x _Wand-x | Begane grond N | Bestaand
27 x _Wand-x | 1e verdieping N | Bestaand
_Wand-x | 1e verdieping N | Nieuw
21 x _Wand-x | 2e verdieping N | Bestaand
5 x _Wand-x | 2e verdieping V | Bestaand
8 x _Wand-x | 3e verdieping/dak N | Bestaand
4 x _Wand-x | 3e verdieping V | Bestaand
4 x _Wand-x | 4e verdieping V | Bestaand
4 x _Wand-x | 5e verdieping V | Bestaand
4 x _Wand-x | 6e verdieping V | Bestaand
_Wand-x | 6e verdieping V | Nieuw

# IfcWall: ALG - CONSTRUCTIEF 35 (2)
In: 3e verdieping/dak N
Material: ALG - CONSTRUCTIEF
Pset_WallCommon - FireRating: n.v.t.; SurfaceSpreadOfFlame: n.v.t.; IsExternal: yes; LoadBearing: yes
CPset_Phasing - Renovation Phase: Nieuw
Material Properties - ALG - CONSTRUCTIEF, ThermalConductivity: 2.3; ALG - CONSTRUCTIEF, SpecificHeatCapacity: 1000 J/kg/K; ALG - CONSTRUCTIEF, MassDensity: 2300 kg/m3; ALG - CONSTRUCTIEF, Embodied Energy: 1.92 (MJ/kg); ALG - CONSTRUCTIEF, Embodied Carbon: 0.198 (kgCO₂/kg); ALG - CONSTRUCTIEF, Name: ALG - CONSTRUCTIEF; ALG - CONSTRUCTIEF, Participates in Collision Detection: yes

# IfcWall: ALG - CONSTRUCTIEF 350 (10)
Material: ALG - CONSTRUCTIEF
Pset_WallCommon - FireRating: n.v.t.; SurfaceSpreadOfFlame: n.v.t.; IsExternal: yes; LoadBearing: yes
CPset_Phasing - Renovation Phase: Bestaand
Material Properties - ALG - CONSTRUCTIEF, ThermalConductivity: 2.3; ALG - CONSTRUCTIEF, SpecificHeatCapacity: 1000 J/kg/K; ALG - CONSTRUCTIEF, MassDensity: 2300 kg/m3; ALG - CONSTRUCTIEF, Embodied Energy: 1.92 (MJ/kg); ALG - CONSTRUCTIEF, Embodied Carbon: 0.198 (kgCO₂/kg); ALG - CONSTRUCTIEF, Name: ALG - CONSTRUCTIEF; ALG - CONSTRUCTIEF, Participates in Collision Detection: yes
Name | In
2 x _Wand-x | Begane grond N
_Wand-x | 1e verdieping N
3 x _Wand-x | 2e verdieping N
2 x _Wand-x | 2e verdieping V
_Wand-x | 6e verdieping V
_Wand-x | 7e verdieping-dak V

# IfcWall: ALG - CONSTRUCTIEF 400 (22)
Material: ALG - CONSTRUCTIEF
Pset_WallCommon - FireRating: n.v.t.; SurfaceSpreadOfFlame: n.v.t.; IsExternal: yes; LoadBearing: yes
CPset_Phasing - Renovation Phase: Bestaand
Material Properties - ALG - CONSTRUCTIEF, ThermalConductivity: 2.3; ALG - CONSTRUCTIEF, SpecificHeatCapacity: 1000 J/kg/K; ALG - CONSTRUCTIEF, MassDensity: 2300 kg/m3; ALG - CONSTRUCTIEF, Embodied Energy: 1.92 (MJ/kg); ALG - CONSTRUCTIEF, Embodied Carbon: 0.198 (kgCO₂/kg); ALG - CONSTRUCTIEF, Name: ALG - CONSTRUCTIEF; ALG - CONSTRUCTIEF, Participates in Collision Detection: yes
Name | In
_Wand-x | Fundering N
10 x _Wand-x | Begane grond N
_Wand-x | 1e verdieping N
_Wand-x | 2e verdieping N
9 x _Wand-x | 2e verdieping V

# IfcWall: ALG - CONSTRUCTIEF 420 (2)
In: Begane grond N
Material: ALG - CONSTRUCTIEF
Pset_WallCommon - FireRating: n.v.t.; SurfaceSpreadOfFlame: n.v.t.; IsExternal: yes; LoadBearing: yes
CPset_Phasing - Renovation Phase: Bestaand
Material Properties - ALG - CONSTRUCTIEF, ThermalConductivity: 2.3; ALG - CONSTRUCTIEF, SpecificHeatCapacity: 1000 J/kg/K; ALG - CONSTRUCTIEF, MassDensity: 2300 kg/m3; ALG - CONSTRUCTIEF, Embodied Energy: 1.92 (MJ/kg); ALG - CONSTRUCTIEF, Embodied Carbon: 0.198 (kgCO₂/kg); ALG - CONSTRUCTIEF, Name: ALG - CONSTRUCTIEF; ALG - CONSTRUCTIEF, Participates in Collision Detection: yes

# IfcWall: ALG - CONSTRUCTIEF 820 (2)
In: Fundering N
Material: ALG - CONSTRUCTIEF
Pset_WallCommon - FireRating: n.v.t.; SurfaceSpreadOfFlame: n.v.t.; IsExternal: yes; LoadBearing: yes
CPset_Phasing - Renovation Phase: Bestaand
Material Properties - ALG - CONSTRUCTIEF, ThermalConductivity: 2.3; ALG - CONSTRUCTIEF, SpecificHeatCapacity: 1000 J/kg/K; ALG - CONSTRUCTIEF, MassDensity: 2300 kg/m3; ALG - CONSTRUCTIEF, Embodied Energy: 1.92 (MJ/kg); ALG - CONSTRUCTIEF, Embodied Carbon: 0.198 (kgCO₂/kg); ALG - CONSTRUCTIEF, Name: ALG - CONSTRUCTIEF; ALG - CONSTRUCTIEF, Participates in Collision Detection: yes

# IfcWall: ALG - GEVEL 110 (5)
In: 1e verdieping N
Material: ALG - GEVEL
Pset_WallCommon - FireRating: n.v.t.; SurfaceSpreadOfFlame: n.v.t.; IsExternal: yes; LoadBearing: yes
CPset_Phasing - Renovation Phase: Bestaand
Material Properties - ALG - GEVEL, ThermalConductivity: 0.9; ALG - GEVEL, SpecificHeatCapacity: 840 J/kg/K; ALG - GEVEL, MassDensity: 1600 kg/m3; ALG - GEVEL, Embodied Energy: 3 (MJ/kg); ALG - GEVEL, Embodied Carbon: 0.23 (kgCO₂/kg); ALG - GEVEL, Name: ALG - GEVEL; ALG - GEVEL, Participates in Collision Detection: yes

# IfcWall: ALG - GEVEL 260 (52)
Material: ALG - GEVEL
CPset_Phasing - Renovation Phase: Bestaand
Material Properties - ALG - GEVEL, ThermalConductivity: 0.9; ALG - GEVEL, SpecificHeatCapacity: 840 J/kg/K; ALG - GEVEL, MassDensity: 1600 kg/m3; ALG - GEVEL, Embodied Energy: 3 (MJ/kg); ALG - GEVEL, Embodied Carbon: 0.23 (kgCO₂/kg); ALG - GEVEL, Name: ALG - GEVEL; ALG - GEVEL, Participates in Collision Detection: yes
Pset_WallCommon - FireRating: n.v.t.; SurfaceSpreadOfFlame: n.v.t.; IsExternal: yes; LoadBearing: yes
Name | In
11 x _Wand-x | Begane grond N
21 x _Wand-x | 1e verdieping N
20 x _Wand-x | 2e verdieping N

# IfcWall: ALG - ONTWERPWAND 150, _Wand-x
In: Begane grond N
Material: ALG - ONTWERPWAND
Pset_WallCommon - FireRating: n.v.t.; SurfaceSpreadOfFlame: n.v.t.; IsExternal: yes; LoadBearing: yes
CPset_Phasing - Renovation Phase: Nieuw
Material Properties - ALG - ONTWERPWAND, ThermalConductivity: 2.3; ALG - ONTWERPWAND, SpecificHeatCapacity: 1000 J/kg/K; ALG - ONTWERPWAND, MassDensity: 2300 kg/m3; ALG - ONTWERPWAND, Embodied Energy: 1.92 (MJ/kg); ALG - ONTWERPWAND, Embodied Carbon: 0.198 (kgCO₂/kg); ALG - ONTWERPWAND, Name: ALG - ONTWERPWAND; ALG - ONTWERPWAND, Participates in Collision Detection: yes

# IfcWall: ALG - ONTWERPWAND 50 (8)
Material: ALG - ONTWERPWAND
Pset_WallCommon - FireRating: n.v.t.; SurfaceSpreadOfFlame: n.v.t.; IsExternal: yes; LoadBearing: yes
CPset_Phasing - Renovation Phase: Nieuw
Material Properties - ALG - ONTWERPWAND, ThermalConductivity: 2.3; ALG - ONTWERPWAND, SpecificHeatCapacity: 1000 J/kg/K; ALG - ONTWERPWAND, MassDensity: 2300 kg/m3; ALG - ONTWERPWAND, Embodied Energy: 1.92 (MJ/kg); ALG - ONTWERPWAND, Embodied Carbon: 0.198 (kgCO₂/kg); ALG - ONTWERPWAND, Name: ALG - ONTWERPWAND; ALG - ONTWERPWAND, Participates in Collision Detection: yes
Name | In
4 x _Wand-x | Begane grond N
4 x _Wand-x | 1e verdieping N

# IfcWall: Basic Wall:21_WA_gevel V iso stuc systeem Nieuwe dakrand - 410mm (3)
In: 5e verdieping V
Type - PredefinedType: STANDARD
Pset_WallCommon - ExtendToStructure: no; Reference: 21_WA_gevel V iso stuc systeem Nieuwe dakrand - 410mm; IsExternal: yes; LoadBearing: no
Pset_ReinforcementBarPitchOfWall - Reference: 21_WA_gevel V iso stuc systeem Nieuwe dakrand - 410mm; sets with these values: 2
CPset_Phasing - Renovation Phase: Nieuw
Name (Basic Wall:21_WA_gevel V iso stuc systeem Nieuwe dakrand - 410mm:...)
2753305
2766943
2754110

# IfcWall: Basic Wall:21_WA_gevel V plaat tussen kozijnen op binnenblad - kozijnmaat (5)
In: 5e verdieping V
Type - PredefinedType: STANDARD
Pset_WallCommon - ExtendToStructure: no; Reference: 21_WA_gevel V plaat tussen kozijnen op binnenblad - kozijnmaat; IsExternal: yes; LoadBearing: no
CPset_Phasing - Renovation Phase: Nieuw
Name (Basic Wall:21_WA_gevel V plaat tussen kozijnen op binnenblad - kozijnmaat:...) | Pset_ReinforcementBarPitchOfWall, Reference | Pset_ReinforcementBarPitchOfWall, sets with these values
2657318 | 21_WA_gevel V plaat tussen kozijnen op binnenblad - kozijnmaat | 2
2558939 | Pset_QuantityTakeOff - Reference: 21_WA_gevel V plaat tussen kozijnen op binnenblad - kozijnmaat; sets with these values: 2
3093944 | 21_WA_gevel V plaat tussen kozijnen op binnenblad - kozijnmaat | 2
2667654 | 21_WA_gevel V plaat tussen kozijnen op binnenblad - kozijnmaat | 2
2667732 | 21_WA_gevel V plaat tussen kozijnen op binnenblad - kozijnmaat | 2

# IfcWall: Basic Wall:21_WA_gevel V spouwmuur, Basic Wall:21_WA_gevel V spouwmuur:3065812
In: 2e verdieping N
Type - PredefinedType: STANDARD
Pset_WallCommon - ExtendToStructure: no; Reference: 21_WA_gevel V spouwmuur; IsExternal: yes; LoadBearing: no
Pset_ReinforcementBarPitchOfWall - Reference: 21_WA_gevel V spouwmuur; sets with these values: 2
CPset_Phasing - Renovation Phase: Nieuw

# IfcWall: Basic Wall:31_WA_ALU_PANEEL (22)
In: 2e verdieping N
Type - PredefinedType: STANDARD
Pset_WallCommon - ExtendToStructure: no; Reference: 31_WA_ALU_PANEEL; IsExternal: yes; LoadBearing: no
CPset_Phasing - Renovation Phase: Nieuw
Name (Basic Wall:31_WA_ALU_PANEEL:...) | Pset_ReinforcementBarPitchOfWall, Reference | Pset_ReinforcementBarPitchOfWall, sets with these values
3107492 | 31_WA_ALU_PANEEL | 2
3101952 | 31_WA_ALU_PANEEL | 2
3107252 | Pset_QuantityTakeOff - Reference: 31_WA_ALU_PANEEL; sets with these values: 2
3108856 | Pset_QuantityTakeOff - Reference: 31_WA_ALU_PANEEL; sets with these values: 2
3108857 | Pset_QuantityTakeOff - Reference: 31_WA_ALU_PANEEL; sets with these values: 2
3108812 | 31_WA_ALU_PANEEL | 2
3108708 | 31_WA_ALU_PANEEL | 2
3096276 | 31_WA_ALU_PANEEL | 2
3108855 | 31_WA_ALU_PANEEL | 2
3108854 | 31_WA_ALU_PANEEL | 2
3108353 | Pset_QuantityTakeOff - Reference: 31_WA_ALU_PANEEL; sets with these values: 2
3108786 | 31_WA_ALU_PANEEL | 2
3110108 | 31_WA_ALU_PANEEL | 2
2974202 | 31_WA_ALU_PANEEL | 2
3102546 | Pset_QuantityTakeOff - Reference: 31_WA_ALU_PANEEL; sets with these values: 2
3168434 | 31_WA_ALU_PANEEL | 2
3168818 | 31_WA_ALU_PANEEL | 2
3168747 | Pset_QuantityTakeOff - Reference: 31_WA_ALU_PANEEL; sets with these values: 2
3168573 | 31_WA_ALU_PANEEL | 2
3027881 | Pset_QuantityTakeOff - Reference: 31_WA_ALU_PANEEL; sets with these values: 2
3105634 | 31_WA_ALU_PANEEL | 2 | Material: IFC Building Material; Material Properties - IFC Building Material, ThermalConductivity: 2.3; IFC Building Material, SpecificHeatCapacity: 1000 J/kg/K; IFC Building Material, MassDensity: 2300 kg/m3; IFC Building Material, Embodied Energy: 1.92 (MJ/kg); IFC Building Material, Embodied Carbon: 0.198 (kgCO₂/kg); IFC Building Material, Name: IFC Building Material; IFC Building Material, Participates in Collision Detection: yes
3110240 | 31_WA_ALU_PANEEL | 2 | Material: IFC Building Material; Material Properties - IFC Building Material, ThermalConductivity: 2.3; IFC Building Material, SpecificHeatCapacity: 1000 J/kg/K; IFC Building Material, MassDensity: 2300 kg/m3; IFC Building Material, Embodied Energy: 1.92 (MJ/kg); IFC Building Material, Embodied Carbon: 0.198 (kgCO₂/kg); IFC Building Material, Name: IFC Building Material; IFC Building Material, Participates in Collision Detection: yes

# IfcWall: Basic Wall:34_WA_hard glazen balustrade (16)
Type - PredefinedType: STANDARD
Material: glas gehard
Pset_WallCommon - ExtendToStructure: no; Reference: 34_WA_hard glazen balustrade; IsExternal: yes; LoadBearing: no
CPset_Phasing - Renovation Phase: Nieuw
Material Properties - glas gehard, ThermalConductivity: 2.3; glas gehard, SpecificHeatCapacity: 1000 J/kg/K; glas gehard, MassDensity: 2300 kg/m3; glas gehard, Embodied Energy: 1.92 (MJ/kg); glas gehard, Embodied Carbon: 0.198 (kgCO₂/kg); glas gehard, Name: glas gehard; glas gehard, Participates in Collision Detection: yes
Name (Basic Wall:34_WA_hard glazen balustrade:...) | In | Pset_ReinforcementBarPitchOfWall, Reference | Pset_ReinforcementBarPitchOfWall, sets with these values | Group
2972476 | 2e verdieping V | 34_WA_hard glazen balustrade | 2 | Model Group:BUITENRUIMTE helft:2972320
2972479 | 2e verdieping V | 34_WA_hard glazen balustrade | 2 | Model Group:BUITENRUIMTE helft:2972347
2972477 | 2e verdieping V |  |  | Model Group:BUITENRUIMTE helft:2972320 | Pset_QuantityTakeOff - Reference: 34_WA_hard glazen balustrade; sets with these values: 2
2972478 | 2e verdieping V |  |  | Model Group:BUITENRUIMTE helft:2972347 | Pset_QuantityTakeOff - Reference: 34_WA_hard glazen balustrade; sets with these values: 2
2972470 | 3e verdieping/dak N | 34_WA_hard glazen balustrade | 2 | Model Group:BUITENRUIMTE helft:2972046
2972468 | 3e verdieping/dak N | 34_WA_hard glazen balustrade | 2 | Model Group:BUITENRUIMTE helft:2972019
2972471 | 3e verdieping/dak N | 34_WA_hard glazen balustrade | 2 | Model Group:BUITENRUIMTE helft:2972046
2972469 | 3e verdieping/dak N | 34_WA_hard glazen balustrade | 2 | Model Group:BUITENRUIMTE helft:2972019
2972472 | 3e verdieping V | 34_WA_hard glazen balustrade | 2 | Model Group:BUITENRUIMTE helft:2972073
2972474 | 3e verdieping V | 34_WA_hard glazen balustrade | 2 | Model Group:BUITENRUIMTE helft:2972100
2972475 | 3e verdieping V |  |  | Model Group:BUITENRUIMTE helft:2972100 | Pset_QuantityTakeOff - Reference: 34_WA_hard glazen balustrade; sets with these values: 2
2972473 | 3e verdieping V |  |  | Model Group:BUITENRUIMTE helft:2972073 | Pset_QuantityTakeOff - Reference: 34_WA_hard glazen balustrade; sets with these values: 2
2972467 | 4e verdieping V | 34_WA_hard glazen balustrade | 2 | Model Group:BUITENRUIMTE helft:2971992
2972465 | 4e verdieping V | 34_WA_hard glazen balustrade | 2 | Model Group:BUITENRUIMTE helft:2971965
2972464 | 4e verdieping V | 34_WA_hard glazen balustrade | 2 | Model Group:BUITENRUIMTE helft:2971965
2972466 | 4e verdieping V |  |  | Model Group:BUITENRUIMTE helft:2971992 | Pset_QuantityTakeOff - Reference: 34_WA_hard glazen balustrade; sets with these values: 2

# IfcWall: Basic Wall:41_WA_houten delen vert HSB, Basic Wall:41_WA_houten delen vert HSB:2973857
In: 2e verdieping N
Type - PredefinedType: STANDARD
Pset_WallCommon - ExtendToStructure: no; Reference: 41_WA_houten delen vert HSB; IsExternal: no; LoadBearing: no
Pset_ReinforcementBarPitchOfWall - Reference: 41_WA_houten delen vert HSB; sets with these values: 2
CPset_Phasing - Renovation Phase: Nieuw

# IfcWall: Basic Wall:41_WA_houten delen vert HSB 300 breed, Basic Wall:41_WA_houten delen vert HSB 300 breed:3137566
In: 2e verdieping N
Type - PredefinedType: STANDARD
Pset_ReinforcementBarPitchOfWall - Reference: 41_WA_houten delen vert HSB 300 breed; sets with these values: 2
Pset_WallCommon - ExtendToStructure: no; Reference: 41_WA_houten delen vert HSB 300 breed; IsExternal: no; LoadBearing: no
CPset_Phasing - Renovation Phase: Nieuw

# IfcWall: Basic Wall:41_WA_houten delen vert HSB 365 breed, Basic Wall:41_WA_houten delen vert HSB 365 breed:2974010
In: 2e verdieping N
Type - PredefinedType: STANDARD
Pset_QuantityTakeOff - Reference: 41_WA_houten delen vert HSB 365 breed; sets with these values: 2
Pset_WallCommon - ExtendToStructure: no; Reference: 41_WA_houten delen vert HSB 365 breed; IsExternal: no; LoadBearing: no
CPset_Phasing - Renovation Phase: Nieuw

# IfcWall: Basic Wall:41_WA_houten delen vert balkon/terras bij BT, Basic Wall:41_WA_houten delen vert balkon/terras bij BT:2658072
In: 5e verdieping V
Type - PredefinedType: STANDARD
Pset_WallCommon - ExtendToStructure: no; Reference: 41_WA_houten delen vert balkon/terras bij BT; IsExternal: no; LoadBearing: no
Pset_QuantityTakeOff - Reference: 41_WA_houten delen vert balkon/terras bij BT; sets with these values: 2
CPset_Phasing - Renovation Phase: Nieuw

# IfcWall: Basic Wall:41_WA_houten delen vert trappenhuis (7)
Type - PredefinedType: STANDARD
Pset_WallCommon - ExtendToStructure: no; Reference: 41_WA_houten delen vert trappenhuis; IsExternal: no; LoadBearing: no
CPset_Phasing - Renovation Phase: Nieuw
Name (Basic Wall:41_WA_houten delen vert trappenhuis:...) | In | Pset_ReinforcementBarPitchOfWall, Reference | Pset_ReinforcementBarPitchOfWall, sets with these values | Group
2039373 | 1e verdieping N | Pset_QuantityTakeOff - Reference: 41_WA_houten delen vert trappenhuis; sets with these values: 2
2039127 | 2e verdieping N | 41_WA_houten delen vert trappenhuis | 2
2013382 | 2e verdieping V | 41_WA_houten delen vert trappenhuis | 2 | Model Group:V vluchttrappenhuis 2:2013401
2013452 | 3e verdieping/dak N | 41_WA_houten delen vert trappenhuis | 2 | Model Group:V vluchttrappenhuis 2:2013471
2013649 | 3e verdieping V |  |  | Model Group:V vluchttrappenhuis 2:2013517 | Pset_QuantityTakeOff - Reference: 41_WA_houten delen vert trappenhuis; sets with these values: 2
3085514 | 4e verdieping V |  |  | Model Group:V vluchttrappenhuis 2:2013112 | Pset_QuantityTakeOff - Reference: 41_WA_houten delen vert trappenhuis; sets with these values: 2
3081074 | 5e verdieping V | 41_WA_houten delen vert trappenhuis | 2 | Model Group:V vluchttrappenhuis V5:3080963

# IfcWall: Basic Wall:41_WA_stucwerk op iso 100mm, Basic Wall:41_WA_stucwerk op iso 100mm:2110438
In: 2e verdieping N
Type - PredefinedType: STANDARD
Pset_WallCommon - ExtendToStructure: no; Reference: 41_WA_stucwerk op iso 100mm; IsExternal: yes; LoadBearing: no
Pset_QuantityTakeOff - Reference: 41_WA_stucwerk op iso 100mm; sets with these values: 2
CPset_Phasing - Renovation Phase: Nieuw

# IfcWall: Basic Wall:41_WA_stucwerk op iso 110mm (12)
Type - PredefinedType: STANDARD
CPset_Phasing - Renovation Phase: Nieuw
Pset_WallCommon - ExtendToStructure: no; Reference: 41_WA_stucwerk op iso 110mm; IsExternal: yes; LoadBearing: no
Name (Basic Wall:41_WA_stucwerk op iso 110mm:...) | In | Pset_ReinforcementBarPitchOfWall, Reference | Pset_ReinforcementBarPitchOfWall, sets with these values
2553194 | 5e verdieping V | Pset_QuantityTakeOff - Reference: 41_WA_stucwerk op iso 110mm; sets with these values: 2
2553193 | 5e verdieping V | 41_WA_stucwerk op iso 110mm | 2
2553192 | 5e verdieping V | 41_WA_stucwerk op iso 110mm | 2
2553028 | 5e verdieping V | Pset_QuantityTakeOff - Reference: 41_WA_stucwerk op iso 110mm; sets with these values: 2
2463189 | 5e verdieping V | Pset_QuantityTakeOff - Reference: 41_WA_stucwerk op iso 110mm; sets with these values: 2
2465533 | 5e verdieping V | Pset_QuantityTakeOff - Reference: 41_WA_stucwerk op iso 110mm; sets with these values: 2
2465232 | 5e verdieping V | 41_WA_stucwerk op iso 110mm | 2
3140915 | 5e verdieping V | 41_WA_stucwerk op iso 110mm | 2 | Group: Model Group:V vluchttrappenhuis V5:3080963
3090988 | 5e verdieping V | 41_WA_stucwerk op iso 110mm | 2 | Group: Model Group:V vluchttrappenhuis V5:3080963
2550517 | 6e verdieping V | 41_WA_stucwerk op iso 110mm | 2
2550574 | 6e verdieping V | 41_WA_stucwerk op iso 110mm | 2
2550433 | 6e verdieping V | 41_WA_stucwerk op iso 110mm | 2

# IfcWall: Basic Wall:41_WA_stucwerk op iso 170mm (37)
Type - PredefinedType: STANDARD
Pset_WallCommon - ExtendToStructure: no; Reference: 41_WA_stucwerk op iso 170mm; IsExternal: yes; LoadBearing: no
CPset_Phasing - Renovation Phase: Nieuw
Name (Basic Wall:41_WA_stucwerk op iso 170mm:...) | In | Pset_ReinforcementBarPitchOfWall, Reference | Pset_ReinforcementBarPitchOfWall, sets with these values | Group
2040042 | 1e verdieping N | Pset_QuantityTakeOff - Reference: 41_WA_stucwerk op iso 170mm; sets with these values: 2
2039126 | 1e verdieping N | 41_WA_stucwerk op iso 170mm | 2
2040043 | 1e verdieping N | 41_WA_stucwerk op iso 170mm | 2
2728386 | 1e verdieping N | 41_WA_stucwerk op iso 170mm | 2
2039351 | 1e verdieping N | 41_WA_stucwerk op iso 170mm | 2
2039353 | 1e verdieping N | 41_WA_stucwerk op iso 170mm | 2
2039372 | 1e verdieping N | 41_WA_stucwerk op iso 170mm | 2
2039106 | 1e verdieping N | 41_WA_stucwerk op iso 170mm | 2
3144202 | 1e verdieping N | 41_WA_stucwerk op iso 170mm | 2
2725946 | 1e verdieping N | Pset_QuantityTakeOff - Reference: 41_WA_stucwerk op iso 170mm; sets with these values: 2
2013361 | 2e verdieping N | 41_WA_stucwerk op iso 170mm | 2 | Model Group:V vluchttrappenhuis 2:2013401
2013360 | 2e verdieping N | 41_WA_stucwerk op iso 170mm | 2 | Model Group:V vluchttrappenhuis 2:2013401
2013381 | 2e verdieping N | 41_WA_stucwerk op iso 170mm | 2 | Model Group:V vluchttrappenhuis 2:2013401
2039105 | 2e verdieping N | Pset_QuantityTakeOff - Reference: 41_WA_stucwerk op iso 170mm; sets with these values: 2
2039107 | 2e verdieping N | Pset_QuantityTakeOff - Reference: 41_WA_stucwerk op iso 170mm; sets with these values: 2
2013430 | 2e verdieping V | 41_WA_stucwerk op iso 170mm | 2 | Model Group:V vluchttrappenhuis 2:2013471
2013451 | 2e verdieping V |  |  | Model Group:V vluchttrappenhuis 2:2013471 | Pset_QuantityTakeOff - Reference: 41_WA_stucwerk op iso 170mm; sets with these values: 2
2013431 | 2e verdieping V |  |  | Model Group:V vluchttrappenhuis 2:2013471 | Pset_QuantityTakeOff - Reference: 41_WA_stucwerk op iso 170mm; sets with these values: 2
2013362 | 2e verdieping V |  |  | Model Group:V vluchttrappenhuis 2:2013401 | Pset_QuantityTakeOff - Reference: 41_WA_stucwerk op iso 170mm; sets with these values: 2
2013432 | 3e verdieping/dak N | 41_WA_stucwerk op iso 170mm | 2 | Model Group:V vluchttrappenhuis 2:2013471
2013627 | 3e verdieping/dak N | 41_WA_stucwerk op iso 170mm | 2 | Model Group:V vluchttrappenhuis 2:2013517
2013648 | 3e verdieping/dak N | 41_WA_stucwerk op iso 170mm | 2 | Model Group:V vluchttrappenhuis 2:2013517
2013628 | 3e verdieping/dak N | 41_WA_stucwerk op iso 170mm | 2 | Model Group:V vluchttrappenhuis 2:2013517
3085495 | 3e verdieping V | 41_WA_stucwerk op iso 170mm | 2 | Model Group:V vluchttrappenhuis 2:2013112
3085513 | 3e verdieping V |  |  | Model Group:V vluchttrappenhuis 2:2013112 | Pset_QuantityTakeOff - Reference: 41_WA_stucwerk op iso 170mm; sets with these values: 2
2013629 | 3e verdieping V |  |  | Model Group:V vluchttrappenhuis 2:2013517 | Pset_QuantityTakeOff - Reference: 41_WA_stucwerk op iso 170mm; sets with these values: 2
3085496 | 3e verdieping V | 41_WA_stucwerk op iso 170mm | 2 | Model Group:V vluchttrappenhuis 2:2013112
3085497 | 4e verdieping V |  |  | Model Group:V vluchttrappenhuis 2:2013112 | Pset_QuantityTakeOff - Reference: 41_WA_stucwerk op iso 170mm; sets with these values: 2
2549414 | 5e verdieping V | 41_WA_stucwerk op iso 170mm | 2
2091743 | 5e verdieping V | 41_WA_stucwerk op iso 170mm | 2
3086327 | 5e verdieping V | 41_WA_stucwerk op iso 170mm | 2
3081057 | 5e verdieping V | 41_WA_stucwerk op iso 170mm | 2 | Model Group:V vluchttrappenhuis V5:3080963
2463730 | 5e verdieping V | 41_WA_stucwerk op iso 170mm | 2
3081055 | 5e verdieping V | 41_WA_stucwerk op iso 170mm | 2 | Model Group:V vluchttrappenhuis V5:3080963
3081073 | 5e verdieping V |  |  | Model Group:V vluchttrappenhuis V5:3080963 | Pset_QuantityTakeOff - Reference: 41_WA_stucwerk op iso 170mm; sets with these values: 2
3081056 | 5e verdieping V | 41_WA_stucwerk op iso 170mm | 2 | Model Group:V vluchttrappenhuis V5:3080963
2549112 | 6e verdieping V | Pset_QuantityTakeOff - Reference: 41_WA_stucwerk op iso 170mm; sets with these values: 2

# IfcWall: Basic Wall:41_WA_stucwerk op iso 70mm (4)
In: 5e verdieping V
Type - PredefinedType: STANDARD
Pset_WallCommon - ExtendToStructure: no; Reference: 41_WA_stucwerk op iso 70mm; IsExternal: yes; LoadBearing: no
CPset_Phasing - Renovation Phase: Nieuw
Name (Basic Wall:41_WA_stucwerk op iso 70mm:...) | Pset_ReinforcementBarPitchOfWall, Reference | Pset_ReinforcementBarPitchOfWall, sets with these values
2657196 | 41_WA_stucwerk op iso 70mm | 2
2557722 | Pset_QuantityTakeOff - Reference: 41_WA_stucwerk op iso 70mm; sets with these values: 2
3092958 | 41_WA_stucwerk op iso 70mm | 2
3093572 | 41_WA_stucwerk op iso 70mm | 2

# IfcWall: Basic Wall:GF 100/2.50.2.A (20)
In: 5e verdieping V
Type - PredefinedType: STANDARD
CPset_Phasing - Renovation Phase: Nieuw
Pset_WallCommon - ExtendToStructure: no; Reference: GF 100/2.50.2.A; IsExternal: no; LoadBearing: no
Name (Basic Wall:GF 100/2.50.2.A:...) | Pset_ReinforcementBarPitchOfWall, Reference | Pset_ReinforcementBarPitchOfWall, sets with these values
2478777 | GF 100/2.50.2.A | 2
2538369 | GF 100/2.50.2.A | 2
2479290 | GF 100/2.50.2.A | 2
2469198 | GF 100/2.50.2.A | 2
2468759 | GF 100/2.50.2.A | 2
2470084 | GF 100/2.50.2.A | 2
2469740 | GF 100/2.50.2.A | 2
2469857 | GF 100/2.50.2.A | 2
2478877 | GF 100/2.50.2.A | 2
2535657 | GF 100/2.50.2.A | 2
2538670 | GF 100/2.50.2.A | 2
2538327 | GF 100/2.50.2.A | 2
2478964 | GF 100/2.50.2.A | 2
2538624 | GF 100/2.50.2.A | 2
3206854 | GF 100/2.50.2.A | 2
2469299 | GF 100/2.50.2.A | 2
2469633 | GF 100/2.50.2.A | 2
2479038 | Pset_QuantityTakeOff - Reference: GF 100/2.50.2.A; sets with these values: 2
2479134 | GF 100/2.50.2.A | 2
2479236 | GF 100/2.50.2.A | 2

# IfcWall: Basic Wall:GF 205 ECO DGS/2.75*75.2.AA (5)
In: 5e verdieping V
Type - PredefinedType: STANDARD
Pset_WallCommon - ExtendToStructure: no; Reference: GF 205 ECO DGS/2.75*75.2.AA; IsExternal: no; LoadBearing: no
Pset_ReinforcementBarPitchOfWall - Reference: GF 205 ECO DGS/2.75*75.2.AA; sets with these values: 2
CPset_Phasing - Renovation Phase: Nieuw
Name (Basic Wall:GF 205 ECO DGS/2.75*75.2.AA:...)
2539458
2479533
2479587
2480143
2479836

# IfcWall: Basic Wall:GF 75/2.50 voorzetwand (3)
In: 5e verdieping V
Type - PredefinedType: STANDARD
CPset_Phasing - Renovation Phase: Nieuw
Pset_WallCommon - ExtendToStructure: no; Reference: GF 75/2.50 voorzetwand; IsExternal: no; LoadBearing: no
Name (Basic Wall:GF 75/2.50 voorzetwand:...) | Pset_ReinforcementBarPitchOfWall, Reference | Pset_ReinforcementBarPitchOfWall, sets with these values
2536184 | Pset_QuantityTakeOff - Reference: GF 75/2.50 voorzetwand; sets with these values: 2
2537172 | GF 75/2.50 voorzetwand | 2
2534762 | GF 75/2.50 voorzetwand | 2

# IfcWall: Basic Wall:NLRS_20_basis 200mm (4)
Type - PredefinedType: STANDARD
Material: Wall Basis
Pset_WallCommon - ExtendToStructure: no; Reference: NLRS_20_basis 200mm; IsExternal: yes; LoadBearing: no
CPset_Phasing - Renovation Phase: Nieuw
Material Properties - Wall Basis, ThermalConductivity: 2.3; Wall Basis, SpecificHeatCapacity: 1000 J/kg/K; Wall Basis, MassDensity: 2300 kg/m3; Wall Basis, Embodied Energy: 1.92 (MJ/kg); Wall Basis, Embodied Carbon: 0.198 (kgCO₂/kg); Wall Basis, Name: Wall Basis; Wall Basis, Participates in Collision Detection: yes
Name (Basic Wall:NLRS_20_basis 200mm:...) | In | Pset_ReinforcementBarPitchOfWall, Reference | Pset_ReinforcementBarPitchOfWall, sets with these values
2972652 | 2e verdieping V | NLRS_20_basis 200mm | 2
2972653 | 3e verdieping/dak N | NLRS_20_basis 200mm | 2
2973015 | 3e verdieping V | Pset_QuantityTakeOff - Reference: NLRS_20_basis 200mm; sets with these values: 2
2972463 | 4e verdieping V | NLRS_20_basis 200mm | 2

# IfcWall: Basic Wall:NLRS_20_bestaand 240mm, Basic Wall:NLRS_20_bestaand 240mm:876329
In: 2e verdieping N
Type - PredefinedType: STANDARD
Pset_WallCommon - ExtendToStructure: no; Reference: NLRS_20_bestaand 240mm; IsExternal: yes; LoadBearing: no
Pset_QuantityTakeOff - Reference: NLRS_20_bestaand 240mm; sets with these values: 2
CPset_Phasing - Renovation Phase: Nieuw

# IfcWall: Basic Wall:NLRS_20_bestaand 300mm, Basic Wall:NLRS_20_bestaand 300mm:881340
In: 2e verdieping N
Type - PredefinedType: STANDARD
Material: Bestaand metselwerk
Pset_WallCommon - ExtendToStructure: no; Reference: NLRS_20_bestaand 300mm; IsExternal: yes; LoadBearing: no
Pset_ReinforcementBarPitchOfWall - Reference: NLRS_20_bestaand 300mm; sets with these values: 2
CPset_Phasing - Renovation Phase: Nieuw
Material Properties - Bestaand metselwerk, ThermalConductivity: 2.3; Bestaand metselwerk, SpecificHeatCapacity: 1000 J/kg/K; Bestaand metselwerk, MassDensity: 2300 kg/m3; Bestaand metselwerk, Embodied Energy: 1.92 (MJ/kg); Bestaand metselwerk, Embodied Carbon: 0.198 (kgCO₂/kg); Bestaand metselwerk, Name: Bestaand metselwerk; Bestaand metselwerk, Participates in Collision Detection: yes

# IfcWall: Basic Wall:NLRS_21_basis 200mm (3)
In: 5e verdieping V
Type - PredefinedType: STANDARD
Material: Wall Basis
Pset_WallCommon - ExtendToStructure: no; Reference: NLRS_21_basis 200mm; IsExternal: yes; LoadBearing: no
CPset_Phasing - Renovation Phase: Nieuw
Material Properties - Wall Basis, ThermalConductivity: 2.3; Wall Basis, SpecificHeatCapacity: 1000 J/kg/K; Wall Basis, MassDensity: 2300 kg/m3; Wall Basis, Embodied Energy: 1.92 (MJ/kg); Wall Basis, Embodied Carbon: 0.198 (kgCO₂/kg); Wall Basis, Name: Wall Basis; Wall Basis, Participates in Collision Detection: yes
Name (Basic Wall:NLRS_21_basis 200mm:...) | Pset_ReinforcementBarPitchOfWall, Reference | Pset_ReinforcementBarPitchOfWall, sets with these values
2468417 | NLRS_21_basis 200mm | 2
2468300 | NLRS_21_basis 200mm | 2
2468543 | Pset_QuantityTakeOff - Reference: NLRS_21_basis 200mm; sets with these values: 2

# IfcWall: Basic Wall:NLRS_22_gasbeton 100mm (9)
In: 6e verdieping V
Type - PredefinedType: STANDARD
Material: gasbeton
Pset_WallCommon - ExtendToStructure: no; Reference: NLRS_22_gasbeton 100mm; IsExternal: no; LoadBearing: no
Pset_ReinforcementBarPitchOfWall - Reference: NLRS_22_gasbeton 100mm; sets with these values: 2
CPset_Phasing - Renovation Phase: Nieuw
Material Properties - gasbeton, ThermalConductivity: 2.3; gasbeton, SpecificHeatCapacity: 1000 J/kg/K; gasbeton, MassDensity: 2300 kg/m3; gasbeton, Embodied Energy: 1.92 (MJ/kg); gasbeton, Embodied Carbon: 0.198 (kgCO₂/kg); gasbeton, Name: gasbeton; gasbeton, Participates in Collision Detection: yes
Name (Basic Wall:NLRS_22_gasbeton 100mm:...)
2091721
2548628
2550976
2547972
2551125
2548165
2551037
2550806
2091764

# IfcWall: Basic Wall:NLRS_22_gasbeton 200mm (3)
Type - PredefinedType: STANDARD
Material: gasbeton
Pset_ReinforcementBarPitchOfWall - Reference: NLRS_22_gasbeton 200mm; sets with these values: 2
Material Properties - gasbeton, ThermalConductivity: 2.3; gasbeton, SpecificHeatCapacity: 1000 J/kg/K; gasbeton, MassDensity: 2300 kg/m3; gasbeton, Embodied Energy: 1.92 (MJ/kg); gasbeton, Embodied Carbon: 0.198 (kgCO₂/kg); gasbeton, Name: gasbeton; gasbeton, Participates in Collision Detection: yes
CPset_Phasing - Renovation Phase: Nieuw
Pset_WallCommon - ExtendToStructure: no; Reference: NLRS_22_gasbeton 200mm; IsExternal: no; LoadBearing: no
Name (Basic Wall:NLRS_22_gasbeton 200mm:...) | In
2547299 | 6e verdieping V
3146919 | 7e verdieping-dak V
3146670 | 7e verdieping-dak V

# IfcWall: Basic Wall:NLRS_28_kalkzandsteen 100mm (37)
Type - PredefinedType: STANDARD
Material: kalkzandsteen
Pset_WallCommon - ExtendToStructure: no; Reference: NLRS_28_kalkzandsteen 100mm; IsExternal: no; LoadBearing: no
CPset_Phasing - Renovation Phase: Nieuw
Material Properties - kalkzandsteen, ThermalConductivity: 2.3; kalkzandsteen, SpecificHeatCapacity: 1000 J/kg/K; kalkzandsteen, MassDensity: 2300 kg/m3; kalkzandsteen, Embodied Energy: 1.92 (MJ/kg); kalkzandsteen, Embodied Carbon: 0.198 (kgCO₂/kg); kalkzandsteen, Name: kalkzandsteen; kalkzandsteen, Participates in Collision Detection: yes
Name (Basic Wall:NLRS_28_kalkzandsteen 100mm:...) | In | Pset_ReinforcementBarPitchOfWall, Reference | Pset_ReinforcementBarPitchOfWall, sets with these values | Group
2040055 | 1e verdieping N | NLRS_28_kalkzandsteen 100mm | 2
2040056 | 1e verdieping N | NLRS_28_kalkzandsteen 100mm | 2
2420448 | 1e verdieping N | NLRS_28_kalkzandsteen 100mm | 2
2039363 | 1e verdieping N | NLRS_28_kalkzandsteen 100mm | 2
2039364 | 1e verdieping N | NLRS_28_kalkzandsteen 100mm | 2
2039365 | 1e verdieping N | Pset_QuantityTakeOff - Reference: NLRS_28_kalkzandsteen 100mm; sets with these values: 2
2423069 | 1e verdieping N | NLRS_28_kalkzandsteen 100mm | 2
2427719 | 1e verdieping N | NLRS_28_kalkzandsteen 100mm | 2
2728958 | 1e verdieping N | NLRS_28_kalkzandsteen 100mm | 2
2040054 | 1e verdieping N | NLRS_28_kalkzandsteen 100mm | 2
2427406 | 2e verdieping N | NLRS_28_kalkzandsteen 100mm | 2
2111239 | 2e verdieping N | NLRS_28_kalkzandsteen 100mm | 2
2111107 | 2e verdieping N | NLRS_28_kalkzandsteen 100mm | 2
2039119 | 2e verdieping N | NLRS_28_kalkzandsteen 100mm | 2
2039117 | 2e verdieping N | NLRS_28_kalkzandsteen 100mm | 2
2039118 | 2e verdieping N | NLRS_28_kalkzandsteen 100mm | 2
2013374 | 2e verdieping V | NLRS_28_kalkzandsteen 100mm | 2 | Model Group:V vluchttrappenhuis 2:2013401
2013373 | 2e verdieping V | NLRS_28_kalkzandsteen 100mm | 2 | Model Group:V vluchttrappenhuis 2:2013401
2013372 | 2e verdieping V |  |  | Model Group:V vluchttrappenhuis 2:2013401 | Pset_QuantityTakeOff - Reference: NLRS_28_kalkzandsteen 100mm; sets with these values: 2
2425398 | 2e verdieping V | NLRS_28_kalkzandsteen 100mm | 2 | Model Group:V vluchttrappenhuis 2:2013401
2425403 | 3e verdieping/dak N | NLRS_28_kalkzandsteen 100mm | 2 | Model Group:V vluchttrappenhuis 2:2013471
2013443 | 3e verdieping/dak N | NLRS_28_kalkzandsteen 100mm | 2 | Model Group:V vluchttrappenhuis 2:2013471
2013444 | 3e verdieping/dak N | NLRS_28_kalkzandsteen 100mm | 2 | Model Group:V vluchttrappenhuis 2:2013471
2013442 | 3e verdieping/dak N | NLRS_28_kalkzandsteen 100mm | 2 | Model Group:V vluchttrappenhuis 2:2013471
2013641 | 3e verdieping V | NLRS_28_kalkzandsteen 100mm | 2 | Model Group:V vluchttrappenhuis 2:2013517
2013639 | 3e verdieping V | NLRS_28_kalkzandsteen 100mm | 2 | Model Group:V vluchttrappenhuis 2:2013517
2013640 | 3e verdieping V |  |  | Model Group:V vluchttrappenhuis 2:2013517 | Pset_QuantityTakeOff - Reference: NLRS_28_kalkzandsteen 100mm; sets with these values: 2
2425408 | 3e verdieping V | NLRS_28_kalkzandsteen 100mm | 2 | Model Group:V vluchttrappenhuis 2:2013517
3085528 | 4e verdieping V |  |  | Model Group:V vluchttrappenhuis 2:2013112 | Pset_QuantityTakeOff - Reference: NLRS_28_kalkzandsteen 100mm; sets with these values: 2
3085505 | 4e verdieping V |  |  | Model Group:V vluchttrappenhuis 2:2013112 | Pset_QuantityTakeOff - Reference: NLRS_28_kalkzandsteen 100mm; sets with these values: 2
3085507 | 4e verdieping V | NLRS_28_kalkzandsteen 100mm | 2 | Model Group:V vluchttrappenhuis 2:2013112
3085506 | 4e verdieping V | NLRS_28_kalkzandsteen 100mm | 2 | Model Group:V vluchttrappenhuis 2:2013112
3083783 | 5e verdieping V | NLRS_28_kalkzandsteen 100mm | 2 | Model Group:V vluchttrappenhuis V5:3080963
3081067 | 5e verdieping V | NLRS_28_kalkzandsteen 100mm | 2 | Model Group:V vluchttrappenhuis V5:3080963
3081263 | 5e verdieping V | NLRS_28_kalkzandsteen 100mm | 2 | Model Group:V vluchttrappenhuis V5:3080963
3081262 | 5e verdieping V | NLRS_28_kalkzandsteen 100mm | 2 | Model Group:V vluchttrappenhuis V5:3080963
3081066 | 5e verdieping V |  |  | Model Group:V vluchttrappenhuis V5:3080963 | Pset_QuantityTakeOff - Reference: NLRS_28_kalkzandsteen 100mm; sets with these values: 2

# IfcWall: Basic Wall:NLRS_28_kalkzandsteen 214mm (69)
Type - PredefinedType: STANDARD
Material: kalkzandsteen
Pset_WallCommon - Reference: NLRS_28_kalkzandsteen 214mm; IsExternal: no; LoadBearing: no
Material Properties - kalkzandsteen, ThermalConductivity: 2.3; kalkzandsteen, SpecificHeatCapacity: 1000 J/kg/K; kalkzandsteen, MassDensity: 2300 kg/m3; kalkzandsteen, Embodied Energy: 1.92 (MJ/kg); kalkzandsteen, Embodied Carbon: 0.198 (kgCO₂/kg); kalkzandsteen, Name: kalkzandsteen; kalkzandsteen, Participates in Collision Detection: yes
CPset_Phasing - Renovation Phase: Nieuw
Name (Basic Wall:NLRS_28_kalkzandsteen 214mm:...) | In | ExtendToStructure | Pset_ReinforcementBarPitchOfWall, Reference | Pset_ReinforcementBarPitchOfWall, sets with these values | Group
2728202 | 1e verdieping N | no | NLRS_28_kalkzandsteen 214mm | 2
2728058 | 1e verdieping N | no | Pset_QuantityTakeOff - Reference: NLRS_28_kalkzandsteen 214mm; sets with these values: 2
2040023 | 1e verdieping N | no | NLRS_28_kalkzandsteen 214mm | 2
2040040 | 1e verdieping N | no | NLRS_28_kalkzandsteen 214mm | 2
2040039 | 1e verdieping N | no | NLRS_28_kalkzandsteen 214mm | 2
2040022 | 1e verdieping N | no | NLRS_28_kalkzandsteen 214mm | 2
2039349 | 1e verdieping N | no | NLRS_28_kalkzandsteen 214mm | 2
2039369 | 1e verdieping N | no | NLRS_28_kalkzandsteen 214mm | 2
2039330 | 1e verdieping N | no | NLRS_28_kalkzandsteen 214mm | 2
2039331 | 1e verdieping N | no | Pset_QuantityTakeOff - Reference: NLRS_28_kalkzandsteen 214mm; sets with these values: 2
2039333 | 1e verdieping N | no | Pset_QuantityTakeOff - Reference: NLRS_28_kalkzandsteen 214mm; sets with these values: 2
2039348 | 1e verdieping N | no | NLRS_28_kalkzandsteen 214mm | 2
2039350 | 1e verdieping N | no | Pset_QuantityTakeOff - Reference: NLRS_28_kalkzandsteen 214mm; sets with these values: 2
2040041 | 1e verdieping N | no | NLRS_28_kalkzandsteen 214mm | 2
2040021 | 1e verdieping N | no | NLRS_28_kalkzandsteen 214mm | 2
3212067 | 1e verdieping N | no | Pset_QuantityTakeOff - Reference: NLRS_28_kalkzandsteen 214mm; sets with these values: 2
2039332 | 1e verdieping N | no | NLRS_28_kalkzandsteen 214mm | 2
2040024 | 1e verdieping N | no | NLRS_28_kalkzandsteen 214mm | 2
2040060 | 1e verdieping N | no | NLRS_28_kalkzandsteen 214mm | 2
2039087 | 2e verdieping N | no | Pset_QuantityTakeOff - Reference: NLRS_28_kalkzandsteen 214mm; sets with these values: 2
2039086 | 2e verdieping N | no | Pset_QuantityTakeOff - Reference: NLRS_28_kalkzandsteen 214mm; sets with these values: 2
2039103 | 2e verdieping N | no | Pset_QuantityTakeOff - Reference: NLRS_28_kalkzandsteen 214mm; sets with these values: 2
2039084 | 2e verdieping N | no | NLRS_28_kalkzandsteen 214mm | 2
2039085 | 2e verdieping N | no | NLRS_28_kalkzandsteen 214mm | 2
2039123 | 2e verdieping N | no | NLRS_28_kalkzandsteen 214mm | 2
2013359 | 2e verdieping V | no |  |  | Model Group:V vluchttrappenhuis 2:2013401 | Pset_QuantityTakeOff - Reference: NLRS_28_kalkzandsteen 214mm; sets with these values: 2
2013337 | 2e verdieping V | no |  |  | Model Group:V vluchttrappenhuis 2:2013401 | Pset_QuantityTakeOff - Reference: NLRS_28_kalkzandsteen 214mm; sets with these values: 2
2013336 | 2e verdieping V | no | NLRS_28_kalkzandsteen 214mm | 2 | Model Group:V vluchttrappenhuis 2:2013401
2013378 | 2e verdieping V | no | NLRS_28_kalkzandsteen 214mm | 2 | Model Group:V vluchttrappenhuis 2:2013401
2013335 | 2e verdieping V | no | NLRS_28_kalkzandsteen 214mm | 2 | Model Group:V vluchttrappenhuis 2:2013401
2014444 | 2e verdieping V | no | NLRS_28_kalkzandsteen 214mm | 2 | Model Group:V vluchttrappenhuis 2:2013401
2013334 | 2e verdieping V | no | NLRS_28_kalkzandsteen 214mm | 2 | Model Group:V vluchttrappenhuis 2:2013401
2014443 | 2e verdieping V | no | NLRS_28_kalkzandsteen 214mm | 2 | Model Group:V vluchttrappenhuis 2:2013401
2014453 | 3e verdieping/dak N | no | NLRS_28_kalkzandsteen 214mm | 2 | Model Group:V vluchttrappenhuis 2:2013471
2013429 | 3e verdieping/dak N | no | NLRS_28_kalkzandsteen 214mm | 2 | Model Group:V vluchttrappenhuis 2:2013471
2013404 | 3e verdieping/dak N | no | NLRS_28_kalkzandsteen 214mm | 2 | Model Group:V vluchttrappenhuis 2:2013471
2013405 | 3e verdieping/dak N | no | NLRS_28_kalkzandsteen 214mm | 2 | Model Group:V vluchttrappenhuis 2:2013471
2014452 | 3e verdieping/dak N | yes | NLRS_28_kalkzandsteen 214mm | 2 | Model Group:V vluchttrappenhuis 2:2013471
2013406 | 3e verdieping/dak N | no | NLRS_28_kalkzandsteen 214mm | 2 | Model Group:V vluchttrappenhuis 2:2013471
2013407 | 3e verdieping/dak N | no | NLRS_28_kalkzandsteen 214mm | 2 | Model Group:V vluchttrappenhuis 2:2013471
2013448 | 3e verdieping/dak N | no | NLRS_28_kalkzandsteen 214mm | 2 | Model Group:V vluchttrappenhuis 2:2013471
2014462 | 3e verdieping V | no |  |  | Model Group:V vluchttrappenhuis 2:2013517 | Pset_QuantityTakeOff - Reference: NLRS_28_kalkzandsteen 214mm; sets with these values: 2
2013645 | 3e verdieping V | no |  |  | Model Group:V vluchttrappenhuis 2:2013517 | Pset_QuantityTakeOff - Reference: NLRS_28_kalkzandsteen 214mm; sets with these values: 2
2013625 | 3e verdieping V | no | NLRS_28_kalkzandsteen 214mm | 2 | Model Group:V vluchttrappenhuis 2:2013517
2013599 | 3e verdieping V | no | NLRS_28_kalkzandsteen 214mm | 2 | Model Group:V vluchttrappenhuis 2:2013517
2013600 | 3e verdieping V | no | NLRS_28_kalkzandsteen 214mm | 2 | Model Group:V vluchttrappenhuis 2:2013517
2013601 | 3e verdieping V | no |  |  | Model Group:V vluchttrappenhuis 2:2013517 | Pset_QuantityTakeOff - Reference: NLRS_28_kalkzandsteen 214mm; sets with these values: 2
2013602 | 3e verdieping V | no | NLRS_28_kalkzandsteen 214mm | 2 | Model Group:V vluchttrappenhuis 2:2013517
2014461 | 3e verdieping V | no |  |  | Model Group:V vluchttrappenhuis 2:2013517 | Pset_QuantityTakeOff - Reference: NLRS_28_kalkzandsteen 214mm; sets with these values: 2
3085480 | 4e verdieping V | no | NLRS_28_kalkzandsteen 214mm | 2 | Model Group:V vluchttrappenhuis 2:2013112
2039102 | 2e verdieping N | no | NLRS_28_kalkzandsteen 214mm | 2
3085479 | 4e verdieping V | no | NLRS_28_kalkzandsteen 214mm | 2 | Model Group:V vluchttrappenhuis 2:2013112
3085477 | 4e verdieping V | no | NLRS_28_kalkzandsteen 214mm | 2 | Model Group:V vluchttrappenhuis 2:2013112
3085511 | 4e verdieping V | no |  |  | Model Group:V vluchttrappenhuis 2:2013112 | Pset_QuantityTakeOff - Reference: NLRS_28_kalkzandsteen 214mm; sets with these values: 2
3085521 | 4e verdieping V | no |  |  | Model Group:V vluchttrappenhuis 2:2013112 | Pset_QuantityTakeOff - Reference: NLRS_28_kalkzandsteen 214mm; sets with these values: 2
3085522 | 4e verdieping V | no | NLRS_28_kalkzandsteen 214mm | 2 | Model Group:V vluchttrappenhuis 2:2013112
3085478 | 4e verdieping V | no |  |  | Model Group:V vluchttrappenhuis 2:2013112 | Pset_QuantityTakeOff - Reference: NLRS_28_kalkzandsteen 214mm; sets with these values: 2
3085494 | 4e verdieping V | no | NLRS_28_kalkzandsteen 214mm | 2 | Model Group:V vluchttrappenhuis 2:2013112
3084238 | 5e verdieping V | no |  |  | Model Group:V vluchttrappenhuis V5:3080963 | Pset_QuantityTakeOff - Reference: NLRS_28_kalkzandsteen 214mm; sets with these values: 2
3084438 | 5e verdieping V | no |  |  | Model Group:V vluchttrappenhuis V5:3080963 | Pset_QuantityTakeOff - Reference: NLRS_28_kalkzandsteen 214mm; sets with these values: 2
3081037 | 5e verdieping V | no |  |  | Model Group:V vluchttrappenhuis V5:3080963 | Pset_QuantityTakeOff - Reference: NLRS_28_kalkzandsteen 214mm; sets with these values: 2
3081071 | 5e verdieping V | no | NLRS_28_kalkzandsteen 214mm | 2 | Model Group:V vluchttrappenhuis V5:3080963
3081053 | 5e verdieping V | no | NLRS_28_kalkzandsteen 214mm | 2 | Model Group:V vluchttrappenhuis V5:3080963
3081038 | 5e verdieping V | no |  |  | Model Group:V vluchttrappenhuis V5:3080963 | Pset_QuantityTakeOff - Reference: NLRS_28_kalkzandsteen 214mm; sets with these values: 2
3081036 | 5e verdieping V | no | NLRS_28_kalkzandsteen 214mm | 2 | Model Group:V vluchttrappenhuis V5:3080963
3081052 | 5e verdieping V | no | NLRS_28_kalkzandsteen 214mm | 2 | Model Group:V vluchttrappenhuis V5:3080963
3081035 | 5e verdieping V | no | NLRS_28_kalkzandsteen 214mm | 2 | Model Group:V vluchttrappenhuis V5:3080963
3081811 | 5e verdieping V | no |  |  | Model Group:V vluchttrappenhuis V5:3080963 | Pset_QuantityTakeOff - Reference: NLRS_28_kalkzandsteen 214mm; sets with these values: 2
2039104 | 2e verdieping N | no | NLRS_28_kalkzandsteen 214mm | 2

# IfcWall: Basic Wall:NLRS_28_massieve betonwand 200mm, Basic Wall:NLRS_28_massieve betonwand 200mm:3066162
In: 2e verdieping N
Type - PredefinedType: STANDARD
Material: beton_ wanden
Pset_WallCommon - ExtendToStructure: no; Reference: NLRS_28_massieve betonwand 200mm; IsExternal: no; LoadBearing: no
Pset_ReinforcementBarPitchOfWall - Reference: NLRS_28_massieve betonwand 200mm; sets with these values: 2
CPset_Phasing - Renovation Phase: Nieuw
Material Properties - beton_ wanden, ThermalConductivity: 2.3; beton_ wanden, SpecificHeatCapacity: 1000 J/kg/K; beton_ wanden, MassDensity: 2300 kg/m3; beton_ wanden, Embodied Energy: 1.92 (MJ/kg); beton_ wanden, Embodied Carbon: 0.198 (kgCO₂/kg); beton_ wanden, Name: beton_ wanden; beton_ wanden, Participates in Collision Detection: yes

# IfcWall: Beton gewapend C vloer 600 (2)
In: Fundering N
Material: Beton gewapend C vloer
Pset_WallCommon - FireRating: n.v.t.; SurfaceSpreadOfFlame: n.v.t.; IsExternal: yes; LoadBearing: yes
CPset_Phasing - Renovation Phase: Nieuw
Material Properties - Beton gewapend C vloer, ThermalConductivity: 2.5; Beton gewapend C vloer, SpecificHeatCapacity: 1000 J/kg/K; Beton gewapend C vloer, MassDensity: 2400 kg/m3; Beton gewapend C vloer, Embodied Energy: 2.33 (MJ/kg); Beton gewapend C vloer, Embodied Carbon: 0.242 (kgCO₂/kg); Beton gewapend C vloer, Name: Beton gewapend C vloer; Beton gewapend C vloer, Participates in Collision Detection: yes

# IfcWall: Beton gewapend C vloer 800 (2)
In: Fundering N
Material: Beton gewapend C vloer
Pset_WallCommon - FireRating: n.v.t.; SurfaceSpreadOfFlame: n.v.t.; IsExternal: yes; LoadBearing: yes
CPset_Phasing - Renovation Phase: Nieuw
Material Properties - Beton gewapend C vloer, ThermalConductivity: 2.5; Beton gewapend C vloer, SpecificHeatCapacity: 1000 J/kg/K; Beton gewapend C vloer, MassDensity: 2400 kg/m3; Beton gewapend C vloer, Embodied Energy: 2.33 (MJ/kg); Beton gewapend C vloer, Embodied Carbon: 0.242 (kgCO₂/kg); Beton gewapend C vloer, Name: Beton gewapend C vloer; Beton gewapend C vloer, Participates in Collision Detection: yes

# IfcWall: Gevel decowall-hsb 278 (3)
Pset_WallCommon - FireRating: n.v.t.; SurfaceSpreadOfFlame: n.v.t.; IsExternal: yes; LoadBearing: yes
CPset_Phasing - Renovation Phase: Nieuw
Name | In
2 x _Wand-x | 2e verdieping N
_Wand-x | 2e verdieping V

# IfcWall: Gevel-hsb tpv bg optie 216 (2)
In: Begane grond N
Pset_WallCommon - FireRating: n.v.t.; SurfaceSpreadOfFlame: n.v.t.; IsExternal: yes; LoadBearing: yes
CPset_Phasing - Renovation Phase: Nieuw

# IfcWall: Gevelstuc 90 (7)
In: Begane grond N
Pset_WallCommon - FireRating: n.v.t.; SurfaceSpreadOfFlame: n.v.t.; IsExternal: yes; LoadBearing: yes
CPset_Phasing - Renovation Phase: Nieuw

# IfcWall: Gipsplaat 13 (10)
Material: Gipsplaat
CPset_Phasing - Renovation Phase: Nieuw
Material Properties - Gipsplaat, ThermalConductivity: 0.23; Gipsplaat, SpecificHeatCapacity: 840 J/kg/K; Gipsplaat, MassDensity: 800 kg/m3; Gipsplaat, Embodied Energy: 6.75 (MJ/kg); Gipsplaat, Embodied Carbon: 0.38 (kgCO₂/kg); Gipsplaat, Name: Gipsplaat; Gipsplaat, Participates in Collision Detection: yes
Pset_WallCommon - FireRating: n.v.t.; SurfaceSpreadOfFlame: n.v.t.; IsExternal: yes; LoadBearing: yes
Name | In
5 x _Wand-x | Begane grond N
4 x _Wand-x | 1e verdieping N
_Wand-x | 2e verdieping N

# IfcWall: Gipsplaat 25 (189)
Material: Gipsplaat
CPset_Phasing - Renovation Phase: Nieuw
Pset_WallCommon - FireRating: n.v.t.; SurfaceSpreadOfFlame: n.v.t.; IsExternal: yes; LoadBearing: yes
Material Properties - Gipsplaat, ThermalConductivity: 0.23; Gipsplaat, SpecificHeatCapacity: 840 J/kg/K; Gipsplaat, MassDensity: 800 kg/m3; Gipsplaat, Embodied Energy: 6.75 (MJ/kg); Gipsplaat, Embodied Carbon: 0.38 (kgCO₂/kg); Gipsplaat, Name: Gipsplaat; Gipsplaat, Participates in Collision Detection: yes
Name | In
56 x _Wand-x | Begane grond N
63 x _Wand-x | 1e verdieping N
70 x _Wand-x | 2e verdieping N

# IfcWall: Glas 10 (5)
Material: Glas
CPset_Phasing - Renovation Phase: Nieuw
Material Properties - Glas, ThermalConductivity: 1.2; Glas, SpecificHeatCapacity: 795 J/kg/K; Glas, MassDensity: 2180 kg/m3; Glas, Embodied Energy: 15 (MJ/kg); Glas, Embodied Carbon: 0.86 (kgCO₂/kg); Glas, Name: Glas; Glas, Participates in Collision Detection: yes
Pset_WallCommon - FireRating: n.v.t.; SurfaceSpreadOfFlame: n.v.t.; IsExternal: yes; LoadBearing: yes
Name | In
3 x _Wand-x | 1e verdieping N
2 x _Wand-x | 2e verdieping N

# IfcWall: Metalstud 100 enkel 100 (78)
Material: Gipsplaat
Pset_WallCommon - FireRating: n.v.t.; SurfaceSpreadOfFlame: n.v.t.; IsExternal: yes; LoadBearing: yes
Material Properties - Gipsplaat, ThermalConductivity: 0.23; Gipsplaat, SpecificHeatCapacity: 840 J/kg/K; Gipsplaat, MassDensity: 800 kg/m3; Gipsplaat, Embodied Energy: 6.75 (MJ/kg); Gipsplaat, Embodied Carbon: 0.38 (kgCO₂/kg); Gipsplaat, Name: Gipsplaat; Gipsplaat, Participates in Collision Detection: yes
Name | In | Renovation Phase
23 x _Wand-x | Begane grond N | Nieuw
_Wand-x | Begane grond N | Bestaand
27 x _Wand-x | 1e verdieping N | Nieuw
27 x _Wand-x | 2e verdieping N | Nieuw

# IfcWall: Metalstud 150 enkel 150 (20)
Material: Gipsplaat
Pset_WallCommon - FireRating: n.v.t.; SurfaceSpreadOfFlame: n.v.t.; IsExternal: yes; LoadBearing: yes
CPset_Phasing - Renovation Phase: Nieuw
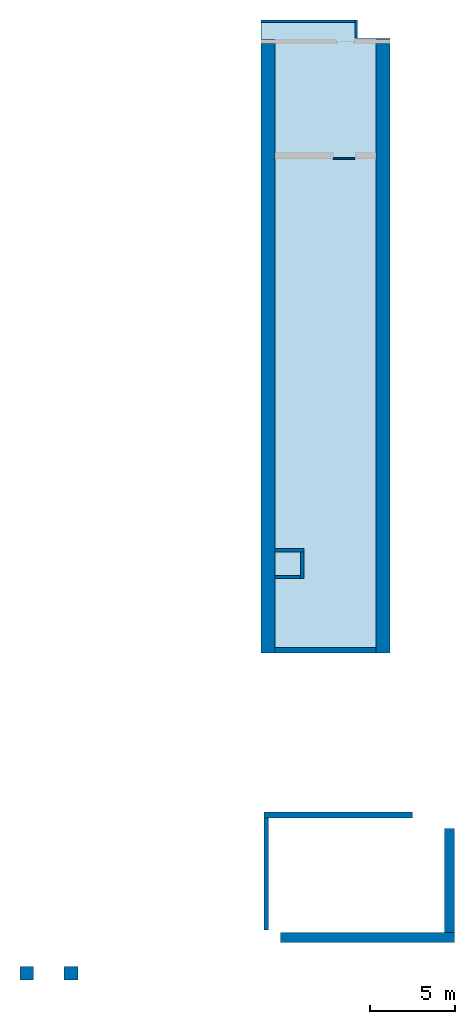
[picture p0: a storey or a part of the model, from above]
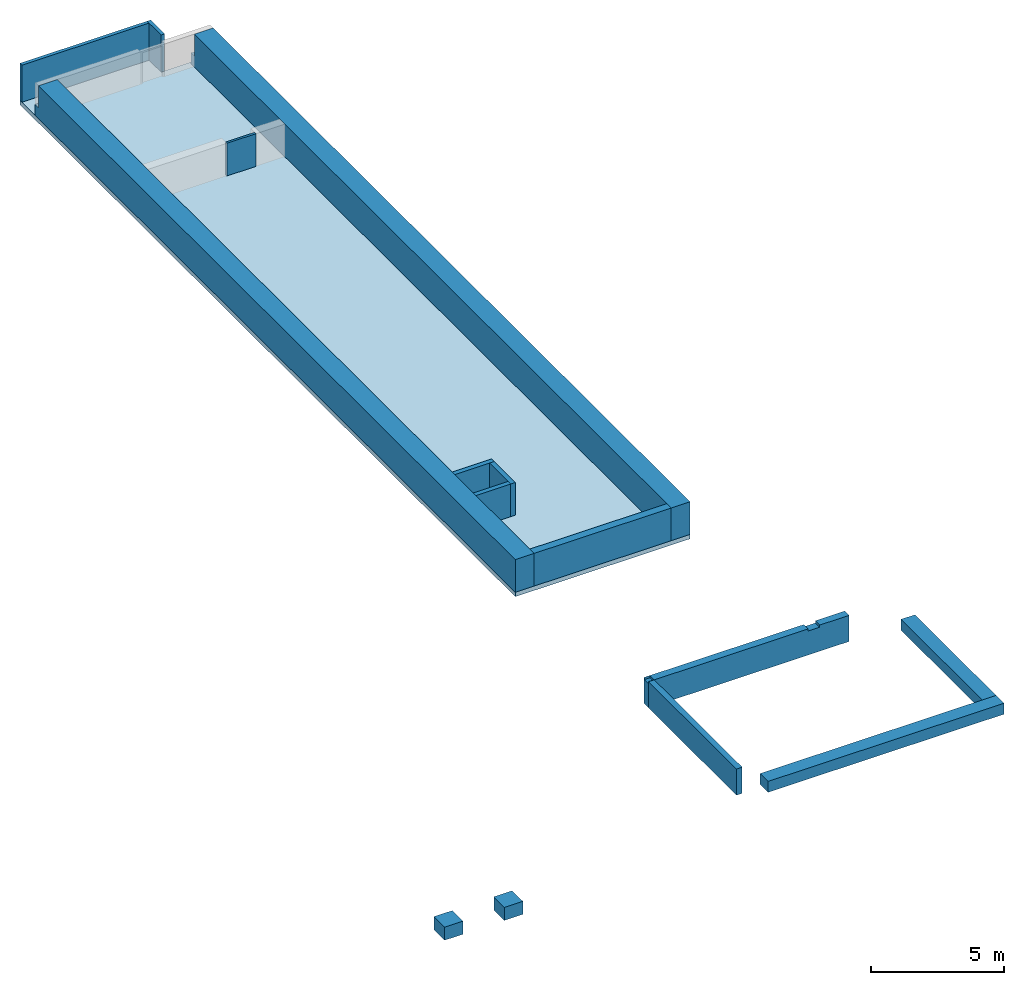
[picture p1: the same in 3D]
Properties of the parts of a building model (IFC2X3), part 7 of 7

# IfcWall: Metalstud 150 enkel 150 (20)
Material Properties - Gipsplaat, ThermalConductivity: 0.23; Gipsplaat, SpecificHeatCapacity: 840 J/kg/K; Gipsplaat, MassDensity: 800 kg/m3; Gipsplaat, Embodied Energy: 6.75 (MJ/kg); Gipsplaat, Embodied Carbon: 0.38 (kgCO₂/kg); Gipsplaat, Name: Gipsplaat; Gipsplaat, Participates in Collision Detection: yes
Name | In
6 x _Wand-x | Begane grond N
7 x _Wand-x | 1e verdieping N
7 x _Wand-x | 2e verdieping N

# IfcWall: Metalstud iso 100 100 (257)
Pset_WallCommon - FireRating: n.v.t.; SurfaceSpreadOfFlame: n.v.t.; IsExternal: yes; LoadBearing: yes
Name | In | Renovation Phase
87 x _Wand-x | Begane grond N | Nieuw
95 x _Wand-x | 1e verdieping N | Nieuw
2 x _Wand-x | 1e verdieping N | Bestaand
73 x _Wand-x | 2e verdieping N | Nieuw

# IfcWall: Metalstud iso 100 enkel 100 (3)
Pset_WallCommon - FireRating: n.v.t.; SurfaceSpreadOfFlame: n.v.t.; IsExternal: yes; LoadBearing: yes
CPset_Phasing - Renovation Phase: Nieuw
Name | In
2 x _Wand-x | Begane grond N
_Wand-x | 1e verdieping N

# IfcWall: Metalstud iso 150 150 (27)
Pset_WallCommon - FireRating: n.v.t.; SurfaceSpreadOfFlame: n.v.t.; IsExternal: yes; LoadBearing: yes
CPset_Phasing - Renovation Phase: Nieuw
Name | In
12 x _Wand-x | Begane grond N
8 x _Wand-x | 1e verdieping N
7 x _Wand-x | 2e verdieping N

# IfcWall: Metalstud voorzetwand 200 200 (3)
In: Begane grond N
Pset_WallCommon - FireRating: n.v.t.; SurfaceSpreadOfFlame: n.v.t.; IsExternal: yes; LoadBearing: yes
CPset_Phasing - Renovation Phase: Nieuw

# IfcWall: Spouwmuur mw-bs 330 330 (2)
In: Begane grond N
CPset_Phasing - Renovation Phase: Nieuw
Pset_WallCommon - FireRating: n.v.t.; SurfaceSpreadOfFlame: n.v.t.; IsExternal: yes; LoadBearing: yes

# IfcWall: Steen - Betonblok 100 (27)
Material: Steen - Betonblok
Pset_WallCommon - FireRating: n.v.t.; SurfaceSpreadOfFlame: n.v.t.; IsExternal: yes; LoadBearing: yes
CPset_Phasing - Renovation Phase: Nieuw
Material Properties - Steen - Betonblok, ThermalConductivity: 0.4; Steen - Betonblok, SpecificHeatCapacity: 840 J/kg/K; Steen - Betonblok, MassDensity: 800 kg/m3; Steen - Betonblok, Embodied Energy: 0.59 (MJ/kg); Steen - Betonblok, Embodied Carbon: 0.059 (kgCO₂/kg); Steen - Betonblok, Name: Steen - Betonblok; Steen - Betonblok, Participates in Collision Detection: yes
Name | In
21 x _Wand-x | Begane grond N
3 x _Wand-x | 1e verdieping N
3 x _Wand-x | 2e verdieping N

# IfcWall: Steen - Betonblok 150 (3)
Material: Steen - Betonblok
CPset_Phasing - Renovation Phase: Nieuw
Material Properties - Steen - Betonblok, ThermalConductivity: 0.4; Steen - Betonblok, SpecificHeatCapacity: 840 J/kg/K; Steen - Betonblok, MassDensity: 800 kg/m3; Steen - Betonblok, Embodied Energy: 0.59 (MJ/kg); Steen - Betonblok, Embodied Carbon: 0.059 (kgCO₂/kg); Steen - Betonblok, Name: Steen - Betonblok; Steen - Betonblok, Participates in Collision Detection: yes
Pset_WallCommon - FireRating: n.v.t.; SurfaceSpreadOfFlame: n.v.t.; IsExternal: yes; LoadBearing: yes
Name | In
_Wand-x | Begane grond N
_Wand-x | 1e verdieping N
_Wand-x | 2e verdieping N

# IfcWall: Steen - Betonblok 240 (4)
In: Begane grond N
Material: Steen - Betonblok
Pset_WallCommon - FireRating: n.v.t.; SurfaceSpreadOfFlame: n.v.t.; IsExternal: yes; LoadBearing: yes
CPset_Phasing - Renovation Phase: Nieuw
Material Properties - Steen - Betonblok, ThermalConductivity: 0.4; Steen - Betonblok, SpecificHeatCapacity: 840 J/kg/K; Steen - Betonblok, MassDensity: 800 kg/m3; Steen - Betonblok, Embodied Energy: 0.59 (MJ/kg); Steen - Betonblok, Embodied Carbon: 0.059 (kgCO₂/kg); Steen - Betonblok, Name: Steen - Betonblok; Steen - Betonblok, Participates in Collision Detection: yes

# IfcWall: Steen - Betonblok 250, _Wand-x
In: Begane grond N
Material: Steen - Betonblok
CPset_Phasing - Renovation Phase: Nieuw
Pset_WallCommon - FireRating: n.v.t.; SurfaceSpreadOfFlame: n.v.t.; IsExternal: yes; LoadBearing: yes
Material Properties - Steen - Betonblok, ThermalConductivity: 0.4; Steen - Betonblok, SpecificHeatCapacity: 840 J/kg/K; Steen - Betonblok, MassDensity: 800 kg/m3; Steen - Betonblok, Embodied Energy: 0.59 (MJ/kg); Steen - Betonblok, Embodied Carbon: 0.059 (kgCO₂/kg); Steen - Betonblok, Name: Steen - Betonblok; Steen - Betonblok, Participates in Collision Detection: yes

# IfcWall: Steen - Betonblok C 100 (2)
Material: Steen - Betonblok C
Pset_WallCommon - FireRating: n.v.t.; SurfaceSpreadOfFlame: n.v.t.; IsExternal: yes; LoadBearing: yes
CPset_Phasing - Renovation Phase: Nieuw
Material Properties - Steen - Betonblok C, ThermalConductivity: 0.75; Steen - Betonblok C, SpecificHeatCapacity: 840 J/kg/K; Steen - Betonblok C, MassDensity: 1600 kg/m3; Steen - Betonblok C, Embodied Energy: 0.83 (MJ/kg); Steen - Betonblok C, Embodied Carbon: 0.1 (kgCO₂/kg); Steen - Betonblok C, Name: Steen - Betonblok C; Steen - Betonblok C, Participates in Collision Detection: yes
Name | In
_Wand-x | Begane grond N
_Wand-x | 2e verdieping N

# IfcWall: Steen - Betonblok C 150 (7)
Material: Steen - Betonblok C
Pset_WallCommon - FireRating: n.v.t.; SurfaceSpreadOfFlame: n.v.t.; IsExternal: yes; LoadBearing: yes
Material Properties - Steen - Betonblok C, ThermalConductivity: 0.75; Steen - Betonblok C, SpecificHeatCapacity: 840 J/kg/K; Steen - Betonblok C, MassDensity: 1600 kg/m3; Steen - Betonblok C, Embodied Energy: 0.83 (MJ/kg); Steen - Betonblok C, Embodied Carbon: 0.1 (kgCO₂/kg); Steen - Betonblok C, Name: Steen - Betonblok C; Steen - Betonblok C, Participates in Collision Detection: yes
CPset_Phasing - Renovation Phase: Nieuw
Name | In
2 x _Wand-x | Begane grond N
3 x _Wand-x | 1e verdieping N
2 x _Wand-x | 2e verdieping N

# IfcWall: Steen - Betonblok C 240, _Wand-x
In: Begane grond N
Material: Steen - Betonblok C
Material Properties - Steen - Betonblok C, ThermalConductivity: 0.75; Steen - Betonblok C, SpecificHeatCapacity: 840 J/kg/K; Steen - Betonblok C, MassDensity: 1600 kg/m3; Steen - Betonblok C, Embodied Energy: 0.83 (MJ/kg); Steen - Betonblok C, Embodied Carbon: 0.1 (kgCO₂/kg); Steen - Betonblok C, Name: Steen - Betonblok C; Steen - Betonblok C, Participates in Collision Detection: yes
CPset_Phasing - Renovation Phase: Nieuw
Pset_WallCommon - FireRating: n.v.t.; SurfaceSpreadOfFlame: n.v.t.; IsExternal: yes; LoadBearing: yes

# IfcWall: afdekkap dakrand penthouse:afdekkap dakrand penthouse, afdekkap dakrand penthouse:afdekkap dakrand penthouse:2660494
In: 7e verdieping-dak V
Material: aluminium_grijs
Pset_WallCommon - Reference: afdekkap dakrand penthouse; IsExternal: no; LoadBearing: yes
Pset_QuantityTakeOff - Reference: afdekkap dakrand penthouse; sets with these values: 2
CPset_Phasing - Renovation Phase: Nieuw
Material Properties - aluminium_grijs, ThermalConductivity: 2.3; aluminium_grijs, SpecificHeatCapacity: 1000 J/kg/K; aluminium_grijs, MassDensity: 2300 kg/m3; aluminium_grijs, Embodied Energy: 1.92 (MJ/kg); aluminium_grijs, Embodied Carbon: 0.198 (kgCO₂/kg); aluminium_grijs, Name: aluminium_grijs; aluminium_grijs, Participates in Collision Detection: yes

# IfcWindow: 31_WI_raam_1:alu raam (14)
In: 5e verdieping V
Type - ParameterTakesPrecedence: no; Sizeable: no
Material: IFC Building Material
Pset_QuantityTakeOff - Reference: alu raam
Pset_WindowCommon - Reference: alu raam; IsExternal: yes
CPset_Phasing - Renovation Phase: Nieuw
Material Properties - IFC Building Material, ThermalConductivity: 2.3; IFC Building Material, SpecificHeatCapacity: 1000 J/kg/K; IFC Building Material, MassDensity: 2300 kg/m3; IFC Building Material, Embodied Energy: 1.92 (MJ/kg); IFC Building Material, Embodied Carbon: 0.198 (kgCO₂/kg); IFC Building Material, Name: IFC Building Material; IFC Building Material, Participates in Collision Detection: yes
Name (31_WI_raam_1:alu raam:...)
2999301
2999314
2540324
2997195
2557570 | Group: Model Group:V-koz-N nieuw:2557585
2557576 | Group: Model Group:V-koz-N nieuw:2557585
2772145
2772150
2772160
2772184
2772173
2772179
2772194
2772139

# IfcWindow: Beton C (2)
In: 1e verdieping N
Type - ParameterTakesPrecedence: no; Sizeable: no
Material: Beton C
Pset_WindowCommon - Reference: Hoekstijl Entree; IsExternal: no
Pset_QuantityTakeOff - Reference: Hoekstijl Entree
CPset_Phasing - Renovation Phase: Nieuw
Material Properties - Beton C, ThermalConductivity: 2; Beton C, SpecificHeatCapacity: 840 J/kg/K; Beton C, MassDensity: 2400 kg/m3; Beton C, Embodied Energy: 0.75 (MJ/kg); Beton C, Embodied Carbon: 0.1 (kgCO₂/kg); Beton C, Name: Beton C; Beton C, Participates in Collision Detection: yes
Name
Hoekstijl Entree1:Hoekstijl Entree:2949808
Hoekstijl Entree:Hoekstijl Entree:2730332

# IfcWindow: R rond 26 (3)
In: Begane grond N
Type - OperationType: USERDEFINED; ParameterTakesPrecedence: no; Sizeable: no
OverallHeight: 2000 mm; OverallWidth: 2000 mm
Pset_WindowCommon - FireRating: n.v.t.; SecurityRating: FALSE; ThermalTransmittance: 0; GlazingAreaFraction: 2.6974; SmokeStop: no; IsExternal: yes
Material - Afwerking dagkant binnen: n.v.t.; Afwerking dagkant buiten: n.v.t.; Draaiend deel: n.v.t.; Frame: n.v.t.; Onderdorpel: n.v.t.; Rollaag / latei: n.v.t.; Spouwlat: n.v.t.; Vensterbank: n.v.t.; Zonwering - behuizing: n.v.t.; Zonwering - isolatie: n.v.t.; Glas: Glas - algemeen
CPset_Phasing - Renovation Phase: Nieuw

# IfcWindow: R1 26 (8)
In: 1e verdieping N
Type - OperationType: SINGLE_PANEL; ParameterTakesPrecedence: no; Sizeable: no
Type - Window Lining Properties - LiningDepth: 114 mm; LiningThickness: 33.5 mm
Type - Window Panel Properties - Panel 1 - OperationType: FIXEDCASEMENT; PanelPosition: MIDDLE
OverallHeight: 3400 mm
Material - Afwerking dagkant binnen: n.v.t.; Afwerking dagkant buiten: n.v.t.; Draaiend deel: n.v.t.; Frame: n.v.t.; Onderdorpel: n.v.t.; Rollaag / latei: n.v.t.; Spouwlat: n.v.t.; Vensterbank: n.v.t.; Ventilatierooster: n.v.t.; Zonwering - behuizing: n.v.t.; Zonwering - isolatie: n.v.t.; Glas: Glas - algemeen
Pset_WindowCommon - FireRating: n.v.t.; SecurityRating: FALSE; ThermalTransmittance: 0; SmokeStop: no; IsExternal: yes
CPset_Phasing - Renovation Phase: Nieuw
Name | OverallWidth (mm) | GlazingAreaFraction
3 x _Merk-031 | 1000 | 3.04718
3 x _Merk-028 | 870 | 2.6226
2 x _Merk-028sp | 870 | 2.6226

# IfcWindow: R1 26 (2)
In: 1e verdieping N
Type - OperationType: SINGLE_PANEL; ParameterTakesPrecedence: no; Sizeable: no
Type - Window Lining Properties - LiningDepth: 114 mm; LiningThickness: 67 mm
Type - Window Panel Properties - Panel 1 - OperationType: FIXEDCASEMENT; PanelPosition: MIDDLE
OverallHeight: 3400 mm; OverallWidth: 870 mm
Material - Afwerking dagkant binnen: n.v.t.; Afwerking dagkant buiten: n.v.t.; Draaiend deel: n.v.t.; Frame: n.v.t.; Onderdorpel: n.v.t.; Rollaag / latei: n.v.t.; Spouwlat: n.v.t.; Vensterbank: n.v.t.; Ventilatierooster: n.v.t.; Zonwering - behuizing: n.v.t.; Zonwering - isolatie: n.v.t.; Glas: Glas - algemeen
Pset_WindowCommon - FireRating: n.v.t.; SecurityRating: FALSE; ThermalTransmittance: 0; GlazingAreaFraction: 2.40378; SmokeStop: no; IsExternal: yes
CPset_Phasing - Renovation Phase: Nieuw

# IfcWindow: R1 26, _Merk-053
In: 2e verdieping N
Type - OperationType: SINGLE_PANEL; ParameterTakesPrecedence: no; Sizeable: no
Type - Window Lining Properties - LiningDepth: 114 mm; LiningThickness: 90 mm
Type - Window Panel Properties - Panel 1 - OperationType: FIXEDCASEMENT; PanelPosition: MIDDLE
OverallHeight: 600 mm; OverallWidth: 2795.58 mm
Pset_WindowCommon - FireRating: n.v.t.; SecurityRating: FALSE; ThermalTransmittance: 0; GlazingAreaFraction: 1.09854; SmokeStop: no; IsExternal: yes
Material - Afwerking dagkant binnen: n.v.t.; Afwerking dagkant buiten: n.v.t.; Draaiend deel: n.v.t.; Frame: n.v.t.; Onderdorpel: n.v.t.; Rollaag / latei: n.v.t.; Spouwlat: n.v.t.; Vensterbank: n.v.t.; Ventilatierooster: n.v.t.; Zonwering - behuizing: n.v.t.; Zonwering - isolatie: n.v.t.; Glas: Glas - algemeen
CPset_Phasing - Renovation Phase: Nieuw

# IfcWindow: R1 26 (20)
Type - OperationType: SINGLE_PANEL; ParameterTakesPrecedence: no; Sizeable: no
Type - Window Lining Properties - LiningDepth: 20 mm; LiningThickness: 30 mm
Type - Window Panel Properties - Panel 1 - OperationType: FIXEDCASEMENT; PanelPosition: MIDDLE
OverallHeight: 2400 mm
Pset_WindowCommon - FireRating: n.v.t.; SecurityRating: FALSE; ThermalTransmittance: 0; SmokeStop: no; IsExternal: yes
Material - Zonwering - behuizing: n.v.t.; Afwerking dagkant binnen: n.v.t.; Afwerking dagkant buiten: n.v.t.; Draaiend deel: n.v.t.; Frame: n.v.t.; Onderdorpel: n.v.t.; Rollaag / latei: n.v.t.; Spouwlat: n.v.t.; Vensterbank: n.v.t.; Ventilatierooster: n.v.t.; Zonwering - isolatie: n.v.t.; Glas: Glas - algemeen
Name | In | OverallWidth (mm) | GlazingAreaFraction | Renovation Phase
2 x _Merk-002 | Begane grond N | 730 | 1.5678 | Nieuw
_Merk-002 | Begane grond N | 685 | 1.4625 | Nieuw
2 x _Merk-002 | Begane grond N | 940 | 2.0592 | Nieuw
_Merk-002 | Begane grond N | 520 | 1.0764 | Nieuw
2 x _Merk-002 | 1e verdieping N | 940 | 2.0592 | Nieuw
2 x _Merk-002 | 1e verdieping N | 730 | 1.5678 | Nieuw
2 x _Merk-002 | 1e verdieping N | 685 | 1.4625 | Nieuw
_Merk-002 | 1e verdieping N | 3344.51 | 7.68576 | Nieuw
2 x _Merk-002 | 2e verdieping N | 730 | 1.5678 | Nieuw
_Merk-002 | 2e verdieping N | 940 | 2.0592 | Bestaand
2 x _Merk-002 | 2e verdieping N | 685 | 1.4625 | Bestaand
_Merk-002 | 2e verdieping N | 940 | 2.0592 | Nieuw
_Merk-002 | 2e verdieping N | 3344.51 | 7.68576 | Nieuw

# IfcWindow: R1 27 (4)
Type - OperationType: DOUBLE_PANEL_HORIZONTAL; ParameterTakesPrecedence: no; Sizeable: no
Type - Window Lining Properties - LiningDepth: 114 mm; LiningThickness: 67 mm; TransomThickness: 67 mm; FirstTransomOffset: 0.205882
Type - Window Panel Properties - Panel 1 - OperationType: TILTANDTURNRIGHTHAND; PanelPosition: TOP; FrameDepth: 54 mm; FrameThickness: 67 mm
Type - Window Panel Properties - Panel 2 - OperationType: FIXEDCASEMENT; PanelPosition: BOTTOM
OverallHeight: 1700 mm; OverallWidth: 1341 mm
Pset_WindowCommon - FireRating: n.v.t.; SecurityRating: FALSE; ThermalTransmittance: 0; GlazingAreaFraction: 1.57364; SmokeStop: no; IsExternal: yes
Material - Afwerking dagkant binnen: n.v.t.; Afwerking dagkant buiten: n.v.t.; Draaiend deel: n.v.t.; Frame: n.v.t.; Onderdorpel: n.v.t.; Rollaag / latei: n.v.t.; Spouwlat: n.v.t.; Vensterbank: n.v.t.; Ventilatierooster: n.v.t.; Zonwering - behuizing: n.v.t.; Zonwering - isolatie: n.v.t.; Glas: Glas - algemeen
CPset_Phasing - Renovation Phase: Bestaand
Name | In
_Merk-x | 2e verdieping V
_Merk-x | 3e verdieping V
_Merk-x | 4e verdieping V
_Merk-x | 5e verdieping V

# IfcWindow: R1 27, _Merk-x
In: 2e verdieping N
Type - OperationType: DOUBLE_PANEL_HORIZONTAL; ParameterTakesPrecedence: no; Sizeable: no
Type - Window Lining Properties - LiningDepth: 114 mm; LiningThickness: 67 mm; TransomThickness: 67 mm; FirstTransomOffset: 0.444444
Type - Window Panel Properties - Panel 1 - OperationType: FIXEDCASEMENT; PanelPosition: TOP
Type - Window Panel Properties - Panel 2 - OperationType: FIXEDCASEMENT; PanelPosition: BOTTOM
OverallHeight: 3600 mm; OverallWidth: 1000 mm
Pset_WindowCommon - FireRating: n.v.t.; SecurityRating: FALSE; ThermalTransmittance: 0; GlazingAreaFraction: 1.64497; SmokeStop: no; IsExternal: yes
Material - Afwerking dagkant binnen: n.v.t.; Afwerking dagkant buiten: n.v.t.; Draaiend deel: n.v.t.; Frame: n.v.t.; Onderdorpel: n.v.t.; Rollaag / latei: n.v.t.; Spouwlat: n.v.t.; Vensterbank: n.v.t.; Ventilatierooster: n.v.t.; Zonwering - behuizing: n.v.t.; Zonwering - isolatie: n.v.t.; Glas: Glas - algemeen
CPset_Phasing - Renovation Phase: Bestaand

# IfcWindow: R1 27, _Merk-x
In: 1e verdieping N
Type - OperationType: DOUBLE_PANEL_HORIZONTAL; ParameterTakesPrecedence: no; Sizeable: no
Type - Window Lining Properties - LiningDepth: 114 mm; LiningThickness: 67 mm; TransomThickness: 67 mm; FirstTransomOffset: 0.457143
Type - Window Panel Properties - Panel 1 - OperationType: FIXEDCASEMENT; PanelPosition: TOP
Type - Window Panel Properties - Panel 2 - OperationType: FIXEDCASEMENT; PanelPosition: BOTTOM
OverallHeight: 3500 mm; OverallWidth: 1000 mm
Pset_WindowCommon - FireRating: n.v.t.; SecurityRating: FALSE; ThermalTransmittance: 0; GlazingAreaFraction: 1.55837; SmokeStop: no; IsExternal: yes
Material - Afwerking dagkant binnen: n.v.t.; Afwerking dagkant buiten: n.v.t.; Draaiend deel: n.v.t.; Frame: n.v.t.; Onderdorpel: n.v.t.; Rollaag / latei: n.v.t.; Spouwlat: n.v.t.; Vensterbank: n.v.t.; Ventilatierooster: n.v.t.; Zonwering - behuizing: n.v.t.; Zonwering - isolatie: n.v.t.; Glas: Glas - algemeen
CPset_Phasing - Renovation Phase: Bestaand

# IfcWindow: R1 27 (4)
Type - OperationType: DOUBLE_PANEL_HORIZONTAL; ParameterTakesPrecedence: no; Sizeable: no
Type - Window Lining Properties - LiningDepth: 114 mm; LiningThickness: 67 mm; TransomThickness: 67 mm; FirstTransomOffset: 0.84
Type - Window Panel Properties - Panel 1 - OperationType: FIXEDCASEMENT; PanelPosition: TOP
Type - Window Panel Properties - Panel 2 - OperationType: SIDEHUNGLEFTHAND; PanelPosition: BOTTOM; FrameDepth: 54 mm; FrameThickness: 67 mm
OverallHeight: 2500 mm
Pset_WindowCommon - FireRating: n.v.t.; SecurityRating: FALSE; ThermalTransmittance: 0; SmokeStop: no; IsExternal: yes
Material - Afwerking dagkant binnen: n.v.t.; Afwerking dagkant buiten: n.v.t.; Draaiend deel: n.v.t.; Frame: n.v.t.; Onderdorpel: n.v.t.; Rollaag / latei: n.v.t.; Spouwlat: n.v.t.; Vensterbank: n.v.t.; Ventilatierooster: n.v.t.; Zonwering - behuizing: n.v.t.; Zonwering - isolatie: n.v.t.; Glas: Glas - algemeen
CPset_Phasing - Renovation Phase: Bestaand
Name | In | OverallWidth (mm) | GlazingAreaFraction
_Merk-x | 2e verdieping V | 996.511 | 1.70671
_Merk-x | 3e verdieping V | 996.511 | 1.70671
_Merk-x | 4e verdieping V | 1000 | 1.71438
_Merk-x | 5e verdieping V | 996.511 | 1.70671

# IfcWindow: R1 27 (4)
Type - OperationType: DOUBLE_PANEL_HORIZONTAL; ParameterTakesPrecedence: no; Sizeable: no
Type - Window Lining Properties - LiningDepth: 114 mm; LiningThickness: 67 mm; TransomThickness: 67 mm; FirstTransomOffset: 0.84
Type - Window Panel Properties - Panel 1 - OperationType: FIXEDCASEMENT; PanelPosition: TOP
Type - Window Panel Properties - Panel 2 - OperationType: SIDEHUNGRIGHTHAND; PanelPosition: BOTTOM; FrameDepth: 54 mm; FrameThickness: 67 mm
OverallHeight: 2500 mm; OverallWidth: 1000 mm
Material - Afwerking dagkant binnen: n.v.t.; Afwerking dagkant buiten: n.v.t.; Draaiend deel: n.v.t.; Frame: n.v.t.; Onderdorpel: n.v.t.; Rollaag / latei: n.v.t.; Spouwlat: n.v.t.; Vensterbank: n.v.t.; Ventilatierooster: n.v.t.; Zonwering - behuizing: n.v.t.; Zonwering - isolatie: n.v.t.; Glas: Glas - algemeen
Pset_WindowCommon - FireRating: n.v.t.; SecurityRating: FALSE; ThermalTransmittance: 0; GlazingAreaFraction: 1.71438; SmokeStop: no; IsExternal: yes
CPset_Phasing - Renovation Phase: Bestaand
Name | In
_Merk-x | 2e verdieping V
_Merk-x | 3e verdieping V
_Merk-x | 4e verdieping V
_Merk-x | 5e verdieping V

# IfcWindow: R1 27 (16)
Type - OperationType: SINGLE_PANEL; ParameterTakesPrecedence: no; Sizeable: no
Type - Window Lining Properties - LiningDepth: 114 mm; LiningThickness: 67 mm
Type - Window Panel Properties - Panel 1 - OperationType: FIXEDCASEMENT; PanelPosition: MIDDLE
Pset_WindowCommon - FireRating: n.v.t.; SecurityRating: FALSE; ThermalTransmittance: 0; SmokeStop: no; IsExternal: yes
Material - Afwerking dagkant binnen: n.v.t.; Afwerking dagkant buiten: n.v.t.; Draaiend deel: n.v.t.; Frame: n.v.t.; Onderdorpel: n.v.t.; Rollaag / latei: n.v.t.; Spouwlat: n.v.t.; Vensterbank: n.v.t.; Ventilatierooster: n.v.t.; Zonwering - behuizing: n.v.t.; Zonwering - isolatie: n.v.t.; Glas: Glas - algemeen
Name | In | OverallHeight (mm) | OverallWidth (mm) | GlazingAreaFraction | Renovation Phase
_Merk-x | 1e verdieping N | 1500 | 800 | 0.909756 | Nieuw | Pset_FireRatingProperties - FireResistanceRating: 60 minuten brandwerend
_Merk-x | 2e verdieping V | 500 | 1650 | 0.554856 | Bestaand
2 x _Merk-x | 2e verdieping V | 438.223 | 1566.82 | 0.435898 | Bestaand
_Merk-x | 3e verdieping V | 800 | 1790 | 1.1029 | Bestaand
2 x _Merk-x | 3e verdieping V | 438.223 | 1566.82 | 0.435898 | Bestaand
_Merk-x | 3e verdieping V | 500 | 1650 | 0.554856 | Bestaand
_Merk-x | 4e verdieping V | 800 | 1790 | 1.1029 | Bestaand
_Merk-x | 4e verdieping V | 500 | 1650 | 0.554856 | Bestaand
2 x _Merk-x | 4e verdieping V | 438.223 | 1565 | 0.435343 | Bestaand
_Merk-x | 5e verdieping V | 800 | 1790 | 1.1029 | Bestaand
_Merk-x | 5e verdieping V | 500 | 1650 | 0.554856 | Bestaand
2 x _Merk-x | 5e verdieping V | 438.223 | 1566.82 | 0.435898 | Bestaand

# IfcWindow: R1 27, _Merk-
In: Begane grond N
Type - OperationType: SINGLE_PANEL; ParameterTakesPrecedence: no; Sizeable: no
Type - Window Lining Properties - LiningDepth: 114 mm; LiningThickness: 67 mm
Type - Window Panel Properties - Panel 1 - OperationType: SIDEHUNGLEFTHAND; PanelPosition: MIDDLE; FrameDepth: 54 mm; FrameThickness: 67 mm
OverallHeight: 1700 mm; OverallWidth: 800 mm
Pset_WindowCommon - FireRating: n.v.t.; SecurityRating: FALSE; ThermalTransmittance: 0; GlazingAreaFraction: 0.829756; SmokeStop: no; IsExternal: yes
Material - Afwerking dagkant binnen: n.v.t.; Afwerking dagkant buiten: n.v.t.; Draaiend deel: n.v.t.; Frame: n.v.t.; Onderdorpel: n.v.t.; Rollaag / latei: n.v.t.; Spouwlat: n.v.t.; Vensterbank: n.v.t.; Ventilatierooster: n.v.t.; Zonwering - behuizing: n.v.t.; Zonwering - isolatie: n.v.t.; Glas: Glas - algemeen
CPset_Phasing - Renovation Phase: Bestaand

# IfcWindow: R2 bl ol 26 (2)
In: 2e verdieping N
Type - OperationType: DOUBLE_PANEL_VERTICAL; ParameterTakesPrecedence: no; Sizeable: no
Type - Window Lining Properties - LiningDepth: 114 mm; LiningThickness: 67 mm; MullionThickness: 67 mm; FirstMullionOffset: 0.5
Type - Window Panel Properties - Panel 1 - OperationType: FIXEDCASEMENT; PanelPosition: LEFT
Type - Window Panel Properties - Panel 2 - OperationType: FIXEDCASEMENT; PanelPosition: RIGHT
OverallHeight: 1720 mm
Pset_WindowCommon - FireRating: n.v.t.; SecurityRating: FALSE; ThermalTransmittance: 0; SmokeStop: no; IsExternal: yes
Material - Afwerking dagkant binnen: n.v.t.; Afwerking dagkant buiten: n.v.t.; Draaiend deel: n.v.t.; Frame: n.v.t.; Onderdorpel: n.v.t.; Rollaag / latei: n.v.t.; Spouwlat: n.v.t.; Vensterbank: n.v.t.; Ventilatierooster: n.v.t.; Zonwering - behuizing: n.v.t.; Zonwering - isolatie: n.v.t.; Glas: Glas - algemeen
CPset_Phasing - Renovation Phase: Nieuw
Name | OverallWidth (mm) | GlazingAreaFraction
_Merk-050 | 1545 | 2.13158 | Pset_FireRatingProperties - FireResistanceRating: 30 minuten brandwerend
_Merk-049 | 1800 | 2.53601

# IfcWindow: R2 bl ol 26 (2)
Type - OperationType: DOUBLE_PANEL_VERTICAL; ParameterTakesPrecedence: no; Sizeable: no
Type - Window Lining Properties - LiningDepth: 114 mm; LiningThickness: 67 mm; MullionThickness: 67 mm; FirstMullionOffset: 0.5
Type - Window Panel Properties - Panel 1 - OperationType: FIXEDCASEMENT; PanelPosition: RIGHT
Type - Window Panel Properties - Panel 2 - OperationType: FIXEDCASEMENT; PanelPosition: LEFT
OverallWidth: 1545 mm
Material - Afwerking dagkant binnen: n.v.t.; Afwerking dagkant buiten: n.v.t.; Draaiend deel: n.v.t.; Frame: n.v.t.; Onderdorpel: n.v.t.; Rollaag / latei: n.v.t.; Spouwlat: n.v.t.; Vensterbank: n.v.t.; Ventilatierooster: n.v.t.; Zonwering - behuizing: n.v.t.; Zonwering - isolatie: n.v.t.; Glas: Glas - algemeen
CPset_Phasing - Renovation Phase: Nieuw
Pset_WindowCommon - FireRating: n.v.t.; SecurityRating: FALSE; ThermalTransmittance: 0; SmokeStop: no; IsExternal: yes
Name | In | OverallHeight (mm) | GlazingAreaFraction
_Merk-004 | Begane grond N | 1700.5 | 2.10538
_Merk-036 | 1e verdieping N | 1657 | 2.04691

# IfcWindow: R2 bl ol 26, _Merk-051
In: 2e verdieping N
Type - OperationType: DOUBLE_PANEL_VERTICAL; ParameterTakesPrecedence: no; Sizeable: no
Type - Window Lining Properties - LiningDepth: 114 mm; LiningThickness: 67 mm; MullionThickness: 67 mm; FirstMullionOffset: 0.5
Type - Window Panel Properties - Panel 1 - OperationType: TILTANDTURNLEFTHAND; PanelPosition: RIGHT; FrameDepth: 54 mm; FrameThickness: 67 mm
Type - Window Panel Properties - Panel 2 - OperationType: TILTANDTURNRIGHTHAND; PanelPosition: LEFT; FrameDepth: 54 mm; FrameThickness: 67 mm
OverallHeight: 1720 mm; OverallWidth: 1663.68 mm
Pset_WindowCommon - FireRating: n.v.t.; SecurityRating: FALSE; ThermalTransmittance: 0; GlazingAreaFraction: 1.87634; SmokeStop: no; IsExternal: yes
Material - Afwerking dagkant binnen: n.v.t.; Afwerking dagkant buiten: n.v.t.; Draaiend deel: n.v.t.; Frame: n.v.t.; Onderdorpel: n.v.t.; Rollaag / latei: n.v.t.; Spouwlat: n.v.t.; Vensterbank: n.v.t.; Ventilatierooster: n.v.t.; Zonwering - behuizing: n.v.t.; Zonwering - isolatie: n.v.t.; Glas: Glas - algemeen
CPset_Phasing - Renovation Phase: Nieuw

# IfcWindow: R2 bl ol 26, _Merk-035
In: 1e verdieping N
Type - OperationType: TRIPLE_PANEL_TOP; ParameterTakesPrecedence: no; Sizeable: no
Type - Window Lining Properties - LiningDepth: 114 mm; LiningThickness: 67 mm; TransomThickness: 67 mm; MullionThickness: 67 mm; FirstTransomOffset: 0.745074; FirstMullionOffset: 0.5
Type - Window Panel Properties - Panel 1 - OperationType: FIXEDCASEMENT; PanelPosition: LEFT
Type - Window Panel Properties - Panel 2 - OperationType: FIXEDCASEMENT; PanelPosition: RIGHT
Type - Window Panel Properties - Panel 3 - OperationType: FIXEDCASEMENT; PanelPosition: TOP
OverallHeight: 3400 mm; OverallWidth: 1795 mm
CPset_Phasing - Renovation Phase: Nieuw
Material - Afwerking dagkant binnen: n.v.t.; Afwerking dagkant buiten: n.v.t.; Draaiend deel: n.v.t.; Frame: n.v.t.; Onderdorpel: n.v.t.; Rollaag / latei: n.v.t.; Spouwlat: n.v.t.; Vensterbank: n.v.t.; Ventilatierooster: n.v.t.; Zonwering - behuizing: n.v.t.; Zonwering - isolatie: n.v.t.; Glas: Glas - algemeen
Pset_WindowCommon - FireRating: n.v.t.; SecurityRating: FALSE; ThermalTransmittance: 0; GlazingAreaFraction: 1.27274; SmokeStop: no; IsExternal: yes

# IfcWindow: R2 bl ol 26, _Merk-035
In: 1e verdieping N
Type - OperationType: TRIPLE_PANEL_TOP; ParameterTakesPrecedence: no; Sizeable: no
Type - Window Lining Properties - LiningDepth: 114 mm; LiningThickness: 67 mm; TransomThickness: 67 mm; MullionThickness: 67 mm; FirstTransomOffset: 0.745074; FirstMullionOffset: 0.5
Type - Window Panel Properties - Panel 1 - OperationType: FIXEDCASEMENT; PanelPosition: RIGHT
Type - Window Panel Properties - Panel 2 - OperationType: FIXEDCASEMENT; PanelPosition: LEFT
Type - Window Panel Properties - Panel 3 - OperationType: FIXEDCASEMENT; PanelPosition: TOP
OverallHeight: 3400 mm; OverallWidth: 1795 mm
Pset_WindowCommon - FireRating: n.v.t.; SecurityRating: FALSE; ThermalTransmittance: 0; GlazingAreaFraction: 1.27274; SmokeStop: no; IsExternal: yes
Material - Afwerking dagkant binnen: n.v.t.; Afwerking dagkant buiten: n.v.t.; Draaiend deel: n.v.t.; Frame: n.v.t.; Onderdorpel: n.v.t.; Rollaag / latei: n.v.t.; Spouwlat: n.v.t.; Vensterbank: n.v.t.; Ventilatierooster: n.v.t.; Zonwering - behuizing: n.v.t.; Zonwering - isolatie: n.v.t.; Glas: Glas - algemeen
CPset_Phasing - Renovation Phase: Nieuw

# IfcWindow: R2 bl ol 26 (61)
Type - OperationType: USERDEFINED; ParameterTakesPrecedence: no; Sizeable: no
Pset_WindowCommon - FireRating: n.v.t.; SecurityRating: FALSE; ThermalTransmittance: 0; SmokeStop: no; IsExternal: yes
Material - Afwerking dagkant binnen: n.v.t.; Afwerking dagkant buiten: n.v.t.; Draaiend deel: n.v.t.; Frame: n.v.t.; Onderdorpel: n.v.t.; Rollaag / latei: n.v.t.; Spouwlat: n.v.t.; Vensterbank: n.v.t.; Ventilatierooster: n.v.t.; Zonwering - behuizing: n.v.t.; Zonwering - isolatie: n.v.t.; Glas: Glas - algemeen
CPset_Phasing - Renovation Phase: Nieuw
Name | In | OverallHeight (mm) | OverallWidth (mm) | GlazingAreaFraction
8 x _Merk-006 | Begane grond N | 3090 | 1662.5 | 2.92472
2 x _Merk-005 | Begane grond N | 3090 | 1800 | 2.90959
8 x _Merk-006sp | Begane grond N | 3090 | 1662.5 | 2.92472
_Merk-006A | Begane grond N | 3090 | 1662.5 | 3.14847 | Pset_FireRatingProperties - FireResistanceRating: 30 minuten brandwerend
_Merk-006sp | Begane grond N | 3090 | 1662.5 | 2.91972
_Merk-012 | Begane grond N | 3090 | 1740.07 | 3.31184
_Merk-012 | Begane grond N | 3090 | 1706.57 | 3.31184
_Merk-014sp | Begane grond N | 3090 | 1662.54 | 2.85593
_Merk-013sp | Begane grond N | 3090 | 1535 | 2.66258
2 x _Merk-014 | Begane grond N | 3090 | 1662.54 | 2.9248
_Merk-013 | Begane grond N | 3090 | 1535 | 2.66258
_Merk-005 | Begane grond N | 3090 | 1800 | 2.91429
_Merk-042 | 1e verdieping N | 3500 | 1800 | 2.43528
_Merk-043 | 1e verdieping N | 3500 | 1535 | 1.87203
4 x _Merk-044 | 1e verdieping N | 3500 | 1662.5 | 2.05984
_Merk-43sp | 1e verdieping N | 3500 | 1535 | 1.87203
4 x _Merk-044sp | 1e verdieping N | 3500 | 1662.5 | 2.05984
2 x _Merk-044 | 1e verdieping N | 3500 | 1662.54 | 2.05989
_Merk-046 | 1e verdieping N | 3500 | 1662.5 | 2.01049
_Merk-020 | 1e verdieping N | 2440 | 1662.51 | 2.05985
_Merk-021 | 1e verdieping N | 2440 | 1800 | 2.43528 | Pset_FireRatingProperties - FireResistanceRating: 30 minuten brandwerend
2 x _Merk-020 | 1e verdieping N | 2440 | 1662.5 | 2.05984
_Merk-020sp | 1e verdieping N | 2440 | 1662.51 | 2.05985
2 x _Merk-020sp | 1e verdieping N | 2440 | 1662.5 | 2.05984
_Merk-042 | 1e verdieping N | 3500 | 1706.57 | 2.39503
_Merk-042 | 1e verdieping N | 3500 | 1740.07 | 2.39503
3 x _Merk-037 | 1e verdieping N | 3500 | 1800 | 1.99078
3 x _Merk-051 | 2e verdieping N | 3500 | 1800 | 2.07891
_Merk-057 | 2e verdieping N | 3500 | 1706.57 | 2.4941
_Merk-057 | 2e verdieping N | 3500 | 1740.07 | 2.4941
_Merk-058sp | 2e verdieping N | 3500 | 1535.04 | 1.95194
_Merk-058 | 2e verdieping N | 3500 | 1535 | 1.95188

# IfcWindow: R2 bl ol 27 (12)
In: 2e verdieping N
Type - OperationType: DOUBLE_PANEL_VERTICAL; ParameterTakesPrecedence: no; Sizeable: no
Type - Window Lining Properties - LiningDepth: 114 mm; LiningThickness: 67 mm; MullionThickness: 67 mm; FirstMullionOffset: 0.28125
Type - Window Panel Properties - Panel 1 - OperationType: FIXEDCASEMENT; PanelPosition: RIGHT
Type - Window Panel Properties - Panel 2 - OperationType: TILTANDTURNRIGHTHAND; PanelPosition: LEFT; FrameDepth: 54 mm; FrameThickness: 67 mm
OverallHeight: 2550 mm; OverallWidth: 3200 mm
Pset_WindowCommon - FireRating: n.v.t.; SecurityRating: FALSE; ThermalTransmittance: 0; GlazingAreaFraction: 6.93403; SmokeStop: no; IsExternal: yes
Material - Afwerking dagkant binnen: n.v.t.; Afwerking dagkant buiten: n.v.t.; Draaiend deel: n.v.t.; Frame: n.v.t.; Onderdorpel: n.v.t.; Rollaag / latei: n.v.t.; Spouwlat: n.v.t.; Vensterbank: n.v.t.; Ventilatierooster: n.v.t.; Zonwering - behuizing: n.v.t.; Zonwering - isolatie: n.v.t.; Glas: Glas - algemeen
CPset_Phasing - Renovation Phase: Bestaand

# IfcWindow: R2 bl ol 27, _Merk-048
In: 2e verdieping N
Type - OperationType: DOUBLE_PANEL_VERTICAL; ParameterTakesPrecedence: no; Sizeable: no
Type - Window Lining Properties - LiningDepth: 114 mm; LiningThickness: 67 mm; MullionThickness: 67 mm; FirstMullionOffset: 0.5
Type - Window Panel Properties - Panel 1 - OperationType: FIXEDCASEMENT; PanelPosition: LEFT
Type - Window Panel Properties - Panel 2 - OperationType: FIXEDCASEMENT; PanelPosition: RIGHT
OverallHeight: 550 mm; OverallWidth: 1545 mm
Material - Afwerking dagkant binnen: n.v.t.; Afwerking dagkant buiten: n.v.t.; Draaiend deel: n.v.t.; Frame: n.v.t.; Onderdorpel: n.v.t.; Rollaag / latei: n.v.t.; Spouwlat: n.v.t.; Vensterbank: n.v.t.; Ventilatierooster: n.v.t.; Zonwering - behuizing: n.v.t.; Zonwering - isolatie: n.v.t.; Glas: Glas - algemeen
Pset_WindowCommon - FireRating: n.v.t.; SecurityRating: FALSE; ThermalTransmittance: 0; GlazingAreaFraction: 0.559104; SmokeStop: no; IsExternal: yes
CPset_Phasing - Renovation Phase: Nieuw
Pset_FireRatingProperties - FireResistanceRating: 30 minuten brandwerend

# IfcWindow: R2 bl ol 27 (12)
In: 2e verdieping N
Type - OperationType: DOUBLE_PANEL_VERTICAL; ParameterTakesPrecedence: no; Sizeable: no
Type - Window Lining Properties - LiningDepth: 114 mm; LiningThickness: 67 mm; MullionThickness: 67 mm; FirstMullionOffset: 0.71875
Type - Window Panel Properties - Panel 1 - OperationType: FIXEDCASEMENT; PanelPosition: LEFT
Type - Window Panel Properties - Panel 2 - OperationType: TILTANDTURNLEFTHAND; PanelPosition: RIGHT; FrameDepth: 54 mm; FrameThickness: 67 mm
OverallHeight: 2550 mm; OverallWidth: 3200 mm
Pset_WindowCommon - FireRating: n.v.t.; SecurityRating: FALSE; ThermalTransmittance: 0; GlazingAreaFraction: 6.93403; SmokeStop: no; IsExternal: yes
CPset_Phasing - Renovation Phase: Bestaand
Material - Afwerking dagkant binnen: n.v.t.; Afwerking dagkant buiten: n.v.t.; Draaiend deel: n.v.t.; Frame: n.v.t.; Onderdorpel: n.v.t.; Rollaag / latei: n.v.t.; Spouwlat: n.v.t.; Vensterbank: n.v.t.; Ventilatierooster: n.v.t.; Zonwering - behuizing: n.v.t.; Zonwering - isolatie: n.v.t.; Glas: Glas - algemeen

# IfcWindow: R2 bl ol 27 (11)
In: 1e verdieping N
Type - OperationType: TRIPLE_PANEL_BOTTOM; ParameterTakesPrecedence: no; Sizeable: no
Type - Window Lining Properties - LiningDepth: 114 mm; LiningThickness: 67 mm; TransomThickness: 67 mm; MullionThickness: 67 mm; FirstTransomOffset: 0.254902; FirstMullionOffset: 0.28125
Type - Window Panel Properties - Panel 1 - OperationType: FIXEDCASEMENT; PanelPosition: RIGHT
Type - Window Panel Properties - Panel 2 - OperationType: TILTANDTURNRIGHTHAND; PanelPosition: LEFT; FrameDepth: 54 mm; FrameThickness: 67 mm
Type - Window Panel Properties - Panel 3 - OperationType: FIXEDCASEMENT; PanelPosition: BOTTOM
OverallHeight: 2550 mm; OverallWidth: 3200 mm
Pset_WindowCommon - FireRating: n.v.t.; SecurityRating: FALSE; ThermalTransmittance: 0; GlazingAreaFraction: 5.1468; SmokeStop: no; IsExternal: yes
CPset_Phasing - Renovation Phase: Bestaand
Material - Afwerking dagkant binnen: n.v.t.; Afwerking dagkant buiten: n.v.t.; Draaiend deel: n.v.t.; Frame: n.v.t.; Onderdorpel: n.v.t.; Rollaag / latei: n.v.t.; Spouwlat: n.v.t.; Vensterbank: n.v.t.; Ventilatierooster: n.v.t.; Zonwering - behuizing: n.v.t.; Zonwering - isolatie: n.v.t.; Glas: Glas - algemeen

# IfcWindow: R2 bl ol 27 (11)
In: 1e verdieping N
Type - OperationType: TRIPLE_PANEL_BOTTOM; ParameterTakesPrecedence: no; Sizeable: no
Type - Window Lining Properties - LiningDepth: 114 mm; LiningThickness: 67 mm; TransomThickness: 67 mm; MullionThickness: 67 mm; FirstTransomOffset: 0.254902; FirstMullionOffset: 0.71875
Type - Window Panel Properties - Panel 1 - OperationType: FIXEDCASEMENT; PanelPosition: LEFT
Type - Window Panel Properties - Panel 2 - OperationType: TILTANDTURNLEFTHAND; PanelPosition: RIGHT; FrameDepth: 54 mm; FrameThickness: 67 mm
Type - Window Panel Properties - Panel 3 - OperationType: FIXEDCASEMENT; PanelPosition: BOTTOM
OverallHeight: 2550 mm; OverallWidth: 3200 mm
Pset_WindowCommon - FireRating: n.v.t.; SecurityRating: FALSE; ThermalTransmittance: 0; GlazingAreaFraction: 5.1468; SmokeStop: no; IsExternal: yes
Material - Afwerking dagkant binnen: n.v.t.; Afwerking dagkant buiten: n.v.t.; Draaiend deel: n.v.t.; Frame: n.v.t.; Onderdorpel: n.v.t.; Rollaag / latei: n.v.t.; Spouwlat: n.v.t.; Vensterbank: n.v.t.; Ventilatierooster: n.v.t.; Zonwering - behuizing: n.v.t.; Zonwering - isolatie: n.v.t.; Glas: Glas - algemeen
CPset_Phasing - Renovation Phase: Bestaand

# IfcWindow: R2 bl ol 27 (80)
Type - OperationType: USERDEFINED; ParameterTakesPrecedence: no; Sizeable: no
OverallHeight: 1700 mm
Material - Afwerking dagkant binnen: n.v.t.; Afwerking dagkant buiten: n.v.t.; Draaiend deel: n.v.t.; Frame: n.v.t.; Onderdorpel: n.v.t.; Rollaag / latei: n.v.t.; Spouwlat: n.v.t.; Vensterbank: n.v.t.; Ventilatierooster: n.v.t.; Zonwering - behuizing: n.v.t.; Zonwering - isolatie: n.v.t.; Glas: Glas - algemeen
Pset_WindowCommon - FireRating: n.v.t.; SecurityRating: FALSE; ThermalTransmittance: 0; SmokeStop: no; IsExternal: yes
CPset_Phasing - Renovation Phase: Bestaand
Name | In | OverallWidth (mm) | GlazingAreaFraction
16 x _Merk-x | 2e verdieping V | 2515 | 3.23304
_Merk-x | 2e verdieping V | 2515.03 | 3.23308
20 x _Merk-x | 3e verdieping V | 2515 | 3.23304
_Merk-x | 3e verdieping V | 2515.03 | 3.23308
20 x _Merk-x | 4e verdieping V | 2515 | 3.23304
_Merk-x | 4e verdieping V | 2515.03 | 3.23308
20 x _Merk-x | 5e verdieping V | 2515 | 3.23304
_Merk-x | 5e verdieping V | 2515.03 | 3.23308

# IfcWindow: R3 bl ol 26 (11)
Type - OperationType: USERDEFINED; ParameterTakesPrecedence: no; Sizeable: no
Pset_WindowCommon - FireRating: n.v.t.; SecurityRating: FALSE; ThermalTransmittance: 0; SmokeStop: no; IsExternal: yes
CPset_Phasing - Renovation Phase: Nieuw
Material - Afwerking dagkant binnen: n.v.t.; Afwerking dagkant buiten: n.v.t.; Draaiend deel: n.v.t.; Frame: n.v.t.; Onderdorpel: n.v.t.; Rollaag / latei: n.v.t.; Spouwlat: n.v.t.; Vensterbank: n.v.t.; Ventilatierooster: n.v.t.; Zonwering - behuizing: n.v.t.; Zonwering - isolatie: n.v.t.; Glas: Glas - algemeen
Name | In | OverallHeight (mm) | OverallWidth (mm) | GlazingAreaFraction
_Merk-009 | Begane grond N | 3090 | 2355 | 3.98132
_Merk-010 | Begane grond N | 3090 | 2440 | 4.35283
_Merk-011 | Begane grond N | 3090 | 2593.36 | 4.74012
_Merk-015 | Begane grond N | 3090 | 2493.73 | 4.4642
_Merk-039 | 1e verdieping N | 3500 | 2355 | 2.75477
_Merk-045 | 1e verdieping N | 3500 | 2492.5 | 3.17146
_Merk-041 | 1e verdieping N | 3500 | 2593.36 | 3.42151
_Merk-040 | 1e verdieping N | 3500 | 2440 | 3.09326
_Merk-055 | 2e verdieping N | 3500 | 2440 | 3.44479 | Pset_FireRatingProperties - FireResistanceRating: 30 minuten brandwerend
_Merk-056 | 2e verdieping N | 3500 | 2593.36 | 3.51392
_Merk-054 | 2e verdieping N | 3500 | 2355 | 2.87365

# IfcWindow: RVS plaat1:RVS plaat, RVS plaat1:RVS plaat:2949023
In: 1e verdieping N
Type - ParameterTakesPrecedence: no; Sizeable: no
Material: Aluminum geanodiseerd RAL 7024
Pset_WindowCommon - Reference: RVS plaat; IsExternal: no
Pset_QuantityTakeOff - Reference: RVS plaat
CPset_Phasing - Renovation Phase: Nieuw
Material Properties - Aluminum geanodiseerd RAL 7024, ThermalConductivity: 2.3; Aluminum geanodiseerd RAL 7024, SpecificHeatCapacity: 1000 J/kg/K; Aluminum geanodiseerd RAL 7024, MassDensity: 2300 kg/m3; Aluminum geanodiseerd RAL 7024, Embodied Energy: 1.92 (MJ/kg); Aluminum geanodiseerd RAL 7024, Embodied Carbon: 0.198 (kgCO₂/kg); Aluminum geanodiseerd RAL 7024, Name: Aluminum geanodiseerd RAL 7024; Aluminum geanodiseerd RAL 7024, Participates in Collision Detection: yes

# IfcWindow: RVS plaat:RVS plaat, RVS plaat:RVS plaat:2744850
In: 1e verdieping N
Type - ParameterTakesPrecedence: no; Sizeable: no
Material: Aluminum geanodiseerd RAL 7024
Pset_QuantityTakeOff - Reference: RVS plaat
Pset_WindowCommon - Reference: RVS plaat; IsExternal: no
CPset_Phasing - Renovation Phase: Nieuw
Material Properties - Aluminum geanodiseerd RAL 7024, ThermalConductivity: 2.3; Aluminum geanodiseerd RAL 7024, SpecificHeatCapacity: 1000 J/kg/K; Aluminum geanodiseerd RAL 7024, MassDensity: 2300 kg/m3; Aluminum geanodiseerd RAL 7024, Embodied Energy: 1.92 (MJ/kg); Aluminum geanodiseerd RAL 7024, Embodied Carbon: 0.198 (kgCO₂/kg); Aluminum geanodiseerd RAL 7024, Name: Aluminum geanodiseerd RAL 7024; Aluminum geanodiseerd RAL 7024, Participates in Collision Detection: yes

# IfcWindow: Rnx horizontaal 26 (29)
Type - OperationType: USERDEFINED; ParameterTakesPrecedence: no; Sizeable: no
Material - Zonwering - behuizing: n.v.t.; Afwerking dagkant binnen: n.v.t.; Afwerking dagkant buiten: n.v.t.; Draaiend deel: n.v.t.; Frame: n.v.t.; Onderdorpel: n.v.t.; Rollaag / latei: n.v.t.; Spouwlat: n.v.t.; Vensterbank: n.v.t.; Ventilatierooster: n.v.t.; Zonwering - isolatie: n.v.t.; Glas: Glas - algemeen
CPset_Phasing - Renovation Phase: Nieuw
Pset_WindowCommon - FireRating: n.v.t.; SecurityRating: FALSE; ThermalTransmittance: 0; SmokeStop: no; IsExternal: yes
Name | In | OverallHeight (mm) | OverallWidth (mm) | GlazingAreaFraction
2 x _Merk-001 | Begane grond N | 1000 | 4900 | 3.66019
8 x _Merk-038 | 1e verdieping N | 1657 | 3325 | 4.10967
_Merk-038A | 1e verdieping N | 1657 | 3325 | 4.33172 | Pset_FireRatingProperties - FireResistanceRating: 30 minuten brandwerend
8 x _Merk-052 | 2e verdieping N | 1720 | 3325 | 4.28544
10 x _Merk-048 | 2e verdieping N | 1720 | 3325 | 4.28544

# IfcWindow: Rnx verticaal 26 (12)
In: 1e verdieping N
Type - OperationType: SINGLE_PANEL; ParameterTakesPrecedence: no; Sizeable: no
Type - Window Lining Properties - LiningDepth: 114 mm; LiningThickness: 33.5 mm
Type - Window Panel Properties - Panel 1 - OperationType: FIXEDCASEMENT; PanelPosition: MIDDLE
OverallHeight: 3400 mm
Material - Afwerking dagkant binnen: n.v.t.; Afwerking dagkant buiten: n.v.t.; Draaiend deel: n.v.t.; Frame: n.v.t.; Onderdorpel: n.v.t.; Rollaag / latei: n.v.t.; Spouwlat: n.v.t.; Vensterbank: n.v.t.; Ventilatierooster: n.v.t.; Zonwering - behuizing: n.v.t.; Zonwering - isolatie: n.v.t.; Glas: Glas - algemeen
Pset_WindowCommon - FireRating: n.v.t.; SecurityRating: FALSE; ThermalTransmittance: 0; SmokeStop: no; IsExternal: yes
CPset_Phasing - Renovation Phase: Nieuw
Name | OverallWidth (mm) | GlazingAreaFraction
2 x _Merk-032 | 1731 | 5.43462
8 x _Merk-027 | 1795 | 5.64365
_Merk-029sp | 1426 | 4.32908
_Merk-029 | 1426 | 4.32908

# IfcWindow: Rnx verticaal 26 (2)
In: 1e verdieping N
Type - OperationType: SINGLE_PANEL; ParameterTakesPrecedence: no; Sizeable: no
Type - Window Lining Properties - LiningDepth: 114 mm; LiningThickness: 67 mm
Type - Window Panel Properties - Panel 1 - OperationType: FIXEDCASEMENT; PanelPosition: MIDDLE
OverallHeight: 3400 mm; OverallWidth: 1600 mm
Pset_WindowCommon - FireRating: n.v.t.; SecurityRating: FALSE; ThermalTransmittance: 0; GlazingAreaFraction: 4.89737; SmokeStop: no; IsExternal: yes
Material - Afwerking dagkant binnen: n.v.t.; Afwerking dagkant buiten: n.v.t.; Draaiend deel: n.v.t.; Frame: n.v.t.; Onderdorpel: n.v.t.; Rollaag / latei: n.v.t.; Spouwlat: n.v.t.; Vensterbank: n.v.t.; Ventilatierooster: n.v.t.; Zonwering - behuizing: n.v.t.; Zonwering - isolatie: n.v.t.; Glas: Glas - algemeen
CPset_Phasing - Renovation Phase: Nieuw
Name
_Merk-030sp
_Merk-030

# IfcWindow: Rnx verticaal 27 (3)
In: 2e verdieping V
Type - OperationType: TRIPLE_PANEL_HORIZONTAL; ParameterTakesPrecedence: no; Sizeable: no
Type - Window Lining Properties - LiningDepth: 114 mm; LiningThickness: 33.5 mm; TransomThickness: 33.5 mm; FirstTransomOffset: 0.317048; SecondTransomOffset: 0.658524
Type - Window Panel Properties - Panel 1 - OperationType: FIXEDCASEMENT; PanelPosition: TOP
Type - Window Panel Properties - Panel 2 - OperationType: FIXEDCASEMENT; PanelPosition: MIDDLE
Type - Window Panel Properties - Panel 3 - OperationType: FIXEDCASEMENT; PanelPosition: BOTTOM
OverallHeight: 2680.98 mm; OverallWidth: 1270 mm
Pset_WindowCommon - FireRating: n.v.t.; SecurityRating: FALSE; ThermalTransmittance: 0; SmokeStop: no; IsExternal: yes
Material - Afwerking dagkant binnen: n.v.t.; Afwerking dagkant buiten: n.v.t.; Draaiend deel: n.v.t.; Frame: n.v.t.; Onderdorpel: n.v.t.; Rollaag / latei: n.v.t.; Spouwlat: n.v.t.; Vensterbank: n.v.t.; Ventilatierooster: n.v.t.; Zonwering - behuizing: n.v.t.; Zonwering - isolatie: n.v.t.; Glas: Glas - algemeen
CPset_Phasing - Renovation Phase: Bestaand
Name | GlazingAreaFraction
_Merk-x | 2.86116
2 x _Merk-x | 2.94312

# IfcWindow: Rnx verticaal 27 (3)
In: 3e verdieping V
Type - OperationType: TRIPLE_PANEL_HORIZONTAL; ParameterTakesPrecedence: no; Sizeable: no
Type - Window Lining Properties - LiningDepth: 114 mm; LiningThickness: 33.5 mm; TransomThickness: 33.5 mm; FirstTransomOffset: 0.33876; SecondTransomOffset: 0.66938
Type - Window Panel Properties - Panel 1 - OperationType: FIXEDCASEMENT; PanelPosition: TOP
Type - Window Panel Properties - Panel 2 - OperationType: FIXEDCASEMENT; PanelPosition: MIDDLE
Type - Window Panel Properties - Panel 3 - OperationType: FIXEDCASEMENT; PanelPosition: BOTTOM
OverallHeight: 2769.02 mm; OverallWidth: 1270 mm
Pset_WindowCommon - FireRating: n.v.t.; SecurityRating: FALSE; ThermalTransmittance: 0; SmokeStop: no; IsExternal: yes
CPset_Phasing - Renovation Phase: Bestaand
Material - Afwerking dagkant binnen: n.v.t.; Afwerking dagkant buiten: n.v.t.; Draaiend deel: n.v.t.; Frame: n.v.t.; Onderdorpel: n.v.t.; Rollaag / latei: n.v.t.; Spouwlat: n.v.t.; Vensterbank: n.v.t.; Ventilatierooster: n.v.t.; Zonwering - behuizing: n.v.t.; Zonwering - isolatie: n.v.t.; Glas: Glas - algemeen
Name | GlazingAreaFraction
_Merk-x | 3.0033
2 x _Merk-x | 3.08932

# IfcWindow: Rnx verticaal 27 (6)
Type - OperationType: TRIPLE_PANEL_HORIZONTAL; ParameterTakesPrecedence: no; Sizeable: no
Type - Window Lining Properties - LiningDepth: 114 mm; LiningThickness: 33.5 mm; TransomThickness: 33.5 mm; FirstTransomOffset: 0.338995; SecondTransomOffset: 0.669498
Type - Window Panel Properties - Panel 1 - OperationType: FIXEDCASEMENT; PanelPosition: TOP
Type - Window Panel Properties - Panel 2 - OperationType: FIXEDCASEMENT; PanelPosition: MIDDLE
Type - Window Panel Properties - Panel 3 - OperationType: FIXEDCASEMENT; PanelPosition: BOTTOM
OverallHeight: 2770 mm; OverallWidth: 1270 mm
Pset_WindowCommon - FireRating: n.v.t.; SecurityRating: FALSE; ThermalTransmittance: 0; SmokeStop: no; IsExternal: yes
Material - Afwerking dagkant binnen: n.v.t.; Afwerking dagkant buiten: n.v.t.; Draaiend deel: n.v.t.; Frame: n.v.t.; Onderdorpel: n.v.t.; Rollaag / latei: n.v.t.; Spouwlat: n.v.t.; Vensterbank: n.v.t.; Ventilatierooster: n.v.t.; Zonwering - behuizing: n.v.t.; Zonwering - isolatie: n.v.t.; Glas: Glas - algemeen
CPset_Phasing - Renovation Phase: Bestaand
Name | In | GlazingAreaFraction
_Merk-x | 4e verdieping V | 3.00445
2 x _Merk-x | 4e verdieping V | 3.09051
_Merk-x | 5e verdieping V | 2.96527
2 x _Merk-x | 5e verdieping V | 3.05021

# IfcWindow: Rnx verticaal 27, _Merk-x
In: 2e verdieping V
Type - OperationType: TRIPLE_PANEL_HORIZONTAL; ParameterTakesPrecedence: no; Sizeable: no
Type - Window Lining Properties - LiningDepth: 114 mm; LiningThickness: 67 mm; TransomThickness: 67 mm; FirstTransomOffset: 0.317048; SecondTransomOffset: 0.658524
Type - Window Panel Properties - Panel 1 - OperationType: FIXEDCASEMENT; PanelPosition: TOP
Type - Window Panel Properties - Panel 2 - OperationType: FIXEDCASEMENT; PanelPosition: MIDDLE
Type - Window Panel Properties - Panel 3 - OperationType: FIXEDCASEMENT; PanelPosition: BOTTOM
OverallHeight: 2680.98 mm; OverallWidth: 1270 mm
Pset_WindowCommon - FireRating: n.v.t.; SecurityRating: FALSE; ThermalTransmittance: 0; GlazingAreaFraction: 2.86116; SmokeStop: no; IsExternal: yes
Material - Afwerking dagkant binnen: n.v.t.; Afwerking dagkant buiten: n.v.t.; Draaiend deel: n.v.t.; Frame: n.v.t.; Onderdorpel: n.v.t.; Rollaag / latei: n.v.t.; Spouwlat: n.v.t.; Vensterbank: n.v.t.; Ventilatierooster: n.v.t.; Zonwering - behuizing: n.v.t.; Zonwering - isolatie: n.v.t.; Glas: Glas - algemeen
CPset_Phasing - Renovation Phase: Bestaand

# IfcWindow: Rnx verticaal 27, _Merk-x
In: 3e verdieping V
Type - OperationType: TRIPLE_PANEL_HORIZONTAL; ParameterTakesPrecedence: no; Sizeable: no
Type - Window Lining Properties - LiningDepth: 114 mm; LiningThickness: 67 mm; TransomThickness: 67 mm; FirstTransomOffset: 0.33876; SecondTransomOffset: 0.66938
Type - Window Panel Properties - Panel 1 - OperationType: FIXEDCASEMENT; PanelPosition: TOP
Type - Window Panel Properties - Panel 2 - OperationType: FIXEDCASEMENT; PanelPosition: MIDDLE
Type - Window Panel Properties - Panel 3 - OperationType: FIXEDCASEMENT; PanelPosition: BOTTOM
OverallHeight: 2769.02 mm; OverallWidth: 1270 mm
Pset_WindowCommon - FireRating: n.v.t.; SecurityRating: FALSE; ThermalTransmittance: 0; GlazingAreaFraction: 3.0033; SmokeStop: no; IsExternal: yes
Material - Afwerking dagkant binnen: n.v.t.; Afwerking dagkant buiten: n.v.t.; Draaiend deel: n.v.t.; Frame: n.v.t.; Onderdorpel: n.v.t.; Rollaag / latei: n.v.t.; Spouwlat: n.v.t.; Vensterbank: n.v.t.; Ventilatierooster: n.v.t.; Zonwering - behuizing: n.v.t.; Zonwering - isolatie: n.v.t.; Glas: Glas - algemeen
CPset_Phasing - Renovation Phase: Bestaand

# IfcWindow: Rnx verticaal 27 (2)
Type - OperationType: TRIPLE_PANEL_HORIZONTAL; ParameterTakesPrecedence: no; Sizeable: no
Type - Window Lining Properties - LiningDepth: 114 mm; LiningThickness: 67 mm; TransomThickness: 67 mm; FirstTransomOffset: 0.338995; SecondTransomOffset: 0.669498
Type - Window Panel Properties - Panel 1 - OperationType: FIXEDCASEMENT; PanelPosition: TOP
Type - Window Panel Properties - Panel 2 - OperationType: FIXEDCASEMENT; PanelPosition: MIDDLE
Type - Window Panel Properties - Panel 3 - OperationType: FIXEDCASEMENT; PanelPosition: BOTTOM
OverallHeight: 2770 mm; OverallWidth: 1270 mm
Material - Afwerking dagkant binnen: n.v.t.; Afwerking dagkant buiten: n.v.t.; Draaiend deel: n.v.t.; Frame: n.v.t.; Onderdorpel: n.v.t.; Rollaag / latei: n.v.t.; Spouwlat: n.v.t.; Vensterbank: n.v.t.; Ventilatierooster: n.v.t.; Zonwering - behuizing: n.v.t.; Zonwering - isolatie: n.v.t.; Glas: Glas - algemeen
Pset_WindowCommon - FireRating: n.v.t.; SecurityRating: FALSE; ThermalTransmittance: 0; SmokeStop: no; IsExternal: yes
CPset_Phasing - Renovation Phase: Bestaand
Name | In | GlazingAreaFraction
_Merk-x | 4e verdieping V | 3.00445
_Merk-x | 5e verdieping V | 2.96527

# IfcWindow: WI_subvak:glas 2 (24)
Type - ParameterTakesPrecedence: no; Sizeable: no
Material: Glass
Pset_WindowCommon - Reference: glas 2; IsExternal: no
Pset_QuantityTakeOff - Reference: glas 2
CPset_Phasing - Renovation Phase: Nieuw
Material Properties - Glass, ThermalConductivity: 2.3; Glass, SpecificHeatCapacity: 1000 J/kg/K; Glass, MassDensity: 2300 kg/m3; Glass, Embodied Energy: 1.92 (MJ/kg); Glass, Embodied Carbon: 0.198 (kgCO₂/kg); Glass, Name: Glass; Glass, Participates in Collision Detection: yes
Name (WI_subvak:glas 2:...) | In
3024372 | 2e verdieping N
3022440 | 2e verdieping N
3022441 | 2e verdieping N
3024087 | 2e verdieping N
3024088 | 2e verdieping N
3024371 | 2e verdieping N
3028185 | 2e verdieping N
3028186 | 2e verdieping N
2760023 | 5e verdieping V
2553666 | 5e verdieping V
2557584 | 5e verdieping V | Group: Model Group:V-koz-N nieuw:2557585
2760022 | 5e verdieping V
2772199 | 5e verdieping V
2772205 | 5e verdieping V
2772203 | 5e verdieping V
2772167 | 5e verdieping V
2772201 | 5e verdieping V
2772165 | 5e verdieping V
2772169 | 5e verdieping V
2772171 | 5e verdieping V
2997341 | 5e verdieping V
2999316 | 5e verdieping V
2999312 | 5e verdieping V
2557582 | 5e verdieping V | Group: Model Group:V-koz-N nieuw:2557585
